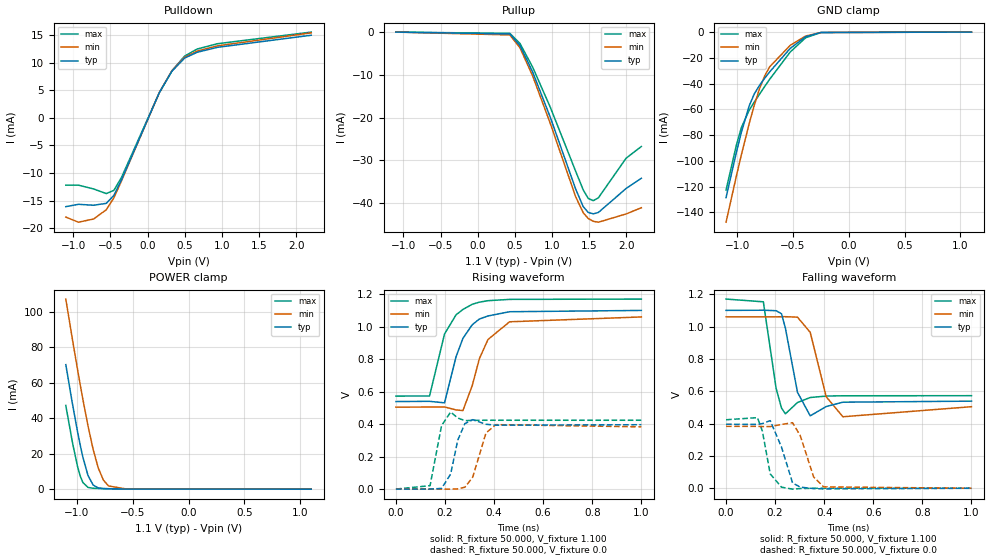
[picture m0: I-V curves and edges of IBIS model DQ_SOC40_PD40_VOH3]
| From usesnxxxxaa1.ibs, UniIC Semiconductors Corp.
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|   Model DQ_SOC40_PD40_VOH3
[Model] DQ_SOC40_PD40_VOH3
Model_type I/O
Polarity   Non-Inverting
Enable   Active-High
Vinl =  0.113V
Vinh =  0.253V
Vmeas =  0.183V
Rref =  50.000
Vref =  0.183V
C_comp   1.110pF   1.087pF   1.118pF
[Model Spec]
Vinh   0.253V   0.247V   0.265V
Vinl   0.113V   0.107V   0.125V
Vmeas   0.183V   NA   NA
Vref   0.183V   NA   NA
Rref   50.000   NA   NA
[Temperature Range]   25.000   0.125k   -40.000
[Voltage Range]   1.100V   1.060V   1.170V
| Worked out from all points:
|   slope of the pulldown table from 0 to 0.165 V, typ, clamps not added: 34.3 ohm
|   GND clamp passes 1 mA (typ) near -0.30 V on its own axis
|   POWER clamp passes 1 mA (typ) near -0.82 V on its own axis
|   rising waveform, R_fixture 50.000, V_fixture 1.100: 20-80 % time 76.9ps typ, 80.7ps min, 76.1ps max; typ from 0.539 V to 1.1 V
|   rising waveform, R_fixture 50.000, V_fixture 0.0: 20-80 % time 34.2ps typ, 42.2ps min, 26.6ps max; typ from 0 V to 0.396 V
|   falling waveform, R_fixture 50.000, V_fixture 1.100: 20-80 % time 39.5ps typ, 51.4ps min, 30.3ps max; typ from 1.1 V to 0.539 V
|   falling waveform, R_fixture 50.000, V_fixture 0.0: 20-80 % time 39.4ps typ, 48.3ps min, 31.2ps max; typ from 0.396 V to 0 V
[Pulldown]
|Voltage   I(typ)   I(min)   I(max)
-1.1V     -16.12mA   -18.01mA   -12.21mA
-930mV    -15.69mA   -18.94mA   -12.21mA
-726mV    -15.86mA   -18.36mA   -12.9mA
-556mV    -15.52mA   -16.68mA   -13.74mA
-454mV    -14.08mA   -14.53mA   -13.16mA
-352mV    -11.27mA   -11.46mA   -10.83mA
158mV     4.629mA    4.648mA    4.586mA
328mV     8.522mA    8.602mA    8.586mA
498mV     10.89mA    11.05mA    11.26mA
668mV     11.95mA    12.17mA    12.54mA
940mV     12.84mA    13.11mA    13.5mA
2.2V      15.04mA    15.47mA    15.61mA
[Pullup]
|Voltage   I(typ)   I(min)   I(max)
-1.1V     1nA        40.29nA    -1.059nA
432mV     -445.9uA   -664.3uA   -301.9uA
568mV     -3.14mA    -3.672mA   -2.666mA
738mV     -9.312mA   -10.23mA   -8.171mA
976mV     -19.93mA   -21.36mA   -17.58mA
1.316V    -36.64mA   -38.44mA   -32.48mA
1.418V    -40.78mA   -42.2mA    -36.86mA
1.486V    -42.14mA   -43.56mA   -38.87mA
1.554V    -42.47mA   -44.22mA   -39.39mA
1.622V    -42.15mA   -44.42mA   -38.73mA
1.996V    -36.53mA   -42.49mA   -29.45mA
2.2V      -34.15mA   -41.04mA   -26.73mA
[GND_clamp]
|Voltage   I(typ)   I(min)   I(max)
-1.1V     -128.5mA   -147.6mA   -122.6mA
-1.008V   -93.62mA   -112mA     -87.95mA
-962mV    -77.6mA    -95.05mA   -73.96mA
-893mV    -57.36mA   -71.21mA   -60.7mA
-847mV    -48.01mA   -56.81mA   -54.36mA
-801mV    -41.47mA   -44.23mA   -48.33mA
-755mV    -36.02mA   -34.19mA   -42.41mA
-709mV    -30.9mA    -26.94mA   -36.63mA
-525mV    -12.67mA   -10.3mA    -15.49mA
-387mV    -3.615mA   -3.065mA   -4.419mA
-249mV    -281uA     -330.6uA   -301.3uA
1.1V      0A         0A         0A
[POWER_clamp]
|Voltage   I(typ)   I(min)   I(max)
-1.1V     70.27mA    107.3mA    47.25mA
-1.039V   47.68mA    83.93mA    25.86mA
-993mV    31.88mA    66.94mA    12.35mA
-970mV    24.65mA    58.72mA    7.262mA
-947mV    18.06mA    50.74mA    3.761mA
-901mV    7.73mA     35.71mA    987.1uA
-855mV    2.348mA    22.46mA    514uA
-809mV    697.3uA    11.94mA    396.5uA
-763mV    321uA      5.097mA    322.7uA
-717mV    213.8uA    1.813mA    258.1uA
-556mV    65.24uA    79.15uA    81.64uA
1.1V      0A         0A         0A
[Ramp]
| variable   typ   min   max
dV/dt_r   0.238/34.205p   0.230/44.058p   0.254/26.879p
dV/dt_f   0.337/40.097p   0.333/51.984p   0.359/30.470p
R_load = 50.000
[Rising Waveform]
R_fixture= 50.000
V_fixture= 1.100
V_fixture_min= 1.060
V_fixture_max= 1.170
|time   V(typ)   V(min)   V(max)
0s        538.9mV    504.5mV    572.5mV
137ps     540.2mV    505.1mV    573.3mV
198ps     531mV      505.7mV    954.9mV
245ps     814.7mV    487.4mV    1.073V
273ps     928.1mV    483.5mV    1.106V
311ps     1.012V     637.3mV    1.138V
340ps     1.047V     802.9mV    1.151V
375ps     1.066V     920.7mV    1.16V
463ps     1.092V     1.03V      1.168V
1ns       1.1V       1.06V      1.17V
[Rising Waveform]
R_fixture= 50.000
V_fixture= 0.0
V_fixture_min= 0.0
V_fixture_max= 0.0
|time   V(typ)   V(min)   V(max)
0s        1.764uV    14.27uV    330.5nV
139ps     -39.12uV   2.016uV    20.91mV
186ps     4.2mV      18.06uV    391.2mV
223ps     92.51mV    -600.2uV   474.3mV
252ps     301.6mV    1.192mV    437.6mV
281ps     403.2mV    11.53mV    421.3mV
313ps     427.4mV    73.36mV    423.1mV
367ps     398.9mV    345.4mV    423.7mV
407ps     393.4mV    396.8mV    423.7mV
1ns       396.3mV    383.1mV    423.7mV
[Falling Waveform]
R_fixture= 50.000
V_fixture= 1.100
V_fixture_min= 1.060
V_fixture_max= 1.170
|time   V(typ)   V(min)   V(max)
0s        1.1V       1.06V      1.17V
152ps     1.101V     1.06V      1.153V
204ps     1.098V     1.06V      618.2mV
226ps     1.079V     1.061V     495.6mV
242ps     989.3mV    1.061V     460.5mV
291ps     593.7mV    1.058V     530.2mV
343ps     447.9mV    964.1mV    561.3mV
408ps     505.4mV    566.4mV    570.2mV
476ps     532.3mV    442.2mV    572mV
1ns       538.8mV    504.5mV    572.5mV
[Falling Waveform]
R_fixture= 50.000
V_fixture= 0.0
V_fixture_min= 0.0
V_fixture_max= 0.0
|time   V(typ)   V(min)   V(max)
0s        396.3mV    383.1mV    423.7mV
128ps     394.7mV    382.7mV    436.7mV
148ps     400.1mV    381.8mV    353.5mV
180ps     418.2mV    381.3mV    88.91mV
226ps     254.5mV    394.9mV    6.791mV
271ps     33.25mV    405.4mV    -5.525mV
302ps     7.059mV    326.9mV    -1.691mV
357ps     -2.039mV   69.62mV    -140.1uV
398ps     -3.841mV   8.587mV    -19.95uV
1ns       1.873uV    15.43uV    -4.527uV
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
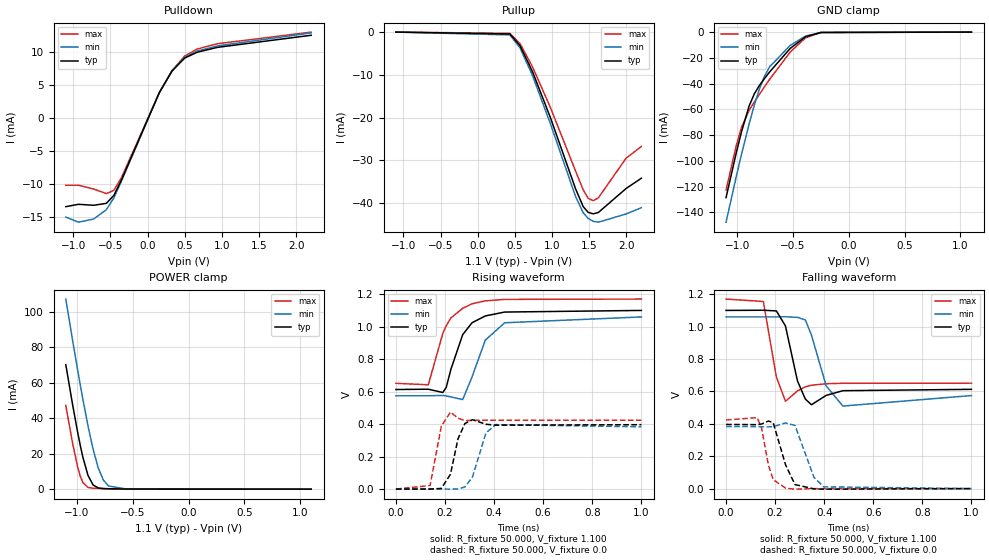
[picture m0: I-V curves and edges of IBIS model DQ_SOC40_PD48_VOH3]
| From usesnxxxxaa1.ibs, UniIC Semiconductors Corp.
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|   Model DQ_SOC40_PD48_VOH3
[Model] DQ_SOC40_PD48_VOH3
Model_type I/O
Polarity   Non-Inverting
Enable   Active-High
Vinl =  0.113V
Vinh =  0.253V
Vmeas =  0.183V
Rref =  50.000
Vref =  0.183V
C_comp   1.110pF   1.087pF   1.118pF
[Model Spec]
Vinh   0.253V   0.247V   0.265V
Vinl   0.113V   0.107V   0.125V
Vmeas   0.183V   NA   NA
Vref   0.183V   NA   NA
Rref   50.000   NA   NA
[Temperature Range]   25.000   0.125k   -40.000
[Voltage Range]   1.100V   1.060V   1.170V
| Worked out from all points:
|   slope of the pulldown table from 0 to 0.165 V, typ, clamps not added: 41.1 ohm
|   GND clamp passes 1 mA (typ) near -0.30 V on its own axis
|   POWER clamp passes 1 mA (typ) near -0.82 V on its own axis
|   rising waveform, R_fixture 50.000, V_fixture 1.100: 20-80 % time 76.2ps typ, 79.4ps min, 75.9ps max; typ from 0.613 V to 1.1 V
|   rising waveform, R_fixture 50.000, V_fixture 0.0: 20-80 % time 34.3ps typ, 43ps min, 26.7ps max; typ from 0 V to 0.396 V
|   falling waveform, R_fixture 50.000, V_fixture 1.100: 20-80 % time 40.3ps typ, 52.9ps min, 30.8ps max; typ from 1.1 V to 0.613 V
|   falling waveform, R_fixture 50.000, V_fixture 0.0: 20-80 % time 41.5ps typ, 49.8ps min, 33.7ps max; typ from 0.396 V to 0 V
[Pulldown]
|Voltage   I(typ)   I(min)   I(max)
-1.1V     -13.43mA   -15.01mA   -10.18mA
-930mV    -13.07mA   -15.78mA   -10.18mA
-726mV    -13.22mA   -15.3mA    -10.75mA
-556mV    -12.93mA   -13.9mA    -11.45mA
-454mV    -11.73mA   -12.11mA   -10.97mA
-352mV    -9.395mA   -9.553mA   -9.028mA
158mV     3.857mA    3.874mA    3.821mA
328mV     7.102mA    7.168mA    7.155mA
498mV     9.071mA    9.207mA    9.38mA
668mV     9.963mA    10.14mA    10.45mA
940mV     10.7mA     10.92mA    11.25mA
2.2V      12.53mA    12.89mA    13.01mA
[Pullup]
|Voltage   I(typ)   I(min)   I(max)
-1.1V     1nA        40.29nA    -1.059nA
432mV     -445.9uA   -664.3uA   -301.9uA
568mV     -3.14mA    -3.672mA   -2.666mA
738mV     -9.312mA   -10.23mA   -8.171mA
976mV     -19.93mA   -21.36mA   -17.58mA
1.316V    -36.64mA   -38.44mA   -32.48mA
1.418V    -40.78mA   -42.2mA    -36.86mA
1.486V    -42.14mA   -43.56mA   -38.87mA
1.554V    -42.47mA   -44.22mA   -39.39mA
1.622V    -42.15mA   -44.42mA   -38.73mA
1.996V    -36.53mA   -42.49mA   -29.45mA
2.2V      -34.15mA   -41.04mA   -26.73mA
[GND_clamp]
|Voltage   I(typ)   I(min)   I(max)
-1.1V     -128.5mA   -147.6mA   -122.6mA
-1.008V   -93.62mA   -112mA     -87.95mA
-962mV    -77.6mA    -95.05mA   -73.96mA
-893mV    -57.36mA   -71.21mA   -60.7mA
-847mV    -48.01mA   -56.81mA   -54.36mA
-801mV    -41.47mA   -44.23mA   -48.33mA
-755mV    -36.02mA   -34.19mA   -42.41mA
-709mV    -30.9mA    -26.94mA   -36.63mA
-525mV    -12.67mA   -10.3mA    -15.49mA
-387mV    -3.615mA   -3.065mA   -4.419mA
-249mV    -281uA     -330.6uA   -301.3uA
1.1V      0A         0A         0A
[POWER_clamp]
|Voltage   I(typ)   I(min)   I(max)
-1.1V     70.27mA    107.3mA    47.25mA
-1.039V   47.68mA    83.93mA    25.86mA
-993mV    31.88mA    66.94mA    12.35mA
-970mV    24.65mA    58.72mA    7.262mA
-947mV    18.06mA    50.74mA    3.761mA
-901mV    7.73mA     35.71mA    987.1uA
-855mV    2.348mA    22.46mA    514uA
-809mV    697.3uA    11.94mA    396.5uA
-763mV    321uA      5.097mA    322.7uA
-717mV    213.8uA    1.813mA    258.1uA
-556mV    65.24uA    79.15uA    81.64uA
1.1V      0A         0A         0A
[Ramp]
| variable   typ   min   max
dV/dt_r   0.238/34.731p   0.230/44.705p   0.254/27.114p
dV/dt_f   0.292/40.843p   0.291/53.764p   0.311/30.978p
R_load = 50.000
[Rising Waveform]
R_fixture= 50.000
V_fixture= 1.100
V_fixture_min= 1.060
V_fixture_max= 1.170
|time   V(typ)   V(min)   V(max)
0s        613mV      574.4mV    651mV
132ps     614.8mV    574.8mV    642.1mV
191ps     594.6mV    576.2mV    958.6mV
205ps     626.4mV    574mV      1.006V
224ps     737.4mV    567.2mV    1.054V
272ps     950.6mV    551mV      1.113V
310ps     1.024V     689.5mV    1.141V
364ps     1.066V     916.8mV    1.159V
443ps     1.09V      1.024V     1.168V
1ns       1.1V       1.06V      1.17V
[Rising Waveform]
R_fixture= 50.000
V_fixture= 0.0
V_fixture_min= 0.0
V_fixture_max= 0.0
|time   V(typ)   V(min)   V(max)
0s        1.965uV    15.9uV     367.9nV
139ps     -74.6uV    22.91uV    21.61mV
185ps     3.776mV    40.2uV     386.4mV
222ps     90.46mV    -769.1uV   473.9mV
253ps     309.5mV    1.09mV     436.6mV
281ps     403.5mV    12.65mV    421.3mV
312ps     427mV      74.25mV    423.1mV
367ps     398.8mV    346.4mV    423.7mV
407ps     393.4mV    396.8mV    423.7mV
1ns       396.3mV    383.1mV    423.7mV
[Falling Waveform]
R_fixture= 50.000
V_fixture= 1.100
V_fixture_min= 1.060
V_fixture_max= 1.170
|time   V(typ)   V(min)   V(max)
0s        1.1V       1.06V      1.17V
152ps     1.101V     1.06V      1.155V
205ps     1.097V     1.06V      688.9mV
242ps     1.004V     1.061V     539.3mV
291ps     664.7mV    1.057V     603.3mV
323ps     553.1mV    1.041V     628.1mV
348ps     517.7mV    947.7mV    637.9mV
408ps     575.5mV    633.9mV    647.5mV
476ps     604.4mV    509.6mV    650.2mV
1ns       612.9mV    574.4mV    651mV
[Falling Waveform]
R_fixture= 50.000
V_fixture= 0.0
V_fixture_min= 0.0
V_fixture_max= 0.0
|time   V(typ)   V(min)   V(max)
0s        396.3mV    383.1mV    423.7mV
127ps     394.7mV    382.7mV    438.3mV
145ps     398.8mV    381.9mV    371.6mV
173ps     417.2mV    381.1mV    142.1mV
192ps     406.9mV    382.4mV    55.76mV
243ps     144.6mV    405.5mV    2.177mV
281ps     24.82mV    389.6mV    -3.372mV
358ps     -1.482mV   70.24mV    -149.3uV
398ps     -3.36mV    10.99mV    -26.6uV
1ns       3.815uV    17.59uV    -4.001uV
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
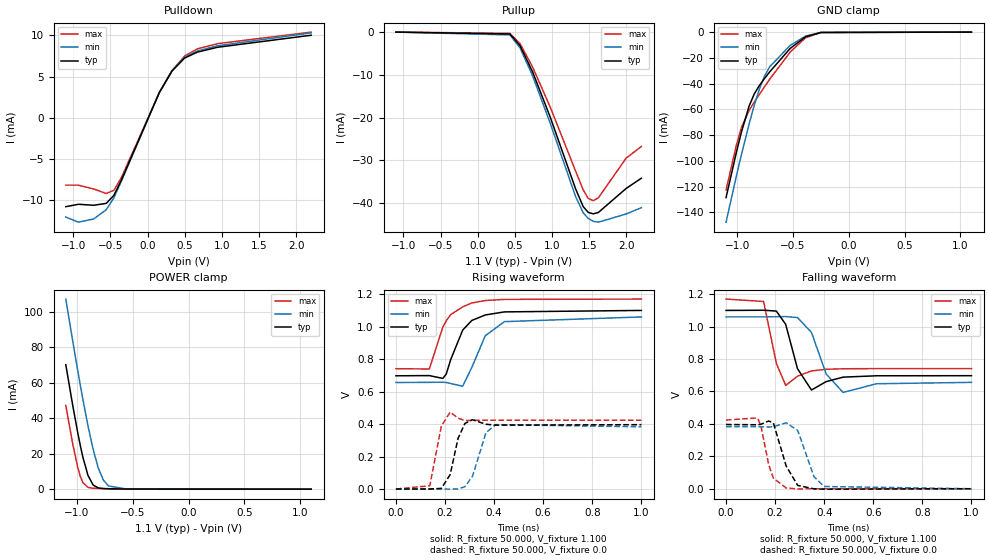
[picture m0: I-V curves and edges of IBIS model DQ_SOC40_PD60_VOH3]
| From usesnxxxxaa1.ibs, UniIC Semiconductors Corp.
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|   Model DQ_SOC40_PD60_VOH3
[Model] DQ_SOC40_PD60_VOH3
Model_type I/O
Polarity   Non-Inverting
Enable   Active-High
Vinl =  0.113V
Vinh =  0.253V
Vmeas =  0.183V
Rref =  50.000
Vref =  0.183V
C_comp   1.110pF   1.087pF   1.118pF
[Model Spec]
Vinh   0.253V   0.247V   0.265V
Vinl   0.113V   0.107V   0.125V
Vmeas   0.183V   NA   NA
Vref   0.183V   NA   NA
Rref   50.000   NA   NA
[Temperature Range]   25.000   0.125k   -40.000
[Voltage Range]   1.100V   1.060V   1.170V
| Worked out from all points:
|   slope of the pulldown table from 0 to 0.165 V, typ, clamps not added: 51.4 ohm
|   GND clamp passes 1 mA (typ) near -0.30 V on its own axis
|   POWER clamp passes 1 mA (typ) near -0.82 V on its own axis
|   rising waveform, R_fixture 50.000, V_fixture 1.100: 20-80 % time 75.4ps typ, 77.9ps min, 75.4ps max; typ from 0.697 V to 1.1 V
|   rising waveform, R_fixture 50.000, V_fixture 0.0: 20-80 % time 34.8ps typ, 43.7ps min, 26.8ps max; typ from 0 V to 0.396 V
|   falling waveform, R_fixture 50.000, V_fixture 1.100: 20-80 % time 40.8ps typ, 54.1ps min, 31.1ps max; typ from 1.1 V to 0.697 V
|   falling waveform, R_fixture 50.000, V_fixture 0.0: 20-80 % time 44ps typ, 51.6ps min, 36.8ps max; typ from 0.396 V to 0 V
[Pulldown]
|Voltage   I(typ)   I(min)   I(max)
-1.1V     -10.75mA   -12.01mA   -8.142mA
-930mV    -10.46mA   -12.63mA   -8.143mA
-726mV    -10.58mA   -12.24mA   -8.599mA
-556mV    -10.35mA   -11.12mA   -9.157mA
-454mV    -9.387mA   -9.688mA   -8.773mA
-352mV    -7.516mA   -7.642mA   -7.222mA
158mV     3.086mA    3.099mA    3.057mA
328mV     5.681mA    5.734mA    5.724mA
498mV     7.257mA    7.365mA    7.504mA
668mV     7.97mA     8.112mA    8.363mA
940mV     8.561mA    8.737mA    9mA
2.2V      10.02mA    10.31mA    10.4mA
[Pullup]
|Voltage   I(typ)   I(min)   I(max)
-1.1V     1nA        40.29nA    -1.059nA
432mV     -445.9uA   -664.3uA   -301.9uA
568mV     -3.14mA    -3.672mA   -2.666mA
738mV     -9.312mA   -10.23mA   -8.171mA
976mV     -19.93mA   -21.36mA   -17.58mA
1.316V    -36.64mA   -38.44mA   -32.48mA
1.418V    -40.78mA   -42.2mA    -36.86mA
1.486V    -42.14mA   -43.56mA   -38.87mA
1.554V    -42.47mA   -44.22mA   -39.39mA
1.622V    -42.15mA   -44.42mA   -38.73mA
1.996V    -36.53mA   -42.49mA   -29.45mA
2.2V      -34.15mA   -41.04mA   -26.73mA
[GND_clamp]
|Voltage   I(typ)   I(min)   I(max)
-1.1V     -128.5mA   -147.6mA   -122.6mA
-1.008V   -93.62mA   -112mA     -87.95mA
-962mV    -77.6mA    -95.05mA   -73.96mA
-893mV    -57.36mA   -71.21mA   -60.7mA
-847mV    -48.01mA   -56.81mA   -54.36mA
-801mV    -41.47mA   -44.23mA   -48.33mA
-755mV    -36.02mA   -34.19mA   -42.41mA
-709mV    -30.9mA    -26.94mA   -36.63mA
-525mV    -12.67mA   -10.3mA    -15.49mA
-387mV    -3.615mA   -3.065mA   -4.419mA
-249mV    -281uA     -330.6uA   -301.3uA
1.1V      0A         0A         0A
[POWER_clamp]
|Voltage   I(typ)   I(min)   I(max)
-1.1V     70.27mA    107.3mA    47.25mA
-1.039V   47.68mA    83.93mA    25.86mA
-993mV    31.88mA    66.94mA    12.35mA
-970mV    24.65mA    58.72mA    7.262mA
-947mV    18.06mA    50.74mA    3.761mA
-901mV    7.73mA     35.71mA    987.1uA
-855mV    2.348mA    22.46mA    514uA
-809mV    697.3uA    11.94mA    396.5uA
-763mV    321uA      5.097mA    322.7uA
-717mV    213.8uA    1.813mA    258.1uA
-556mV    65.24uA    79.15uA    81.64uA
1.1V      0A         0A         0A
[Ramp]
| variable   typ   min   max
dV/dt_r   0.238/35.057p   0.230/45.290p   0.254/27.177p
dV/dt_f   0.242/41.314p   0.242/55.001p   0.257/31.296p
R_load = 50.000
[Rising Waveform]
R_fixture= 50.000
V_fixture= 1.100
V_fixture_min= 1.060
V_fixture_max= 1.170
|time   V(typ)   V(min)   V(max)
0s        697.4mV    656.2mV    741mV
136ps     698.6mV    656.9mV    739.3mV
191ps     681.3mV    657.9mV    996.8mV
205ps     708mV      655.9mV    1.036V
223ps     796.6mV    650mV      1.074V
272ps     978.6mV    633.2mV    1.122V
309ps     1.038V     748.6mV    1.146V
364ps     1.072V     943.9mV    1.161V
442ps     1.091V     1.031V     1.168V
1ns       1.1V       1.06V      1.17V
[Rising Waveform]
R_fixture= 50.000
V_fixture= 0.0
V_fixture_min= 0.0
V_fixture_max= 0.0
|time   V(typ)   V(min)   V(max)
0s        2.218uV    17.94uV    414.7nV
138ps     -92.5uV    41.88uV    20.05mV
185ps     3.849mV    32.41uV    387.4mV
221ps     88.62mV    -949.7uV   473.5mV
253ps     311mV      857.9uV    436.7mV
281ps     403.7mV    14mV       421.3mV
312ps     426.9mV    78.79mV    423.1mV
367ps     398.7mV    347.3mV    423.7mV
407ps     393.4mV    396.7mV    423.7mV
1ns       396.3mV    383.1mV    423.7mV
[Falling Waveform]
R_fixture= 50.000
V_fixture= 1.100
V_fixture_min= 1.060
V_fixture_max= 1.170
|time   V(typ)   V(min)   V(max)
0s        1.1V       1.06V      1.17V
153ps     1.101V     1.06V      1.155V
205ps     1.096V     1.061V     773.3mV
243ps     1.014V     1.062V     637.3mV
291ps     741.1mV    1.056V     693.9mV
348ps     608.9mV    964.3mV    726.8mV
408ps     660.8mV    707.7mV    736.9mV
477ps     688.4mV    594mV      740mV
613ps     696.8mV    647.6mV    741mV
1ns       697.4mV    656.2mV    741mV
[Falling Waveform]
R_fixture= 50.000
V_fixture= 0.0
V_fixture_min= 0.0
V_fixture_max= 0.0
|time   V(typ)   V(min)   V(max)
0s        396.3mV    383.1mV    423.7mV
128ps     394.7mV    382.7mV    436.8mV
142ps     397.5mV    382mV      388.8mV
174ps     418mV      381.1mV    146.9mV
193ps     404.9mV    382.6mV    64.65mV
245ps     140.1mV    406.6mV    4.713mV
292ps     20.39mV    359.8mV    -1.251mV
358ps     -395uV     75.54mV    -107.1uV
399ps     -2.61mV    13.92mV    -21.3uV
1ns       4.28uV     19.82uV    -4.941uV
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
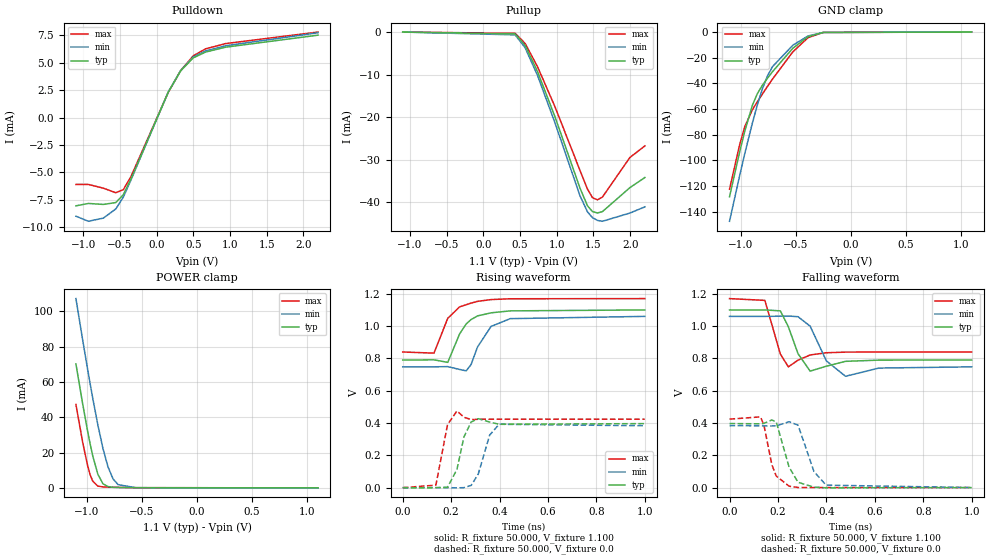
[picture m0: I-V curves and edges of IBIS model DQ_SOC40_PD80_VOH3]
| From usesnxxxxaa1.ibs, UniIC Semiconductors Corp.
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|   Model DQ_SOC40_PD80_VOH3
[Model] DQ_SOC40_PD80_VOH3
Model_type I/O
Polarity   Non-Inverting
Enable   Active-High
Vinl =  0.113V
Vinh =  0.253V
Vmeas =  0.183V
Rref =  50.000
Vref =  0.183V
C_comp   1.110pF   1.087pF   1.118pF
[Model Spec]
Vinh   0.253V   0.247V   0.265V
Vinl   0.113V   0.107V   0.125V
Vmeas   0.183V   NA   NA
Vref   0.183V   NA   NA
Rref   50.000   NA   NA
[Temperature Range]   25.000   0.125k   -40.000
[Voltage Range]   1.100V   1.060V   1.170V
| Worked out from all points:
|   slope of the pulldown table from 0 to 0.165 V, typ, clamps not added: 68.6 ohm
|   GND clamp passes 1 mA (typ) near -0.30 V on its own axis
|   POWER clamp passes 1 mA (typ) near -0.82 V on its own axis
|   rising waveform, R_fixture 50.000, V_fixture 1.100: 20-80 % time 70.4ps typ, 70.3ps min, 71.4ps max; typ from 0.79 V to 1.1 V
|   rising waveform, R_fixture 50.000, V_fixture 0.0: 20-80 % time 34.7ps typ, 44.4ps min, 26.7ps max; typ from 0 V to 0.396 V
|   falling waveform, R_fixture 50.000, V_fixture 1.100: 20-80 % time 43ps typ, 55.7ps min, 32.9ps max; typ from 1.1 V to 0.79 V
|   falling waveform, R_fixture 50.000, V_fixture 0.0: 20-80 % time 44.3ps typ, 50.6ps min, 39.7ps max; typ from 0.396 V to 0 V
[Pulldown]
|Voltage   I(typ)   I(min)   I(max)
-1.1V     -8.06mA    -9.005mA   -6.106mA
-930mV    -7.843mA   -9.47mA    -6.107mA
-726mV    -7.932mA   -9.181mA   -6.449mA
-556mV    -7.761mA   -8.341mA   -6.868mA
-454mV    -7.04mA    -7.266mA   -6.58mA
-352mV    -5.637mA   -5.732mA   -5.417mA
158mV     2.314mA    2.324mA    2.293mA
328mV     4.261mA    4.301mA    4.293mA
498mV     5.443mA    5.524mA    5.628mA
668mV     5.978mA    6.084mA    6.272mA
940mV     6.421mA    6.553mA    6.75mA
2.2V      7.518mA    7.735mA    7.803mA
[Pullup]
|Voltage   I(typ)   I(min)   I(max)
-1.1V     1nA        40.29nA    -1.059nA
432mV     -445.9uA   -664.3uA   -301.9uA
568mV     -3.14mA    -3.672mA   -2.666mA
738mV     -9.312mA   -10.23mA   -8.171mA
976mV     -19.93mA   -21.36mA   -17.58mA
1.316V    -36.64mA   -38.44mA   -32.48mA
1.418V    -40.78mA   -42.2mA    -36.86mA
1.486V    -42.14mA   -43.56mA   -38.87mA
1.554V    -42.47mA   -44.22mA   -39.39mA
1.622V    -42.15mA   -44.42mA   -38.73mA
1.996V    -36.53mA   -42.49mA   -29.45mA
2.2V      -34.15mA   -41.04mA   -26.73mA
[GND_clamp]
|Voltage   I(typ)   I(min)   I(max)
-1.1V     -128.5mA   -147.6mA   -122.6mA
-1.008V   -93.62mA   -112mA     -87.95mA
-962mV    -77.6mA    -95.05mA   -73.96mA
-893mV    -57.36mA   -71.21mA   -60.7mA
-847mV    -48.01mA   -56.81mA   -54.36mA
-801mV    -41.47mA   -44.23mA   -48.33mA
-755mV    -36.02mA   -34.19mA   -42.41mA
-709mV    -30.9mA    -26.94mA   -36.63mA
-525mV    -12.67mA   -10.3mA    -15.49mA
-387mV    -3.615mA   -3.065mA   -4.419mA
-249mV    -281uA     -330.6uA   -301.3uA
1.1V      0A         0A         0A
[POWER_clamp]
|Voltage   I(typ)   I(min)   I(max)
-1.1V     70.27mA    107.3mA    47.25mA
-1.039V   47.68mA    83.93mA    25.86mA
-993mV    31.88mA    66.94mA    12.35mA
-970mV    24.65mA    58.72mA    7.262mA
-947mV    18.06mA    50.74mA    3.761mA
-901mV    7.73mA     35.71mA    987.1uA
-855mV    2.348mA    22.46mA    514uA
-809mV    697.3uA    11.94mA    396.5uA
-763mV    321uA      5.097mA    322.7uA
-717mV    213.8uA    1.813mA    258.1uA
-556mV    65.24uA    79.15uA    81.64uA
1.1V      0A         0A         0A
[Ramp]
| variable   typ   min   max
dV/dt_r   0.238/35.308p   0.230/45.309p   0.254/27.184p
dV/dt_f   0.186/43.222p   0.187/56.773p   0.198/32.941p
R_load = 50.000
[Rising Waveform]
R_fixture= 50.000
V_fixture= 1.100
V_fixture_min= 1.060
V_fixture_max= 1.170
|time   V(typ)   V(min)   V(max)
0s        789.7mV    747.6mV    839.6mV
129ps     791.1mV    747.9mV    832.6mV
186ps     775.4mV    749.1mV    1.048V
235ps     951.6mV    731.5mV    1.119V
262ps     1.013V     723mV      1.132V
282ps     1.04V      761mV      1.142V
309ps     1.063V     870.9mV    1.153V
365ps     1.082V     997.9mV    1.164V
444ps     1.094V     1.046V     1.169V
1ns       1.1V       1.06V      1.17V
[Rising Waveform]
R_fixture= 50.000
V_fixture= 0.0
V_fixture_min= 0.0
V_fixture_max= 0.0
|time   V(typ)   V(min)   V(max)
0s        2.545uV    20.59uV    475.2nV
137ps     21.39uV    51.46uV    15.68mV
185ps     2.658mV    111.2uV    389.7mV
224ps     113.1mV    -1.052mV   474.7mV
253ps     315mV      144.2uV    435.7mV
283ps     406.9mV    14.18mV    421.3mV
312ps     426.9mV    84.52mV    423.1mV
359ps     406.1mV    325.4mV    423.7mV
398ps     392.5mV    392.3mV    423.7mV
1ns       396.3mV    383.1mV    423.7mV
[Falling Waveform]
R_fixture= 50.000
V_fixture= 1.100
V_fixture_min= 1.060
V_fixture_max= 1.170
|time   V(typ)   V(min)   V(max)
0s        1.1V       1.06V      1.17V
146ps     1.1V       1.06V      1.159V
210ps     1.094V     1.061V     826.6mV
243ps     995.8mV    1.062V     747.4mV
283ps     828.9mV    1.058V     789mV
333ps     721mV      999.4mV    821.1mV
400ps     751.5mV    784.5mV    834.7mV
479ps     781.5mV    689.1mV    838.6mV
617ps     789.2mV    739.9mV    839.6mV
1ns       789.7mV    747.5mV    839.6mV
[Falling Waveform]
R_fixture= 50.000
V_fixture= 0.0
V_fixture_min= 0.0
V_fixture_max= 0.0
|time   V(typ)   V(min)   V(max)
0s        396.3mV    383.1mV    423.7mV
128ps     394.7mV    382.7mV    437.7mV
142ps     397.4mV    382mV      387.9mV
175ps     418.7mV    381.1mV    140.6mV
193ps     406.2mV    382.5mV    71.6mV
246ps     126.9mV    407.3mV    8.571mV
283ps     32.66mV    386.9mV    459.6uV
349ps     2.59mV     98.23mV    92.22uV
399ps     -1.679mV   14.9mV     27.07uV
1ns       5.025uV    22.73uV    -5.313uV
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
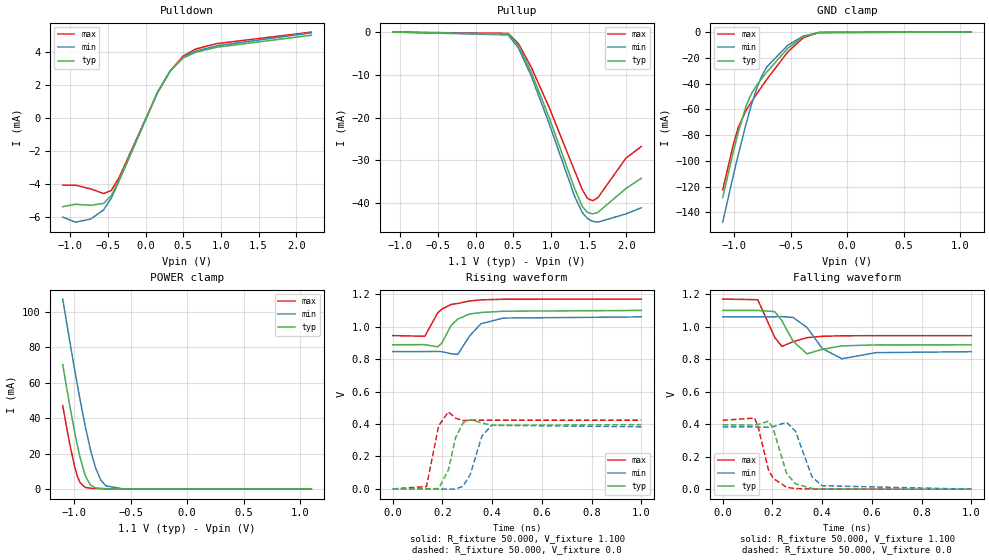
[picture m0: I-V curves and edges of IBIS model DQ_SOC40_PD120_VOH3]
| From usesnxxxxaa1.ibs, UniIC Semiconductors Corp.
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|   Model DQ_SOC40_PD120_VOH3
[Model] DQ_SOC40_PD120_VOH3
Model_type I/O
Polarity   Non-Inverting
Enable   Active-High
Vinl =  0.113V
Vinh =  0.253V
Vmeas =  0.183V
Rref =  50.000
Vref =  0.183V
C_comp   1.110pF   1.087pF   1.118pF
[Model Spec]
Vinh   0.253V   0.247V   0.265V
Vinl   0.113V   0.107V   0.125V
Vmeas   0.183V   NA   NA
Vref   0.183V   NA   NA
Rref   50.000   NA   NA
[Temperature Range]   25.000   0.125k   -40.000
[Voltage Range]   1.100V   1.060V   1.170V
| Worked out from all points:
|   slope of the pulldown table from 0 to 0.165 V, typ, clamps not added: 103 ohm
|   GND clamp passes 1 mA (typ) near -0.30 V on its own axis
|   POWER clamp passes 1 mA (typ) near -0.82 V on its own axis
|   rising waveform, R_fixture 50.000, V_fixture 1.100: 20-80 % time 65.9ps typ, 63.5ps min, 68.5ps max; typ from 0.888 V to 1.1 V
|   rising waveform, R_fixture 50.000, V_fixture 0.0: 20-80 % time 35.2ps typ, 45.4ps min, 26.9ps max; typ from 0 V to 0.396 V
|   falling waveform, R_fixture 50.000, V_fixture 1.100: 20-80 % time 43.5ps typ, 56.9ps min, 33.2ps max; typ from 1.1 V to 0.888 V
|   falling waveform, R_fixture 50.000, V_fixture 0.0: 20-80 % time 49ps typ, 53.8ps min, 46ps max; typ from 0.396 V to 0 V
[Pulldown]
|Voltage   I(typ)   I(min)   I(max)
-1.1V     -5.373mA   -6.003mA   -4.071mA
-930mV    -5.229mA   -6.314mA   -4.072mA
-726mV    -5.288mA   -6.12mA    -4.3mA
-556mV    -5.174mA   -5.561mA   -4.579mA
-454mV    -4.694mA   -4.844mA   -4.386mA
-352mV    -3.758mA   -3.821mA   -3.611mA
158mV     1.543mA    1.549mA    1.529mA
328mV     2.841mA    2.867mA    2.862mA
498mV     3.628mA    3.683mA    3.752mA
668mV     3.985mA    4.056mA    4.181mA
940mV     4.28mA     4.369mA    4.5mA
2.2V      5.012mA    5.157mA    5.202mA
[Pullup]
|Voltage   I(typ)   I(min)   I(max)
-1.1V     1nA        40.29nA    -1.059nA
432mV     -445.9uA   -664.3uA   -301.9uA
568mV     -3.14mA    -3.672mA   -2.666mA
738mV     -9.312mA   -10.23mA   -8.171mA
976mV     -19.93mA   -21.36mA   -17.58mA
1.316V    -36.64mA   -38.44mA   -32.48mA
1.418V    -40.78mA   -42.2mA    -36.86mA
1.486V    -42.14mA   -43.56mA   -38.87mA
1.554V    -42.47mA   -44.22mA   -39.39mA
1.622V    -42.15mA   -44.42mA   -38.73mA
1.996V    -36.53mA   -42.49mA   -29.45mA
2.2V      -34.15mA   -41.04mA   -26.73mA
[GND_clamp]
|Voltage   I(typ)   I(min)   I(max)
-1.1V     -128.5mA   -147.6mA   -122.6mA
-1.008V   -93.62mA   -112mA     -87.95mA
-962mV    -77.6mA    -95.05mA   -73.96mA
-893mV    -57.36mA   -71.21mA   -60.7mA
-847mV    -48.01mA   -56.81mA   -54.36mA
-801mV    -41.47mA   -44.23mA   -48.33mA
-755mV    -36.02mA   -34.19mA   -42.41mA
-709mV    -30.9mA    -26.94mA   -36.63mA
-525mV    -12.67mA   -10.3mA    -15.49mA
-387mV    -3.615mA   -3.065mA   -4.419mA
-249mV    -281uA     -330.6uA   -301.3uA
1.1V      0A         0A         0A
[POWER_clamp]
|Voltage   I(typ)   I(min)   I(max)
-1.1V     70.27mA    107.3mA    47.25mA
-1.039V   47.68mA    83.93mA    25.86mA
-993mV    31.88mA    66.94mA    12.35mA
-970mV    24.65mA    58.72mA    7.262mA
-947mV    18.06mA    50.74mA    3.761mA
-901mV    7.73mA     35.71mA    987.1uA
-855mV    2.348mA    22.46mA    514uA
-809mV    697.3uA    11.94mA    396.5uA
-763mV    321uA      5.097mA    322.7uA
-717mV    213.8uA    1.813mA    258.1uA
-556mV    65.24uA    79.15uA    81.64uA
1.1V      0A         0A         0A
[Ramp]
| variable   typ   min   max
dV/dt_r   0.238/36.048p   0.230/46.073p   0.254/27.536p
dV/dt_f   0.127/43.850p   0.128/57.564p   0.135/33.292p
R_load = 50.000
[Rising Waveform]
R_fixture= 50.000
V_fixture= 1.100
V_fixture_min= 1.060
V_fixture_max= 1.170
|time   V(typ)   V(min)   V(max)
0s        888.3mV    846.1mV    944.8mV
129ps     889.2mV    846.4mV    940.9mV
181ps     875.6mV    847.3mV    1.085V
198ps     899.6mV    845.6mV    1.108V
235ps     1.008V     833.3mV    1.137V
262ps     1.047V     829.3mV    1.143V
309ps     1.078V     942.5mV    1.158V
355ps     1.087V     1.018V     1.165V
445ps     1.095V     1.053V     1.169V
1ns       1.1V       1.06V      1.17V
[Rising Waveform]
R_fixture= 50.000
V_fixture= 0.0
V_fixture_min= 0.0
V_fixture_max= 0.0
|time   V(typ)   V(min)   V(max)
0s        2.986uV    24.15uV    556.4nV
136ps     4.467uV    74.9uV     14.95mV
185ps     2.796mV    109.4uV    390.1mV
224ps     117.6mV    -1.347mV   474.7mV
253ps     316.2mV    -263.4uV   435.8mV
283ps     406.9mV    16.24mV    421.3mV
312ps     426.9mV    89.99mV    423.1mV
359ps     406mV      326.3mV    423.7mV
398ps     392.5mV    392.2mV    423.7mV
1ns       396.3mV    383.1mV    423.7mV
[Falling Waveform]
R_fixture= 50.000
V_fixture= 1.100
V_fixture_min= 1.060
V_fixture_max= 1.170
|time   V(typ)   V(min)   V(max)
0s        1.1V       1.06V      1.17V
141ps     1.1V       1.06V      1.166V
209ps     1.093V     1.061V     935mV
238ps     1.037V     1.062V     878.4mV
283ps     910.7mV    1.057V     907.6mV
339ps     833mV      995.2mV    932.3mV
400ps     860.3mV    866.6mV    940.9mV
479ps     882mV      802.6mV    944mV
617ps     887.8mV    840.3mV    944.7mV
1ns       888.3mV    846.1mV    944.8mV
[Falling Waveform]
R_fixture= 50.000
V_fixture= 0.0
V_fixture_min= 0.0
V_fixture_max= 0.0
|time   V(typ)   V(min)   V(max)
0s        396.3mV    383.1mV    423.7mV
128ps     394.7mV    382.7mV    437.6mV
142ps     397.5mV    382mV      386.8mV
184ps     418.3mV    381.4mV    119.4mV
203ps     373.4mV    384.9mV    66.53mV
257ps     96.94mV    411.4mV    11.35mV
293ps     32.82mV    355.9mV    3.762mV
359ps     4.085mV    76.31mV    736.7uV
399ps     96.03uV    21.21mV    271.4uV
1ns       62.55nV    26.72uV    -6.107uV
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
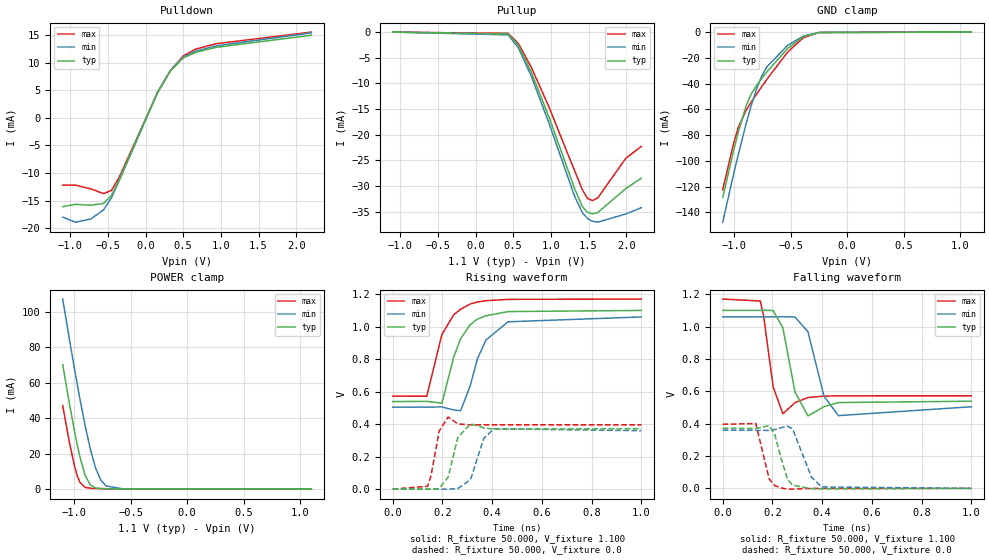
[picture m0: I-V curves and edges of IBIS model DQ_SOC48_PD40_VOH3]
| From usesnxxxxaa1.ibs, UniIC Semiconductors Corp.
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|   Model DQ_SOC48_PD40_VOH3
[Model] DQ_SOC48_PD40_VOH3
Model_type I/O
Polarity   Non-Inverting
Enable   Active-High
Vinl =  0.113V
Vinh =  0.253V
Vmeas =  0.183V
Rref =  50.000
Vref =  0.183V
C_comp   1.110pF   1.087pF   1.118pF
[Model Spec]
Vinh   0.253V   0.247V   0.265V
Vinl   0.113V   0.107V   0.125V
Vmeas   0.183V   NA   NA
Vref   0.183V   NA   NA
Rref   50.000   NA   NA
[Temperature Range]   25.000   0.125k   -40.000
[Voltage Range]   1.100V   1.060V   1.170V
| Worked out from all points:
|   slope of the pulldown table from 0 to 0.165 V, typ, clamps not added: 34.3 ohm
|   GND clamp passes 1 mA (typ) near -0.30 V on its own axis
|   POWER clamp passes 1 mA (typ) near -0.82 V on its own axis
|   rising waveform, R_fixture 50.000, V_fixture 1.100: 20-80 % time 77ps typ, 81.1ps min, 76.1ps max; typ from 0.539 V to 1.1 V
|   rising waveform, R_fixture 50.000, V_fixture 0.0: 20-80 % time 34.7ps typ, 43.2ps min, 27ps max; typ from 0 V to 0.372 V
|   falling waveform, R_fixture 50.000, V_fixture 1.100: 20-80 % time 39.3ps typ, 51ps min, 30.3ps max; typ from 1.1 V to 0.539 V
|   falling waveform, R_fixture 50.000, V_fixture 0.0: 20-80 % time 38.9ps typ, 47.7ps min, 30.9ps max; typ from 0.372 V to 0 V
[Pulldown]
|Voltage   I(typ)   I(min)   I(max)
-1.1V     -16.12mA   -18.01mA   -12.21mA
-930mV    -15.69mA   -18.94mA   -12.21mA
-726mV    -15.86mA   -18.36mA   -12.9mA
-556mV    -15.52mA   -16.68mA   -13.74mA
-454mV    -14.08mA   -14.53mA   -13.16mA
-352mV    -11.27mA   -11.46mA   -10.83mA
158mV     4.629mA    4.648mA    4.586mA
328mV     8.522mA    8.602mA    8.586mA
498mV     10.89mA    11.05mA    11.26mA
668mV     11.95mA    12.17mA    12.54mA
940mV     12.84mA    13.11mA    13.5mA
2.2V      15.04mA    15.47mA    15.61mA
[Pullup]
|Voltage   I(typ)   I(min)   I(max)
-1.1V     1nA        30.06nA    -1.059nA
432mV     -371.6uA   -553.6uA   -251.6uA
568mV     -2.617mA   -3.06mA    -2.222mA
738mV     -7.76mA    -8.529mA   -6.809mA
976mV     -16.61mA   -17.8mA    -14.65mA
1.316V    -30.54mA   -32.03mA   -27.06mA
1.418V    -33.98mA   -35.17mA   -30.72mA
1.486V    -35.12mA   -36.3mA    -32.39mA
1.554V    -35.39mA   -36.85mA   -32.82mA
1.622V    -35.13mA   -37.02mA   -32.28mA
1.996V    -30.44mA   -35.41mA   -24.54mA
2.2V      -28.46mA   -34.2mA    -22.27mA
[GND_clamp]
|Voltage   I(typ)   I(min)   I(max)
-1.1V     -128.5mA   -147.6mA   -122.6mA
-1.008V   -93.62mA   -112mA     -87.95mA
-962mV    -77.6mA    -95.05mA   -73.96mA
-893mV    -57.36mA   -71.21mA   -60.7mA
-847mV    -48.01mA   -56.81mA   -54.36mA
-801mV    -41.47mA   -44.23mA   -48.33mA
-755mV    -36.02mA   -34.19mA   -42.41mA
-709mV    -30.9mA    -26.94mA   -36.63mA
-525mV    -12.67mA   -10.3mA    -15.49mA
-387mV    -3.615mA   -3.065mA   -4.419mA
-249mV    -281uA     -330.6uA   -301.3uA
1.1V      0A         0A         0A
[POWER_clamp]
|Voltage   I(typ)   I(min)   I(max)
-1.1V     70.27mA    107.3mA    47.25mA
-1.039V   47.68mA    83.93mA    25.86mA
-993mV    31.88mA    66.94mA    12.35mA
-970mV    24.65mA    58.72mA    7.262mA
-947mV    18.06mA    50.74mA    3.761mA
-901mV    7.73mA     35.71mA    987.1uA
-855mV    2.348mA    22.46mA    514uA
-809mV    697.3uA    11.94mA    396.5uA
-763mV    321uA      5.097mA    322.7uA
-717mV    213.8uA    1.813mA    258.1uA
-556mV    65.24uA    79.15uA    81.64uA
1.1V      0A         0A         0A
[Ramp]
| variable   typ   min   max
dV/dt_r   0.223/34.718p   0.216/44.081p   0.238/27.242p
dV/dt_f   0.337/39.960p   0.333/51.746p   0.359/30.253p
R_load = 50.000
[Rising Waveform]
R_fixture= 50.000
V_fixture= 1.100
V_fixture_min= 1.060
V_fixture_max= 1.170
|time   V(typ)   V(min)   V(max)
0s        538.9mV    504.5mV    572.5mV
137ps     540.2mV    505.1mV    571.6mV
198ps     529.1mV    505.7mV    952.3mV
245ps     810.4mV    487.6mV    1.073V
273ps     925.5mV    482.4mV    1.107V
311ps     1.011V     632.5mV    1.139V
341ps     1.047V     802.7mV    1.152V
375ps     1.067V     917.9mV    1.16V
464ps     1.093V     1.03V      1.168V
1ns       1.1V       1.06V      1.17V
[Rising Waveform]
R_fixture= 50.000
V_fixture= 0.0
V_fixture_min= 0.0
V_fixture_max= 0.0
|time   V(typ)   V(min)   V(max)
0s        1.764uV    14.27uV    330.5nV
140ps     2.535uV    -6.891uV   17.52mV
154ps     -246.8uV   32.03uV    81.06mV
187ps     3.627mV    6.249uV    357.3mV
223ps     73.95mV    -340.5uV   443.9mV
262ps     318.5mV    3.075mV    401.2mV
313ps     401.6mV    58.72mV    395.6mV
366ps     376.9mV    311.1mV    396mV
407ps     369.2mV    371.5mV    396mV
1ns       371.6mV    359.6mV    396mV
[Falling Waveform]
R_fixture= 50.000
V_fixture= 1.100
V_fixture_min= 1.060
V_fixture_max= 1.170
|time   V(typ)   V(min)   V(max)
0s        1.1V       1.06V      1.17V
151ps     1.1V       1.06V      1.158V
164ps     1.101V     1.06V      1.071V
203ps     1.099V     1.06V      627.2mV
242ps     992.1mV    1.061V     461.2mV
291ps     594.8mV    1.059V     530.2mV
343ps     448.1mV    967.5mV    561.3mV
407ps     504.7mV    571.5mV    570.1mV
465ps     530.4mV    449.7mV    571.9mV
1ns       538.8mV    504.5mV    572.5mV
[Falling Waveform]
R_fixture= 50.000
V_fixture= 0.0
V_fixture_min= 0.0
V_fixture_max= 0.0
|time   V(typ)   V(min)   V(max)
0s        371.6mV    359.6mV    396mV
133ps     370.7mV    359mV      400.9mV
187ps     387.8mV    358.4mV    57.34mV
210ps     330mV      363.2mV    16.39mV
236ps     179.8mV    375.2mV    2.494mV
261ps     55.66mV    384.7mV    -4.804mV
281ps     19.55mV    367.9mV    -4.332mV
357ps     -2.041mV   69.11mV    -138.1uV
398ps     -3.843mV   8.999mV    -16.5uV
1ns       2.392uV    16.45uV    -1.611uV
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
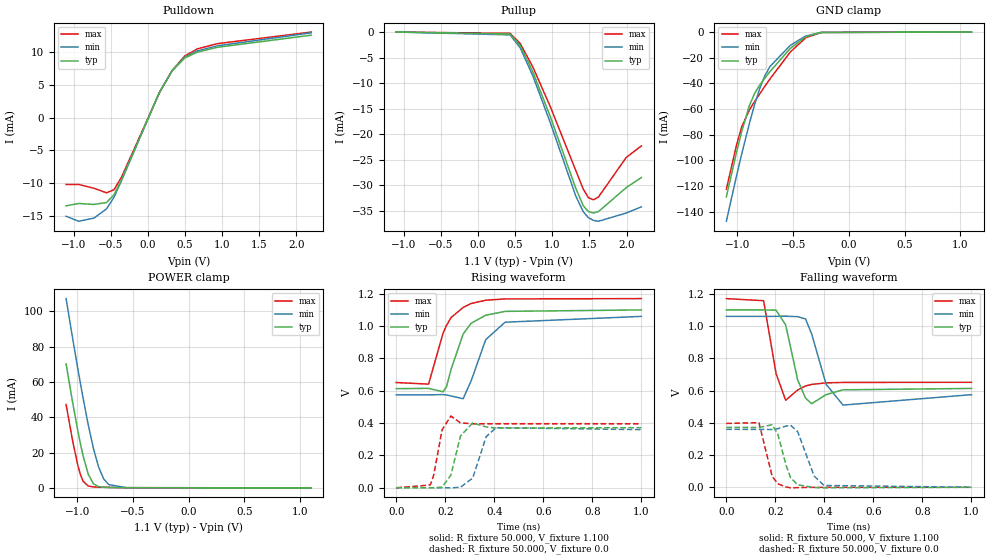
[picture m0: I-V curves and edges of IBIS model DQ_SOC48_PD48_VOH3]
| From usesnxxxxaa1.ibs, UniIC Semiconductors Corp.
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|   Model DQ_SOC48_PD48_VOH3
[Model] DQ_SOC48_PD48_VOH3
Model_type I/O
Polarity   Non-Inverting
Enable   Active-High
Vinl =  0.113V
Vinh =  0.253V
Vmeas =  0.183V
Rref =  50.000
Vref =  0.183V
C_comp   1.110pF   1.087pF   1.118pF
[Model Spec]
Vinh   0.253V   0.247V   0.265V
Vinl   0.113V   0.107V   0.125V
Vmeas   0.183V   NA   NA
Vref   0.183V   NA   NA
Rref   50.000   NA   NA
[Temperature Range]   25.000   0.125k   -40.000
[Voltage Range]   1.100V   1.060V   1.170V
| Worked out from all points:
|   slope of the pulldown table from 0 to 0.165 V, typ, clamps not added: 41.1 ohm
|   GND clamp passes 1 mA (typ) near -0.30 V on its own axis
|   POWER clamp passes 1 mA (typ) near -0.82 V on its own axis
|   rising waveform, R_fixture 50.000, V_fixture 1.100: 20-80 % time 76.5ps typ, 80ps min, 75.9ps max; typ from 0.613 V to 1.1 V
|   rising waveform, R_fixture 50.000, V_fixture 0.0: 20-80 % time 35.2ps typ, 43.9ps min, 26.9ps max; typ from 0 V to 0.372 V
|   falling waveform, R_fixture 50.000, V_fixture 1.100: 20-80 % time 40.1ps typ, 52.8ps min, 30.8ps max; typ from 1.1 V to 0.613 V
|   falling waveform, R_fixture 50.000, V_fixture 0.0: 20-80 % time 41.1ps typ, 49.3ps min, 33.4ps max; typ from 0.372 V to 0 V
[Pulldown]
|Voltage   I(typ)   I(min)   I(max)
-1.1V     -13.43mA   -15.01mA   -10.18mA
-930mV    -13.07mA   -15.78mA   -10.18mA
-726mV    -13.22mA   -15.3mA    -10.75mA
-556mV    -12.93mA   -13.9mA    -11.45mA
-454mV    -11.73mA   -12.11mA   -10.97mA
-352mV    -9.395mA   -9.553mA   -9.028mA
158mV     3.857mA    3.874mA    3.821mA
328mV     7.102mA    7.168mA    7.155mA
498mV     9.071mA    9.207mA    9.38mA
668mV     9.963mA    10.14mA    10.45mA
940mV     10.7mA     10.92mA    11.25mA
2.2V      12.53mA    12.89mA    13.01mA
[Pullup]
|Voltage   I(typ)   I(min)   I(max)
-1.1V     1nA        30.06nA    -1.059nA
432mV     -371.6uA   -553.6uA   -251.6uA
568mV     -2.617mA   -3.06mA    -2.222mA
738mV     -7.76mA    -8.529mA   -6.809mA
976mV     -16.61mA   -17.8mA    -14.65mA
1.316V    -30.54mA   -32.03mA   -27.06mA
1.418V    -33.98mA   -35.17mA   -30.72mA
1.486V    -35.12mA   -36.3mA    -32.39mA
1.554V    -35.39mA   -36.85mA   -32.82mA
1.622V    -35.13mA   -37.02mA   -32.28mA
1.996V    -30.44mA   -35.41mA   -24.54mA
2.2V      -28.46mA   -34.2mA    -22.27mA
[GND_clamp]
|Voltage   I(typ)   I(min)   I(max)
-1.1V     -128.5mA   -147.6mA   -122.6mA
-1.008V   -93.62mA   -112mA     -87.95mA
-962mV    -77.6mA    -95.05mA   -73.96mA
-893mV    -57.36mA   -71.21mA   -60.7mA
-847mV    -48.01mA   -56.81mA   -54.36mA
-801mV    -41.47mA   -44.23mA   -48.33mA
-755mV    -36.02mA   -34.19mA   -42.41mA
-709mV    -30.9mA    -26.94mA   -36.63mA
-525mV    -12.67mA   -10.3mA    -15.49mA
-387mV    -3.615mA   -3.065mA   -4.419mA
-249mV    -281uA     -330.6uA   -301.3uA
1.1V      0A         0A         0A
[POWER_clamp]
|Voltage   I(typ)   I(min)   I(max)
-1.1V     70.27mA    107.3mA    47.25mA
-1.039V   47.68mA    83.93mA    25.86mA
-993mV    31.88mA    66.94mA    12.35mA
-970mV    24.65mA    58.72mA    7.262mA
-947mV    18.06mA    50.74mA    3.761mA
-901mV    7.73mA     35.71mA    987.1uA
-855mV    2.348mA    22.46mA    514uA
-809mV    697.3uA    11.94mA    396.5uA
-763mV    321uA      5.097mA    322.7uA
-717mV    213.8uA    1.813mA    258.1uA
-556mV    65.24uA    79.15uA    81.64uA
1.1V      0A         0A         0A
[Ramp]
| variable   typ   min   max
dV/dt_r   0.223/35.405p   0.216/44.709p   0.238/27.565p
dV/dt_f   0.292/40.658p   0.291/53.435p   0.311/30.807p
R_load = 50.000
[Rising Waveform]
R_fixture= 50.000
V_fixture= 1.100
V_fixture_min= 1.060
V_fixture_max= 1.170
|time   V(typ)   V(min)   V(max)
0s        613mV      574.4mV    651mV
132ps     614.8mV    574.8mV    641mV
191ps     593.6mV    576.2mV    955.8mV
205ps     623.8mV    574.1mV    1.004V
224ps     733.3mV    567.5mV    1.053V
273ps     950.5mV    550.6mV    1.115V
306ps     1.018V     662.6mV    1.14V
365ps     1.067V     915.9mV    1.16V
444ps     1.091V     1.024V     1.168V
1ns       1.1V       1.06V      1.17V
[Rising Waveform]
R_fixture= 50.000
V_fixture= 0.0
V_fixture_min= 0.0
V_fixture_max= 0.0
|time   V(typ)   V(min)   V(max)
0s        1.965uV    15.9uV     367.9nV
139ps     -25.47uV   11.23uV    16.81mV
153ps     -356uV     50.82uV    77.23mV
187ps     3.739mV    7.855uV    358mV
223ps     77.94mV    -516.4uV   443.9mV
262ps     319.6mV    2.977mV    401.2mV
312ps     401.1mV    59.98mV    395.6mV
367ps     376.1mV    315.6mV    396mV
407ps     369.2mV    371.5mV    396mV
1ns       371.6mV    359.6mV    396mV
[Falling Waveform]
R_fixture= 50.000
V_fixture= 1.100
V_fixture_min= 1.060
V_fixture_max= 1.170
|time   V(typ)   V(min)   V(max)
0s        1.1V       1.06V      1.17V
152ps     1.1V       1.06V      1.157V
203ps     1.098V     1.06V      704.3mV
242ps     1.007V     1.061V     539.5mV
291ps     665.9mV    1.058V     603.4mV
323ps     553.5mV    1.044V     628.2mV
348ps     518mV      951.2mV    637.9mV
407ps     574.7mV    638.7mV    647.5mV
476ps     604.4mV    509.8mV    650.2mV
1ns       612.9mV    574.4mV    651mV
[Falling Waveform]
R_fixture= 50.000
V_fixture= 0.0
V_fixture_min= 0.0
V_fixture_max= 0.0
|time   V(typ)   V(min)   V(max)
0s        371.6mV    359.6mV    396mV
133ps     370.7mV    359mV      400.5mV
187ps     387.7mV    358.4mV    67.55mV
210ps     328.8mV    363.3mV    22.16mV
244ps     135.3mV    379.7mV    1.605mV
262ps     59.77mV    384.9mV    -3.396mV
291ps     15.61mV    345.2mV    -2.323mV
358ps     -1.5mV     69.85mV    -148.7uV
398ps     -3.368mV   11.42mV    -23.61uV
1ns       4.349uV    18.74uV    -1.582uV
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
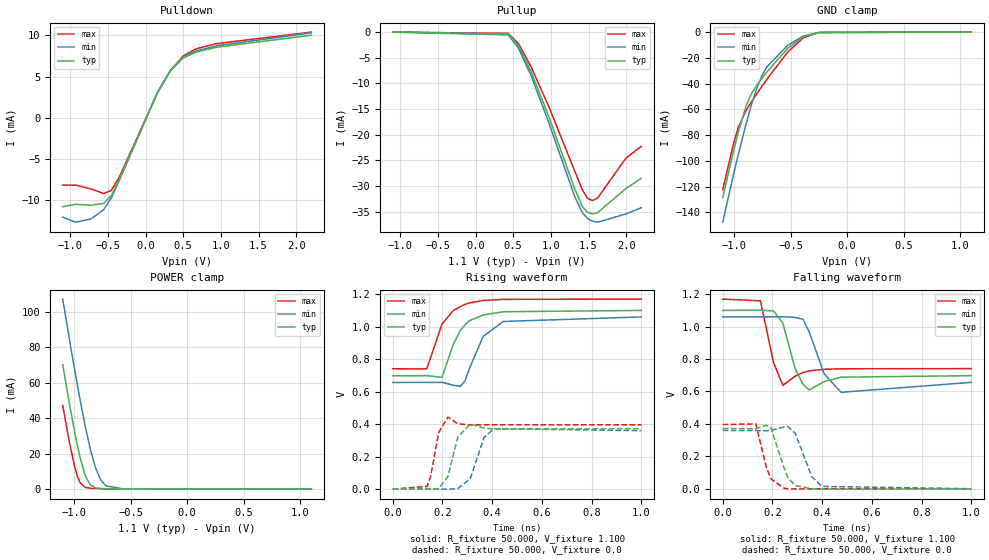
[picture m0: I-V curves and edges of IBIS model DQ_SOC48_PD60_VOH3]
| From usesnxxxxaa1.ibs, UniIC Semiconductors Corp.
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|   Model DQ_SOC48_PD60_VOH3
[Model] DQ_SOC48_PD60_VOH3
Model_type I/O
Polarity   Non-Inverting
Enable   Active-High
Vinl =  0.113V
Vinh =  0.253V
Vmeas =  0.183V
Rref =  50.000
Vref =  0.183V
C_comp   1.110pF   1.087pF   1.118pF
[Model Spec]
Vinh   0.253V   0.247V   0.265V
Vinl   0.113V   0.107V   0.125V
Vmeas   0.183V   NA   NA
Vref   0.183V   NA   NA
Rref   50.000   NA   NA
[Temperature Range]   25.000   0.125k   -40.000
[Voltage Range]   1.100V   1.060V   1.170V
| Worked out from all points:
|   slope of the pulldown table from 0 to 0.165 V, typ, clamps not added: 51.4 ohm
|   GND clamp passes 1 mA (typ) near -0.30 V on its own axis
|   POWER clamp passes 1 mA (typ) near -0.82 V on its own axis
|   rising waveform, R_fixture 50.000, V_fixture 1.100: 20-80 % time 75.6ps typ, 78.6ps min, 75.5ps max; typ from 0.697 V to 1.1 V
|   rising waveform, R_fixture 50.000, V_fixture 0.0: 20-80 % time 35.7ps typ, 44.5ps min, 27.3ps max; typ from 0 V to 0.372 V
|   falling waveform, R_fixture 50.000, V_fixture 1.100: 20-80 % time 40.6ps typ, 53.9ps min, 31.1ps max; typ from 1.1 V to 0.697 V
|   falling waveform, R_fixture 50.000, V_fixture 0.0: 20-80 % time 43.7ps typ, 51.6ps min, 36.4ps max; typ from 0.372 V to 0 V
[Pulldown]
|Voltage   I(typ)   I(min)   I(max)
-1.1V     -10.75mA   -12.01mA   -8.142mA
-930mV    -10.46mA   -12.63mA   -8.143mA
-726mV    -10.58mA   -12.24mA   -8.599mA
-556mV    -10.35mA   -11.12mA   -9.157mA
-454mV    -9.387mA   -9.688mA   -8.773mA
-352mV    -7.516mA   -7.642mA   -7.222mA
158mV     3.086mA    3.099mA    3.057mA
328mV     5.681mA    5.734mA    5.724mA
498mV     7.257mA    7.365mA    7.504mA
668mV     7.97mA     8.112mA    8.363mA
940mV     8.561mA    8.737mA    9mA
2.2V      10.02mA    10.31mA    10.4mA
[Pullup]
|Voltage   I(typ)   I(min)   I(max)
-1.1V     1nA        30.06nA    -1.059nA
432mV     -371.6uA   -553.6uA   -251.6uA
568mV     -2.617mA   -3.06mA    -2.222mA
738mV     -7.76mA    -8.529mA   -6.809mA
976mV     -16.61mA   -17.8mA    -14.65mA
1.316V    -30.54mA   -32.03mA   -27.06mA
1.418V    -33.98mA   -35.17mA   -30.72mA
1.486V    -35.12mA   -36.3mA    -32.39mA
1.554V    -35.39mA   -36.85mA   -32.82mA
1.622V    -35.13mA   -37.02mA   -32.28mA
1.996V    -30.44mA   -35.41mA   -24.54mA
2.2V      -28.46mA   -34.2mA    -22.27mA
[GND_clamp]
|Voltage   I(typ)   I(min)   I(max)
-1.1V     -128.5mA   -147.6mA   -122.6mA
-1.008V   -93.62mA   -112mA     -87.95mA
-962mV    -77.6mA    -95.05mA   -73.96mA
-893mV    -57.36mA   -71.21mA   -60.7mA
-847mV    -48.01mA   -56.81mA   -54.36mA
-801mV    -41.47mA   -44.23mA   -48.33mA
-755mV    -36.02mA   -34.19mA   -42.41mA
-709mV    -30.9mA    -26.94mA   -36.63mA
-525mV    -12.67mA   -10.3mA    -15.49mA
-387mV    -3.615mA   -3.065mA   -4.419mA
-249mV    -281uA     -330.6uA   -301.3uA
1.1V      0A         0A         0A
[POWER_clamp]
|Voltage   I(typ)   I(min)   I(max)
-1.1V     70.27mA    107.3mA    47.25mA
-1.039V   47.68mA    83.93mA    25.86mA
-993mV    31.88mA    66.94mA    12.35mA
-970mV    24.65mA    58.72mA    7.262mA
-947mV    18.06mA    50.74mA    3.761mA
-901mV    7.73mA     35.71mA    987.1uA
-855mV    2.348mA    22.46mA    514uA
-809mV    697.3uA    11.94mA    396.5uA
-763mV    321uA      5.097mA    322.7uA
-717mV    213.8uA    1.813mA    258.1uA
-556mV    65.24uA    79.15uA    81.64uA
1.1V      0A         0A         0A
[Ramp]
| variable   typ   min   max
dV/dt_r   0.223/35.869p   0.216/45.259p   0.238/27.612p
dV/dt_f   0.242/41.080p   0.242/54.520p   0.257/31.198p
R_load = 50.000
[Rising Waveform]
R_fixture= 50.000
V_fixture= 1.100
V_fixture_min= 1.060
V_fixture_max= 1.170
|time   V(typ)   V(min)   V(max)
0s        697.4mV    656.2mV    741mV
137ps     698.5mV    656.9mV    739.5mV
198ps     687.9mV    657.2mV    1.015V
244ps     892.2mV    639.3mV    1.1V
272ps     976mV      632.2mV    1.123V
291ps     1.012V     666.8mV    1.137V
309ps     1.037V     744.3mV    1.146V
364ps     1.072V     940.6mV    1.161V
445ps     1.092V     1.032V     1.168V
1ns       1.1V       1.06V      1.17V
[Rising Waveform]
R_fixture= 50.000
V_fixture= 0.0
V_fixture_min= 0.0
V_fixture_max= 0.0
|time   V(typ)   V(min)   V(max)
0s        2.218uV    17.94uV    414.7nV
138ps     -53.57uV   30.54uV    15.83mV
152ps     -464.7uV   69.02uV    73.91mV
185ps     3.048mV    19.91uV    348.5mV
222ps     76.81mV    -701.6uV   443.2mV
262ps     320.6mV    2.968mV    401.4mV
312ps     401.1mV    64.3mV     395.6mV
367ps     376.1mV    316.7mV    396mV
407ps     369.2mV    371.5mV    396mV
1ns       371.6mV    359.6mV    396mV
[Falling Waveform]
R_fixture= 50.000
V_fixture= 1.100
V_fixture_min= 1.060
V_fixture_max= 1.170
|time   V(typ)   V(min)   V(max)
0s        1.1V       1.06V      1.17V
152ps     1.101V     1.06V      1.159V
204ps     1.097V     1.06V      780.3mV
242ps     1.022V     1.061V     637.8mV
291ps     742.3mV    1.057V     694.1mV
323ps     643.6mV    1.045V     717.3mV
348ps     609.3mV    967.8mV    726.8mV
408ps     660.9mV    709.2mV    736.9mV
476ps     688.3mV    594.8mV    740mV
1ns       697.4mV    656.2mV    741mV
[Falling Waveform]
R_fixture= 50.000
V_fixture= 0.0
V_fixture_min= 0.0
V_fixture_max= 0.0
|time   V(typ)   V(min)   V(max)
0s        371.6mV    359.6mV    396mV
133ps     370.7mV    359mV      400mV
175ps     390.9mV    357.8mV    135.9mV
193ps     380.9mV    359.1mV    62.15mV
244ps     140.9mV    379.8mV    4.873mV
262ps     67.77mV    385mV      -921.1uV
292ps     19.99mV    341.8mV    -1.303mV
358ps     -430.8uV   74.92mV    -109.7uV
399ps     -2.623mV   14.36mV    -18.87uV
1ns       4.993uV    21.11uV    -2.174uV
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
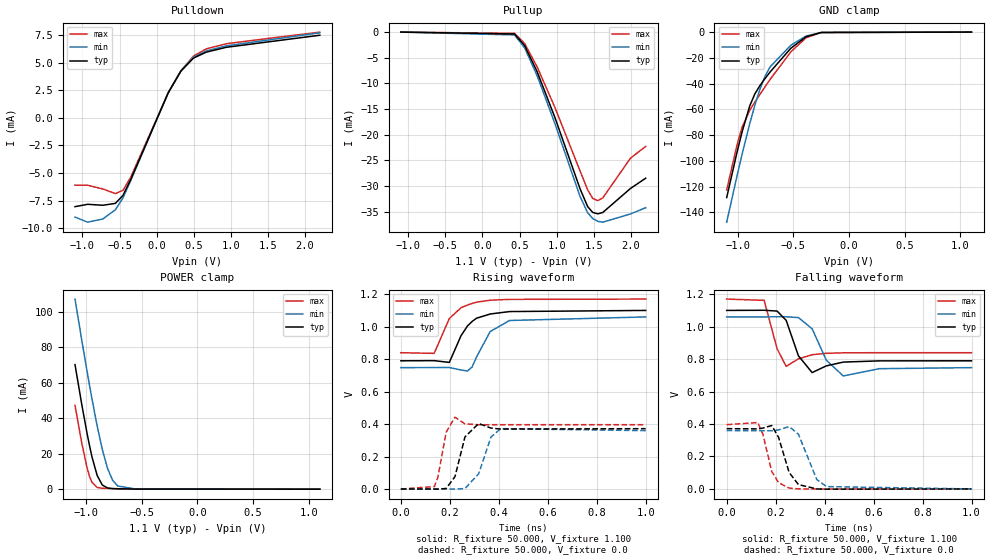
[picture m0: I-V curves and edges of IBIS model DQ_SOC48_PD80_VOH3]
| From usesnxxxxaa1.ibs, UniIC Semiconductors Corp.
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|   Model DQ_SOC48_PD80_VOH3
[Model] DQ_SOC48_PD80_VOH3
Model_type I/O
Polarity   Non-Inverting
Enable   Active-High
Vinl =  0.113V
Vinh =  0.253V
Vmeas =  0.183V
Rref =  50.000
Vref =  0.183V
C_comp   1.110pF   1.087pF   1.118pF
[Model Spec]
Vinh   0.253V   0.247V   0.265V
Vinl   0.113V   0.107V   0.125V
Vmeas   0.183V   NA   NA
Vref   0.183V   NA   NA
Rref   50.000   NA   NA
[Temperature Range]   25.000   0.125k   -40.000
[Voltage Range]   1.100V   1.060V   1.170V
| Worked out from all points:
|   slope of the pulldown table from 0 to 0.165 V, typ, clamps not added: 68.6 ohm
|   GND clamp passes 1 mA (typ) near -0.30 V on its own axis
|   POWER clamp passes 1 mA (typ) near -0.82 V on its own axis
|   rising waveform, R_fixture 50.000, V_fixture 1.100: 20-80 % time 74.6ps typ, 77.1ps min, 75.1ps max; typ from 0.79 V to 1.1 V
|   rising waveform, R_fixture 50.000, V_fixture 0.0: 20-80 % time 36.3ps typ, 45.2ps min, 27.8ps max; typ from 0 V to 0.372 V
|   falling waveform, R_fixture 50.000, V_fixture 1.100: 20-80 % time 40.6ps typ, 54.4ps min, 31.1ps max; typ from 1.1 V to 0.79 V
|   falling waveform, R_fixture 50.000, V_fixture 0.0: 20-80 % time 47.6ps typ, 55ps min, 41.2ps max; typ from 0.372 V to 0 V
[Pulldown]
|Voltage   I(typ)   I(min)   I(max)
-1.1V     -8.06mA    -9.005mA   -6.106mA
-930mV    -7.843mA   -9.47mA    -6.107mA
-726mV    -7.932mA   -9.181mA   -6.449mA
-556mV    -7.761mA   -8.341mA   -6.868mA
-454mV    -7.04mA    -7.266mA   -6.58mA
-352mV    -5.637mA   -5.732mA   -5.417mA
158mV     2.314mA    2.324mA    2.293mA
328mV     4.261mA    4.301mA    4.293mA
498mV     5.443mA    5.524mA    5.628mA
668mV     5.978mA    6.084mA    6.272mA
940mV     6.421mA    6.553mA    6.75mA
2.2V      7.518mA    7.735mA    7.803mA
[Pullup]
|Voltage   I(typ)   I(min)   I(max)
-1.1V     1nA        30.06nA    -1.059nA
432mV     -371.6uA   -553.6uA   -251.6uA
568mV     -2.617mA   -3.06mA    -2.222mA
738mV     -7.76mA    -8.529mA   -6.809mA
976mV     -16.61mA   -17.8mA    -14.65mA
1.316V    -30.54mA   -32.03mA   -27.06mA
1.418V    -33.98mA   -35.17mA   -30.72mA
1.486V    -35.12mA   -36.3mA    -32.39mA
1.554V    -35.39mA   -36.85mA   -32.82mA
1.622V    -35.13mA   -37.02mA   -32.28mA
1.996V    -30.44mA   -35.41mA   -24.54mA
2.2V      -28.46mA   -34.2mA    -22.27mA
[GND_clamp]
|Voltage   I(typ)   I(min)   I(max)
-1.1V     -128.5mA   -147.6mA   -122.6mA
-1.008V   -93.62mA   -112mA     -87.95mA
-962mV    -77.6mA    -95.05mA   -73.96mA
-893mV    -57.36mA   -71.21mA   -60.7mA
-847mV    -48.01mA   -56.81mA   -54.36mA
-801mV    -41.47mA   -44.23mA   -48.33mA
-755mV    -36.02mA   -34.19mA   -42.41mA
-709mV    -30.9mA    -26.94mA   -36.63mA
-525mV    -12.67mA   -10.3mA    -15.49mA
-387mV    -3.615mA   -3.065mA   -4.419mA
-249mV    -281uA     -330.6uA   -301.3uA
1.1V      0A         0A         0A
[POWER_clamp]
|Voltage   I(typ)   I(min)   I(max)
-1.1V     70.27mA    107.3mA    47.25mA
-1.039V   47.68mA    83.93mA    25.86mA
-993mV    31.88mA    66.94mA    12.35mA
-970mV    24.65mA    58.72mA    7.262mA
-947mV    18.06mA    50.74mA    3.761mA
-901mV    7.73mA     35.71mA    987.1uA
-855mV    2.348mA    22.46mA    514uA
-809mV    697.3uA    11.94mA    396.5uA
-763mV    321uA      5.097mA    322.7uA
-717mV    213.8uA    1.813mA    258.1uA
-556mV    65.24uA    79.15uA    81.64uA
1.1V      0A         0A         0A
[Ramp]
| variable   typ   min   max
dV/dt_r   0.223/36.354p   0.216/46.217p   0.238/28.090p
dV/dt_f   0.186/41.024p   0.187/55.162p   0.198/31.224p
R_load = 50.000
[Rising Waveform]
R_fixture= 50.000
V_fixture= 1.100
V_fixture_min= 1.060
V_fixture_max= 1.170
|time   V(typ)   V(min)   V(max)
0s        789.7mV    747.6mV    839.6mV
136ps     790.7mV    748.1mV    835.4mV
198ps     779.8mV    748.3mV    1.05V
246ps     944.9mV    733.2mV    1.117V
272ps     1.004V     726.6mV    1.133V
291ps     1.032V     751.5mV    1.143V
309ps     1.052V     813.1mV    1.151V
365ps     1.078V     970.1mV    1.163V
444ps     1.093V     1.038V     1.168V
1ns       1.1V       1.06V      1.17V
[Rising Waveform]
R_fixture= 50.000
V_fixture= 0.0
V_fixture_min= 0.0
V_fixture_max= 0.0
|time   V(typ)   V(min)   V(max)
0s        2.545uV    20.59uV    475.2nV
137ps     -81.03uV   52.03uV    15.2mV
151ps     -589.2uV   92.18uV    70.8mV
185ps     3.278mV    11.56uV    349.3mV
221ps     75.98mV    -913.9uV   442.6mV
262ps     321.4mV    3.082mV    401.4mV
318ps     403.7mV    94.17mV    395.7mV
368ps     375.4mV    320mV      396mV
408ps     369.3mV    371.9mV    396mV
1ns       371.6mV    359.6mV    396mV
[Falling Waveform]
R_fixture= 50.000
V_fixture= 1.100
V_fixture_min= 1.060
V_fixture_max= 1.170
|time   V(typ)   V(min)   V(max)
0s        1.1V       1.06V      1.17V
153ps     1.101V     1.06V      1.162V
206ps     1.096V     1.061V     863.4mV
243ps     1.039V     1.061V     755.4mV
293ps     820.3mV    1.056V     801.6mV
349ps     717mV      986.9mV    827.2mV
407ps     758.4mV    793.2mV    835.7mV
476ps     781.6mV    696.3mV    838.7mV
623ps     789.2mV    741mV      839.6mV
1ns       789.7mV    747.5mV    839.6mV
[Falling Waveform]
R_fixture= 50.000
V_fixture= 0.0
V_fixture_min= 0.0
V_fixture_max= 0.0
|time   V(typ)   V(min)   V(max)
0s        371.6mV    359.6mV    396mV
127ps     370.1mV    359.2mV    409.2mV
148ps     374.9mV    358.4mV    336.9mV
184ps     390.8mV    358.2mV    107.7mV
212ps     317.6mV    364mV      38.53mV
255ps     101.9mV    384.2mV    5.391mV
293ps     26.92mV    337.5mV    527.6uV
368ps     94.09uV    57.83mV    81.73uV
408ps     -1.313mV   14.42mV    31.9uV
1ns       5.66uV     24.23uV    -2.177uV
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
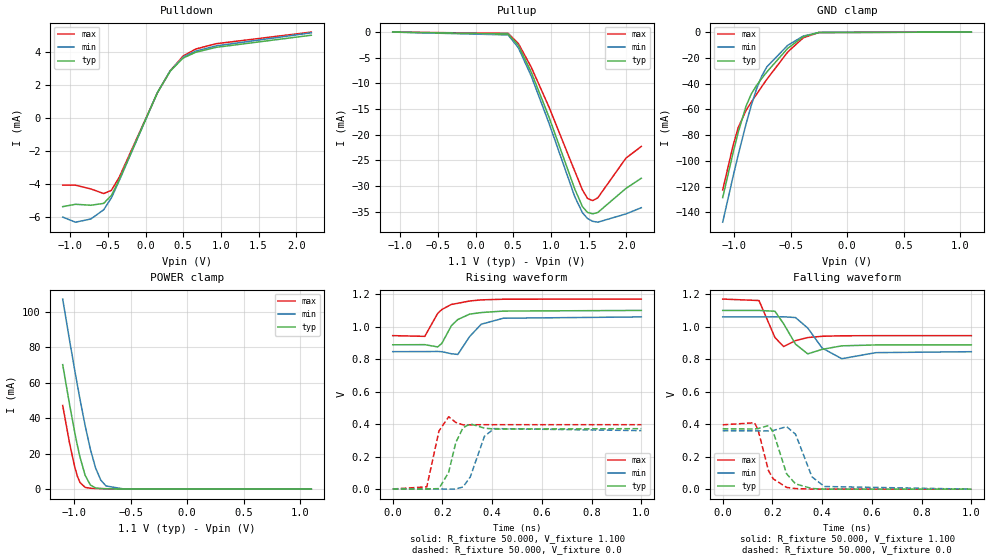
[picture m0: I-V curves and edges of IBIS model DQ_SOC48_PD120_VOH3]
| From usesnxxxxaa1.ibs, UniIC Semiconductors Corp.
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|   Model DQ_SOC48_PD120_VOH3
[Model] DQ_SOC48_PD120_VOH3
Model_type I/O
Polarity   Non-Inverting
Enable   Active-High
Vinl =  0.113V
Vinh =  0.253V
Vmeas =  0.183V
Rref =  50.000
Vref =  0.183V
C_comp   1.110pF   1.087pF   1.118pF
[Model Spec]
Vinh   0.253V   0.247V   0.265V
Vinl   0.113V   0.107V   0.125V
Vmeas   0.183V   NA   NA
Vref   0.183V   NA   NA
Rref   50.000   NA   NA
[Temperature Range]   25.000   0.125k   -40.000
[Voltage Range]   1.100V   1.060V   1.170V
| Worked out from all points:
|   slope of the pulldown table from 0 to 0.165 V, typ, clamps not added: 103 ohm
|   GND clamp passes 1 mA (typ) near -0.30 V on its own axis
|   POWER clamp passes 1 mA (typ) near -0.82 V on its own axis
|   rising waveform, R_fixture 50.000, V_fixture 1.100: 20-80 % time 68.3ps typ, 67ps min, 69.8ps max; typ from 0.888 V to 1.1 V
|   rising waveform, R_fixture 50.000, V_fixture 0.0: 20-80 % time 36.3ps typ, 45.5ps min, 27.7ps max; typ from 0 V to 0.372 V
|   falling waveform, R_fixture 50.000, V_fixture 1.100: 20-80 % time 43.2ps typ, 56.4ps min, 33ps max; typ from 1.1 V to 0.888 V
|   falling waveform, R_fixture 50.000, V_fixture 0.0: 20-80 % time 49.2ps typ, 54.5ps min, 46.1ps max; typ from 0.372 V to 0 V
[Pulldown]
|Voltage   I(typ)   I(min)   I(max)
-1.1V     -5.373mA   -6.003mA   -4.071mA
-930mV    -5.229mA   -6.314mA   -4.072mA
-726mV    -5.288mA   -6.12mA    -4.3mA
-556mV    -5.174mA   -5.561mA   -4.579mA
-454mV    -4.694mA   -4.844mA   -4.386mA
-352mV    -3.758mA   -3.821mA   -3.611mA
158mV     1.543mA    1.549mA    1.529mA
328mV     2.841mA    2.867mA    2.862mA
498mV     3.628mA    3.683mA    3.752mA
668mV     3.985mA    4.056mA    4.181mA
940mV     4.28mA     4.369mA    4.5mA
2.2V      5.012mA    5.157mA    5.202mA
[Pullup]
|Voltage   I(typ)   I(min)   I(max)
-1.1V     1nA        30.06nA    -1.059nA
432mV     -371.6uA   -553.6uA   -251.6uA
568mV     -2.617mA   -3.06mA    -2.222mA
738mV     -7.76mA    -8.529mA   -6.809mA
976mV     -16.61mA   -17.8mA    -14.65mA
1.316V    -30.54mA   -32.03mA   -27.06mA
1.418V    -33.98mA   -35.17mA   -30.72mA
1.486V    -35.12mA   -36.3mA    -32.39mA
1.554V    -35.39mA   -36.85mA   -32.82mA
1.622V    -35.13mA   -37.02mA   -32.28mA
1.996V    -30.44mA   -35.41mA   -24.54mA
2.2V      -28.46mA   -34.2mA    -22.27mA
[GND_clamp]
|Voltage   I(typ)   I(min)   I(max)
-1.1V     -128.5mA   -147.6mA   -122.6mA
-1.008V   -93.62mA   -112mA     -87.95mA
-962mV    -77.6mA    -95.05mA   -73.96mA
-893mV    -57.36mA   -71.21mA   -60.7mA
-847mV    -48.01mA   -56.81mA   -54.36mA
-801mV    -41.47mA   -44.23mA   -48.33mA
-755mV    -36.02mA   -34.19mA   -42.41mA
-709mV    -30.9mA    -26.94mA   -36.63mA
-525mV    -12.67mA   -10.3mA    -15.49mA
-387mV    -3.615mA   -3.065mA   -4.419mA
-249mV    -281uA     -330.6uA   -301.3uA
1.1V      0A         0A         0A
[POWER_clamp]
|Voltage   I(typ)   I(min)   I(max)
-1.1V     70.27mA    107.3mA    47.25mA
-1.039V   47.68mA    83.93mA    25.86mA
-993mV    31.88mA    66.94mA    12.35mA
-970mV    24.65mA    58.72mA    7.262mA
-947mV    18.06mA    50.74mA    3.761mA
-901mV    7.73mA     35.71mA    987.1uA
-855mV    2.348mA    22.46mA    514uA
-809mV    697.3uA    11.94mA    396.5uA
-763mV    321uA      5.097mA    322.7uA
-717mV    213.8uA    1.813mA    258.1uA
-556mV    65.24uA    79.15uA    81.64uA
1.1V      0A         0A         0A
[Ramp]
| variable   typ   min   max
dV/dt_r   0.223/36.494p   0.216/46.462p   0.238/28.256p
dV/dt_f   0.127/43.476p   0.128/57.142p   0.135/33.011p
R_load = 50.000
[Rising Waveform]
R_fixture= 50.000
V_fixture= 1.100
V_fixture_min= 1.060
V_fixture_max= 1.170
|time   V(typ)   V(min)   V(max)
0s        888.3mV    846.1mV    944.8mV
129ps     889.1mV    846.4mV    940.3mV
181ps     875.3mV    847.3mV    1.082V
198ps     898mV      845.6mV    1.106V
236ps     1.006V     833.2mV    1.137V
262ps     1.044V     828.9mV    1.144V
309ps     1.077V     938.3mV    1.158V
356ps     1.087V     1.015V     1.165V
445ps     1.096V     1.052V     1.169V
1ns       1.1V       1.06V      1.17V
[Rising Waveform]
R_fixture= 50.000
V_fixture= 0.0
V_fixture_min= 0.0
V_fixture_max= 0.0
|time   V(typ)   V(min)   V(max)
0s        2.986uV    24.15uV    556.4nV
137ps     243.8nV    68.11uV    13.18mV
186ps     2.366mV    74.18uV    356.9mV
225ps     102.5mV    -1.051mV   445mV
254ps     287.4mV    -30.05uV   409.7mV
283ps     377.4mV    12.83mV    395.2mV
312ps     401.2mV    74.4mV     395.6mV
369ps     374.9mV    324.8mV    396mV
408ps     369.3mV    371.9mV    396mV
1ns       371.6mV    359.6mV    396mV
[Falling Waveform]
R_fixture= 50.000
V_fixture= 1.100
V_fixture_min= 1.060
V_fixture_max= 1.170
|time   V(typ)   V(min)   V(max)
0s        1.1V       1.06V      1.17V
146ps     1.1V       1.06V      1.161V
210ps     1.095V     1.061V     933.6mV
245ps     1.018V     1.061V     877.7mV
293ps     892.4mV    1.056V     914.3mV
342ps     832.6mV    991.7mV    933.1mV
400ps     860.5mV    868.4mV    940.9mV
479ps     882.1mV    803mV      944mV
616ps     887.8mV    840.2mV    944.7mV
1ns       888.3mV    846.1mV    944.8mV
[Falling Waveform]
R_fixture= 50.000
V_fixture= 0.0
V_fixture_min= 0.0
V_fixture_max= 0.0
|time   V(typ)   V(min)   V(max)
0s        371.6mV    359.6mV    396mV
128ps     370.2mV    359.2mV    408.7mV
142ps     372.6mV    358.6mV    366.4mV
184ps     391.5mV    358.1mV    114.6mV
203ps     354.3mV    361.1mV    63.84mV
257ps     94.45mV    384.9mV    10.79mV
293ps     32.29mV    338.1mV    3.544mV
359ps     3.999mV    75.8mV     697.6uV
409ps     -29.98uV   16.34mV    204.2uV
1ns       1.679uV    28.44uV    -2.337uV
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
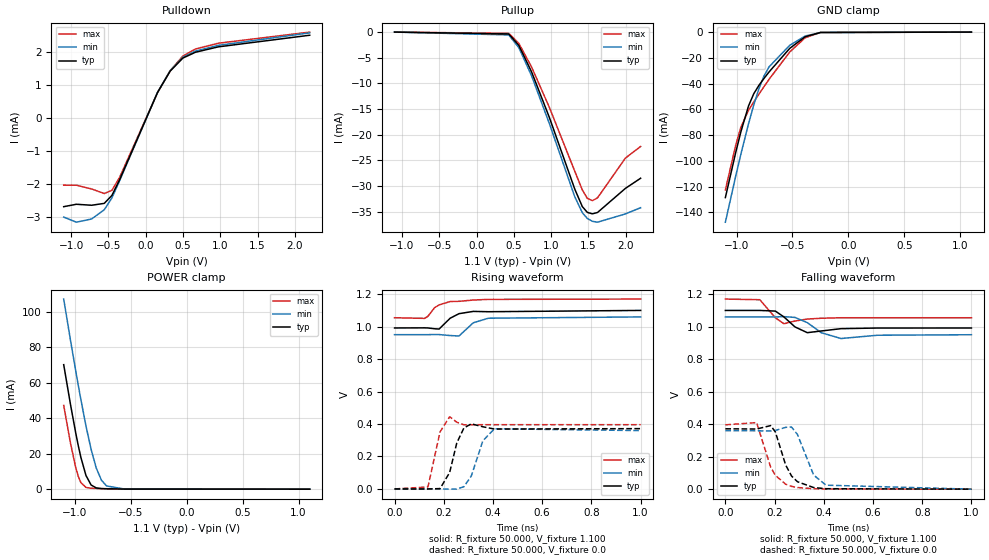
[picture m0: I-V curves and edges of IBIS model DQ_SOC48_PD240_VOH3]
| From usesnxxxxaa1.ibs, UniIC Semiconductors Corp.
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|   Model DQ_SOC48_PD240_VOH3
[Model] DQ_SOC48_PD240_VOH3
Model_type I/O
Polarity   Non-Inverting
Enable   Active-High
Vinl =  0.113V
Vinh =  0.253V
Vmeas =  0.183V
Rref =  50.000
Vref =  0.183V
C_comp   1.110pF   1.087pF   1.118pF
[Model Spec]
Vinh   0.253V   0.247V   0.265V
Vinl   0.113V   0.107V   0.125V
Vmeas   0.183V   NA   NA
Vref   0.183V   NA   NA
Rref   50.000   NA   NA
[Temperature Range]   25.000   0.125k   -40.000
[Voltage Range]   1.100V   1.060V   1.170V
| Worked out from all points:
|   slope of the pulldown table from 0 to 0.165 V, typ, clamps not added: 206 ohm
|   GND clamp passes 1 mA (typ) near -0.30 V on its own axis
|   POWER clamp passes 1 mA (typ) near -0.82 V on its own axis
|   rising waveform, R_fixture 50.000, V_fixture 1.100: 20-80 % time 54.9ps typ, 50.3ps min, 62.1ps max; typ from 0.992 V to 1.1 V
|   rising waveform, R_fixture 50.000, V_fixture 0.0: 20-80 % time 36.9ps typ, 47.1ps min, 28.3ps max; typ from 0 V to 0.372 V
|   falling waveform, R_fixture 50.000, V_fixture 1.100: 20-80 % time 44.3ps typ, 57.5ps min, 33.8ps max; typ from 1.1 V to 0.992 V
|   falling waveform, R_fixture 50.000, V_fixture 0.0: 20-80 % time 57.2ps typ, 60.1ps min, 56ps max; typ from 0.372 V to 0 V
[Pulldown]
|Voltage   I(typ)   I(min)   I(max)
-1.1V     -2.687mA   -3.002mA   -2.035mA
-930mV    -2.614mA   -3.157mA   -2.036mA
-726mV    -2.644mA   -3.06mA    -2.15mA
-556mV    -2.587mA   -2.78mA    -2.289mA
-454mV    -2.347mA   -2.422mA   -2.193mA
-352mV    -1.879mA   -1.911mA   -1.806mA
158mV     771.5uA    774.7uA    764.3uA
328mV     1.42mA     1.434mA    1.431mA
498mV     1.814mA    1.841mA    1.876mA
668mV     1.992mA    2.028mA    2.091mA
974mV     2.154mA    2.199mA    2.264mA
2.2V      2.506mA    2.578mA    2.601mA
[Pullup]
|Voltage   I(typ)   I(min)   I(max)
-1.1V     1nA        30.06nA    -1.059nA
432mV     -371.6uA   -553.6uA   -251.6uA
568mV     -2.617mA   -3.06mA    -2.222mA
738mV     -7.76mA    -8.529mA   -6.809mA
976mV     -16.61mA   -17.8mA    -14.65mA
1.316V    -30.54mA   -32.03mA   -27.06mA
1.418V    -33.98mA   -35.17mA   -30.72mA
1.486V    -35.12mA   -36.3mA    -32.39mA
1.554V    -35.39mA   -36.85mA   -32.82mA
1.622V    -35.13mA   -37.02mA   -32.28mA
1.996V    -30.44mA   -35.41mA   -24.54mA
2.2V      -28.46mA   -34.2mA    -22.27mA
[GND_clamp]
|Voltage   I(typ)   I(min)   I(max)
-1.1V     -128.5mA   -147.6mA   -122.6mA
-1.008V   -93.62mA   -112mA     -87.95mA
-962mV    -77.6mA    -95.05mA   -73.96mA
-893mV    -57.36mA   -71.21mA   -60.7mA
-847mV    -48.01mA   -56.81mA   -54.36mA
-801mV    -41.47mA   -44.23mA   -48.33mA
-755mV    -36.02mA   -34.19mA   -42.41mA
-709mV    -30.9mA    -26.94mA   -36.63mA
-525mV    -12.67mA   -10.3mA    -15.49mA
-387mV    -3.615mA   -3.065mA   -4.419mA
-249mV    -281uA     -330.6uA   -301.3uA
1.1V      0A         0A         0A
[POWER_clamp]
|Voltage   I(typ)   I(min)   I(max)
-1.1V     70.27mA    107.3mA    47.25mA
-1.039V   47.68mA    83.93mA    25.86mA
-993mV    31.88mA    66.94mA    12.35mA
-970mV    24.65mA    58.72mA    7.262mA
-947mV    18.06mA    50.74mA    3.761mA
-901mV    7.73mA     35.71mA    987.1uA
-855mV    2.348mA    22.46mA    514uA
-809mV    697.3uA    11.94mA    396.5uA
-763mV    321uA      5.097mA    322.7uA
-717mV    213.8uA    1.813mA    258.1uA
-556mV    65.24uA    79.15uA    81.64uA
1.1V      0A         0A         0A
[Ramp]
| variable   typ   min   max
dV/dt_r   0.223/37.359p   0.216/47.161p   0.238/28.337p
dV/dt_f   64.848m/44.297p   65.673m/58.011p   68.888m/33.844p
R_load = 50.000
[Rising Waveform]
R_fixture= 50.000
V_fixture= 1.100
V_fixture_min= 1.060
V_fixture_max= 1.170
|time   V(typ)   V(min)   V(max)
0s        991.9mV    950.6mV    1.055V
122ps     992.6mV    950.6mV    1.051V
135ps     992mV      950.8mV    1.063V
163ps     986.9mV    951.3mV    1.117V
181ps     985.3mV    951.2mV    1.134V
226ps     1.052V     945.2mV    1.155V
262ps     1.08V      942.5mV    1.156V
320ps     1.094V     1.024V     1.164V
381ps     1.092V     1.052V     1.168V
1ns       1.1V       1.06V      1.17V
[Rising Waveform]
R_fixture= 50.000
V_fixture= 0.0
V_fixture_min= 0.0
V_fixture_max= 0.0
|time   V(typ)   V(min)   V(max)
0s        3.61uV     29.2uV     671nV
136ps     -38.66uV   95.79uV    12.43mV
185ps     2.18mV     64.65uV    352.3mV
224ps     101.5mV    -1.344mV   444.7mV
253ps     283.7mV    -561.8uV   411.2mV
282ps     376mV      13.96mV    395.3mV
312ps     401.1mV    80.14mV    395.6mV
359ps     383.1mV    296.9mV    396mV
406ps     369.1mV    370.8mV    396mV
1ns       371.6mV    359.6mV    396mV
[Falling Waveform]
R_fixture= 50.000
V_fixture= 1.100
V_fixture_min= 1.060
V_fixture_max= 1.170
|time   V(typ)   V(min)   V(max)
0s        1.1V       1.06V      1.17V
140ps     1.1V       1.06V      1.166V
203ps     1.096V     1.06V      1.055V
238ps     1.06V      1.062V     1.018V
283ps     998.4mV    1.057V     1.035V
333ps     963.1mV    1.025V     1.047V
390ps     973.7mV    962.6mV    1.052V
470ps     987.8mV    927.2mV    1.055V
618ps     991.7mV    947.4mV    1.055V
1ns       991.9mV    950.5mV    1.055V
[Falling Waveform]
R_fixture= 50.000
V_fixture= 0.0
V_fixture_min= 0.0
V_fixture_max= 0.0
|time   V(typ)   V(min)   V(max)
0s        371.6mV    359.6mV    396mV
127ps     370.1mV    359.2mV    409.7mV
184ps     391.3mV    358.2mV    135.5mV
203ps     352.8mV    361.2mV    85.13mV
245ps     148.7mV    380.7mV    30.54mV
269ps     80.61mV    381.9mV    17.05mV
293ps     45.77mV    336.1mV    10.18mV
359ps     9.829mV    86.28mV    2.587mV
409ps     2.805mV    24.52mV    912.2uV
1ns       8.359uV    34.47uV    -2.76uV
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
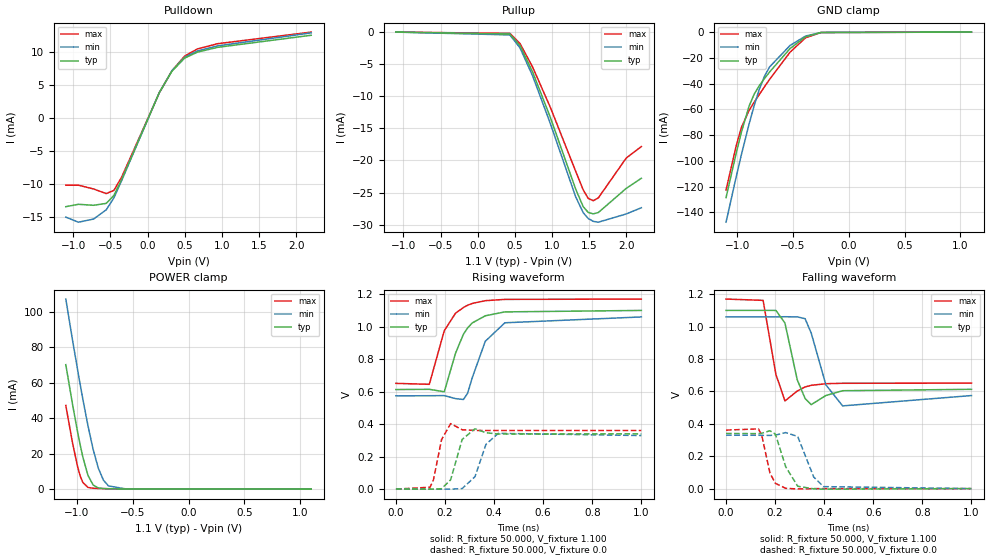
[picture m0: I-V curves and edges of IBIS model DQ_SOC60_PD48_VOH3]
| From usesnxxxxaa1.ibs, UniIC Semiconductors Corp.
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|   Model DQ_SOC60_PD48_VOH3
[Model] DQ_SOC60_PD48_VOH3
Model_type I/O
Polarity   Non-Inverting
Enable   Active-High
Vinl =  0.113V
Vinh =  0.253V
Vmeas =  0.183V
Rref =  50.000
Vref =  0.183V
C_comp   1.110pF   1.087pF   1.118pF
[Model Spec]
Vinh   0.253V   0.247V   0.265V
Vinl   0.113V   0.107V   0.125V
Vmeas   0.183V   NA   NA
Vref   0.183V   NA   NA
Rref   50.000   NA   NA
[Temperature Range]   25.000   0.125k   -40.000
[Voltage Range]   1.100V   1.060V   1.170V
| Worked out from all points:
|   slope of the pulldown table from 0 to 0.165 V, typ, clamps not added: 41.1 ohm
|   GND clamp passes 1 mA (typ) near -0.30 V on its own axis
|   POWER clamp passes 1 mA (typ) near -0.82 V on its own axis
|   rising waveform, R_fixture 50.000, V_fixture 1.100: 20-80 % time 76.7ps typ, 80.3ps min, 75.7ps max; typ from 0.613 V to 1.1 V
|   rising waveform, R_fixture 50.000, V_fixture 0.0: 20-80 % time 35.4ps typ, 44.5ps min, 28.1ps max; typ from 0 V to 0.34 V
|   falling waveform, R_fixture 50.000, V_fixture 1.100: 20-80 % time 40ps typ, 52.5ps min, 30.8ps max; typ from 1.1 V to 0.613 V
|   falling waveform, R_fixture 50.000, V_fixture 0.0: 20-80 % time 40.1ps typ, 48.3ps min, 32.8ps max; typ from 0.34 V to 0 V
[Pulldown]
|Voltage   I(typ)   I(min)   I(max)
-1.1V     -13.43mA   -15.01mA   -10.18mA
-930mV    -13.07mA   -15.78mA   -10.18mA
-726mV    -13.22mA   -15.3mA    -10.75mA
-556mV    -12.93mA   -13.9mA    -11.45mA
-454mV    -11.73mA   -12.11mA   -10.97mA
-352mV    -9.395mA   -9.553mA   -9.028mA
158mV     3.857mA    3.874mA    3.821mA
328mV     7.102mA    7.168mA    7.155mA
498mV     9.071mA    9.207mA    9.38mA
668mV     9.963mA    10.14mA    10.45mA
940mV     10.7mA     10.92mA    11.25mA
2.2V      12.53mA    12.89mA    13.01mA
[Pullup]
|Voltage   I(typ)   I(min)   I(max)
-1.1V     1nA        30.41nA    -1.059nA
432mV     -297.3uA   -442.9uA   -201.3uA
568mV     -2.094mA   -2.448mA   -1.778mA
738mV     -6.208mA   -6.823mA   -5.447mA
976mV     -13.28mA   -14.24mA   -11.72mA
1.316V    -24.43mA   -25.63mA   -21.65mA
1.418V    -27.19mA   -28.13mA   -24.57mA
1.486V    -28.09mA   -29.04mA   -25.91mA
1.554V    -28.31mA   -29.48mA   -26.26mA
1.622V    -28.1mA    -29.61mA   -25.82mA
1.996V    -24.35mA   -28.33mA   -19.63mA
2.2V      -22.77mA   -27.36mA   -17.82mA
[GND_clamp]
|Voltage   I(typ)   I(min)   I(max)
-1.1V     -128.5mA   -147.6mA   -122.6mA
-1.008V   -93.62mA   -112mA     -87.95mA
-962mV    -77.6mA    -95.05mA   -73.96mA
-893mV    -57.36mA   -71.21mA   -60.7mA
-847mV    -48.01mA   -56.81mA   -54.36mA
-801mV    -41.47mA   -44.23mA   -48.33mA
-755mV    -36.02mA   -34.19mA   -42.41mA
-709mV    -30.9mA    -26.94mA   -36.63mA
-525mV    -12.67mA   -10.3mA    -15.49mA
-387mV    -3.615mA   -3.065mA   -4.419mA
-249mV    -281uA     -330.6uA   -301.3uA
1.1V      0A         0A         0A
[POWER_clamp]
|Voltage   I(typ)   I(min)   I(max)
-1.1V     70.27mA    107.3mA    47.25mA
-1.039V   47.68mA    83.93mA    25.86mA
-993mV    31.88mA    66.94mA    12.35mA
-970mV    24.65mA    58.72mA    7.262mA
-947mV    18.06mA    50.74mA    3.761mA
-901mV    7.73mA     35.71mA    987.1uA
-855mV    2.348mA    22.46mA    514uA
-809mV    697.3uA    11.94mA    396.5uA
-763mV    321uA      5.097mA    322.7uA
-717mV    213.8uA    1.813mA    258.1uA
-556mV    65.24uA    79.15uA    81.64uA
1.1V      0A         0A         0A
[Ramp]
| variable   typ   min   max
dV/dt_r   0.204/35.865p   0.198/44.990p   0.217/28.178p
dV/dt_f   0.292/40.381p   0.291/53.457p   0.311/30.798p
R_load = 50.000
[Rising Waveform]
R_fixture= 50.000
V_fixture= 1.100
V_fixture_min= 1.060
V_fixture_max= 1.170
|time   V(typ)   V(min)   V(max)
0s        613mV      574.4mV    651mV
136ps     614.4mV    575mV      645.2mV
197ps     599.1mV    575.7mV    975.6mV
243ps     837.2mV    557.3mV    1.083V
275ps     953.2mV    551.7mV    1.118V
292ps     992.2mV    590mV      1.132V
311ps     1.023V     685.7mV    1.143V
364ps     1.067V     910mV      1.16V
444ps     1.091V     1.024V     1.168V
1ns       1.1V       1.06V      1.17V
[Rising Waveform]
R_fixture= 50.000
V_fixture= 0.0
V_fixture_min= 0.0
V_fixture_max= 0.0
|time   V(typ)   V(min)   V(max)
0s        1.965uV    15.9uV     367.9nV
139ps     42.42uV    -3.809uV   11.73mV
153ps     -152uV     30.7uV     57.46mV
186ps     2.407mV    41.27uV    305.1mV
223ps     57.78mV    -239.4uV   403.5mV
270ps     306.2mV    3.781mV    365.4mV
322ps     371.5mV    76.11mV    361.1mV
367ps     347.2mV    276.1mV    361.1mV
417ps     339.1mV    343.4mV    361.1mV
1ns       340.3mV    329.8mV    361.1mV
[Falling Waveform]
R_fixture= 50.000
V_fixture= 1.100
V_fixture_min= 1.060
V_fixture_max= 1.170
|time   V(typ)   V(min)   V(max)
0s        1.1V       1.06V      1.17V
151ps     1.1V       1.06V      1.162V
203ps     1.1V       1.06V      705.9mV
240ps     1.022V     1.061V     541.1mV
290ps     672mV      1.06V      602.2mV
322ps     556.5mV    1.049V     627.6mV
347ps     518.3mV    960mV      637.6mV
407ps     574.8mV    640mV      647.5mV
475ps     604.3mV    510.6mV    650.2mV
1ns       612.9mV    574.4mV    651mV
[Falling Waveform]
R_fixture= 50.000
V_fixture= 0.0
V_fixture_min= 0.0
V_fixture_max= 0.0
|time   V(typ)   V(min)   V(max)
0s        340.3mV    329.8mV    361.1mV
132ps     339.3mV    329.3mV    368.8mV
146ps     342mV      328.9mV    325.6mV
179ps     357.1mV    328.4mV    95.54mV
201ps     336.6mV    330.3mV    32.57mV
243ps     135.1mV    345.9mV    1.772mV
292ps     14.57mV    322mV      -2.273mV
357ps     -1.398mV   72.02mV    -156.2uV
397ps     -3.436mV   12.23mV    -23.48uV
1ns       4.607uV    19.53uV    575.3nV
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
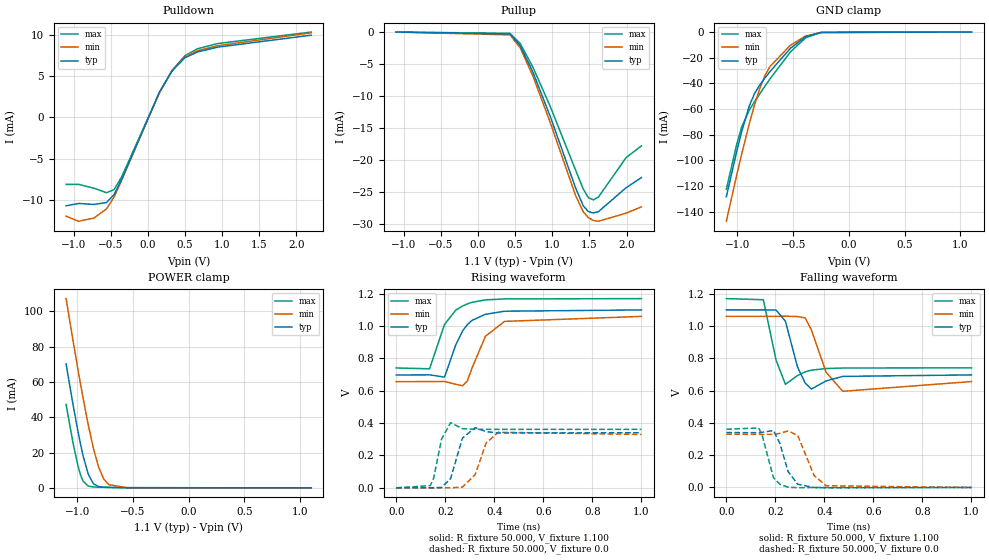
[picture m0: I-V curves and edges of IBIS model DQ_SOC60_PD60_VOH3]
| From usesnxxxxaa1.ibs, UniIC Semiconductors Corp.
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|   Model DQ_SOC60_PD60_VOH3
[Model] DQ_SOC60_PD60_VOH3
Model_type I/O
Polarity   Non-Inverting
Enable   Active-High
Vinl =  0.113V
Vinh =  0.253V
Vmeas =  0.183V
Rref =  50.000
Vref =  0.183V
C_comp   1.110pF   1.087pF   1.118pF
[Model Spec]
Vinh   0.253V   0.247V   0.265V
Vinl   0.113V   0.107V   0.125V
Vmeas   0.183V   NA   NA
Vref   0.183V   NA   NA
Rref   50.000   NA   NA
[Temperature Range]   25.000   0.125k   -40.000
[Voltage Range]   1.100V   1.060V   1.170V
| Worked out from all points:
|   slope of the pulldown table from 0 to 0.165 V, typ, clamps not added: 51.4 ohm
|   GND clamp passes 1 mA (typ) near -0.30 V on its own axis
|   POWER clamp passes 1 mA (typ) near -0.82 V on its own axis
|   rising waveform, R_fixture 50.000, V_fixture 1.100: 20-80 % time 76ps typ, 79.3ps min, 75.4ps max; typ from 0.697 V to 1.1 V
|   rising waveform, R_fixture 50.000, V_fixture 0.0: 20-80 % time 36.1ps typ, 45.4ps min, 28.4ps max; typ from 0 V to 0.34 V
|   falling waveform, R_fixture 50.000, V_fixture 1.100: 20-80 % time 40.4ps typ, 53.6ps min, 31.1ps max; typ from 1.1 V to 0.697 V
|   falling waveform, R_fixture 50.000, V_fixture 0.0: 20-80 % time 42.6ps typ, 50.8ps min, 35.9ps max; typ from 0.34 V to 0 V
[Pulldown]
|Voltage   I(typ)   I(min)   I(max)
-1.1V     -10.75mA   -12.01mA   -8.142mA
-930mV    -10.46mA   -12.63mA   -8.143mA
-726mV    -10.58mA   -12.24mA   -8.599mA
-556mV    -10.35mA   -11.12mA   -9.157mA
-454mV    -9.387mA   -9.688mA   -8.773mA
-352mV    -7.516mA   -7.642mA   -7.222mA
158mV     3.086mA    3.099mA    3.057mA
328mV     5.681mA    5.734mA    5.724mA
498mV     7.257mA    7.365mA    7.504mA
668mV     7.97mA     8.112mA    8.363mA
940mV     8.561mA    8.737mA    9mA
2.2V      10.02mA    10.31mA    10.4mA
[Pullup]
|Voltage   I(typ)   I(min)   I(max)
-1.1V     1nA        30.41nA    -1.059nA
432mV     -297.3uA   -442.9uA   -201.3uA
568mV     -2.094mA   -2.448mA   -1.778mA
738mV     -6.208mA   -6.823mA   -5.447mA
976mV     -13.28mA   -14.24mA   -11.72mA
1.316V    -24.43mA   -25.63mA   -21.65mA
1.418V    -27.19mA   -28.13mA   -24.57mA
1.486V    -28.09mA   -29.04mA   -25.91mA
1.554V    -28.31mA   -29.48mA   -26.26mA
1.622V    -28.1mA    -29.61mA   -25.82mA
1.996V    -24.35mA   -28.33mA   -19.63mA
2.2V      -22.77mA   -27.36mA   -17.82mA
[GND_clamp]
|Voltage   I(typ)   I(min)   I(max)
-1.1V     -128.5mA   -147.6mA   -122.6mA
-1.008V   -93.62mA   -112mA     -87.95mA
-962mV    -77.6mA    -95.05mA   -73.96mA
-893mV    -57.36mA   -71.21mA   -60.7mA
-847mV    -48.01mA   -56.81mA   -54.36mA
-801mV    -41.47mA   -44.23mA   -48.33mA
-755mV    -36.02mA   -34.19mA   -42.41mA
-709mV    -30.9mA    -26.94mA   -36.63mA
-525mV    -12.67mA   -10.3mA    -15.49mA
-387mV    -3.615mA   -3.065mA   -4.419mA
-249mV    -281uA     -330.6uA   -301.3uA
1.1V      0A         0A         0A
[POWER_clamp]
|Voltage   I(typ)   I(min)   I(max)
-1.1V     70.27mA    107.3mA    47.25mA
-1.039V   47.68mA    83.93mA    25.86mA
-993mV    31.88mA    66.94mA    12.35mA
-970mV    24.65mA    58.72mA    7.262mA
-947mV    18.06mA    50.74mA    3.761mA
-901mV    7.73mA     35.71mA    987.1uA
-855mV    2.348mA    22.46mA    514uA
-809mV    697.3uA    11.94mA    396.5uA
-763mV    321uA      5.097mA    322.7uA
-717mV    213.8uA    1.813mA    258.1uA
-556mV    65.24uA    79.15uA    81.64uA
1.1V      0A         0A         0A
[Ramp]
| variable   typ   min   max
dV/dt_r   0.204/36.487p   0.198/45.986p   0.217/28.326p
dV/dt_f   0.242/40.804p   0.242/54.455p   0.257/31.161p
R_load = 50.000
[Rising Waveform]
R_fixture= 50.000
V_fixture= 1.100
V_fixture_min= 1.060
V_fixture_max= 1.170
|time   V(typ)   V(min)   V(max)
0s        697.4mV    656.2mV    741mV
136ps     698.6mV    656.8mV    735.9mV
197ps     684.5mV    657.4mV    1.01V
243ps     884.2mV    640.1mV    1.099V
271ps     971mV      630.8mV    1.124V
290ps     1.009V     660.5mV    1.137V
309ps     1.035V     739.7mV    1.147V
364ps     1.073V     937.2mV    1.162V
442ps     1.092V     1.029V     1.168V
1ns       1.1V       1.06V      1.17V
[Rising Waveform]
R_fixture= 50.000
V_fixture= 0.0
V_fixture_min= 0.0
V_fixture_max= 0.0
|time   V(typ)   V(min)   V(max)
0s        2.218uV    17.94uV    414.7nV
139ps     -5.703uV   18.06uV    13.12mV
152ps     -263.9uV   48uV       55.35mV
185ps     2.206mV    34.71uV    301mV
222ps     57.54mV    -417uV     402.7mV
270ps     307.1mV    4.198mV    365.5mV
322ps     371.5mV    80.78mV    361.1mV
367ps     347.2mV    277.5mV    361.1mV
417ps     339.1mV    343.4mV    361.1mV
1ns       340.3mV    329.8mV    361.1mV
[Falling Waveform]
R_fixture= 50.000
V_fixture= 1.100
V_fixture_min= 1.060
V_fixture_max= 1.170
|time   V(typ)   V(min)   V(max)
0s        1.1V       1.06V      1.17V
151ps     1.1V       1.06V      1.163V
203ps     1.099V     1.06V      787.9mV
241ps     1.03V      1.061V     638.9mV
290ps     747.7mV    1.059V     693.2mV
322ps     646.4mV    1.05V      716.8mV
347ps     609.9mV    975.7mV    726.6mV
407ps     660.2mV    713.5mV    736.9mV
475ps     688.1mV    595.8mV    740mV
1ns       697.4mV    656.2mV    741mV
[Falling Waveform]
R_fixture= 50.000
V_fixture= 0.0
V_fixture_min= 0.0
V_fixture_max= 0.0
|time   V(typ)   V(min)   V(max)
0s        340.3mV    329.8mV    361.1mV
132ps     339.3mV    329.3mV    368.5mV
146ps     342mV      328.9mV    324.3mV
192ps     352.6mV    329.1mV    61.41mV
218ps     274.7mV    335mV      20.15mV
252ps     98.87mV    350.1mV    1.571mV
291ps     20.14mV    322.9mV    -1.424mV
358ps     -469.6uV   74.22mV    -116.3uV
407ps     -2.168mV   10.78mV    -11.41uV
1ns       5.13uV     22.01uV    735.3nV
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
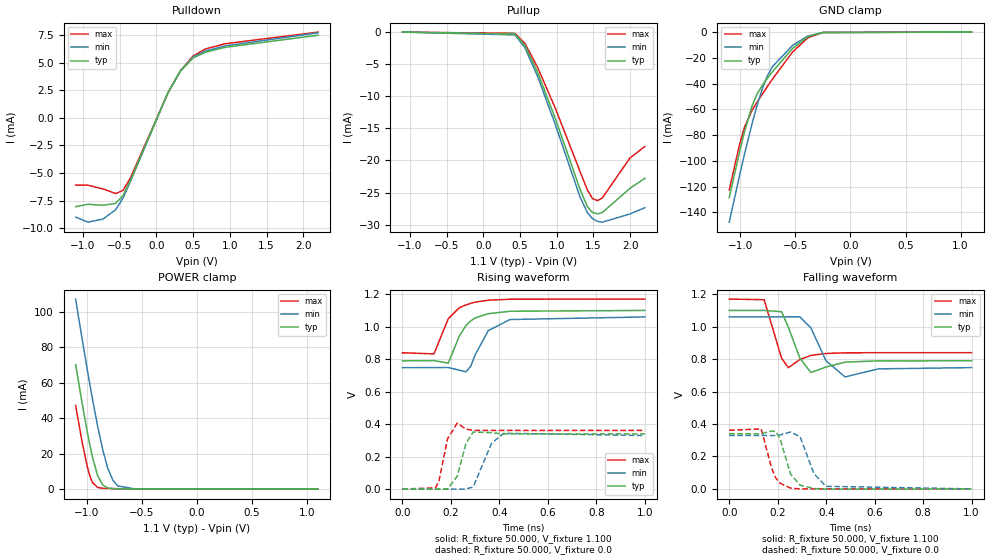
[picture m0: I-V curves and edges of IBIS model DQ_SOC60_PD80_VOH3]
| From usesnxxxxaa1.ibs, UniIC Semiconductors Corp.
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|   Model DQ_SOC60_PD80_VOH3
[Model] DQ_SOC60_PD80_VOH3
Model_type I/O
Polarity   Non-Inverting
Enable   Active-High
Vinl =  0.113V
Vinh =  0.253V
Vmeas =  0.183V
Rref =  50.000
Vref =  0.183V
C_comp   1.110pF   1.087pF   1.118pF
[Model Spec]
Vinh   0.253V   0.247V   0.265V
Vinl   0.113V   0.107V   0.125V
Vmeas   0.183V   NA   NA
Vref   0.183V   NA   NA
Rref   50.000   NA   NA
[Temperature Range]   25.000   0.125k   -40.000
[Voltage Range]   1.100V   1.060V   1.170V
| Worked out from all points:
|   slope of the pulldown table from 0 to 0.165 V, typ, clamps not added: 68.6 ohm
|   GND clamp passes 1 mA (typ) near -0.30 V on its own axis
|   POWER clamp passes 1 mA (typ) near -0.82 V on its own axis
|   rising waveform, R_fixture 50.000, V_fixture 1.100: 20-80 % time 72.8ps typ, 74.3ps min, 72.8ps max; typ from 0.79 V to 1.1 V
|   rising waveform, R_fixture 50.000, V_fixture 0.0: 20-80 % time 36.5ps typ, 45.5ps min, 28.4ps max; typ from 0 V to 0.34 V
|   falling waveform, R_fixture 50.000, V_fixture 1.100: 20-80 % time 42.5ps typ, 55.3ps min, 32.7ps max; typ from 1.1 V to 0.79 V
|   falling waveform, R_fixture 50.000, V_fixture 0.0: 20-80 % time 43.9ps typ, 50ps min, 39.5ps max; typ from 0.34 V to 0 V
[Pulldown]
|Voltage   I(typ)   I(min)   I(max)
-1.1V     -8.06mA    -9.005mA   -6.106mA
-930mV    -7.843mA   -9.47mA    -6.107mA
-726mV    -7.932mA   -9.181mA   -6.449mA
-556mV    -7.761mA   -8.341mA   -6.868mA
-454mV    -7.04mA    -7.266mA   -6.58mA
-352mV    -5.637mA   -5.732mA   -5.417mA
158mV     2.314mA    2.324mA    2.293mA
328mV     4.261mA    4.301mA    4.293mA
498mV     5.443mA    5.524mA    5.628mA
668mV     5.978mA    6.084mA    6.272mA
940mV     6.421mA    6.553mA    6.75mA
2.2V      7.518mA    7.735mA    7.803mA
[Pullup]
|Voltage   I(typ)   I(min)   I(max)
-1.1V     1nA        30.41nA    -1.059nA
432mV     -297.3uA   -442.9uA   -201.3uA
568mV     -2.094mA   -2.448mA   -1.778mA
738mV     -6.208mA   -6.823mA   -5.447mA
976mV     -13.28mA   -14.24mA   -11.72mA
1.316V    -24.43mA   -25.63mA   -21.65mA
1.418V    -27.19mA   -28.13mA   -24.57mA
1.486V    -28.09mA   -29.04mA   -25.91mA
1.554V    -28.31mA   -29.48mA   -26.26mA
1.622V    -28.1mA    -29.61mA   -25.82mA
1.996V    -24.35mA   -28.33mA   -19.63mA
2.2V      -22.77mA   -27.36mA   -17.82mA
[GND_clamp]
|Voltage   I(typ)   I(min)   I(max)
-1.1V     -128.5mA   -147.6mA   -122.6mA
-1.008V   -93.62mA   -112mA     -87.95mA
-962mV    -77.6mA    -95.05mA   -73.96mA
-893mV    -57.36mA   -71.21mA   -60.7mA
-847mV    -48.01mA   -56.81mA   -54.36mA
-801mV    -41.47mA   -44.23mA   -48.33mA
-755mV    -36.02mA   -34.19mA   -42.41mA
-709mV    -30.9mA    -26.94mA   -36.63mA
-525mV    -12.67mA   -10.3mA    -15.49mA
-387mV    -3.615mA   -3.065mA   -4.419mA
-249mV    -281uA     -330.6uA   -301.3uA
1.1V      0A         0A         0A
[POWER_clamp]
|Voltage   I(typ)   I(min)   I(max)
-1.1V     70.27mA    107.3mA    47.25mA
-1.039V   47.68mA    83.93mA    25.86mA
-993mV    31.88mA    66.94mA    12.35mA
-970mV    24.65mA    58.72mA    7.262mA
-947mV    18.06mA    50.74mA    3.761mA
-901mV    7.73mA     35.71mA    987.1uA
-855mV    2.348mA    22.46mA    514uA
-809mV    697.3uA    11.94mA    396.5uA
-763mV    321uA      5.097mA    322.7uA
-717mV    213.8uA    1.813mA    258.1uA
-556mV    65.24uA    79.15uA    81.64uA
1.1V      0A         0A         0A
[Ramp]
| variable   typ   min   max
dV/dt_r   0.204/36.620p   0.198/45.723p   0.217/28.504p
dV/dt_f   0.186/42.751p   0.187/55.978p   0.198/32.699p
R_load = 50.000
[Rising Waveform]
R_fixture= 50.000
V_fixture= 1.100
V_fixture_min= 1.060
V_fixture_max= 1.170
|time   V(typ)   V(min)   V(max)
0s        789.7mV    747.6mV    839.6mV
130ps     791mV      747.9mV    832.3mV
189ps     775.6mV    748.8mV    1.049V
235ps     943.5mV    732mV      1.117V
262ps     1.007V     722.1mV    1.134V
282ps     1.036V     757mV      1.144V
300ps     1.054V     826.6mV    1.151V
354ps     1.08V      975.8mV    1.163V
444ps     1.095V     1.044V     1.169V
1ns       1.1V       1.06V      1.17V
[Rising Waveform]
R_fixture= 50.000
V_fixture= 0.0
V_fixture_min= 0.0
V_fixture_max= 0.0
|time   V(typ)   V(min)   V(max)
0s        2.545uV    20.59uV    475.2nV
137ps     95.77uV    25.53uV    8.072mV
151ps     -199.8uV   59.65uV    51.9mV
186ps     1.16mV     102.8uV    309.3mV
226ps     78.79mV    -454.6uV   405.8mV
262ps     280.8mV    745.3uV    369.5mV
292ps     351.2mV    13.39mV    361.6mV
367ps     347.4mV    280.6mV    361.1mV
418ps     339.1mV    343.8mV    361.1mV
1ns       340.3mV    329.8mV    361.1mV
[Falling Waveform]
R_fixture= 50.000
V_fixture= 1.100
V_fixture_min= 1.060
V_fixture_max= 1.170
|time   V(typ)   V(min)   V(max)
0s        1.1V       1.06V      1.17V
144ps     1.1V       1.06V      1.166V
216ps     1.092V     1.06V      805.4mV
244ps     996.4mV    1.061V     747.3mV
291ps     807.3mV    1.061V     796.8mV
337ps     717mV      992.8mV    822.7mV
399ps     751.1mV    790.1mV    834.7mV
478ps     781.4mV    690.1mV    838.6mV
615ps     789.1mV    739.7mV    839.6mV
1ns       789.7mV    747.5mV    839.6mV
[Falling Waveform]
R_fixture= 50.000
V_fixture= 0.0
V_fixture_min= 0.0
V_fixture_max= 0.0
|time   V(typ)   V(min)   V(max)
0s        340.3mV    329.8mV    361.1mV
132ps     339.2mV    329.3mV    369.7mV
175ps     356.4mV    328.3mV    127.1mV
192ps     353.8mV    329.1mV    66.93mV
210ps     307.5mV    332.5mV    34.57mV
253ps     91.28mV    350.6mV    4.95mV
292ps     22.85mV    322.1mV    114.5uV
349ps     2.413mV    94.91mV    50.38uV
399ps     -1.727mV   15.73mV    21.28uV
1ns       6.029uV    25.23uV    -1.459uV
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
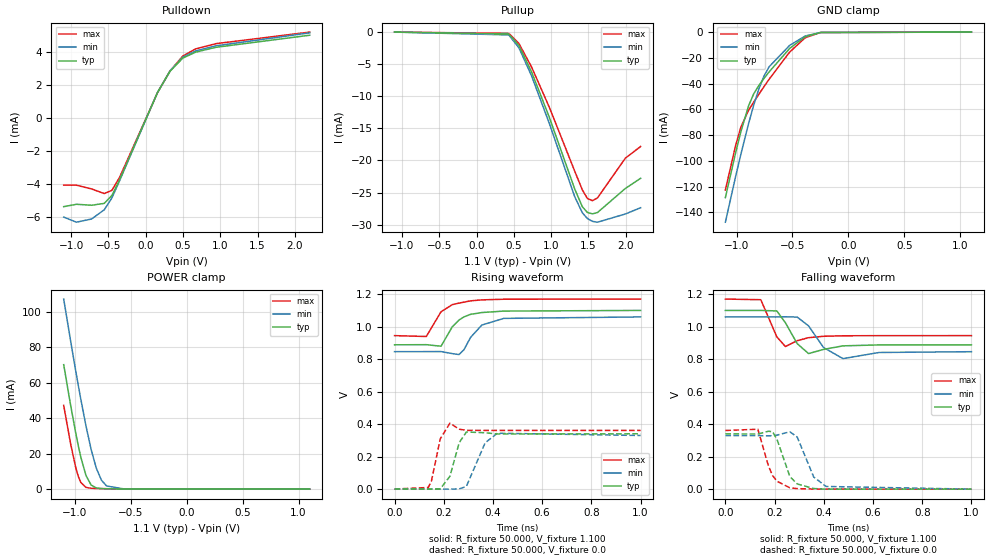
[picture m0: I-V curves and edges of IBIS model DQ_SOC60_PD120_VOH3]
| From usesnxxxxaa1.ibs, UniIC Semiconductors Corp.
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|   Model DQ_SOC60_PD120_VOH3
[Model] DQ_SOC60_PD120_VOH3
Model_type I/O
Polarity   Non-Inverting
Enable   Active-High
Vinl =  0.113V
Vinh =  0.253V
Vmeas =  0.183V
Rref =  50.000
Vref =  0.183V
C_comp   1.110pF   1.087pF   1.118pF
[Model Spec]
Vinh   0.253V   0.247V   0.265V
Vinl   0.113V   0.107V   0.125V
Vmeas   0.183V   NA   NA
Vref   0.183V   NA   NA
Rref   50.000   NA   NA
[Temperature Range]   25.000   0.125k   -40.000
[Voltage Range]   1.100V   1.060V   1.170V
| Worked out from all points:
|   slope of the pulldown table from 0 to 0.165 V, typ, clamps not added: 103 ohm
|   GND clamp passes 1 mA (typ) near -0.30 V on its own axis
|   POWER clamp passes 1 mA (typ) near -0.82 V on its own axis
|   rising waveform, R_fixture 50.000, V_fixture 1.100: 20-80 % time 70.2ps typ, 70.1ps min, 71ps max; typ from 0.888 V to 1.1 V
|   rising waveform, R_fixture 50.000, V_fixture 0.0: 20-80 % time 37.3ps typ, 46.5ps min, 28.7ps max; typ from 0 V to 0.34 V
|   falling waveform, R_fixture 50.000, V_fixture 1.100: 20-80 % time 43ps typ, 55.7ps min, 32.9ps max; typ from 1.1 V to 0.888 V
|   falling waveform, R_fixture 50.000, V_fixture 0.0: 20-80 % time 49.5ps typ, 54.5ps min, 46.1ps max; typ from 0.34 V to 0 V
[Pulldown]
|Voltage   I(typ)   I(min)   I(max)
-1.1V     -5.373mA   -6.003mA   -4.071mA
-930mV    -5.229mA   -6.314mA   -4.072mA
-726mV    -5.288mA   -6.12mA    -4.3mA
-556mV    -5.174mA   -5.561mA   -4.579mA
-454mV    -4.694mA   -4.844mA   -4.386mA
-352mV    -3.758mA   -3.821mA   -3.611mA
158mV     1.543mA    1.549mA    1.529mA
328mV     2.841mA    2.867mA    2.862mA
498mV     3.628mA    3.683mA    3.752mA
668mV     3.985mA    4.056mA    4.181mA
940mV     4.28mA     4.369mA    4.5mA
2.2V      5.012mA    5.157mA    5.202mA
[Pullup]
|Voltage   I(typ)   I(min)   I(max)
-1.1V     1nA        30.41nA    -1.059nA
432mV     -297.3uA   -442.9uA   -201.3uA
568mV     -2.094mA   -2.448mA   -1.778mA
738mV     -6.208mA   -6.823mA   -5.447mA
976mV     -13.28mA   -14.24mA   -11.72mA
1.316V    -24.43mA   -25.63mA   -21.65mA
1.418V    -27.19mA   -28.13mA   -24.57mA
1.486V    -28.09mA   -29.04mA   -25.91mA
1.554V    -28.31mA   -29.48mA   -26.26mA
1.622V    -28.1mA    -29.61mA   -25.82mA
1.996V    -24.35mA   -28.33mA   -19.63mA
2.2V      -22.77mA   -27.36mA   -17.82mA
[GND_clamp]
|Voltage   I(typ)   I(min)   I(max)
-1.1V     -128.5mA   -147.6mA   -122.6mA
-1.008V   -93.62mA   -112mA     -87.95mA
-962mV    -77.6mA    -95.05mA   -73.96mA
-893mV    -57.36mA   -71.21mA   -60.7mA
-847mV    -48.01mA   -56.81mA   -54.36mA
-801mV    -41.47mA   -44.23mA   -48.33mA
-755mV    -36.02mA   -34.19mA   -42.41mA
-709mV    -30.9mA    -26.94mA   -36.63mA
-525mV    -12.67mA   -10.3mA    -15.49mA
-387mV    -3.615mA   -3.065mA   -4.419mA
-249mV    -281uA     -330.6uA   -301.3uA
1.1V      0A         0A         0A
[POWER_clamp]
|Voltage   I(typ)   I(min)   I(max)
-1.1V     70.27mA    107.3mA    47.25mA
-1.039V   47.68mA    83.93mA    25.86mA
-993mV    31.88mA    66.94mA    12.35mA
-970mV    24.65mA    58.72mA    7.262mA
-947mV    18.06mA    50.74mA    3.761mA
-901mV    7.73mA     35.71mA    987.1uA
-855mV    2.348mA    22.46mA    514uA
-809mV    697.3uA    11.94mA    396.5uA
-763mV    321uA      5.097mA    322.7uA
-717mV    213.8uA    1.813mA    258.1uA
-556mV    65.24uA    79.15uA    81.64uA
1.1V      0A         0A         0A
[Ramp]
| variable   typ   min   max
dV/dt_r   0.204/37.225p   0.198/47.308p   0.217/29.060p
dV/dt_f   0.127/43.073p   0.128/56.723p   0.135/32.870p
R_load = 50.000
[Rising Waveform]
R_fixture= 50.000
V_fixture= 1.100
V_fixture_min= 1.060
V_fixture_max= 1.170
|time   V(typ)   V(min)   V(max)
0s        888.3mV    846.1mV    944.8mV
129ps     889.1mV    846.4mV    939.5mV
189ps     879.7mV    846.8mV    1.092V
235ps     1V         833.9mV    1.136V
262ps     1.041V     828.4mV    1.145V
282ps     1.06V      857.8mV    1.151V
309ps     1.076V     934.1mV    1.159V
355ps     1.087V     1.01V      1.165V
444ps     1.096V     1.051V     1.169V
1ns       1.1V       1.06V      1.17V
[Rising Waveform]
R_fixture= 50.000
V_fixture= 0.0
V_fixture_min= 0.0
V_fixture_max= 0.0
|time   V(typ)   V(min)   V(max)
0s        2.986uV    24.15uV    556.4nV
137ps     44.64uV    52.89uV    9.622mV
150ps     -326.1uV   84.95uV    50.07mV
186ps     1.371mV    91.1uV     309.7mV
225ps     78.64mV    -709.1uV   405.5mV
263ps     286.3mV    996.1uV    368.5mV
292ps     351.3mV    16.35mV    361.6mV
368ps     346.7mV    284.5mV    361.1mV
418ps     339.1mV    343.8mV    361.1mV
1ns       340.3mV    329.8mV    361.1mV
[Falling Waveform]
R_fixture= 50.000
V_fixture= 1.100
V_fixture_min= 1.060
V_fixture_max= 1.170
|time   V(typ)   V(min)   V(max)
0s        1.1V       1.06V      1.17V
144ps     1.1V       1.06V      1.166V
209ps     1.097V     1.06V      937.5mV
244ps     1.024V     1.061V     877.9mV
292ps     895.5mV    1.059V     914mV
338ps     834.5mV    1.005V     932.2mV
399ps     860.1mV    871.6mV    940.9mV
478ps     882mV      803.5mV    944mV
625ps     887.9mV    841.1mV    944.7mV
1ns       888.3mV    846.1mV    944.8mV
[Falling Waveform]
R_fixture= 50.000
V_fixture= 0.0
V_fixture_min= 0.0
V_fixture_max= 0.0
|time   V(typ)   V(min)   V(max)
0s        340.3mV    329.8mV    361.1mV
132ps     339.2mV    329.3mV    368.8mV
175ps     356.5mV    328.3mV    142.8mV
192ps     353.3mV    329.1mV    83.48mV
210ps     305.6mV    332.6mV    48.38mV
262ps     77.8mV     353.2mV    8.426mV
292ps     32.12mV    320.4mV    3.33mV
359ps     3.804mV    74.83mV    642.9uV
409ps     -80.15uV   16.59mV    190.9uV
1ns       1.045uV    29.62uV    1.033uV
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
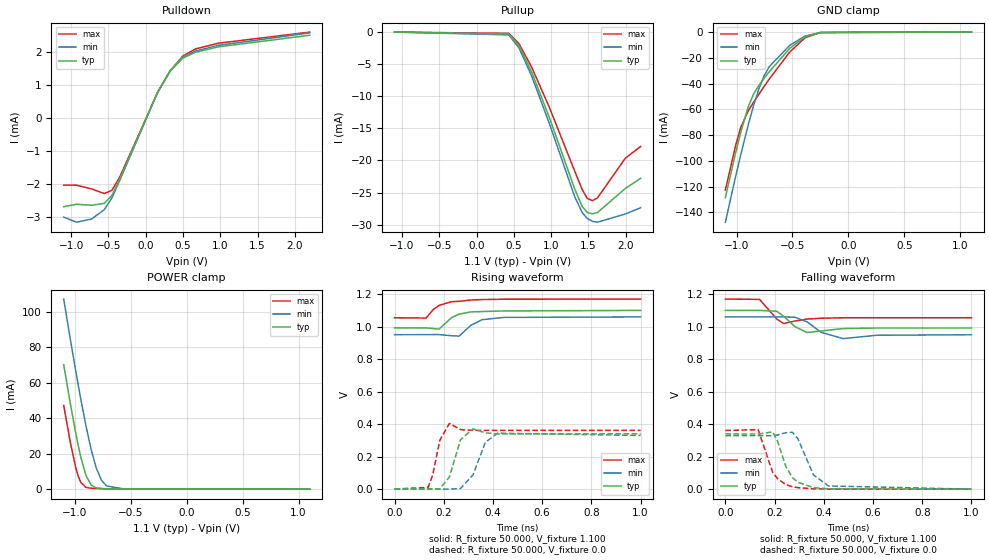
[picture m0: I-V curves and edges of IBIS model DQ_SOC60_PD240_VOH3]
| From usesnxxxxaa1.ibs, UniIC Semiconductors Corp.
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|   Model DQ_SOC60_PD240_VOH3
[Model] DQ_SOC60_PD240_VOH3
Model_type I/O
Polarity   Non-Inverting
Enable   Active-High
Vinl =  0.113V
Vinh =  0.253V
Vmeas =  0.183V
Rref =  50.000
Vref =  0.183V
C_comp   1.110pF   1.087pF   1.118pF
[Model Spec]
Vinh   0.253V   0.247V   0.265V
Vinl   0.113V   0.107V   0.125V
Vmeas   0.183V   NA   NA
Vref   0.183V   NA   NA
Rref   50.000   NA   NA
[Temperature Range]   25.000   0.125k   -40.000
[Voltage Range]   1.100V   1.060V   1.170V
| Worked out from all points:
|   slope of the pulldown table from 0 to 0.165 V, typ, clamps not added: 206 ohm
|   GND clamp passes 1 mA (typ) near -0.30 V on its own axis
|   POWER clamp passes 1 mA (typ) near -0.82 V on its own axis
|   rising waveform, R_fixture 50.000, V_fixture 1.100: 20-80 % time 60.5ps typ, 56.2ps min, 65.3ps max; typ from 0.992 V to 1.1 V
|   rising waveform, R_fixture 50.000, V_fixture 0.0: 20-80 % time 37.9ps typ, 47.6ps min, 29.1ps max; typ from 0 V to 0.34 V
|   falling waveform, R_fixture 50.000, V_fixture 1.100: 20-80 % time 43.6ps typ, 56.7ps min, 33.4ps max; typ from 1.1 V to 0.992 V
|   falling waveform, R_fixture 50.000, V_fixture 0.0: 20-80 % time 57.5ps typ, 60.3ps min, 56.2ps max; typ from 0.34 V to 0 V
[Pulldown]
|Voltage   I(typ)   I(min)   I(max)
-1.1V     -2.687mA   -3.002mA   -2.035mA
-930mV    -2.614mA   -3.157mA   -2.036mA
-726mV    -2.644mA   -3.06mA    -2.15mA
-556mV    -2.587mA   -2.78mA    -2.289mA
-454mV    -2.347mA   -2.422mA   -2.193mA
-352mV    -1.879mA   -1.911mA   -1.806mA
158mV     771.5uA    774.7uA    764.3uA
328mV     1.42mA     1.434mA    1.431mA
498mV     1.814mA    1.841mA    1.876mA
668mV     1.992mA    2.028mA    2.091mA
974mV     2.154mA    2.199mA    2.264mA
2.2V      2.506mA    2.578mA    2.601mA
[Pullup]
|Voltage   I(typ)   I(min)   I(max)
-1.1V     1nA        30.41nA    -1.059nA
432mV     -297.3uA   -442.9uA   -201.3uA
568mV     -2.094mA   -2.448mA   -1.778mA
738mV     -6.208mA   -6.823mA   -5.447mA
976mV     -13.28mA   -14.24mA   -11.72mA
1.316V    -24.43mA   -25.63mA   -21.65mA
1.418V    -27.19mA   -28.13mA   -24.57mA
1.486V    -28.09mA   -29.04mA   -25.91mA
1.554V    -28.31mA   -29.48mA   -26.26mA
1.622V    -28.1mA    -29.61mA   -25.82mA
1.996V    -24.35mA   -28.33mA   -19.63mA
2.2V      -22.77mA   -27.36mA   -17.82mA
[GND_clamp]
|Voltage   I(typ)   I(min)   I(max)
-1.1V     -128.5mA   -147.6mA   -122.6mA
-1.008V   -93.62mA   -112mA     -87.95mA
-962mV    -77.6mA    -95.05mA   -73.96mA
-893mV    -57.36mA   -71.21mA   -60.7mA
-847mV    -48.01mA   -56.81mA   -54.36mA
-801mV    -41.47mA   -44.23mA   -48.33mA
-755mV    -36.02mA   -34.19mA   -42.41mA
-709mV    -30.9mA    -26.94mA   -36.63mA
-525mV    -12.67mA   -10.3mA    -15.49mA
-387mV    -3.615mA   -3.065mA   -4.419mA
-249mV    -281uA     -330.6uA   -301.3uA
1.1V      0A         0A         0A
[POWER_clamp]
|Voltage   I(typ)   I(min)   I(max)
-1.1V     70.27mA    107.3mA    47.25mA
-1.039V   47.68mA    83.93mA    25.86mA
-993mV    31.88mA    66.94mA    12.35mA
-970mV    24.65mA    58.72mA    7.262mA
-947mV    18.06mA    50.74mA    3.761mA
-901mV    7.73mA     35.71mA    987.1uA
-855mV    2.348mA    22.46mA    514uA
-809mV    697.3uA    11.94mA    396.5uA
-763mV    321uA      5.097mA    322.7uA
-717mV    213.8uA    1.813mA    258.1uA
-556mV    65.24uA    79.15uA    81.64uA
1.1V      0A         0A         0A
[Ramp]
| variable   typ   min   max
dV/dt_r   0.204/38.016p   0.198/48.780p   0.217/29.398p
dV/dt_f   64.848m/44.030p   65.673m/57.481p   68.888m/33.584p
R_load = 50.000
[Rising Waveform]
R_fixture= 50.000
V_fixture= 1.100
V_fixture_min= 1.060
V_fixture_max= 1.170
|time   V(typ)   V(min)   V(max)
0s        991.9mV    950.6mV    1.055V
128ps     992.4mV    950.7mV    1.053V
158ps     988.3mV    951.2mV    1.106V
181ps     985mV      951.2mV    1.131V
232ps     1.056V     944mV      1.154V
262ps     1.077V     941.9mV    1.156V
310ps     1.091V     1.008V     1.164V
356ps     1.093V     1.043V     1.167V
445ps     1.097V     1.057V     1.169V
1ns       1.1V       1.06V      1.17V
[Rising Waveform]
R_fixture= 50.000
V_fixture= 0.0
V_fixture_min= 0.0
V_fixture_max= 0.0
|time   V(typ)   V(min)   V(max)
0s        3.61uV     29.2uV     671nV
136ps     -4.338uV   80.83uV    9.469mV
155ps     -709.8uV   121.7uV    84.21mV
184ps     986.8uV    78.25uV    300.7mV
223ps     74.46mV    -961.2uV   404.1mV
268ps     302.9mV    2.942mV    366mV
319ps     370.7mV    87.36mV    361.1mV
369ps     345.8mV    287.6mV    361.1mV
419ps     339.2mV    344.1mV    361.1mV
1ns       340.3mV    329.8mV    361.1mV
[Falling Waveform]
R_fixture= 50.000
V_fixture= 1.100
V_fixture_min= 1.060
V_fixture_max= 1.170
|time   V(typ)   V(min)   V(max)
0s        1.1V       1.06V      1.17V
139ps     1.1V       1.06V      1.168V
209ps     1.095V     1.06V      1.047V
237ps     1.064V     1.061V     1.019V
283ps     999.9mV    1.058V     1.035V
332ps     964.1mV    1.03V      1.047V
389ps     973.6mV    965.5mV    1.052V
478ps     988.4mV    926.6mV    1.055V
616ps     991.7mV    947.3mV    1.055V
1ns       991.9mV    950.5mV    1.055V
[Falling Waveform]
R_fixture= 50.000
V_fixture= 0.0
V_fixture_min= 0.0
V_fixture_max= 0.0
|time   V(typ)   V(min)   V(max)
0s        340.3mV    329.8mV    361.1mV
133ps     339.4mV    329.3mV    366.4mV
192ps     352.5mV    329.1mV    104.5mV
212ps     295.3mV    333.2mV    64.59mV
246ps     138.4mV    347.8mV    28.1mV
272ps     72.35mV    350.5mV    14.96mV
295ps     42mV       309.3mV    9.158mV
358ps     9.717mV    87.52mV    2.481mV
419ps     2.17mV     19.79mV    700.2uV
1ns       8.799uV    35.86uV    1.336uV
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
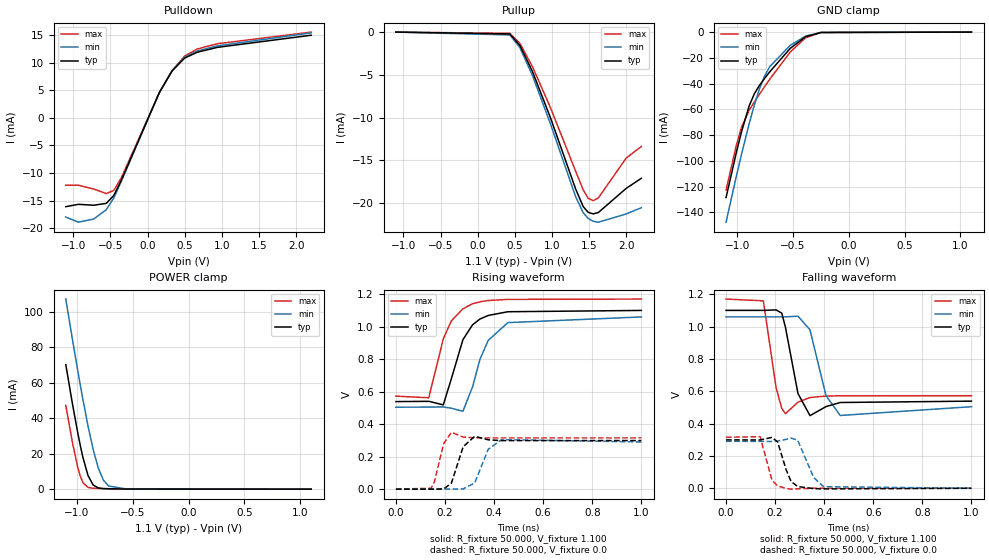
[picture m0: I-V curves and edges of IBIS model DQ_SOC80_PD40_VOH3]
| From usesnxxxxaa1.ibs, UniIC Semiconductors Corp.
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|   Model DQ_SOC80_PD40_VOH3
[Model] DQ_SOC80_PD40_VOH3
Model_type I/O
Polarity   Non-Inverting
Enable   Active-High
Vinl =  0.113V
Vinh =  0.253V
Vmeas =  0.183V
Rref =  50.000
Vref =  0.183V
C_comp   1.110pF   1.087pF   1.118pF
[Model Spec]
Vinh   0.253V   0.247V   0.265V
Vinl   0.113V   0.107V   0.125V
Vmeas   0.183V   NA   NA
Vref   0.183V   NA   NA
Rref   50.000   NA   NA
[Temperature Range]   25.000   0.125k   -40.000
[Voltage Range]   1.100V   1.060V   1.170V
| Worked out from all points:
|   slope of the pulldown table from 0 to 0.165 V, typ, clamps not added: 34.3 ohm
|   GND clamp passes 1 mA (typ) near -0.30 V on its own axis
|   POWER clamp passes 1 mA (typ) near -0.82 V on its own axis
|   rising waveform, R_fixture 50.000, V_fixture 1.100: 20-80 % time 76.9ps typ, 81.2ps min, 75.6ps max; typ from 0.539 V to 1.1 V
|   rising waveform, R_fixture 50.000, V_fixture 0.0: 20-80 % time 35.7ps typ, 44.3ps min, 28.7ps max; typ from 0 V to 0.299 V
|   falling waveform, R_fixture 50.000, V_fixture 1.100: 20-80 % time 39.2ps typ, 50.8ps min, 30.2ps max; typ from 1.1 V to 0.539 V
|   falling waveform, R_fixture 50.000, V_fixture 0.0: 20-80 % time 36.6ps typ, 44.3ps min, 29.4ps max; typ from 0.299 V to 0 V
[Pulldown]
|Voltage   I(typ)   I(min)   I(max)
-1.1V     -16.12mA   -18.01mA   -12.21mA
-930mV    -15.69mA   -18.94mA   -12.21mA
-726mV    -15.86mA   -18.36mA   -12.9mA
-556mV    -15.52mA   -16.68mA   -13.74mA
-454mV    -14.08mA   -14.53mA   -13.16mA
-352mV    -11.27mA   -11.46mA   -10.83mA
158mV     4.629mA    4.648mA    4.586mA
328mV     8.522mA    8.602mA    8.586mA
498mV     10.89mA    11.05mA    11.26mA
668mV     11.95mA    12.17mA    12.54mA
940mV     12.84mA    13.11mA    13.5mA
2.2V      15.04mA    15.47mA    15.61mA
[Pullup]
|Voltage   I(typ)   I(min)   I(max)
-1.1V     1nA        20.18nA    0A
432mV     -223uA     -332.2uA   -150.9uA
568mV     -1.57mA    -1.836mA   -1.333mA
738mV     -4.656mA   -5.117mA   -4.085mA
976mV     -9.963mA   -10.68mA   -8.789mA
1.316V    -18.32mA   -19.22mA   -16.24mA
1.418V    -20.39mA   -21.1mA    -18.43mA
1.486V    -21.07mA   -21.78mA   -19.43mA
1.554V    -21.24mA   -22.11mA   -19.69mA
1.622V    -21.08mA   -22.21mA   -19.37mA
1.996V    -18.26mA   -21.25mA   -14.72mA
2.2V      -17.08mA   -20.52mA   -13.36mA
[GND_clamp]
|Voltage   I(typ)   I(min)   I(max)
-1.1V     -128.5mA   -147.6mA   -122.6mA
-1.008V   -93.62mA   -112mA     -87.95mA
-962mV    -77.6mA    -95.05mA   -73.96mA
-893mV    -57.36mA   -71.21mA   -60.7mA
-847mV    -48.01mA   -56.81mA   -54.36mA
-801mV    -41.47mA   -44.23mA   -48.33mA
-755mV    -36.02mA   -34.19mA   -42.41mA
-709mV    -30.9mA    -26.94mA   -36.63mA
-525mV    -12.67mA   -10.3mA    -15.49mA
-387mV    -3.615mA   -3.065mA   -4.419mA
-249mV    -281uA     -330.6uA   -301.3uA
1.1V      0A         0A         0A
[POWER_clamp]
|Voltage   I(typ)   I(min)   I(max)
-1.1V     70.27mA    107.3mA    47.25mA
-1.039V   47.68mA    83.93mA    25.86mA
-993mV    31.88mA    66.94mA    12.35mA
-970mV    24.65mA    58.72mA    7.262mA
-947mV    18.06mA    50.74mA    3.761mA
-901mV    7.73mA     35.71mA    987.1uA
-855mV    2.348mA    22.46mA    514uA
-809mV    697.3uA    11.94mA    396.5uA
-763mV    321uA      5.097mA    322.7uA
-717mV    213.8uA    1.813mA    258.1uA
-556mV    65.24uA    79.15uA    81.64uA
1.1V      0A         0A         0A
[Ramp]
| variable   typ   min   max
dV/dt_r   0.179/35.881p   0.174/44.542p   0.189/28.904p
dV/dt_f   0.337/39.562p   0.333/51.326p   0.359/30.225p
R_load = 50.000
[Rising Waveform]
R_fixture= 50.000
V_fixture= 1.100
V_fixture_min= 1.060
V_fixture_max= 1.170
|time   V(typ)   V(min)   V(max)
0s        538.9mV    504.5mV    572.5mV
134ps     540.6mV    504.9mV    562.5mV
193ps     518.8mV    506.4mV    925.7mV
226ps     680.2mV    497.8mV    1.036V
273ps     920.2mV    479.4mV    1.11V
312ps     1.011V     628.6mV    1.141V
342ps     1.047V     797.6mV    1.153V
376ps     1.069V     915.5mV    1.161V
456ps     1.092V     1.025V     1.168V
1ns       1.1V       1.06V      1.17V
[Rising Waveform]
R_fixture= 50.000
V_fixture= 0.0
V_fixture_min= 0.0
V_fixture_max= 0.0
|time   V(typ)   V(min)   V(max)
0s        1.764uV    14.27uV    330.5nV
143ps     200.5uV    -33.5uV    5.78mV
156ps     199.8uV    -4.366uV   41.69mV
195ps     1.388mV    115uV      281.2mV
226ps     37.06mV    228.2uV    350.2mV
274ps     261mV      1.524mV    320.4mV
321ps     325.4mV    37.81mV    316mV
376ps     303.8mV    245.1mV    315.5mV
431ps     298.8mV    305mV      315.5mV
1ns       299.2mV    290.5mV    315.5mV
[Falling Waveform]
R_fixture= 50.000
V_fixture= 1.100
V_fixture_min= 1.060
V_fixture_max= 1.170
|time   V(typ)   V(min)   V(max)
0s        1.1V       1.06V      1.17V
152ps     1.1V       1.06V      1.159V
204ps     1.103V     1.06V      621.6mV
227ps     1.083V     1.06V      493.9mV
242ps     996mV      1.06V      461.2mV
293ps     586.1mV    1.064V     532.5mV
342ps     449.1mV    980.1mV    561.1mV
407ps     504.8mV    573.9mV    570.2mV
465ps     530.4mV    450.1mV    571.9mV
1ns       538.8mV    504.5mV    572.5mV
[Falling Waveform]
R_fixture= 50.000
V_fixture= 0.0
V_fixture_min= 0.0
V_fixture_max= 0.0
|time   V(typ)   V(min)   V(max)
0s        299.2mV    290.5mV    315.5mV
139ps     298.7mV    289.9mV    318.9mV
187ps     314.7mV    289.4mV    50.48mV
210ps     286.8mV    291.8mV    14.5mV
245ps     113.8mV    302.7mV    -1.054mV
265ps     41.9mV     310.5mV    -5.517mV
292ps     10.8mV     296.6mV    -2.759mV
357ps     -2.053mV   66.77mV    -141uV
397ps     -3.938mV   9.846mV    -16.21uV
1ns       3.88uV     17.66uV    1.711uV
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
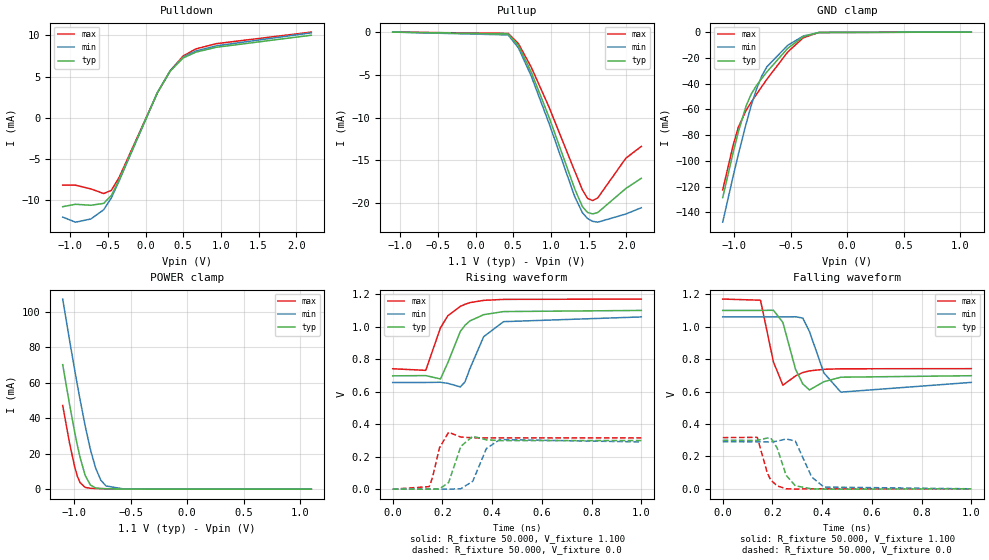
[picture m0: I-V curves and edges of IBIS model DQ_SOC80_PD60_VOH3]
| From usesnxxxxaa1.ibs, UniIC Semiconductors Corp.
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|   Model DQ_SOC80_PD60_VOH3
[Model] DQ_SOC80_PD60_VOH3
Model_type I/O
Polarity   Non-Inverting
Enable   Active-High
Vinl =  0.113V
Vinh =  0.253V
Vmeas =  0.183V
Rref =  50.000
Vref =  0.183V
C_comp   1.110pF   1.087pF   1.118pF
[Model Spec]
Vinh   0.253V   0.247V   0.265V
Vinl   0.113V   0.107V   0.125V
Vmeas   0.183V   NA   NA
Vref   0.183V   NA   NA
Rref   50.000   NA   NA
[Temperature Range]   25.000   0.125k   -40.000
[Voltage Range]   1.100V   1.060V   1.170V
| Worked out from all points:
|   slope of the pulldown table from 0 to 0.165 V, typ, clamps not added: 51.4 ohm
|   GND clamp passes 1 mA (typ) near -0.30 V on its own axis
|   POWER clamp passes 1 mA (typ) near -0.82 V on its own axis
|   rising waveform, R_fixture 50.000, V_fixture 1.100: 20-80 % time 76ps typ, 79.6ps min, 75.2ps max; typ from 0.697 V to 1.1 V
|   rising waveform, R_fixture 50.000, V_fixture 0.0: 20-80 % time 36.6ps typ, 45.5ps min, 29.1ps max; typ from 0 V to 0.299 V
|   falling waveform, R_fixture 50.000, V_fixture 1.100: 20-80 % time 40.3ps typ, 53.4ps min, 31ps max; typ from 1.1 V to 0.697 V
|   falling waveform, R_fixture 50.000, V_fixture 0.0: 20-80 % time 41.5ps typ, 48.9ps min, 35.1ps max; typ from 0.299 V to 0 V
[Pulldown]
|Voltage   I(typ)   I(min)   I(max)
-1.1V     -10.75mA   -12.01mA   -8.142mA
-930mV    -10.46mA   -12.63mA   -8.143mA
-726mV    -10.58mA   -12.24mA   -8.599mA
-556mV    -10.35mA   -11.12mA   -9.157mA
-454mV    -9.387mA   -9.688mA   -8.773mA
-352mV    -7.516mA   -7.642mA   -7.222mA
158mV     3.086mA    3.099mA    3.057mA
328mV     5.681mA    5.734mA    5.724mA
498mV     7.257mA    7.365mA    7.504mA
668mV     7.97mA     8.112mA    8.363mA
940mV     8.561mA    8.737mA    9mA
2.2V      10.02mA    10.31mA    10.4mA
[Pullup]
|Voltage   I(typ)   I(min)   I(max)
-1.1V     1nA        20.18nA    0A
432mV     -223uA     -332.2uA   -150.9uA
568mV     -1.57mA    -1.836mA   -1.333mA
738mV     -4.656mA   -5.117mA   -4.085mA
976mV     -9.963mA   -10.68mA   -8.789mA
1.316V    -18.32mA   -19.22mA   -16.24mA
1.418V    -20.39mA   -21.1mA    -18.43mA
1.486V    -21.07mA   -21.78mA   -19.43mA
1.554V    -21.24mA   -22.11mA   -19.69mA
1.622V    -21.08mA   -22.21mA   -19.37mA
1.996V    -18.26mA   -21.25mA   -14.72mA
2.2V      -17.08mA   -20.52mA   -13.36mA
[GND_clamp]
|Voltage   I(typ)   I(min)   I(max)
-1.1V     -128.5mA   -147.6mA   -122.6mA
-1.008V   -93.62mA   -112mA     -87.95mA
-962mV    -77.6mA    -95.05mA   -73.96mA
-893mV    -57.36mA   -71.21mA   -60.7mA
-847mV    -48.01mA   -56.81mA   -54.36mA
-801mV    -41.47mA   -44.23mA   -48.33mA
-755mV    -36.02mA   -34.19mA   -42.41mA
-709mV    -30.9mA    -26.94mA   -36.63mA
-525mV    -12.67mA   -10.3mA    -15.49mA
-387mV    -3.615mA   -3.065mA   -4.419mA
-249mV    -281uA     -330.6uA   -301.3uA
1.1V      0A         0A         0A
[POWER_clamp]
|Voltage   I(typ)   I(min)   I(max)
-1.1V     70.27mA    107.3mA    47.25mA
-1.039V   47.68mA    83.93mA    25.86mA
-993mV    31.88mA    66.94mA    12.35mA
-970mV    24.65mA    58.72mA    7.262mA
-947mV    18.06mA    50.74mA    3.761mA
-901mV    7.73mA     35.71mA    987.1uA
-855mV    2.348mA    22.46mA    514uA
-809mV    697.3uA    11.94mA    396.5uA
-763mV    321uA      5.097mA    322.7uA
-717mV    213.8uA    1.813mA    258.1uA
-556mV    65.24uA    79.15uA    81.64uA
1.1V      0A         0A         0A
[Ramp]
| variable   typ   min   max
dV/dt_r   0.179/36.904p   0.174/46.516p   0.189/29.583p
dV/dt_f   0.242/40.692p   0.242/54.110p   0.257/31.171p
R_load = 50.000
[Rising Waveform]
R_fixture= 50.000
V_fixture= 1.100
V_fixture_min= 1.060
V_fixture_max= 1.170
|time   V(typ)   V(min)   V(max)
0s        697.4mV    656.2mV    741mV
133ps     698.9mV    656.7mV    731.2mV
192ps     678.3mV    657.9mV    992.6mV
222ps     779.2mV    651.2mV    1.068V
272ps     970.8mV    629.3mV    1.125V
291ps     1.009V     660.6mV    1.138V
310ps     1.035V     739.8mV    1.148V
366ps     1.074V     938.6mV    1.162V
446ps     1.093V     1.031V     1.168V
1ns       1.1V       1.06V      1.17V
[Rising Waveform]
R_fixture= 50.000
V_fixture= 0.0
V_fixture_min= 0.0
V_fixture_max= 0.0
|time   V(typ)   V(min)   V(max)
0s        2.218uV    17.94uV    414.7nV
147ps     35.54uV    16.27uV    15.49mV
160ps     -118.8uV   35.32uV    71.34mV
188ps     1.23mV     56.87uV    254.3mV
225ps     41.09mV    -106.5uV   350mV
274ps     263.1mV    2.517mV    320.6mV
322ps     325.8mV    48.72mV    316mV
377ps     303.4mV    250.2mV    315.5mV
431ps     298.8mV    305.1mV    315.5mV
1ns       299.2mV    290.5mV    315.5mV
[Falling Waveform]
R_fixture= 50.000
V_fixture= 1.100
V_fixture_min= 1.060
V_fixture_max= 1.170
|time   V(typ)   V(min)   V(max)
0s        1.1V       1.06V      1.17V
152ps     1.1V       1.06V      1.163V
204ps     1.101V     1.06V      782.6mV
242ps     1.026V     1.06V      638.6mV
293ps     736.6mV    1.061V     696.3mV
322ps     646.9mV    1.053V     716.8mV
349ps     609.5mV    969.5mV    727.2mV
407ps     660.4mV    714.8mV    736.9mV
475ps     688.2mV    596.1mV    740mV
1ns       697.4mV    656.2mV    741mV
[Falling Waveform]
R_fixture= 50.000
V_fixture= 0.0
V_fixture_min= 0.0
V_fixture_max= 0.0
|time   V(typ)   V(min)   V(max)
0s        299.2mV    290.5mV    315.5mV
139ps     298.7mV    289.9mV    317.5mV
179ps     312.9mV    289.3mV    99.41mV
193ps     313.5mV    289.7mV    54.56mV
219ps     252.4mV    293.9mV    17.96mV
255ps     83.43mV    307.3mV    282.8uV
292ps     18.88mV    294.5mV    -1.478mV
358ps     -512.5uV   72.77mV    -128.5uV
407ps     -2.187mV   10.84mV    -13.51uV
1ns       5.013uV    22.11uV    2.288uV
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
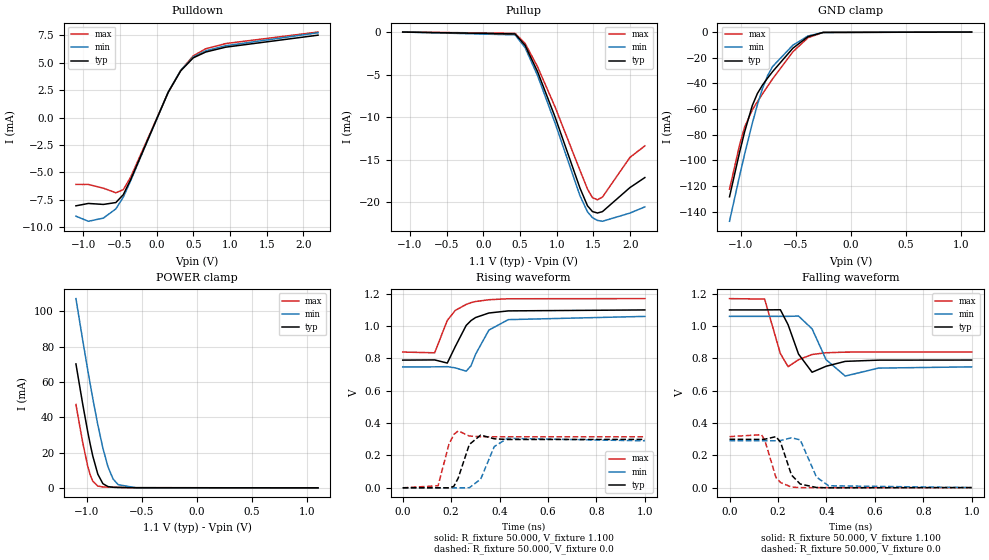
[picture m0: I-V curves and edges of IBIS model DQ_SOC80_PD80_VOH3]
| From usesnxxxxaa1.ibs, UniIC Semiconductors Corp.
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|   Model DQ_SOC80_PD80_VOH3
[Model] DQ_SOC80_PD80_VOH3
Model_type I/O
Polarity   Non-Inverting
Enable   Active-High
Vinl =  0.113V
Vinh =  0.253V
Vmeas =  0.183V
Rref =  50.000
Vref =  0.183V
C_comp   1.110pF   1.087pF   1.118pF
[Model Spec]
Vinh   0.253V   0.247V   0.265V
Vinl   0.113V   0.107V   0.125V
Vmeas   0.183V   NA   NA
Vref   0.183V   NA   NA
Rref   50.000   NA   NA
[Temperature Range]   25.000   0.125k   -40.000
[Voltage Range]   1.100V   1.060V   1.170V
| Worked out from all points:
|   slope of the pulldown table from 0 to 0.165 V, typ, clamps not added: 68.6 ohm
|   GND clamp passes 1 mA (typ) near -0.30 V on its own axis
|   POWER clamp passes 1 mA (typ) near -0.82 V on its own axis
|   rising waveform, R_fixture 50.000, V_fixture 1.100: 20-80 % time 73.7ps typ, 75.7ps min, 73.2ps max; typ from 0.79 V to 1.1 V
|   rising waveform, R_fixture 50.000, V_fixture 0.0: 20-80 % time 36.9ps typ, 45.3ps min, 29.4ps max; typ from 0 V to 0.299 V
|   falling waveform, R_fixture 50.000, V_fixture 1.100: 20-80 % time 42.4ps typ, 55.1ps min, 32.6ps max; typ from 1.1 V to 0.79 V
|   falling waveform, R_fixture 50.000, V_fixture 0.0: 20-80 % time 43.1ps typ, 49ps min, 38.8ps max; typ from 0.299 V to 0 V
[Pulldown]
|Voltage   I(typ)   I(min)   I(max)
-1.1V     -8.06mA    -9.005mA   -6.106mA
-930mV    -7.843mA   -9.47mA    -6.107mA
-726mV    -7.932mA   -9.181mA   -6.449mA
-556mV    -7.761mA   -8.341mA   -6.868mA
-454mV    -7.04mA    -7.266mA   -6.58mA
-352mV    -5.637mA   -5.732mA   -5.417mA
158mV     2.314mA    2.324mA    2.293mA
328mV     4.261mA    4.301mA    4.293mA
498mV     5.443mA    5.524mA    5.628mA
668mV     5.978mA    6.084mA    6.272mA
940mV     6.421mA    6.553mA    6.75mA
2.2V      7.518mA    7.735mA    7.803mA
[Pullup]
|Voltage   I(typ)   I(min)   I(max)
-1.1V     1nA        20.18nA    0A
432mV     -223uA     -332.2uA   -150.9uA
568mV     -1.57mA    -1.836mA   -1.333mA
738mV     -4.656mA   -5.117mA   -4.085mA
976mV     -9.963mA   -10.68mA   -8.789mA
1.316V    -18.32mA   -19.22mA   -16.24mA
1.418V    -20.39mA   -21.1mA    -18.43mA
1.486V    -21.07mA   -21.78mA   -19.43mA
1.554V    -21.24mA   -22.11mA   -19.69mA
1.622V    -21.08mA   -22.21mA   -19.37mA
1.996V    -18.26mA   -21.25mA   -14.72mA
2.2V      -17.08mA   -20.52mA   -13.36mA
[GND_clamp]
|Voltage   I(typ)   I(min)   I(max)
-1.1V     -128.5mA   -147.6mA   -122.6mA
-1.008V   -93.62mA   -112mA     -87.95mA
-962mV    -77.6mA    -95.05mA   -73.96mA
-893mV    -57.36mA   -71.21mA   -60.7mA
-847mV    -48.01mA   -56.81mA   -54.36mA
-801mV    -41.47mA   -44.23mA   -48.33mA
-755mV    -36.02mA   -34.19mA   -42.41mA
-709mV    -30.9mA    -26.94mA   -36.63mA
-525mV    -12.67mA   -10.3mA    -15.49mA
-387mV    -3.615mA   -3.065mA   -4.419mA
-249mV    -281uA     -330.6uA   -301.3uA
1.1V      0A         0A         0A
[POWER_clamp]
|Voltage   I(typ)   I(min)   I(max)
-1.1V     70.27mA    107.3mA    47.25mA
-1.039V   47.68mA    83.93mA    25.86mA
-993mV    31.88mA    66.94mA    12.35mA
-970mV    24.65mA    58.72mA    7.262mA
-947mV    18.06mA    50.74mA    3.761mA
-901mV    7.73mA     35.71mA    987.1uA
-855mV    2.348mA    22.46mA    514uA
-809mV    697.3uA    11.94mA    396.5uA
-763mV    321uA      5.097mA    322.7uA
-717mV    213.8uA    1.813mA    258.1uA
-556mV    65.24uA    79.15uA    81.64uA
1.1V      0A         0A         0A
[Ramp]
| variable   typ   min   max
dV/dt_r   0.179/37.528p   0.174/46.232p   0.189/29.610p
dV/dt_f   0.186/42.394p   0.187/55.808p   0.198/32.549p
R_load = 50.000
[Rising Waveform]
R_fixture= 50.000
V_fixture= 1.100
V_fixture_min= 1.060
V_fixture_max= 1.170
|time   V(typ)   V(min)   V(max)
0s        789.7mV    747.6mV    839.6mV
132ps     790.9mV    748mV      834.9mV
184ps     771.4mV    749.3mV    1.035V
217ps     873.2mV    741.7mV    1.097V
262ps     1.004V     721.2mV    1.134V
282ps     1.034V     754.3mV    1.145V
301ps     1.053V     826.5mV    1.152V
356ps     1.081V     975.4mV    1.163V
436ps     1.094V     1.04V      1.169V
1ns       1.1V       1.06V      1.17V
[Rising Waveform]
R_fixture= 50.000
V_fixture= 0.0
V_fixture_min= 0.0
V_fixture_max= 0.0
|time   V(typ)   V(min)   V(max)
0s        2.545uV    20.59uV    475.2nV
146ps     115uV      27.92uV    12.67mV
191ps     -181.4uV   136.4uV    270.1mV
211ps     8.904mV    30.67uV    329.7mV
229ps     59.53mV    -124.8uV   352.2mV
275ps     267.7mV    457.9uV    320.1mV
322ps     326.1mV    53.51mV    315.9mV
378ps     303mV      255mV      315.5mV
432ps     298.8mV    305.6mV    315.5mV
1ns       299.2mV    290.5mV    315.5mV
[Falling Waveform]
R_fixture= 50.000
V_fixture= 1.100
V_fixture_min= 1.060
V_fixture_max= 1.170
|time   V(typ)   V(min)   V(max)
0s        1.1V       1.06V      1.17V
145ps     1.1V       1.06V      1.167V
210ps     1.101V     1.06V      829.9mV
242ps     1.008V     1.06V      748.8mV
285ps     826.7mV    1.062V     791.7mV
341ps     714.2mV    982.9mV    824.1mV
399ps     751.3mV    791.7mV    834.7mV
478ps     781.5mV    690.5mV    838.6mV
615ps     789.1mV    739.8mV    839.6mV
1ns       789.7mV    747.5mV    839.6mV
[Falling Waveform]
R_fixture= 50.000
V_fixture= 0.0
V_fixture_min= 0.0
V_fixture_max= 0.0
|time   V(typ)   V(min)   V(max)
0s        299.2mV    290.5mV    315.5mV
132ps     298.1mV    290.1mV    327.5mV
146ps     299.7mV    289.7mV    292mV
192ps     315.5mV    289.6mV    62.06mV
211ps     280.2mV    292mV      31.09mV
256ps     77.81mV    308.1mV    3.337mV
292ps     22.11mV    295.7mV    -67.2uV
359ps     726.8uV    65.32mV    15.61uV
409ps     -1.431mV   11.35mV    10.52uV
1ns       5.753uV    25.33uV    -1.648uV
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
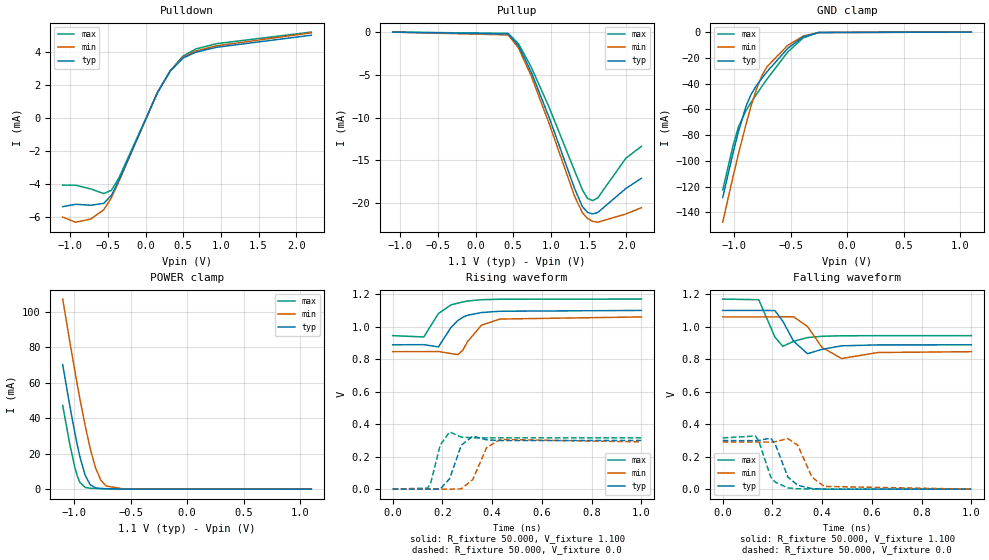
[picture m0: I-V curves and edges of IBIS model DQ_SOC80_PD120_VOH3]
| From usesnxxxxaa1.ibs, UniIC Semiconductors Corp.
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|   Model DQ_SOC80_PD120_VOH3
[Model] DQ_SOC80_PD120_VOH3
Model_type I/O
Polarity   Non-Inverting
Enable   Active-High
Vinl =  0.113V
Vinh =  0.253V
Vmeas =  0.183V
Rref =  50.000
Vref =  0.183V
C_comp   1.110pF   1.087pF   1.118pF
[Model Spec]
Vinh   0.253V   0.247V   0.265V
Vinl   0.113V   0.107V   0.125V
Vmeas   0.183V   NA   NA
Vref   0.183V   NA   NA
Rref   50.000   NA   NA
[Temperature Range]   25.000   0.125k   -40.000
[Voltage Range]   1.100V   1.060V   1.170V
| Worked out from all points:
|   slope of the pulldown table from 0 to 0.165 V, typ, clamps not added: 103 ohm
|   GND clamp passes 1 mA (typ) near -0.30 V on its own axis
|   POWER clamp passes 1 mA (typ) near -0.82 V on its own axis
|   rising waveform, R_fixture 50.000, V_fixture 1.100: 20-80 % time 71.7ps typ, 72.3ps min, 72.1ps max; typ from 0.888 V to 1.1 V
|   rising waveform, R_fixture 50.000, V_fixture 0.0: 20-80 % time 37.5ps typ, 46.2ps min, 29.7ps max; typ from 0 V to 0.299 V
|   falling waveform, R_fixture 50.000, V_fixture 1.100: 20-80 % time 42.7ps typ, 55.3ps min, 32.7ps max; typ from 1.1 V to 0.888 V
|   falling waveform, R_fixture 50.000, V_fixture 0.0: 20-80 % time 48.8ps typ, 53.5ps min, 45.9ps max; typ from 0.299 V to 0 V
[Pulldown]
|Voltage   I(typ)   I(min)   I(max)
-1.1V     -5.373mA   -6.003mA   -4.071mA
-930mV    -5.229mA   -6.314mA   -4.072mA
-726mV    -5.288mA   -6.12mA    -4.3mA
-556mV    -5.174mA   -5.561mA   -4.579mA
-454mV    -4.694mA   -4.844mA   -4.386mA
-352mV    -3.758mA   -3.821mA   -3.611mA
158mV     1.543mA    1.549mA    1.529mA
328mV     2.841mA    2.867mA    2.862mA
498mV     3.628mA    3.683mA    3.752mA
668mV     3.985mA    4.056mA    4.181mA
940mV     4.28mA     4.369mA    4.5mA
2.2V      5.012mA    5.157mA    5.202mA
[Pullup]
|Voltage   I(typ)   I(min)   I(max)
-1.1V     1nA        20.18nA    0A
432mV     -223uA     -332.2uA   -150.9uA
568mV     -1.57mA    -1.836mA   -1.333mA
738mV     -4.656mA   -5.117mA   -4.085mA
976mV     -9.963mA   -10.68mA   -8.789mA
1.316V    -18.32mA   -19.22mA   -16.24mA
1.418V    -20.39mA   -21.1mA    -18.43mA
1.486V    -21.07mA   -21.78mA   -19.43mA
1.554V    -21.24mA   -22.11mA   -19.69mA
1.622V    -21.08mA   -22.21mA   -19.37mA
1.996V    -18.26mA   -21.25mA   -14.72mA
2.2V      -17.08mA   -20.52mA   -13.36mA
[GND_clamp]
|Voltage   I(typ)   I(min)   I(max)
-1.1V     -128.5mA   -147.6mA   -122.6mA
-1.008V   -93.62mA   -112mA     -87.95mA
-962mV    -77.6mA    -95.05mA   -73.96mA
-893mV    -57.36mA   -71.21mA   -60.7mA
-847mV    -48.01mA   -56.81mA   -54.36mA
-801mV    -41.47mA   -44.23mA   -48.33mA
-755mV    -36.02mA   -34.19mA   -42.41mA
-709mV    -30.9mA    -26.94mA   -36.63mA
-525mV    -12.67mA   -10.3mA    -15.49mA
-387mV    -3.615mA   -3.065mA   -4.419mA
-249mV    -281uA     -330.6uA   -301.3uA
1.1V      0A         0A         0A
[POWER_clamp]
|Voltage   I(typ)   I(min)   I(max)
-1.1V     70.27mA    107.3mA    47.25mA
-1.039V   47.68mA    83.93mA    25.86mA
-993mV    31.88mA    66.94mA    12.35mA
-970mV    24.65mA    58.72mA    7.262mA
-947mV    18.06mA    50.74mA    3.761mA
-901mV    7.73mA     35.71mA    987.1uA
-855mV    2.348mA    22.46mA    514uA
-809mV    697.3uA    11.94mA    396.5uA
-763mV    321uA      5.097mA    322.7uA
-717mV    213.8uA    1.813mA    258.1uA
-556mV    65.24uA    79.15uA    81.64uA
1.1V      0A         0A         0A
[Ramp]
| variable   typ   min   max
dV/dt_r   0.179/38.124p   0.174/47.306p   0.189/29.915p
dV/dt_f   0.127/42.714p   0.128/56.263p   0.135/32.637p
R_load = 50.000
[Rising Waveform]
R_fixture= 50.000
V_fixture= 1.100
V_fixture_min= 1.060
V_fixture_max= 1.170
|time   V(typ)   V(min)   V(max)
0s        888.3mV    846.1mV    944.8mV
125ps     889.3mV    846.3mV    936.8mV
184ps     875.5mV    847.2mV    1.081V
234ps     994.4mV    834.7mV    1.134V
262ps     1.038V     827.5mV    1.145V
282ps     1.058V     855.2mV    1.152V
301ps     1.07V      908mV      1.158V
357ps     1.087V     1.009V     1.166V
431ps     1.095V     1.047V     1.169V
1ns       1.1V       1.06V      1.17V
[Rising Waveform]
R_fixture= 50.000
V_fixture= 0.0
V_fixture_min= 0.0
V_fixture_max= 0.0
|time   V(typ)   V(min)   V(max)
0s        2.986uV    24.15uV    556.4nV
140ps     91.91uV    43.24uV    5.876mV
153ps     -158.9uV   64.39uV    39.18mV
191ps     416.4uV    98.88uV    271.3mV
229ps     63.92mV    -394.2uV   352.2mV
276ps     270.8mV    1.662mV    320mV
322ps     326.1mV    58.85mV    315.9mV
378ps     303mV      255.9mV    315.5mV
432ps     298.8mV    305.6mV    315.5mV
1ns       299.2mV    290.5mV    315.5mV
[Falling Waveform]
R_fixture= 50.000
V_fixture= 1.100
V_fixture_min= 1.060
V_fixture_max= 1.170
|time   V(typ)   V(min)   V(max)
0s        1.1V       1.06V      1.17V
145ps     1.1V       1.06V      1.166V
210ps     1.099V     1.06V      935.8mV
242ps     1.033V     1.061V     879.2mV
285ps     910.8mV    1.061V     909.8mV
341ps     833.5mV    1.001V     933mV
399ps     860.3mV    873.2mV    940.9mV
478ps     882.1mV    803.9mV    944mV
624ps     887.9mV    841mV      944.7mV
1ns       888.3mV    846.1mV    944.8mV
[Falling Waveform]
R_fixture= 50.000
V_fixture= 0.0
V_fixture_min= 0.0
V_fixture_max= 0.0
|time   V(typ)   V(min)   V(max)
0s        299.2mV    290.5mV    315.5mV
132ps     298.1mV    290.1mV    327.1mV
146ps     299.8mV    289.7mV    291.3mV
193ps     314.3mV    289.7mV    75.16mV
211ps     278.6mV    292.1mV    43.5mV
262ps     74.68mV    310.9mV    7.632mV
302ps     23.25mV    270.3mV    2.297mV
359ps     3.611mV    73.35mV    571.3uV
409ps     -152uV     16.59mV    170.9uV
1ns       3.146uV    29.71uV    3.149uV
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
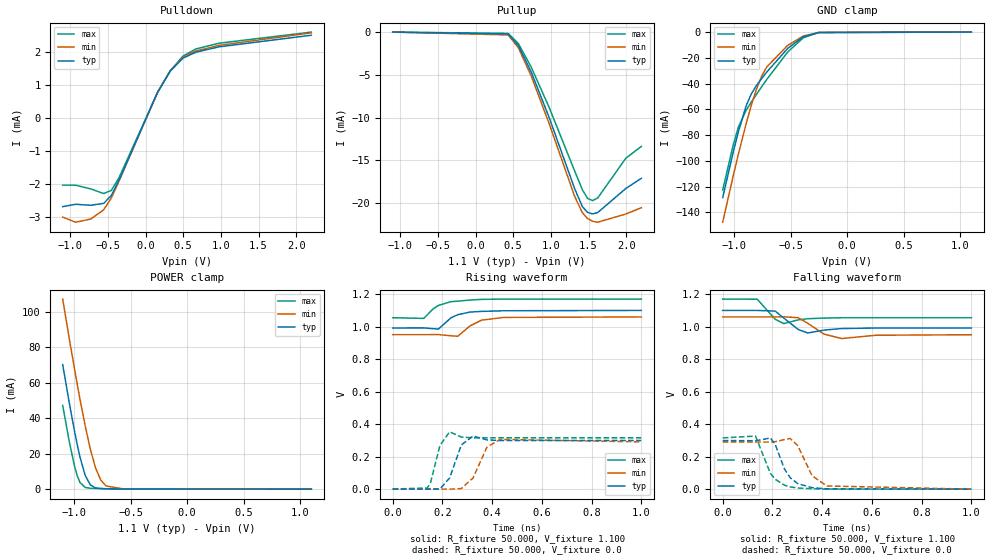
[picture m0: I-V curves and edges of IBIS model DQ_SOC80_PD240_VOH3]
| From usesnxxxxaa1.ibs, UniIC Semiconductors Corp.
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|   Model DQ_SOC80_PD240_VOH3
[Model] DQ_SOC80_PD240_VOH3
Model_type I/O
Polarity   Non-Inverting
Enable   Active-High
Vinl =  0.113V
Vinh =  0.253V
Vmeas =  0.183V
Rref =  50.000
Vref =  0.183V
C_comp   1.110pF   1.087pF   1.118pF
[Model Spec]
Vinh   0.253V   0.247V   0.265V
Vinl   0.113V   0.107V   0.125V
Vmeas   0.183V   NA   NA
Vref   0.183V   NA   NA
Rref   50.000   NA   NA
[Temperature Range]   25.000   0.125k   -40.000
[Voltage Range]   1.100V   1.060V   1.170V
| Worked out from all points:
|   slope of the pulldown table from 0 to 0.165 V, typ, clamps not added: 206 ohm
|   GND clamp passes 1 mA (typ) near -0.30 V on its own axis
|   POWER clamp passes 1 mA (typ) near -0.82 V on its own axis
|   rising waveform, R_fixture 50.000, V_fixture 1.100: 20-80 % time 64.7ps typ, 62.2ps min, 67.7ps max; typ from 0.992 V to 1.1 V
|   rising waveform, R_fixture 50.000, V_fixture 0.0: 20-80 % time 38.3ps typ, 47.9ps min, 30.1ps max; typ from 0 V to 0.299 V
|   falling waveform, R_fixture 50.000, V_fixture 1.100: 20-80 % time 43.2ps typ, 56ps min, 33.2ps max; typ from 1.1 V to 0.992 V
|   falling waveform, R_fixture 50.000, V_fixture 0.0: 20-80 % time 57.4ps typ, 60.3ps min, 56ps max; typ from 0.299 V to 0 V
[Pulldown]
|Voltage   I(typ)   I(min)   I(max)
-1.1V     -2.687mA   -3.002mA   -2.035mA
-930mV    -2.614mA   -3.157mA   -2.036mA
-726mV    -2.644mA   -3.06mA    -2.15mA
-556mV    -2.587mA   -2.78mA    -2.289mA
-454mV    -2.347mA   -2.422mA   -2.193mA
-352mV    -1.879mA   -1.911mA   -1.806mA
158mV     771.5uA    774.7uA    764.3uA
328mV     1.42mA     1.434mA    1.431mA
498mV     1.814mA    1.841mA    1.876mA
668mV     1.992mA    2.028mA    2.091mA
974mV     2.154mA    2.199mA    2.264mA
2.2V      2.506mA    2.578mA    2.601mA
[Pullup]
|Voltage   I(typ)   I(min)   I(max)
-1.1V     1nA        20.18nA    0A
432mV     -223uA     -332.2uA   -150.9uA
568mV     -1.57mA    -1.836mA   -1.333mA
738mV     -4.656mA   -5.117mA   -4.085mA
976mV     -9.963mA   -10.68mA   -8.789mA
1.316V    -18.32mA   -19.22mA   -16.24mA
1.418V    -20.39mA   -21.1mA    -18.43mA
1.486V    -21.07mA   -21.78mA   -19.43mA
1.554V    -21.24mA   -22.11mA   -19.69mA
1.622V    -21.08mA   -22.21mA   -19.37mA
1.996V    -18.26mA   -21.25mA   -14.72mA
2.2V      -17.08mA   -20.52mA   -13.36mA
[GND_clamp]
|Voltage   I(typ)   I(min)   I(max)
-1.1V     -128.5mA   -147.6mA   -122.6mA
-1.008V   -93.62mA   -112mA     -87.95mA
-962mV    -77.6mA    -95.05mA   -73.96mA
-893mV    -57.36mA   -71.21mA   -60.7mA
-847mV    -48.01mA   -56.81mA   -54.36mA
-801mV    -41.47mA   -44.23mA   -48.33mA
-755mV    -36.02mA   -34.19mA   -42.41mA
-709mV    -30.9mA    -26.94mA   -36.63mA
-525mV    -12.67mA   -10.3mA    -15.49mA
-387mV    -3.615mA   -3.065mA   -4.419mA
-249mV    -281uA     -330.6uA   -301.3uA
1.1V      0A         0A         0A
[POWER_clamp]
|Voltage   I(typ)   I(min)   I(max)
-1.1V     70.27mA    107.3mA    47.25mA
-1.039V   47.68mA    83.93mA    25.86mA
-993mV    31.88mA    66.94mA    12.35mA
-970mV    24.65mA    58.72mA    7.262mA
-947mV    18.06mA    50.74mA    3.761mA
-901mV    7.73mA     35.71mA    987.1uA
-855mV    2.348mA    22.46mA    514uA
-809mV    697.3uA    11.94mA    396.5uA
-763mV    321uA      5.097mA    322.7uA
-717mV    213.8uA    1.813mA    258.1uA
-556mV    65.24uA    79.15uA    81.64uA
1.1V      0A         0A         0A
[Ramp]
| variable   typ   min   max
dV/dt_r   0.179/38.893p   0.174/48.556p   0.189/30.250p
dV/dt_f   64.848m/43.349p   65.673m/56.412p   68.888m/33.271p
R_load = 50.000
[Rising Waveform]
R_fixture= 50.000
V_fixture= 1.100
V_fixture_min= 1.060
V_fixture_max= 1.170
|time   V(typ)   V(min)   V(max)
0s        991.9mV    950.6mV    1.055V
125ps     992.5mV    950.6mV    1.051V
162ps     987.6mV    951.2mV    1.109V
184ps     985.4mV    951.2mV    1.131V
234ps     1.054V     943.8mV    1.154V
262ps     1.074V     941mV      1.157V
311ps     1.09V      1.005V     1.164V
357ps     1.094V     1.04V      1.168V
447ps     1.098V     1.057V     1.17V
1ns       1.1V       1.06V      1.17V
[Rising Waveform]
R_fixture= 50.000
V_fixture= 0.0
V_fixture_min= 0.0
V_fixture_max= 0.0
|time   V(typ)   V(min)   V(max)
0s        3.61uV     29.2uV     671nV
139ps     20.99uV    70.95uV    6.475mV
152ps     -310.4uV   89.84uV    38.36mV
190ps     905.6uV    47.09uV    268.2mV
229ps     68.35mV    -709.9uV   352.7mV
276ps     271.6mV    3.007mV    320mV
323ps     326.6mV    68.05mV    315.9mV
379ps     302.6mV    258.4mV    315.5mV
432ps     298.8mV    305.6mV    315.5mV
1ns       299.2mV    290.5mV    315.5mV
[Falling Waveform]
R_fixture= 50.000
V_fixture= 1.100
V_fixture_min= 1.060
V_fixture_max= 1.170
|time   V(typ)   V(min)   V(max)
0s        1.1V       1.06V      1.17V
139ps     1.1V       1.06V      1.169V
211ps     1.096V     1.06V      1.046V
245ps     1.054V     1.061V     1.019V
304ps     982.3mV    1.055V     1.042V
342ps     961.4mV    1.021V     1.049V
407ps     978.8mV    954.6mV    1.053V
478ps     988.5mV    927mV      1.055V
616ps     991.7mV    947.3mV    1.055V
1ns       991.9mV    950.5mV    1.055V
[Falling Waveform]
R_fixture= 50.000
V_fixture= 0.0
V_fixture_min= 0.0
V_fixture_max= 0.0
|time   V(typ)   V(min)   V(max)
0s        299.2mV    290.5mV    315.5mV
132ps     298.1mV    290.1mV    326.8mV
192ps     314.8mV    289.7mV    96.63mV
211ps     276.7mV    292.2mV    61.14mV
248ps     124.9mV    304.8mV    24.82mV
272ps     68.96mV    312mV      13.77mV
302ps     34.34mV    267.9mV    7.261mV
359ps     9mV        83.23mV    2.237mV
419ps     2.03mV     19.66mV    644.9uV
1ns       8.294uV    35.91uV    3.885uV
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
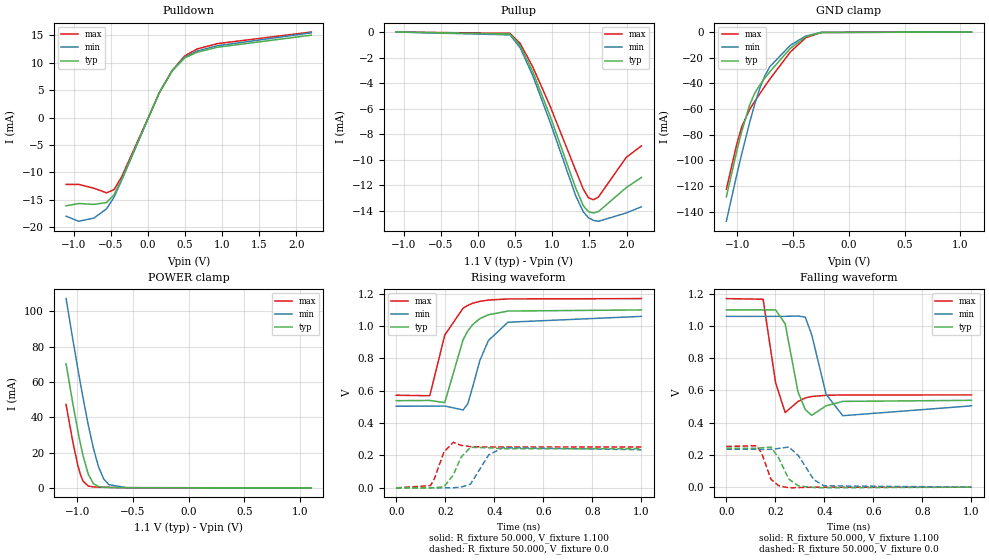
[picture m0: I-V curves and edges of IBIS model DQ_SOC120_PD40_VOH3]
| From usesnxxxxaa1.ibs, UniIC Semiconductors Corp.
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|   Model DQ_SOC120_PD40_VOH3
[Model] DQ_SOC120_PD40_VOH3
Model_type I/O
Polarity   Non-Inverting
Enable   Active-High
Vinl =  0.113V
Vinh =  0.253V
Vmeas =  0.183V
Rref =  50.000
Vref =  0.183V
C_comp   1.110pF   1.087pF   1.118pF
[Model Spec]
Vinh   0.253V   0.247V   0.265V
Vinl   0.113V   0.107V   0.125V
Vmeas   0.183V   NA   NA
Vref   0.183V   NA   NA
Rref   50.000   NA   NA
[Temperature Range]   25.000   0.125k   -40.000
[Voltage Range]   1.100V   1.060V   1.170V
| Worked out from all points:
|   slope of the pulldown table from 0 to 0.165 V, typ, clamps not added: 34.3 ohm
|   GND clamp passes 1 mA (typ) near -0.30 V on its own axis
|   POWER clamp passes 1 mA (typ) near -0.82 V on its own axis
|   rising waveform, R_fixture 50.000, V_fixture 1.100: 20-80 % time 77.6ps typ, 82.5ps min, 75.6ps max; typ from 0.539 V to 1.1 V
|   rising waveform, R_fixture 50.000, V_fixture 0.0: 20-80 % time 42.8ps typ, 52.8ps min, 34.4ps max; typ from 0 V to 0.242 V
|   falling waveform, R_fixture 50.000, V_fixture 1.100: 20-80 % time 39ps typ, 50.6ps min, 30.2ps max; typ from 1.1 V to 0.539 V
|   falling waveform, R_fixture 50.000, V_fixture 0.0: 20-80 % time 46.7ps typ, 59ps min, 34.7ps max; typ from 0.242 V to 0 V
[Pulldown]
|Voltage   I(typ)   I(min)   I(max)
-1.1V     -16.12mA   -18.01mA   -12.21mA
-930mV    -15.69mA   -18.94mA   -12.21mA
-726mV    -15.86mA   -18.36mA   -12.9mA
-556mV    -15.52mA   -16.68mA   -13.74mA
-454mV    -14.08mA   -14.53mA   -13.16mA
-352mV    -11.27mA   -11.46mA   -10.83mA
158mV     4.629mA    4.648mA    4.586mA
328mV     8.522mA    8.602mA    8.586mA
498mV     10.89mA    11.05mA    11.26mA
668mV     11.95mA    12.17mA    12.54mA
940mV     12.84mA    13.11mA    13.5mA
2.2V      15.04mA    15.47mA    15.61mA
[Pullup]
|Voltage   I(typ)   I(min)   I(max)
-1.1V     -58.82pA   9.882nA    0A
432mV     -148.6uA   -221.4uA   -100.6uA
568mV     -1.047mA   -1.224mA   -888.8uA
738mV     -3.104mA   -3.412mA   -2.724mA
976mV     -6.642mA   -7.121mA   -5.859mA
1.316V    -12.21mA   -12.81mA   -10.83mA
1.418V    -13.59mA   -14.07mA   -12.29mA
1.486V    -14.05mA   -14.52mA   -12.96mA
1.554V    -14.16mA   -14.74mA   -13.13mA
1.622V    -14.05mA   -14.81mA   -12.91mA
1.996V    -12.18mA   -14.16mA   -9.815mA
2.2V      -11.38mA   -13.68mA   -8.909mA
[GND_clamp]
|Voltage   I(typ)   I(min)   I(max)
-1.1V     -128.5mA   -147.6mA   -122.6mA
-1.008V   -93.62mA   -112mA     -87.95mA
-962mV    -77.6mA    -95.05mA   -73.96mA
-893mV    -57.36mA   -71.21mA   -60.7mA
-847mV    -48.01mA   -56.81mA   -54.36mA
-801mV    -41.47mA   -44.23mA   -48.33mA
-755mV    -36.02mA   -34.19mA   -42.41mA
-709mV    -30.9mA    -26.94mA   -36.63mA
-525mV    -12.67mA   -10.3mA    -15.49mA
-387mV    -3.615mA   -3.065mA   -4.419mA
-249mV    -281uA     -330.6uA   -301.3uA
1.1V      0A         0A         0A
[POWER_clamp]
|Voltage   I(typ)   I(min)   I(max)
-1.1V     70.27mA    107.3mA    47.25mA
-1.039V   47.68mA    83.93mA    25.86mA
-993mV    31.88mA    66.94mA    12.35mA
-970mV    24.65mA    58.72mA    7.262mA
-947mV    18.06mA    50.74mA    3.761mA
-901mV    7.73mA     35.71mA    987.1uA
-855mV    2.348mA    22.46mA    514uA
-809mV    697.3uA    11.94mA    396.5uA
-763mV    321uA      5.097mA    322.7uA
-717mV    213.8uA    1.813mA    258.1uA
-556mV    65.24uA    79.15uA    81.64uA
1.1V      0A         0A         0A
[Ramp]
| variable   typ   min   max
dV/dt_r   0.145/42.815p   0.141/53.439p   0.152/34.625p
dV/dt_f   0.337/39.417p   0.333/51.732p   0.359/30.295p
R_load = 50.000
[Rising Waveform]
R_fixture= 50.000
V_fixture= 1.100
V_fixture_min= 1.060
V_fixture_max= 1.170
|time   V(typ)   V(min)   V(max)
0s        538.9mV    504.5mV    572.5mV
137ps     540.2mV    505.1mV    569.5mV
198ps     527mV      505.8mV    944.3mV
273ps     916.4mV    481.6mV    1.111V
292ps     969.9mV    519.5mV    1.128V
311ps     1.008V     619.1mV    1.141V
341ps     1.046V     786mV      1.153V
376ps     1.07V      910.8mV    1.161V
456ps     1.093V     1.024V     1.168V
1ns       1.1V       1.06V      1.17V
[Rising Waveform]
R_fixture= 50.000
V_fixture= 0.0
V_fixture_min= 0.0
V_fixture_max= 0.0
|time   V(typ)   V(min)   V(max)
0s        1.764uV    14.27uV    330.5nV
140ps     31.23uV    -42.46uV   13.9mV
155ps     171.3uV    -12.37uV   53.99mV
195ps     6.383mV    -37.05uV   222.7mV
233ps     79.56mV    537.3uV    281.2mV
264ps     188.2mV    4.318mV    262.7mV
303ps     250.5mV    22.52mV    254.8mV
377ps     247.6mV    203.4mV    252.7mV
436ps     241.9mV    248.3mV    252.6mV
1ns       241.7mV    235.4mV    252.6mV
[Falling Waveform]
R_fixture= 50.000
V_fixture= 1.100
V_fixture_min= 1.060
V_fixture_max= 1.170
|time   V(typ)   V(min)   V(max)
0s        1.1V       1.06V      1.17V
150ps     1.1V       1.06V      1.166V
201ps     1.1V       1.06V      647.8mV
240ps     1.014V     1.06V      462.9mV
292ps     593.4mV    1.062V     531.4mV
322ps     481.4mV    1.055V     553.5mV
348ps     445.5mV    947.5mV    562.5mV
407ps     504.9mV    576.1mV    570.2mV
475ps     532.2mV    443.4mV    572mV
1ns       538.8mV    504.5mV    572.5mV
[Falling Waveform]
R_fixture= 50.000
V_fixture= 0.0
V_fixture_min= 0.0
V_fixture_max= 0.0
|time   V(typ)   V(min)   V(max)
0s        241.7mV    235.4mV    252.6mV
124ps     240.9mV    235.1mV    257mV
145ps     244.5mV    234.6mV    208.3mV
182ps     248.6mV    234.8mV    48.69mV
213ps     182.8mV    240.3mV    9.434mV
255ps     49.82mV    249mV      -4.147mV
294ps     7.695mV    196mV      -2.614mV
357ps     -2.145mV   46.25mV    -152.5uV
398ps     -3.877mV   8.384mV    -20.23uV
1ns       2.801uV    16.56uV    1.969uV
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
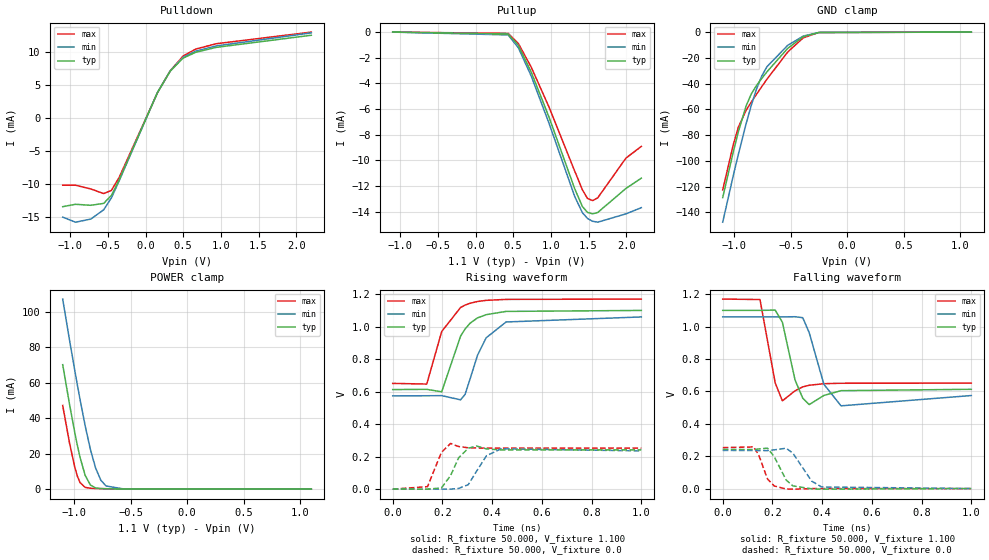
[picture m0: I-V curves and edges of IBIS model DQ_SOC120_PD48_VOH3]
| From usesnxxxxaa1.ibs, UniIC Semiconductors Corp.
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|   Model DQ_SOC120_PD48_VOH3
[Model] DQ_SOC120_PD48_VOH3
Model_type I/O
Polarity   Non-Inverting
Enable   Active-High
Vinl =  0.113V
Vinh =  0.253V
Vmeas =  0.183V
Rref =  50.000
Vref =  0.183V
C_comp   1.110pF   1.087pF   1.118pF
[Model Spec]
Vinh   0.253V   0.247V   0.265V
Vinl   0.113V   0.107V   0.125V
Vmeas   0.183V   NA   NA
Vref   0.183V   NA   NA
Rref   50.000   NA   NA
[Temperature Range]   25.000   0.125k   -40.000
[Voltage Range]   1.100V   1.060V   1.170V
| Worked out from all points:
|   slope of the pulldown table from 0 to 0.165 V, typ, clamps not added: 41.1 ohm
|   GND clamp passes 1 mA (typ) near -0.30 V on its own axis
|   POWER clamp passes 1 mA (typ) near -0.82 V on its own axis
|   rising waveform, R_fixture 50.000, V_fixture 1.100: 20-80 % time 77.4ps typ, 82ps min, 75.6ps max; typ from 0.613 V to 1.1 V
|   rising waveform, R_fixture 50.000, V_fixture 0.0: 20-80 % time 43.3ps typ, 53.2ps min, 34.6ps max; typ from 0 V to 0.242 V
|   falling waveform, R_fixture 50.000, V_fixture 1.100: 20-80 % time 39.7ps typ, 52.2ps min, 30.7ps max; typ from 1.1 V to 0.613 V
|   falling waveform, R_fixture 50.000, V_fixture 0.0: 20-80 % time 48.9ps typ, 60.3ps min, 37.4ps max; typ from 0.242 V to 0 V
[Pulldown]
|Voltage   I(typ)   I(min)   I(max)
-1.1V     -13.43mA   -15.01mA   -10.18mA
-930mV    -13.07mA   -15.78mA   -10.18mA
-726mV    -13.22mA   -15.3mA    -10.75mA
-556mV    -12.93mA   -13.9mA    -11.45mA
-454mV    -11.73mA   -12.11mA   -10.97mA
-352mV    -9.395mA   -9.553mA   -9.028mA
158mV     3.857mA    3.874mA    3.821mA
328mV     7.102mA    7.168mA    7.155mA
498mV     9.071mA    9.207mA    9.38mA
668mV     9.963mA    10.14mA    10.45mA
940mV     10.7mA     10.92mA    11.25mA
2.2V      12.53mA    12.89mA    13.01mA
[Pullup]
|Voltage   I(typ)   I(min)   I(max)
-1.1V     -58.82pA   9.882nA    0A
432mV     -148.6uA   -221.4uA   -100.6uA
568mV     -1.047mA   -1.224mA   -888.8uA
738mV     -3.104mA   -3.412mA   -2.724mA
976mV     -6.642mA   -7.121mA   -5.859mA
1.316V    -12.21mA   -12.81mA   -10.83mA
1.418V    -13.59mA   -14.07mA   -12.29mA
1.486V    -14.05mA   -14.52mA   -12.96mA
1.554V    -14.16mA   -14.74mA   -13.13mA
1.622V    -14.05mA   -14.81mA   -12.91mA
1.996V    -12.18mA   -14.16mA   -9.815mA
2.2V      -11.38mA   -13.68mA   -8.909mA
[GND_clamp]
|Voltage   I(typ)   I(min)   I(max)
-1.1V     -128.5mA   -147.6mA   -122.6mA
-1.008V   -93.62mA   -112mA     -87.95mA
-962mV    -77.6mA    -95.05mA   -73.96mA
-893mV    -57.36mA   -71.21mA   -60.7mA
-847mV    -48.01mA   -56.81mA   -54.36mA
-801mV    -41.47mA   -44.23mA   -48.33mA
-755mV    -36.02mA   -34.19mA   -42.41mA
-709mV    -30.9mA    -26.94mA   -36.63mA
-525mV    -12.67mA   -10.3mA    -15.49mA
-387mV    -3.615mA   -3.065mA   -4.419mA
-249mV    -281uA     -330.6uA   -301.3uA
1.1V      0A         0A         0A
[POWER_clamp]
|Voltage   I(typ)   I(min)   I(max)
-1.1V     70.27mA    107.3mA    47.25mA
-1.039V   47.68mA    83.93mA    25.86mA
-993mV    31.88mA    66.94mA    12.35mA
-970mV    24.65mA    58.72mA    7.262mA
-947mV    18.06mA    50.74mA    3.761mA
-901mV    7.73mA     35.71mA    987.1uA
-855mV    2.348mA    22.46mA    514uA
-809mV    697.3uA    11.94mA    396.5uA
-763mV    321uA      5.097mA    322.7uA
-717mV    213.8uA    1.813mA    258.1uA
-556mV    65.24uA    79.15uA    81.64uA
1.1V      0A         0A         0A
[Ramp]
| variable   typ   min   max
dV/dt_r   0.145/43.238p   0.141/54.160p   0.152/34.977p
dV/dt_f   0.292/40.124p   0.291/53.258p   0.311/30.773p
R_load = 50.000
[Rising Waveform]
R_fixture= 50.000
V_fixture= 1.100
V_fixture_min= 1.060
V_fixture_max= 1.170
|time   V(typ)   V(min)   V(max)
0s        613mV      574.4mV    651mV
137ps     614.2mV    575mV      646.9mV
197ps     599.1mV    575.6mV    970.1mV
273ps     941.6mV    549.9mV    1.118V
291ps     985.7mV    583mV      1.133V
311ps     1.021V     677.3mV    1.144V
341ps     1.054V     823.8mV    1.155V
376ps     1.074V     931.7mV    1.162V
456ps     1.094V     1.029V     1.168V
1ns       1.1V       1.06V      1.17V
[Rising Waveform]
R_fixture= 50.000
V_fixture= 0.0
V_fixture_min= 0.0
V_fixture_max= 0.0
|time   V(typ)   V(min)   V(max)
0s        1.965uV    15.9uV     367.9nV
140ps     -16.19uV   -22.61uV   15.5mV
196ps     7.679mV    -62.83uV   226.7mV
233ps     84.06mV    359.3uV    281.4mV
265ps     192.7mV    4.557mV    262.4mV
304ps     251.8mV    27.59mV    254.7mV
337ps     265.7mV    109.7mV    253.3mV
377ps     247.7mV    205.4mV    252.8mV
436ps     241.9mV    248.5mV    252.6mV
1ns       241.7mV    235.4mV    252.6mV
[Falling Waveform]
R_fixture= 50.000
V_fixture= 1.100
V_fixture_min= 1.060
V_fixture_max= 1.170
|time   V(typ)   V(min)   V(max)
0s        1.1V       1.06V      1.17V
150ps     1.1V       1.06V      1.167V
211ps     1.102V     1.06V      653.1mV
240ps     1.027V     1.06V      541.9mV
291ps     670.1mV    1.061V     603.6mV
322ps     557.9mV    1.055V     627.7mV
348ps     518.6mV    962.2mV    637.9mV
407ps     575mV      643.6mV    647.5mV
476ps     604.5mV    510.8mV    650.2mV
1ns       612.9mV    574.4mV    651mV
[Falling Waveform]
R_fixture= 50.000
V_fixture= 0.0
V_fixture_min= 0.0
V_fixture_max= 0.0
|time   V(typ)   V(min)   V(max)
0s        241.7mV    235.4mV    252.6mV
124ps     240.9mV    235.1mV    257.1mV
145ps     244.5mV    234.6mV    207.2mV
180ps     249.8mV    234.7mV    59.43mV
207ps     197.9mV    238.9mV    16.19mV
255ps     53.24mV    249.2mV    -2.824mV
282ps     16.72mV    219.2mV    -3.662mV
358ps     -1.72mV    45.79mV    -175.8uV
398ps     -3.433mV   9.889mV    -30.88uV
1ns       3.091uV    18.39uV    2.171uV
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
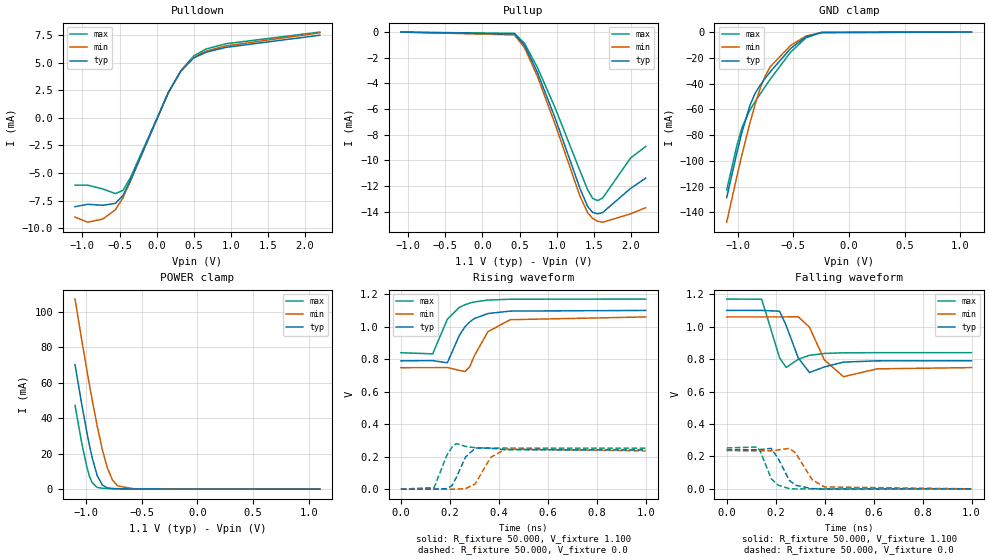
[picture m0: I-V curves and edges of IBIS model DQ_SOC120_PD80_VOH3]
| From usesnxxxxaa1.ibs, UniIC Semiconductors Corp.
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|   Model DQ_SOC120_PD80_VOH3
[Model] DQ_SOC120_PD80_VOH3
Model_type I/O
Polarity   Non-Inverting
Enable   Active-High
Vinl =  0.113V
Vinh =  0.253V
Vmeas =  0.183V
Rref =  50.000
Vref =  0.183V
C_comp   1.110pF   1.087pF   1.118pF
[Model Spec]
Vinh   0.253V   0.247V   0.265V
Vinl   0.113V   0.107V   0.125V
Vmeas   0.183V   NA   NA
Vref   0.183V   NA   NA
Rref   50.000   NA   NA
[Temperature Range]   25.000   0.125k   -40.000
[Voltage Range]   1.100V   1.060V   1.170V
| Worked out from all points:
|   slope of the pulldown table from 0 to 0.165 V, typ, clamps not added: 68.6 ohm
|   GND clamp passes 1 mA (typ) near -0.30 V on its own axis
|   POWER clamp passes 1 mA (typ) near -0.82 V on its own axis
|   rising waveform, R_fixture 50.000, V_fixture 1.100: 20-80 % time 75.8ps typ, 79.1ps min, 74.3ps max; typ from 0.79 V to 1.1 V
|   rising waveform, R_fixture 50.000, V_fixture 0.0: 20-80 % time 43ps typ, 52.6ps min, 34.4ps max; typ from 0 V to 0.242 V
|   falling waveform, R_fixture 50.000, V_fixture 1.100: 20-80 % time 42.4ps typ, 55.3ps min, 32.5ps max; typ from 1.1 V to 0.79 V
|   falling waveform, R_fixture 50.000, V_fixture 0.0: 20-80 % time 49.9ps typ, 58.6ps min, 42.7ps max; typ from 0.242 V to 0 V
[Pulldown]
|Voltage   I(typ)   I(min)   I(max)
-1.1V     -8.06mA    -9.005mA   -6.106mA
-930mV    -7.843mA   -9.47mA    -6.107mA
-726mV    -7.932mA   -9.181mA   -6.449mA
-556mV    -7.761mA   -8.341mA   -6.868mA
-454mV    -7.04mA    -7.266mA   -6.58mA
-352mV    -5.637mA   -5.732mA   -5.417mA
158mV     2.314mA    2.324mA    2.293mA
328mV     4.261mA    4.301mA    4.293mA
498mV     5.443mA    5.524mA    5.628mA
668mV     5.978mA    6.084mA    6.272mA
940mV     6.421mA    6.553mA    6.75mA
2.2V      7.518mA    7.735mA    7.803mA
[Pullup]
|Voltage   I(typ)   I(min)   I(max)
-1.1V     -58.82pA   9.882nA    0A
432mV     -148.6uA   -221.4uA   -100.6uA
568mV     -1.047mA   -1.224mA   -888.8uA
738mV     -3.104mA   -3.412mA   -2.724mA
976mV     -6.642mA   -7.121mA   -5.859mA
1.316V    -12.21mA   -12.81mA   -10.83mA
1.418V    -13.59mA   -14.07mA   -12.29mA
1.486V    -14.05mA   -14.52mA   -12.96mA
1.554V    -14.16mA   -14.74mA   -13.13mA
1.622V    -14.05mA   -14.81mA   -12.91mA
1.996V    -12.18mA   -14.16mA   -9.815mA
2.2V      -11.38mA   -13.68mA   -8.909mA
[GND_clamp]
|Voltage   I(typ)   I(min)   I(max)
-1.1V     -128.5mA   -147.6mA   -122.6mA
-1.008V   -93.62mA   -112mA     -87.95mA
-962mV    -77.6mA    -95.05mA   -73.96mA
-893mV    -57.36mA   -71.21mA   -60.7mA
-847mV    -48.01mA   -56.81mA   -54.36mA
-801mV    -41.47mA   -44.23mA   -48.33mA
-755mV    -36.02mA   -34.19mA   -42.41mA
-709mV    -30.9mA    -26.94mA   -36.63mA
-525mV    -12.67mA   -10.3mA    -15.49mA
-387mV    -3.615mA   -3.065mA   -4.419mA
-249mV    -281uA     -330.6uA   -301.3uA
1.1V      0A         0A         0A
[POWER_clamp]
|Voltage   I(typ)   I(min)   I(max)
-1.1V     70.27mA    107.3mA    47.25mA
-1.039V   47.68mA    83.93mA    25.86mA
-993mV    31.88mA    66.94mA    12.35mA
-970mV    24.65mA    58.72mA    7.262mA
-947mV    18.06mA    50.74mA    3.761mA
-901mV    7.73mA     35.71mA    987.1uA
-855mV    2.348mA    22.46mA    514uA
-809mV    697.3uA    11.94mA    396.5uA
-763mV    321uA      5.097mA    322.7uA
-717mV    213.8uA    1.813mA    258.1uA
-556mV    65.24uA    79.15uA    81.64uA
1.1V      0A         0A         0A
[Ramp]
| variable   typ   min   max
dV/dt_r   0.145/43.192p   0.141/53.263p   0.152/34.691p
dV/dt_f   0.186/42.604p   0.187/55.451p   0.198/32.557p
R_load = 50.000
[Rising Waveform]
R_fixture= 50.000
V_fixture= 1.100
V_fixture_min= 1.060
V_fixture_max= 1.170
|time   V(typ)   V(min)   V(max)
0s        789.7mV    747.6mV    839.6mV
130ps     791mV      747.9mV    832.8mV
190ps     778mV      748.6mV    1.046V
238ps     943.4mV    731mV      1.118V
262ps     999.4mV    723.8mV    1.135V
281ps     1.029V     753mV      1.145V
300ps     1.05V      820.7mV    1.152V
356ps     1.081V     969.9mV    1.164V
447ps     1.096V     1.043V     1.169V
1ns       1.1V       1.06V      1.17V
[Rising Waveform]
R_fixture= 50.000
V_fixture= 0.0
V_fixture_min= 0.0
V_fixture_max= 0.0
|time   V(typ)   V(min)   V(max)
0s        2.545uV    20.59uV    475.2nV
136ps     19.02uV    4.211uV    9.706mV
187ps     3.279mV    -3.991uV   205.8mV
209ps     21.36mV    -71.76uV   258.3mV
227ps     73.42mV    -27.17uV   280.8mV
264ps     197.2mV    3.272mV    263mV
304ps     253.3mV    32.8mV     254.9mV
367ps     252.1mV    195.8mV    252.9mV
428ps     242.1mV    246.8mV    252.6mV
1ns       241.7mV    235.4mV    252.6mV
[Falling Waveform]
R_fixture= 50.000
V_fixture= 1.100
V_fixture_min= 1.060
V_fixture_max= 1.170
|time   V(typ)   V(min)   V(max)
0s        1.1V       1.06V      1.17V
143ps     1.1V       1.06V      1.169V
216ps     1.095V     1.06V      807.9mV
243ps     1.007V     1.06V      748.5mV
292ps     807.7mV    1.061V     798.2mV
338ps     717.5mV    996.7mV    823.2mV
399ps     751.5mV    794.8mV    834.7mV
477ps     781.4mV    691.5mV    838.6mV
615ps     789.1mV    739.8mV    839.6mV
1ns       789.7mV    747.5mV    839.6mV
[Falling Waveform]
R_fixture= 50.000
V_fixture= 0.0
V_fixture_min= 0.0
V_fixture_max= 0.0
|time   V(typ)   V(min)   V(max)
0s        241.7mV    235.4mV    252.6mV
124ps     240.9mV    235.1mV    257.8mV
139ps     242.8mV    234.8mV    225.6mV
182ps     249.1mV    234.8mV    62.26mV
211ps     185.2mV    239.9mV    21.88mV
256ps     51.77mV    249.3mV    1.493mV
282ps     21.88mV    220.5mV    -967.7uV
349ps     1.362mV    56.44mV    -109.3uV
399ps     -1.99mV    11.74mV    -18.32uV
1ns       4.159uV    23.69uV    2.722uV
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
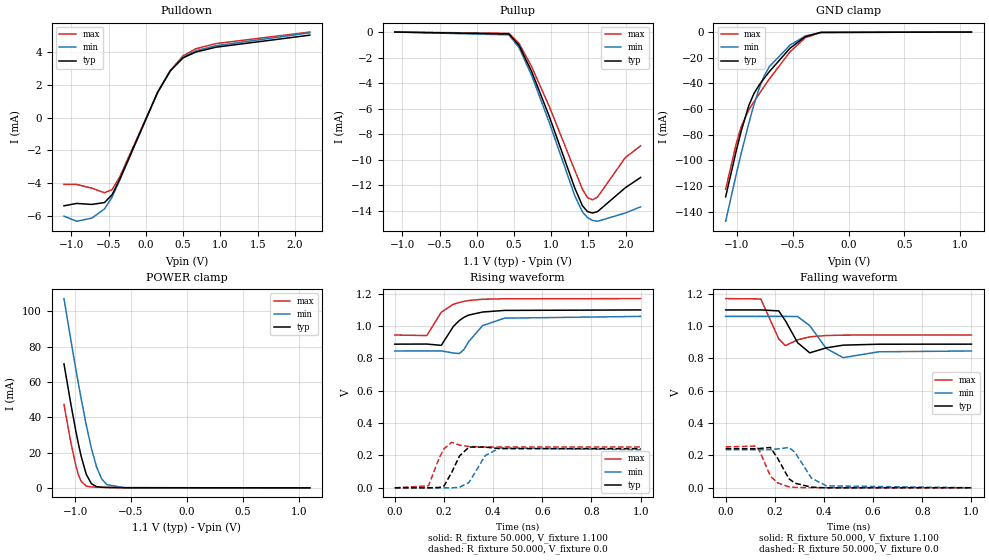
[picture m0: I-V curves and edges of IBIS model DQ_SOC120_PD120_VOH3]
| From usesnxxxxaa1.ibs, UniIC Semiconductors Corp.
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|   Model DQ_SOC120_PD120_VOH3
[Model] DQ_SOC120_PD120_VOH3
Model_type I/O
Polarity   Non-Inverting
Enable   Active-High
Vinl =  0.113V
Vinh =  0.253V
Vmeas =  0.183V
Rref =  50.000
Vref =  0.183V
C_comp   1.110pF   1.087pF   1.118pF
[Model Spec]
Vinh   0.253V   0.247V   0.265V
Vinl   0.113V   0.107V   0.125V
Vmeas   0.183V   NA   NA
Vref   0.183V   NA   NA
Rref   50.000   NA   NA
[Temperature Range]   25.000   0.125k   -40.000
[Voltage Range]   1.100V   1.060V   1.170V
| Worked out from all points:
|   slope of the pulldown table from 0 to 0.165 V, typ, clamps not added: 103 ohm
|   GND clamp passes 1 mA (typ) near -0.30 V on its own axis
|   POWER clamp passes 1 mA (typ) near -0.82 V on its own axis
|   rising waveform, R_fixture 50.000, V_fixture 1.100: 20-80 % time 74.8ps typ, 78ps min, 73.7ps max; typ from 0.888 V to 1.1 V
|   rising waveform, R_fixture 50.000, V_fixture 0.0: 20-80 % time 43.6ps typ, 53.6ps min, 34.8ps max; typ from 0 V to 0.242 V
|   falling waveform, R_fixture 50.000, V_fixture 1.100: 20-80 % time 42.8ps typ, 56ps min, 32.7ps max; typ from 1.1 V to 0.888 V
|   falling waveform, R_fixture 50.000, V_fixture 0.0: 20-80 % time 55ps typ, 61.9ps min, 49ps max; typ from 0.242 V to 0 V
[Pulldown]
|Voltage   I(typ)   I(min)   I(max)
-1.1V     -5.373mA   -6.003mA   -4.071mA
-930mV    -5.229mA   -6.314mA   -4.072mA
-726mV    -5.288mA   -6.12mA    -4.3mA
-556mV    -5.174mA   -5.561mA   -4.579mA
-454mV    -4.694mA   -4.844mA   -4.386mA
-352mV    -3.758mA   -3.821mA   -3.611mA
158mV     1.543mA    1.549mA    1.529mA
328mV     2.841mA    2.867mA    2.862mA
498mV     3.628mA    3.683mA    3.752mA
668mV     3.985mA    4.056mA    4.181mA
940mV     4.28mA     4.369mA    4.5mA
2.2V      5.012mA    5.157mA    5.202mA
[Pullup]
|Voltage   I(typ)   I(min)   I(max)
-1.1V     -58.82pA   9.882nA    0A
432mV     -148.6uA   -221.4uA   -100.6uA
568mV     -1.047mA   -1.224mA   -888.8uA
738mV     -3.104mA   -3.412mA   -2.724mA
976mV     -6.642mA   -7.121mA   -5.859mA
1.316V    -12.21mA   -12.81mA   -10.83mA
1.418V    -13.59mA   -14.07mA   -12.29mA
1.486V    -14.05mA   -14.52mA   -12.96mA
1.554V    -14.16mA   -14.74mA   -13.13mA
1.622V    -14.05mA   -14.81mA   -12.91mA
1.996V    -12.18mA   -14.16mA   -9.815mA
2.2V      -11.38mA   -13.68mA   -8.909mA
[GND_clamp]
|Voltage   I(typ)   I(min)   I(max)
-1.1V     -128.5mA   -147.6mA   -122.6mA
-1.008V   -93.62mA   -112mA     -87.95mA
-962mV    -77.6mA    -95.05mA   -73.96mA
-893mV    -57.36mA   -71.21mA   -60.7mA
-847mV    -48.01mA   -56.81mA   -54.36mA
-801mV    -41.47mA   -44.23mA   -48.33mA
-755mV    -36.02mA   -34.19mA   -42.41mA
-709mV    -30.9mA    -26.94mA   -36.63mA
-525mV    -12.67mA   -10.3mA    -15.49mA
-387mV    -3.615mA   -3.065mA   -4.419mA
-249mV    -281uA     -330.6uA   -301.3uA
1.1V      0A         0A         0A
[POWER_clamp]
|Voltage   I(typ)   I(min)   I(max)
-1.1V     70.27mA    107.3mA    47.25mA
-1.039V   47.68mA    83.93mA    25.86mA
-993mV    31.88mA    66.94mA    12.35mA
-970mV    24.65mA    58.72mA    7.262mA
-947mV    18.06mA    50.74mA    3.761mA
-901mV    7.73mA     35.71mA    987.1uA
-855mV    2.348mA    22.46mA    514uA
-809mV    697.3uA    11.94mA    396.5uA
-763mV    321uA      5.097mA    322.7uA
-717mV    213.8uA    1.813mA    258.1uA
-556mV    65.24uA    79.15uA    81.64uA
1.1V      0A         0A         0A
[Ramp]
| variable   typ   min   max
dV/dt_r   0.145/43.957p   0.141/54.233p   0.152/35.012p
dV/dt_f   0.127/42.915p   0.128/56.600p   0.135/32.753p
R_load = 50.000
[Rising Waveform]
R_fixture= 50.000
V_fixture= 1.100
V_fixture_min= 1.060
V_fixture_max= 1.170
|time   V(typ)   V(min)   V(max)
0s        888.3mV    846.1mV    944.8mV
130ps     889mV      846.4mV    941.5mV
189ps     880.9mV    846.7mV    1.086V
238ps     997.4mV    833.4mV    1.135V
262ps     1.034V     830.1mV    1.146V
281ps     1.054V     854.7mV    1.153V
300ps     1.068V     903.2mV    1.158V
357ps     1.087V     1.003V     1.166V
446ps     1.097V     1.049V     1.169V
1ns       1.1V       1.06V      1.17V
[Rising Waveform]
R_fixture= 50.000
V_fixture= 0.0
V_fixture_min= 0.0
V_fixture_max= 0.0
|time   V(typ)   V(min)   V(max)
0s        2.986uV    24.15uV    556.4nV
137ps     -48.29uV   32.76uV    11.87mV
180ps     2.027mV    22.07uV    182.8mV
200ps     10.89mV    -146.4uV   241.4mV
232ps     96.92mV    -233.1uV   282.1mV
263ps     196.5mV    3.378mV    263.7mV
302ps     252.1mV    32.7mV     255.1mV
368ps     251.5mV    199.5mV    252.8mV
428ps     242.1mV    247mV      252.6mV
1ns       241.7mV    235.4mV    252.6mV
[Falling Waveform]
R_fixture= 50.000
V_fixture= 1.100
V_fixture_min= 1.060
V_fixture_max= 1.170
|time   V(typ)   V(min)   V(max)
0s        1.1V       1.06V      1.17V
143ps     1.1V       1.06V      1.168V
216ps     1.094V     1.06V      920.8mV
243ps     1.033V     1.06V      879.3mV
293ps     896.9mV    1.059V     915.1mV
342ps     834.4mV    1.003V     933.4mV
409ps     865.3mV    861.7mV    941.6mV
478ps     882.1mV    804.7mV    944mV
623ps     887.9mV    841mV      944.7mV
1ns       888.3mV    846.1mV    944.8mV
[Falling Waveform]
R_fixture= 50.000
V_fixture= 0.0
V_fixture_min= 0.0
V_fixture_max= 0.0
|time   V(typ)   V(min)   V(max)
0s        241.7mV    235.4mV    252.6mV
124ps     240.9mV    235.1mV    257.8mV
139ps     242.8mV    234.7mV    224.3mV
182ps     249.2mV    234.8mV    72.05mV
211ps     183.4mV    240mV      30.37mV
257ps     56.48mV    249mV      5.802mV
282ps     28.05mV    219.5mV    1.99mV
349ps     3.654mV    59.21mV    373.7uV
410ps     -564.9uV   11.47mV    88.59uV
1ns       4.843uV    27.74uV    3.338uV
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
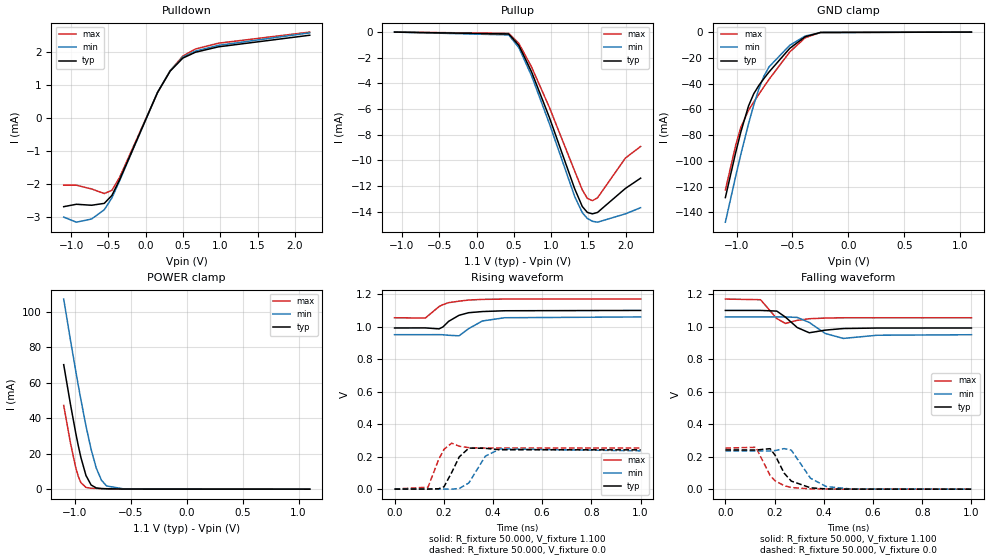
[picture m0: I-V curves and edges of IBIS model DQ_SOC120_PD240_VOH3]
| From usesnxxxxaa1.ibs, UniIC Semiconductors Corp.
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|   Model DQ_SOC120_PD240_VOH3
[Model] DQ_SOC120_PD240_VOH3
Model_type I/O
Polarity   Non-Inverting
Enable   Active-High
Vinl =  0.113V
Vinh =  0.253V
Vmeas =  0.183V
Rref =  50.000
Vref =  0.183V
C_comp   1.110pF   1.087pF   1.118pF
[Model Spec]
Vinh   0.253V   0.247V   0.265V
Vinl   0.113V   0.107V   0.125V
Vmeas   0.183V   NA   NA
Vref   0.183V   NA   NA
Rref   50.000   NA   NA
[Temperature Range]   25.000   0.125k   -40.000
[Voltage Range]   1.100V   1.060V   1.170V
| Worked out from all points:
|   slope of the pulldown table from 0 to 0.165 V, typ, clamps not added: 206 ohm
|   GND clamp passes 1 mA (typ) near -0.30 V on its own axis
|   POWER clamp passes 1 mA (typ) near -0.82 V on its own axis
|   rising waveform, R_fixture 50.000, V_fixture 1.100: 20-80 % time 72.3ps typ, 74.2ps min, 71.9ps max; typ from 0.992 V to 1.1 V
|   rising waveform, R_fixture 50.000, V_fixture 0.0: 20-80 % time 44.7ps typ, 54.7ps min, 35.3ps max; typ from 0 V to 0.242 V
|   falling waveform, R_fixture 50.000, V_fixture 1.100: 20-80 % time 44.2ps typ, 57.8ps min, 33.7ps max; typ from 1.1 V to 0.992 V
|   falling waveform, R_fixture 50.000, V_fixture 0.0: 20-80 % time 62ps typ, 66.4ps min, 58.5ps max; typ from 0.242 V to 0 V
[Pulldown]
|Voltage   I(typ)   I(min)   I(max)
-1.1V     -2.687mA   -3.002mA   -2.035mA
-930mV    -2.614mA   -3.157mA   -2.036mA
-726mV    -2.644mA   -3.06mA    -2.15mA
-556mV    -2.587mA   -2.78mA    -2.289mA
-454mV    -2.347mA   -2.422mA   -2.193mA
-352mV    -1.879mA   -1.911mA   -1.806mA
158mV     771.5uA    774.7uA    764.3uA
328mV     1.42mA     1.434mA    1.431mA
498mV     1.814mA    1.841mA    1.876mA
668mV     1.992mA    2.028mA    2.091mA
974mV     2.154mA    2.199mA    2.264mA
2.2V      2.506mA    2.578mA    2.601mA
[Pullup]
|Voltage   I(typ)   I(min)   I(max)
-1.1V     -58.82pA   9.882nA    0A
432mV     -148.6uA   -221.4uA   -100.6uA
568mV     -1.047mA   -1.224mA   -888.8uA
738mV     -3.104mA   -3.412mA   -2.724mA
976mV     -6.642mA   -7.121mA   -5.859mA
1.316V    -12.21mA   -12.81mA   -10.83mA
1.418V    -13.59mA   -14.07mA   -12.29mA
1.486V    -14.05mA   -14.52mA   -12.96mA
1.554V    -14.16mA   -14.74mA   -13.13mA
1.622V    -14.05mA   -14.81mA   -12.91mA
1.996V    -12.18mA   -14.16mA   -9.815mA
2.2V      -11.38mA   -13.68mA   -8.909mA
[GND_clamp]
|Voltage   I(typ)   I(min)   I(max)
-1.1V     -128.5mA   -147.6mA   -122.6mA
-1.008V   -93.62mA   -112mA     -87.95mA
-962mV    -77.6mA    -95.05mA   -73.96mA
-893mV    -57.36mA   -71.21mA   -60.7mA
-847mV    -48.01mA   -56.81mA   -54.36mA
-801mV    -41.47mA   -44.23mA   -48.33mA
-755mV    -36.02mA   -34.19mA   -42.41mA
-709mV    -30.9mA    -26.94mA   -36.63mA
-525mV    -12.67mA   -10.3mA    -15.49mA
-387mV    -3.615mA   -3.065mA   -4.419mA
-249mV    -281uA     -330.6uA   -301.3uA
1.1V      0A         0A         0A
[POWER_clamp]
|Voltage   I(typ)   I(min)   I(max)
-1.1V     70.27mA    107.3mA    47.25mA
-1.039V   47.68mA    83.93mA    25.86mA
-993mV    31.88mA    66.94mA    12.35mA
-970mV    24.65mA    58.72mA    7.262mA
-947mV    18.06mA    50.74mA    3.761mA
-901mV    7.73mA     35.71mA    987.1uA
-855mV    2.348mA    22.46mA    514uA
-809mV    697.3uA    11.94mA    396.5uA
-763mV    321uA      5.097mA    322.7uA
-717mV    213.8uA    1.813mA    258.1uA
-556mV    65.24uA    79.15uA    81.64uA
1.1V      0A         0A         0A
[Ramp]
| variable   typ   min   max
dV/dt_r   0.145/44.722p   0.141/55.553p   0.152/35.444p
dV/dt_f   64.848m/44.309p   65.673m/58.528p   68.888m/33.816p
R_load = 50.000
[Rising Waveform]
R_fixture= 50.000
V_fixture= 1.100
V_fixture_min= 1.060
V_fixture_max= 1.170
|time   V(typ)   V(min)   V(max)
0s        991.9mV    950.6mV    1.055V
125ps     992.4mV    950.6mV    1.053V
181ps     986.5mV    951.1mV    1.124V
197ps     998.7mV    950.2mV    1.136V
220ps     1.033V     946.9mV    1.148V
262ps     1.07V      943.7mV    1.157V
301ps     1.086V     987.8mV    1.164V
357ps     1.093V     1.035V     1.168V
447ps     1.098V     1.055V     1.17V
1ns       1.1V       1.06V      1.17V
[Rising Waveform]
R_fixture= 50.000
V_fixture= 0.0
V_fixture_min= 0.0
V_fixture_max= 0.0
|time   V(typ)   V(min)   V(max)
0s        3.61uV     29.2uV     671nV
136ps     -105.8uV   61.3uV     11.71mV
179ps     1.785mV    15.19uV    181.3mV
201ps     14.21mV    -288.3uV   244.5mV
232ps     101.4mV    -580.3uV   282.5mV
263ps     198.2mV    3.765mV    263.8mV
302ps     252.4mV    37.59mV    255.1mV
369ps     251mV      202.6mV    252.8mV
429ps     242mV      247.4mV    252.6mV
1ns       241.7mV    235.4mV    252.6mV
[Falling Waveform]
R_fixture= 50.000
V_fixture= 1.100
V_fixture_min= 1.060
V_fixture_max= 1.170
|time   V(typ)   V(min)   V(max)
0s        1.1V       1.06V      1.17V
143ps     1.1V       1.06V      1.166V
209ps     1.096V     1.06V      1.05V
244ps     1.059V     1.06V      1.02V
292ps     994.8mV    1.057V     1.039V
341ps     962.5mV    1.026V     1.049V
406ps     978.8mV    958.2mV    1.053V
479ps     988.6mV    927.7mV    1.055V
617ps     991.7mV    947.4mV    1.055V
1ns       991.9mV    950.5mV    1.055V
[Falling Waveform]
R_fixture= 50.000
V_fixture= 0.0
V_fixture_min= 0.0
V_fixture_max= 0.0
|time   V(typ)   V(min)   V(max)
0s        241.7mV    235.4mV    252.6mV
124ps     240.9mV    235.1mV    257.8mV
182ps     249.2mV    234.8mV    83.49mV
202ps     209.3mV    237.7mV    51.73mV
239ps     98.12mV    249.7mV    21.27mV
268ps     49.56mV    240.2mV    9.978mV
346ps     8.311mV    67.3mV     1.899mV
410ps     1.385mV    15.96mV    509.9uV
509ps     184.2uV    1.494mV    70.66uV
1ns       5.945uV    33.26uV    4.079uV
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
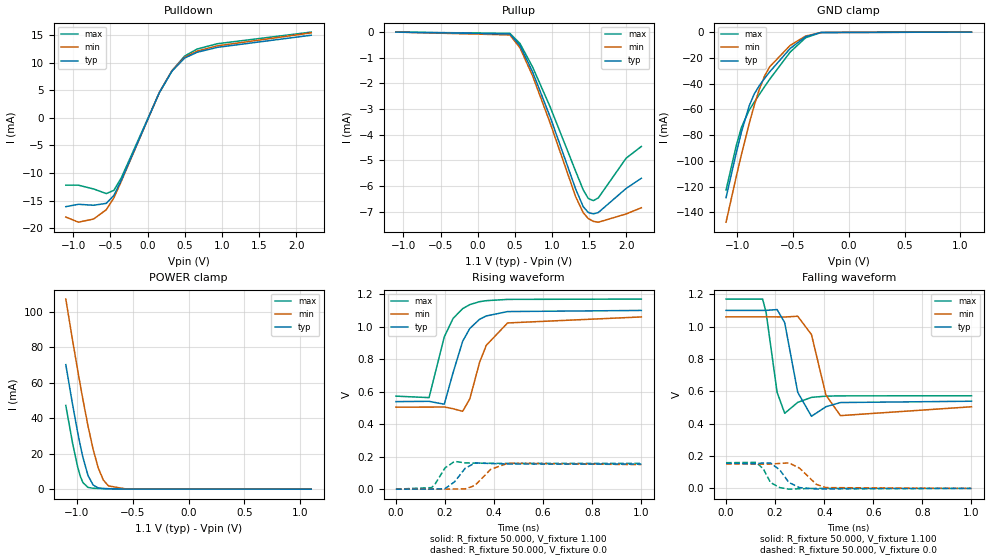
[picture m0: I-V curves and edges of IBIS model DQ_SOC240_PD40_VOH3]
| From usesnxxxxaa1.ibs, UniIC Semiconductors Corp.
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|   Model DQ_SOC240_PD40_VOH3
[Model] DQ_SOC240_PD40_VOH3
Model_type I/O
Polarity   Non-Inverting
Enable   Active-High
Vinl =  0.113V
Vinh =  0.253V
Vmeas =  0.183V
Rref =  50.000
Vref =  0.183V
C_comp   1.110pF   1.087pF   1.118pF
[Model Spec]
Vinh   0.253V   0.247V   0.265V
Vinl   0.113V   0.107V   0.125V
Vmeas   0.183V   NA   NA
Vref   0.183V   NA   NA
Rref   50.000   NA   NA
[Temperature Range]   25.000   0.125k   -40.000
[Voltage Range]   1.100V   1.060V   1.170V
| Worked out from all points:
|   slope of the pulldown table from 0 to 0.165 V, typ, clamps not added: 34.3 ohm
|   GND clamp passes 1 mA (typ) near -0.30 V on its own axis
|   POWER clamp passes 1 mA (typ) near -0.82 V on its own axis
|   rising waveform, R_fixture 50.000, V_fixture 1.100: 20-80 % time 77.3ps typ, 82.1ps min, 75.2ps max; typ from 0.539 V to 1.1 V
|   rising waveform, R_fixture 50.000, V_fixture 0.0: 20-80 % time 47ps typ, 57.4ps min, 38.1ps max; typ from 0 V to 0.154 V
|   falling waveform, R_fixture 50.000, V_fixture 1.100: 20-80 % time 38.9ps typ, 50.3ps min, 30ps max; typ from 1.1 V to 0.539 V
|   falling waveform, R_fixture 50.000, V_fixture 0.0: 20-80 % time 47.5ps typ, 59.9ps min, 35.2ps max; typ from 0.154 V to 0 V
[Pulldown]
|Voltage   I(typ)   I(min)   I(max)
-1.1V     -16.12mA   -18.01mA   -12.21mA
-930mV    -15.69mA   -18.94mA   -12.21mA
-726mV    -15.86mA   -18.36mA   -12.9mA
-556mV    -15.52mA   -16.68mA   -13.74mA
-454mV    -14.08mA   -14.53mA   -13.16mA
-352mV    -11.27mA   -11.46mA   -10.83mA
158mV     4.629mA    4.648mA    4.586mA
328mV     8.522mA    8.602mA    8.586mA
498mV     10.89mA    11.05mA    11.26mA
668mV     11.95mA    12.17mA    12.54mA
940mV     12.84mA    13.11mA    13.5mA
2.2V      15.04mA    15.47mA    15.61mA
[Pullup]
|Voltage   I(typ)   I(min)   I(max)
-1.1V     -58.82pA   10.24nA    0A
432mV     -74.32uA   -110.7uA   -50.31uA
568mV     -523.4uA   -612.1uA   -444.4uA
738mV     -1.552mA   -1.706mA   -1.362mA
976mV     -3.321mA   -3.56mA    -2.93mA
1.316V    -6.107mA   -6.406mA   -5.413mA
1.418V    -6.797mA   -7.033mA   -6.143mA
1.486V    -7.024mA   -7.26mA    -6.478mA
1.554V    -7.079mA   -7.37mA    -6.564mA
1.622V    -7.025mA   -7.403mA   -6.455mA
1.996V    -6.088mA   -7.082mA   -4.908mA
2.2V      -5.692mA   -6.84mA    -4.454mA
[GND_clamp]
|Voltage   I(typ)   I(min)   I(max)
-1.1V     -128.5mA   -147.6mA   -122.6mA
-1.008V   -93.62mA   -112mA     -87.95mA
-962mV    -77.6mA    -95.05mA   -73.96mA
-893mV    -57.36mA   -71.21mA   -60.7mA
-847mV    -48.01mA   -56.81mA   -54.36mA
-801mV    -41.47mA   -44.23mA   -48.33mA
-755mV    -36.02mA   -34.19mA   -42.41mA
-709mV    -30.9mA    -26.94mA   -36.63mA
-525mV    -12.67mA   -10.3mA    -15.49mA
-387mV    -3.615mA   -3.065mA   -4.419mA
-249mV    -281uA     -330.6uA   -301.3uA
1.1V      0A         0A         0A
[POWER_clamp]
|Voltage   I(typ)   I(min)   I(max)
-1.1V     70.27mA    107.3mA    47.25mA
-1.039V   47.68mA    83.93mA    25.86mA
-993mV    31.88mA    66.94mA    12.35mA
-970mV    24.65mA    58.72mA    7.262mA
-947mV    18.06mA    50.74mA    3.761mA
-901mV    7.73mA     35.71mA    987.1uA
-855mV    2.348mA    22.46mA    514uA
-809mV    697.3uA    11.94mA    396.5uA
-763mV    321uA      5.097mA    322.7uA
-717mV    213.8uA    1.813mA    258.1uA
-556mV    65.24uA    79.15uA    81.64uA
1.1V      0A         0A         0A
[Ramp]
| variable   typ   min   max
dV/dt_r   92.531m/47.009p   90.530m/58.050p   95.291m/38.202p
dV/dt_f   0.337/39.369p   0.333/51.398p   0.359/30.118p
R_load = 50.000
[Rising Waveform]
R_fixture= 50.000
V_fixture= 1.100
V_fixture_min= 1.060
V_fixture_max= 1.170
|time   V(typ)   V(min)   V(max)
0s        538.9mV    504.5mV    572.5mV
135ps     540.5mV    505mV      563.4mV
197ps     522.8mV    506mV      937.5mV
233ps     717.8mV    495mV      1.051V
272ps     910.5mV    479.2mV    1.111V
301ps     988.9mV    555.6mV    1.136V
341ps     1.046V     781.2mV    1.154V
368ps     1.066V     885.1mV    1.16V
455ps     1.093V     1.023V     1.168V
1ns       1.1V       1.06V      1.17V
[Rising Waveform]
R_fixture= 50.000
V_fixture= 0.0
V_fixture_min= 0.0
V_fixture_max= 0.0
|time   V(typ)   V(min)   V(max)
0s        1.764uV    14.27uV    330.5nV
145ps     244.4uV    -57.61uV   9.46mV
158ps     510.8uV    -27.45uV   27.34mV
200ps     2.97mV     177.8uV    130.9mV
239ps     45.15mV    1.237mV    170.8mV
282ps     128.1mV    1.352mV    161.9mV
322ps     161.5mV    22.74mV    159.9mV
386ps     157.8mV    121.9mV    159mV
456ps     154.7mV    159.4mV    158.8mV
1ns       154.2mV    150.9mV    158.8mV
[Falling Waveform]
R_fixture= 50.000
V_fixture= 1.100
V_fixture_min= 1.060
V_fixture_max= 1.170
|time   V(typ)   V(min)   V(max)
0s        1.1V       1.06V      1.17V
149ps     1.1V       1.06V      1.17V
163ps     1.1V       1.06V      1.089V
208ps     1.105V     1.06V      593.9mV
239ps     1.024V     1.059V     464.1mV
292ps     594.1mV    1.064V     531.6mV
348ps     445.6mV    950.8mV    562.6mV
407ps     504.9mV    577mV      570.2mV
466ps     530.6mV    449.8mV    571.9mV
1ns       538.8mV    504.5mV    572.5mV
[Falling Waveform]
R_fixture= 50.000
V_fixture= 0.0
V_fixture_min= 0.0
V_fixture_max= 0.0
|time   V(typ)   V(min)   V(max)
0s        154.2mV    150.9mV    158.8mV
123ps     153.8mV    150.8mV    160.7mV
152ps     157mV      150.4mV    120.5mV
181ps     157.2mV    150.5mV    36.73mV
219ps     114.2mV    154.5mV    5.124mV
256ps     36.88mV    157.6mV    -4.6mV
299ps     5.017mV    125.9mV    -2.094mV
368ps     -3.386mV   24.94mV    -99.49uV
408ps     -2.884mV   4.941mV    -16.13uV
1ns       1.709uV    14.94uV    593.1nV
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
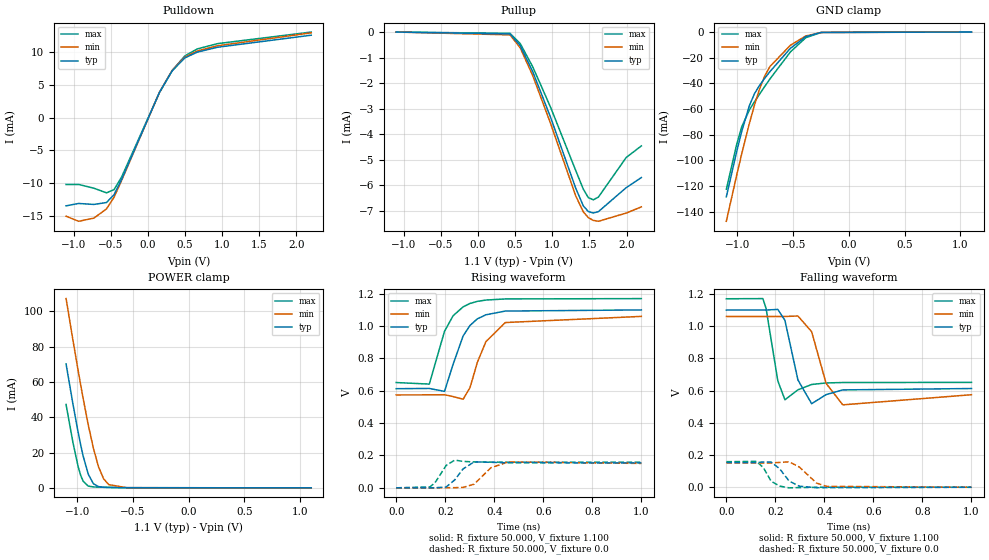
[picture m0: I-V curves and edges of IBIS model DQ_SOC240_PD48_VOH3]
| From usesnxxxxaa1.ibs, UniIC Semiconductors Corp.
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|   Model DQ_SOC240_PD48_VOH3
[Model] DQ_SOC240_PD48_VOH3
Model_type I/O
Polarity   Non-Inverting
Enable   Active-High
Vinl =  0.113V
Vinh =  0.253V
Vmeas =  0.183V
Rref =  50.000
Vref =  0.183V
C_comp   1.110pF   1.087pF   1.118pF
[Model Spec]
Vinh   0.253V   0.247V   0.265V
Vinl   0.113V   0.107V   0.125V
Vmeas   0.183V   NA   NA
Vref   0.183V   NA   NA
Rref   50.000   NA   NA
[Temperature Range]   25.000   0.125k   -40.000
[Voltage Range]   1.100V   1.060V   1.170V
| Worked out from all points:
|   slope of the pulldown table from 0 to 0.165 V, typ, clamps not added: 41.1 ohm
|   GND clamp passes 1 mA (typ) near -0.30 V on its own axis
|   POWER clamp passes 1 mA (typ) near -0.82 V on its own axis
|   rising waveform, R_fixture 50.000, V_fixture 1.100: 20-80 % time 77.1ps typ, 81.7ps min, 75.2ps max; typ from 0.613 V to 1.1 V
|   rising waveform, R_fixture 50.000, V_fixture 0.0: 20-80 % time 48ps typ, 58.8ps min, 38.7ps max; typ from 0 V to 0.154 V
|   falling waveform, R_fixture 50.000, V_fixture 1.100: 20-80 % time 39.6ps typ, 51.9ps min, 30.5ps max; typ from 1.1 V to 0.613 V
|   falling waveform, R_fixture 50.000, V_fixture 0.0: 20-80 % time 50.2ps typ, 62ps min, 37.9ps max; typ from 0.154 V to 0 V
[Pulldown]
|Voltage   I(typ)   I(min)   I(max)
-1.1V     -13.43mA   -15.01mA   -10.18mA
-930mV    -13.07mA   -15.78mA   -10.18mA
-726mV    -13.22mA   -15.3mA    -10.75mA
-556mV    -12.93mA   -13.9mA    -11.45mA
-454mV    -11.73mA   -12.11mA   -10.97mA
-352mV    -9.395mA   -9.553mA   -9.028mA
158mV     3.857mA    3.874mA    3.821mA
328mV     7.102mA    7.168mA    7.155mA
498mV     9.071mA    9.207mA    9.38mA
668mV     9.963mA    10.14mA    10.45mA
940mV     10.7mA     10.92mA    11.25mA
2.2V      12.53mA    12.89mA    13.01mA
[Pullup]
|Voltage   I(typ)   I(min)   I(max)
-1.1V     -58.82pA   10.24nA    0A
432mV     -74.32uA   -110.7uA   -50.31uA
568mV     -523.4uA   -612.1uA   -444.4uA
738mV     -1.552mA   -1.706mA   -1.362mA
976mV     -3.321mA   -3.56mA    -2.93mA
1.316V    -6.107mA   -6.406mA   -5.413mA
1.418V    -6.797mA   -7.033mA   -6.143mA
1.486V    -7.024mA   -7.26mA    -6.478mA
1.554V    -7.079mA   -7.37mA    -6.564mA
1.622V    -7.025mA   -7.403mA   -6.455mA
1.996V    -6.088mA   -7.082mA   -4.908mA
2.2V      -5.692mA   -6.84mA    -4.454mA
[GND_clamp]
|Voltage   I(typ)   I(min)   I(max)
-1.1V     -128.5mA   -147.6mA   -122.6mA
-1.008V   -93.62mA   -112mA     -87.95mA
-962mV    -77.6mA    -95.05mA   -73.96mA
-893mV    -57.36mA   -71.21mA   -60.7mA
-847mV    -48.01mA   -56.81mA   -54.36mA
-801mV    -41.47mA   -44.23mA   -48.33mA
-755mV    -36.02mA   -34.19mA   -42.41mA
-709mV    -30.9mA    -26.94mA   -36.63mA
-525mV    -12.67mA   -10.3mA    -15.49mA
-387mV    -3.615mA   -3.065mA   -4.419mA
-249mV    -281uA     -330.6uA   -301.3uA
1.1V      0A         0A         0A
[POWER_clamp]
|Voltage   I(typ)   I(min)   I(max)
-1.1V     70.27mA    107.3mA    47.25mA
-1.039V   47.68mA    83.93mA    25.86mA
-993mV    31.88mA    66.94mA    12.35mA
-970mV    24.65mA    58.72mA    7.262mA
-947mV    18.06mA    50.74mA    3.761mA
-901mV    7.73mA     35.71mA    987.1uA
-855mV    2.348mA    22.46mA    514uA
-809mV    697.3uA    11.94mA    396.5uA
-763mV    321uA      5.097mA    322.7uA
-717mV    213.8uA    1.813mA    258.1uA
-556mV    65.24uA    79.15uA    81.64uA
1.1V      0A         0A         0A
[Ramp]
| variable   typ   min   max
dV/dt_r   92.531m/47.969p   90.530m/59.492p   95.291m/38.898p
dV/dt_f   0.292/39.850p   0.291/52.748p   0.311/30.586p
R_load = 50.000
[Rising Waveform]
R_fixture= 50.000
V_fixture= 1.100
V_fixture_min= 1.060
V_fixture_max= 1.170
|time   V(typ)   V(min)   V(max)
0s        613mV      574.4mV    651mV
135ps     614.5mV    574.9mV    641.4mV
197ps     596.3mV    575.7mV    967.7mV
232ps     763.5mV    564.4mV    1.064V
273ps     939.4mV    547.7mV    1.119V
301ps     1.004V     619.7mV    1.14V
331ps     1.045V     775.8mV    1.153V
366ps     1.07V      904.2mV    1.161V
445ps     1.093V     1.022V     1.168V
1ns       1.1V       1.06V      1.17V
[Rising Waveform]
R_fixture= 50.000
V_fixture= 0.0
V_fixture_min= 0.0
V_fixture_max= 0.0
|time   V(typ)   V(min)   V(max)
0s        1.965uV    15.9uV     367.9nV
138ps     95.76uV    -45.86uV   5.981mV
158ps     377.3uV    -11.34uV   30.9mV
204ps     5.335mV    176.1uV    139.1mV
239ps     49.41mV    1.06mV     171.4mV
273ps     117.5mV    2.474mV    163.3mV
318ps     160.2mV    22.76mV    160.1mV
386ps     157.9mV    124mV      159mV
457ps     154.7mV    159.9mV    158.9mV
1ns       154.2mV    150.9mV    158.8mV
[Falling Waveform]
R_fixture= 50.000
V_fixture= 1.100
V_fixture_min= 1.060
V_fixture_max= 1.170
|time   V(typ)   V(min)   V(max)
0s        1.1V       1.06V      1.17V
149ps     1.1V       1.06V      1.171V
162ps     1.1V       1.06V      1.111V
210ps     1.104V     1.06V      660.3mV
239ps     1.036V     1.06V      543.2mV
292ps     666.1mV    1.063V     604.8mV
348ps     518.7mV    965.5mV    638mV
407ps     575.1mV    644.7mV    647.5mV
475ps     604.4mV    511.6mV    650.2mV
1ns       612.9mV    574.4mV    651mV
[Falling Waveform]
R_fixture= 50.000
V_fixture= 0.0
V_fixture_min= 0.0
V_fixture_max= 0.0
|time   V(typ)   V(min)   V(max)
0s        154.2mV    150.9mV    158.8mV
123ps     153.7mV    150.8mV    160.8mV
151ps     156.9mV    150.4mV    122mV
183ps     156.5mV    150.6mV    37.13mV
218ps     114mV      154.4mV    7.177mV
256ps     38.63mV    157.8mV    -3.474mV
298ps     6.595mV    125.5mV    -2.037mV
368ps     -2.868mV   26.01mV    -128.3uV
408ps     -2.63mV    5.862mV    -25.38uV
1ns       1.943uV    16.58uV    631.9nV
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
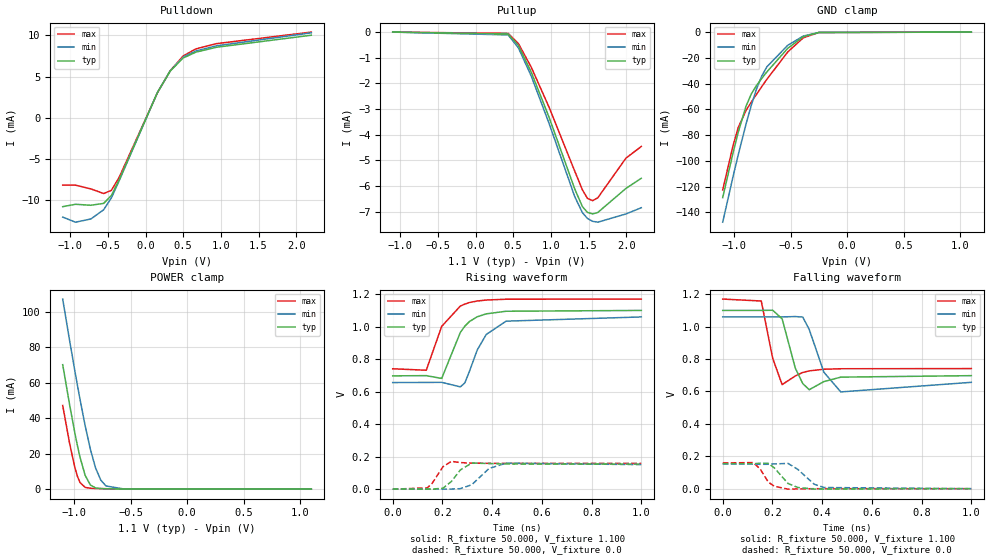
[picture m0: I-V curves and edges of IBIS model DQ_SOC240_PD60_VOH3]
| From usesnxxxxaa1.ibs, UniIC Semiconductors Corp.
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|   Model DQ_SOC240_PD60_VOH3
[Model] DQ_SOC240_PD60_VOH3
Model_type I/O
Polarity   Non-Inverting
Enable   Active-High
Vinl =  0.113V
Vinh =  0.253V
Vmeas =  0.183V
Rref =  50.000
Vref =  0.183V
C_comp   1.110pF   1.087pF   1.118pF
[Model Spec]
Vinh   0.253V   0.247V   0.265V
Vinl   0.113V   0.107V   0.125V
Vmeas   0.183V   NA   NA
Vref   0.183V   NA   NA
Rref   50.000   NA   NA
[Temperature Range]   25.000   0.125k   -40.000
[Voltage Range]   1.100V   1.060V   1.170V
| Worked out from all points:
|   slope of the pulldown table from 0 to 0.165 V, typ, clamps not added: 51.4 ohm
|   GND clamp passes 1 mA (typ) near -0.30 V on its own axis
|   POWER clamp passes 1 mA (typ) near -0.82 V on its own axis
|   rising waveform, R_fixture 50.000, V_fixture 1.100: 20-80 % time 76.9ps typ, 81.2ps min, 75ps max; typ from 0.697 V to 1.1 V
|   rising waveform, R_fixture 50.000, V_fixture 0.0: 20-80 % time 48.8ps typ, 60.5ps min, 39.5ps max; typ from 0 V to 0.154 V
|   falling waveform, R_fixture 50.000, V_fixture 1.100: 20-80 % time 40ps typ, 52.9ps min, 30.8ps max; typ from 1.1 V to 0.697 V
|   falling waveform, R_fixture 50.000, V_fixture 0.0: 20-80 % time 53ps typ, 64.7ps min, 41.3ps max; typ from 0.154 V to 0 V
[Pulldown]
|Voltage   I(typ)   I(min)   I(max)
-1.1V     -10.75mA   -12.01mA   -8.142mA
-930mV    -10.46mA   -12.63mA   -8.143mA
-726mV    -10.58mA   -12.24mA   -8.599mA
-556mV    -10.35mA   -11.12mA   -9.157mA
-454mV    -9.387mA   -9.688mA   -8.773mA
-352mV    -7.516mA   -7.642mA   -7.222mA
158mV     3.086mA    3.099mA    3.057mA
328mV     5.681mA    5.734mA    5.724mA
498mV     7.257mA    7.365mA    7.504mA
668mV     7.97mA     8.112mA    8.363mA
940mV     8.561mA    8.737mA    9mA
2.2V      10.02mA    10.31mA    10.4mA
[Pullup]
|Voltage   I(typ)   I(min)   I(max)
-1.1V     -58.82pA   10.24nA    0A
432mV     -74.32uA   -110.7uA   -50.31uA
568mV     -523.4uA   -612.1uA   -444.4uA
738mV     -1.552mA   -1.706mA   -1.362mA
976mV     -3.321mA   -3.56mA    -2.93mA
1.316V    -6.107mA   -6.406mA   -5.413mA
1.418V    -6.797mA   -7.033mA   -6.143mA
1.486V    -7.024mA   -7.26mA    -6.478mA
1.554V    -7.079mA   -7.37mA    -6.564mA
1.622V    -7.025mA   -7.403mA   -6.455mA
1.996V    -6.088mA   -7.082mA   -4.908mA
2.2V      -5.692mA   -6.84mA    -4.454mA
[GND_clamp]
|Voltage   I(typ)   I(min)   I(max)
-1.1V     -128.5mA   -147.6mA   -122.6mA
-1.008V   -93.62mA   -112mA     -87.95mA
-962mV    -77.6mA    -95.05mA   -73.96mA
-893mV    -57.36mA   -71.21mA   -60.7mA
-847mV    -48.01mA   -56.81mA   -54.36mA
-801mV    -41.47mA   -44.23mA   -48.33mA
-755mV    -36.02mA   -34.19mA   -42.41mA
-709mV    -30.9mA    -26.94mA   -36.63mA
-525mV    -12.67mA   -10.3mA    -15.49mA
-387mV    -3.615mA   -3.065mA   -4.419mA
-249mV    -281uA     -330.6uA   -301.3uA
1.1V      0A         0A         0A
[POWER_clamp]
|Voltage   I(typ)   I(min)   I(max)
-1.1V     70.27mA    107.3mA    47.25mA
-1.039V   47.68mA    83.93mA    25.86mA
-993mV    31.88mA    66.94mA    12.35mA
-970mV    24.65mA    58.72mA    7.262mA
-947mV    18.06mA    50.74mA    3.761mA
-901mV    7.73mA     35.71mA    987.1uA
-855mV    2.348mA    22.46mA    514uA
-809mV    697.3uA    11.94mA    396.5uA
-763mV    321uA      5.097mA    322.7uA
-717mV    213.8uA    1.813mA    258.1uA
-556mV    65.24uA    79.15uA    81.64uA
1.1V      0A         0A         0A
[Ramp]
| variable   typ   min   max
dV/dt_r   92.531m/49.080p   90.528m/60.911p   95.291m/39.688p
dV/dt_f   0.242/40.197p   0.242/53.667p   0.257/30.874p
R_load = 50.000
[Rising Waveform]
R_fixture= 50.000
V_fixture= 1.100
V_fixture_min= 1.060
V_fixture_max= 1.170
|time   V(typ)   V(min)   V(max)
0s        697.4mV    656.2mV    741mV
135ps     698.7mV    656.8mV    731.9mV
197ps     681.5mV    657.5mV    1.002V
272ps     964.7mV    629.6mV    1.127V
290ps     1.003V     653.9mV    1.139V
309ps     1.032V     726.7mV    1.149V
340ps     1.061V     856.4mV    1.158V
376ps     1.079V     951.9mV    1.164V
456ps     1.095V     1.034V     1.169V
1ns       1.1V       1.06V      1.17V
[Rising Waveform]
R_fixture= 50.000
V_fixture= 0.0
V_fixture_min= 0.0
V_fixture_max= 0.0
|time   V(typ)   V(min)   V(max)
0s        2.218uV    17.94uV    414.7nV
139ps     49.34uV    -24.19uV   7.807mV
158ps     234.6uV    2.817uV    34.66mV
202ps     5.849mV    76.03uV    137.8mV
236ps     47.3mV     684.8uV    171.3mV
272ps     118.2mV    3.105mV    163.6mV
318ps     160.8mV    27.23mV    160.2mV
388ps     157.7mV    127.9mV    159mV
457ps     154.7mV    160.2mV    158.9mV
1ns       154.2mV    150.9mV    158.8mV
[Falling Waveform]
R_fixture= 50.000
V_fixture= 1.100
V_fixture_min= 1.060
V_fixture_max= 1.170
|time   V(typ)   V(min)   V(max)
0s        1.1V       1.06V      1.17V
155ps     1.1V       1.06V      1.158V
201ps     1.101V     1.06V      804.7mV
239ps     1.048V     1.06V      642.1mV
292ps     743.7mV    1.062V     695.5mV
322ps     648.6mV    1.059V     717mV
348ps     610.5mV    982.3mV    726.9mV
407ps     660.7mV    718.4mV    736.9mV
475ps     688.2mV    597mV      740mV
1ns       697.4mV    656.2mV    741mV
[Falling Waveform]
R_fixture= 50.000
V_fixture= 0.0
V_fixture_min= 0.0
V_fixture_max= 0.0
|time   V(typ)   V(min)   V(max)
0s        154.2mV    150.9mV    158.8mV
123ps     153.7mV    150.8mV    160.9mV
151ps     157mV      150.4mV    120.9mV
183ps     156.6mV    150.5mV    41.16mV
207ps     128.9mV    152.7mV    15.06mV
263ps     31.83mV    155.7mV    -3.093mV
302ps     7.354mV    119.1mV    -1.452mV
368ps     -2.157mV   27.38mV    -144.2uV
408ps     -2.261mV   7.124mV    -34.52uV
1ns       2.36uV     18.65uV    713.8nV
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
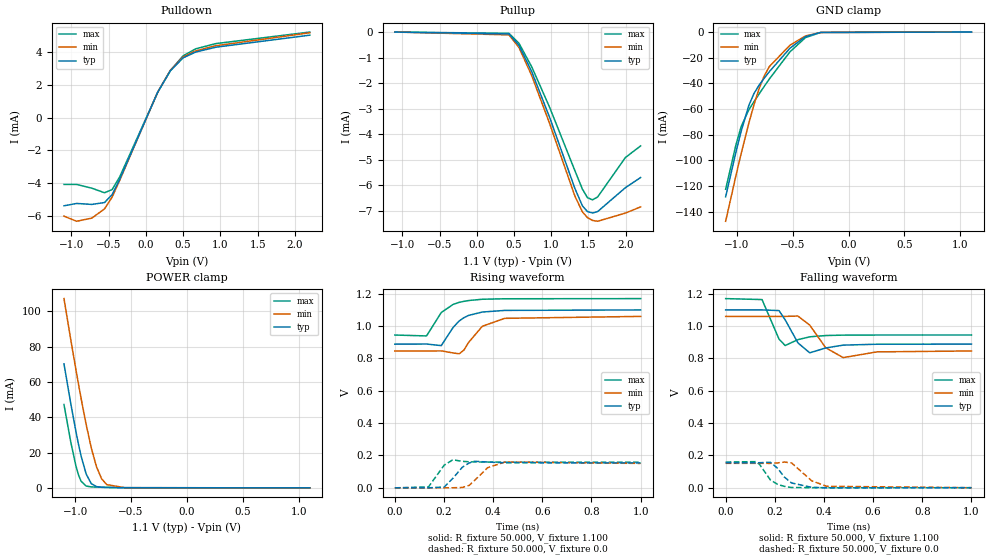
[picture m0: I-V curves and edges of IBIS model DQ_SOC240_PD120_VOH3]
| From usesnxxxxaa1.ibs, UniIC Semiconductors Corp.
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|   Model DQ_SOC240_PD120_VOH3
[Model] DQ_SOC240_PD120_VOH3
Model_type I/O
Polarity   Non-Inverting
Enable   Active-High
Vinl =  0.113V
Vinh =  0.253V
Vmeas =  0.183V
Rref =  50.000
Vref =  0.183V
C_comp   1.110pF   1.087pF   1.118pF
[Model Spec]
Vinh   0.253V   0.247V   0.265V
Vinl   0.113V   0.107V   0.125V
Vmeas   0.183V   NA   NA
Vref   0.183V   NA   NA
Rref   50.000   NA   NA
[Temperature Range]   25.000   0.125k   -40.000
[Voltage Range]   1.100V   1.060V   1.170V
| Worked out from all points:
|   slope of the pulldown table from 0 to 0.165 V, typ, clamps not added: 103 ohm
|   GND clamp passes 1 mA (typ) near -0.30 V on its own axis
|   POWER clamp passes 1 mA (typ) near -0.82 V on its own axis
|   rising waveform, R_fixture 50.000, V_fixture 1.100: 20-80 % time 75.8ps typ, 79.3ps min, 74.3ps max; typ from 0.888 V to 1.1 V
|   rising waveform, R_fixture 50.000, V_fixture 0.0: 20-80 % time 49.3ps typ, 59.9ps min, 39.6ps max; typ from 0 V to 0.154 V
|   falling waveform, R_fixture 50.000, V_fixture 1.100: 20-80 % time 42.4ps typ, 55.4ps min, 32.3ps max; typ from 1.1 V to 0.888 V
|   falling waveform, R_fixture 50.000, V_fixture 0.0: 20-80 % time 56.7ps typ, 64.6ps min, 50.5ps max; typ from 0.154 V to 0 V
[Pulldown]
|Voltage   I(typ)   I(min)   I(max)
-1.1V     -5.373mA   -6.003mA   -4.071mA
-930mV    -5.229mA   -6.314mA   -4.072mA
-726mV    -5.288mA   -6.12mA    -4.3mA
-556mV    -5.174mA   -5.561mA   -4.579mA
-454mV    -4.694mA   -4.844mA   -4.386mA
-352mV    -3.758mA   -3.821mA   -3.611mA
158mV     1.543mA    1.549mA    1.529mA
328mV     2.841mA    2.867mA    2.862mA
498mV     3.628mA    3.683mA    3.752mA
668mV     3.985mA    4.056mA    4.181mA
940mV     4.28mA     4.369mA    4.5mA
2.2V      5.012mA    5.157mA    5.202mA
[Pullup]
|Voltage   I(typ)   I(min)   I(max)
-1.1V     -58.82pA   10.24nA    0A
432mV     -74.32uA   -110.7uA   -50.31uA
568mV     -523.4uA   -612.1uA   -444.4uA
738mV     -1.552mA   -1.706mA   -1.362mA
976mV     -3.321mA   -3.56mA    -2.93mA
1.316V    -6.107mA   -6.406mA   -5.413mA
1.418V    -6.797mA   -7.033mA   -6.143mA
1.486V    -7.024mA   -7.26mA    -6.478mA
1.554V    -7.079mA   -7.37mA    -6.564mA
1.622V    -7.025mA   -7.403mA   -6.455mA
1.996V    -6.088mA   -7.082mA   -4.908mA
2.2V      -5.692mA   -6.84mA    -4.454mA
[GND_clamp]
|Voltage   I(typ)   I(min)   I(max)
-1.1V     -128.5mA   -147.6mA   -122.6mA
-1.008V   -93.62mA   -112mA     -87.95mA
-962mV    -77.6mA    -95.05mA   -73.96mA
-893mV    -57.36mA   -71.21mA   -60.7mA
-847mV    -48.01mA   -56.81mA   -54.36mA
-801mV    -41.47mA   -44.23mA   -48.33mA
-755mV    -36.02mA   -34.19mA   -42.41mA
-709mV    -30.9mA    -26.94mA   -36.63mA
-525mV    -12.67mA   -10.3mA    -15.49mA
-387mV    -3.615mA   -3.065mA   -4.419mA
-249mV    -281uA     -330.6uA   -301.3uA
1.1V      0A         0A         0A
[POWER_clamp]
|Voltage   I(typ)   I(min)   I(max)
-1.1V     70.27mA    107.3mA    47.25mA
-1.039V   47.68mA    83.93mA    25.86mA
-993mV    31.88mA    66.94mA    12.35mA
-970mV    24.65mA    58.72mA    7.262mA
-947mV    18.06mA    50.74mA    3.761mA
-901mV    7.73mA     35.71mA    987.1uA
-855mV    2.348mA    22.46mA    514uA
-809mV    697.3uA    11.94mA    396.5uA
-763mV    321uA      5.097mA    322.7uA
-717mV    213.8uA    1.813mA    258.1uA
-556mV    65.24uA    79.15uA    81.64uA
1.1V      0A         0A         0A
[Ramp]
| variable   typ   min   max
dV/dt_r   92.530m/49.441p   90.524m/60.126p   95.291m/39.756p
dV/dt_f   0.127/42.588p   0.128/55.512p   0.135/32.645p
R_load = 50.000
[Rising Waveform]
R_fixture= 50.000
V_fixture= 1.100
V_fixture_min= 1.060
V_fixture_max= 1.170
|time   V(typ)   V(min)   V(max)
0s        888.3mV    846.1mV    944.8mV
129ps     889.1mV    846.4mV    939.2mV
189ps     879.3mV    846.8mV    1.084V
237ps     991.6mV    834mV      1.134V
262ps     1.032V     829mV      1.147V
281ps     1.052V     851.5mV    1.153V
300ps     1.066V     898.7mV    1.158V
356ps     1.087V     999.1mV    1.166V
447ps     1.097V     1.048V     1.169V
1ns       1.1V       1.06V      1.17V
[Rising Waveform]
R_fixture= 50.000
V_fixture= 0.0
V_fixture_min= 0.0
V_fixture_max= 0.0
|time   V(typ)   V(min)   V(max)
0s        2.986uV    24.15uV    556.4nV
137ps     50.75uV    10.52uV    5.901mV
201ps     5.257mV    50.25uV    140.4mV
236ps     58.81mV    395.3uV    173.4mV
275ps     128mV      2.337mV    163.8mV
302ps     153.2mV    14.89mV    161.2mV
322ps     164.2mV    42.35mV    160.2mV
378ps     159.7mV    124.9mV    159.2mV
448ps     154.9mV    159.4mV    158.9mV
1ns       154.2mV    150.9mV    158.8mV
[Falling Waveform]
R_fixture= 50.000
V_fixture= 1.100
V_fixture_min= 1.060
V_fixture_max= 1.170
|time   V(typ)   V(min)   V(max)
0s        1.1V       1.06V      1.17V
148ps     1.1V       1.06V      1.164V
217ps     1.096V     1.06V      919.6mV
242ps     1.039V     1.06V      879.8mV
294ps     896mV      1.062V     916mV
342ps     834.6mV    1.006V     933.5mV
407ps     864.6mV    865.9mV    941.5mV
478ps     882.1mV    805mV      944mV
616ps     887.8mV    840.4mV    944.7mV
1ns       888.3mV    846.1mV    944.8mV
[Falling Waveform]
R_fixture= 50.000
V_fixture= 0.0
V_fixture_min= 0.0
V_fixture_max= 0.0
|time   V(typ)   V(min)   V(max)
0s        154.2mV    150.9mV    158.8mV
123ps     153.7mV    150.8mV    161.3mV
138ps     154.7mV    150.6mV    143.9mV
182ps     157.5mV    150.5mV    48.26mV
212ps     119.1mV    153.5mV    19.97mV
239ps     65.46mV    158.7mV    8.209mV
268ps     29.35mV    153.6mV    1.322mV
350ps     2.289mV    42.73mV    115.6uV
411ps     -809.8uV   8.736mV    26.89uV
1ns       3.154uV    24.95uV    1.01uV
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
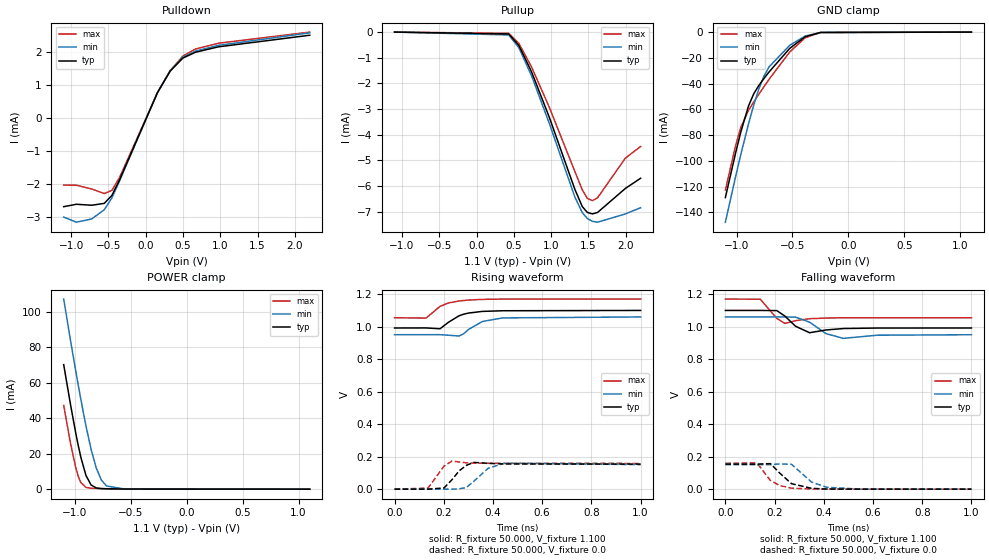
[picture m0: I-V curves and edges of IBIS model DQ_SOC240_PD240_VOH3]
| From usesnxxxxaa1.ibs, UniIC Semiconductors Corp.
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|   Model DQ_SOC240_PD240_VOH3
[Model] DQ_SOC240_PD240_VOH3
Model_type I/O
Polarity   Non-Inverting
Enable   Active-High
Vinl =  0.113V
Vinh =  0.253V
Vmeas =  0.183V
Rref =  50.000
Vref =  0.183V
C_comp   1.110pF   1.087pF   1.118pF
[Model Spec]
Vinh   0.253V   0.247V   0.265V
Vinl   0.113V   0.107V   0.125V
Vmeas   0.183V   NA   NA
Vref   0.183V   NA   NA
Rref   50.000   NA   NA
[Temperature Range]   25.000   0.125k   -40.000
[Voltage Range]   1.100V   1.060V   1.170V
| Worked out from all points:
|   slope of the pulldown table from 0 to 0.165 V, typ, clamps not added: 206 ohm
|   GND clamp passes 1 mA (typ) near -0.30 V on its own axis
|   POWER clamp passes 1 mA (typ) near -0.82 V on its own axis
|   rising waveform, R_fixture 50.000, V_fixture 1.100: 20-80 % time 75ps typ, 78.3ps min, 73.4ps max; typ from 0.992 V to 1.1 V
|   rising waveform, R_fixture 50.000, V_fixture 0.0: 20-80 % time 50.5ps typ, 61.7ps min, 40.4ps max; typ from 0 V to 0.154 V
|   falling waveform, R_fixture 50.000, V_fixture 1.100: 20-80 % time 43.1ps typ, 56.1ps min, 33.1ps max; typ from 1.1 V to 0.992 V
|   falling waveform, R_fixture 50.000, V_fixture 0.0: 20-80 % time 64.4ps typ, 69.9ps min, 60.1ps max; typ from 0.154 V to 0 V
[Pulldown]
|Voltage   I(typ)   I(min)   I(max)
-1.1V     -2.687mA   -3.002mA   -2.035mA
-930mV    -2.614mA   -3.157mA   -2.036mA
-726mV    -2.644mA   -3.06mA    -2.15mA
-556mV    -2.587mA   -2.78mA    -2.289mA
-454mV    -2.347mA   -2.422mA   -2.193mA
-352mV    -1.879mA   -1.911mA   -1.806mA
158mV     771.5uA    774.7uA    764.3uA
328mV     1.42mA     1.434mA    1.431mA
498mV     1.814mA    1.841mA    1.876mA
668mV     1.992mA    2.028mA    2.091mA
974mV     2.154mA    2.199mA    2.264mA
2.2V      2.506mA    2.578mA    2.601mA
[Pullup]
|Voltage   I(typ)   I(min)   I(max)
-1.1V     -58.82pA   10.24nA    0A
432mV     -74.32uA   -110.7uA   -50.31uA
568mV     -523.4uA   -612.1uA   -444.4uA
738mV     -1.552mA   -1.706mA   -1.362mA
976mV     -3.321mA   -3.56mA    -2.93mA
1.316V    -6.107mA   -6.406mA   -5.413mA
1.418V    -6.797mA   -7.033mA   -6.143mA
1.486V    -7.024mA   -7.26mA    -6.478mA
1.554V    -7.079mA   -7.37mA    -6.564mA
1.622V    -7.025mA   -7.403mA   -6.455mA
1.996V    -6.088mA   -7.082mA   -4.908mA
2.2V      -5.692mA   -6.84mA    -4.454mA
[GND_clamp]
|Voltage   I(typ)   I(min)   I(max)
-1.1V     -128.5mA   -147.6mA   -122.6mA
-1.008V   -93.62mA   -112mA     -87.95mA
-962mV    -77.6mA    -95.05mA   -73.96mA
-893mV    -57.36mA   -71.21mA   -60.7mA
-847mV    -48.01mA   -56.81mA   -54.36mA
-801mV    -41.47mA   -44.23mA   -48.33mA
-755mV    -36.02mA   -34.19mA   -42.41mA
-709mV    -30.9mA    -26.94mA   -36.63mA
-525mV    -12.67mA   -10.3mA    -15.49mA
-387mV    -3.615mA   -3.065mA   -4.419mA
-249mV    -281uA     -330.6uA   -301.3uA
1.1V      0A         0A         0A
[POWER_clamp]
|Voltage   I(typ)   I(min)   I(max)
-1.1V     70.27mA    107.3mA    47.25mA
-1.039V   47.68mA    83.93mA    25.86mA
-993mV    31.88mA    66.94mA    12.35mA
-970mV    24.65mA    58.72mA    7.262mA
-947mV    18.06mA    50.74mA    3.761mA
-901mV    7.73mA     35.71mA    987.1uA
-855mV    2.348mA    22.46mA    514uA
-809mV    697.3uA    11.94mA    396.5uA
-763mV    321uA      5.097mA    322.7uA
-717mV    213.8uA    1.813mA    258.1uA
-556mV    65.24uA    79.15uA    81.64uA
1.1V      0A         0A         0A
[Ramp]
| variable   typ   min   max
dV/dt_r   92.530m/50.555p   90.522m/61.781p   95.291m/40.356p
dV/dt_f   64.848m/43.265p   65.673m/56.947p   68.888m/33.233p
R_load = 50.000
[Rising Waveform]
R_fixture= 50.000
V_fixture= 1.100
V_fixture_min= 1.060
V_fixture_max= 1.170
|time   V(typ)   V(min)   V(max)
0s        991.9mV    950.6mV    1.055V
128ps     992.3mV    950.7mV    1.053V
185ps     987.3mV    951.1mV    1.125V
219ps     1.027V     947.4mV    1.146V
262ps     1.067V     942.5mV    1.158V
281ps     1.077V     956.6mV    1.161V
301ps     1.084V     983.3mV    1.164V
357ps     1.094V     1.032V     1.168V
439ps     1.098V     1.054V     1.17V
1ns       1.1V       1.06V      1.17V
[Rising Waveform]
R_fixture= 50.000
V_fixture= 0.0
V_fixture_min= 0.0
V_fixture_max= 0.0
|time   V(typ)   V(min)   V(max)
0s        3.61uV     29.2uV     671nV
136ps     -19.77uV   39.09uV    6.363mV
201ps     7.356mV    -76.4uV    141.9mV
234ps     59.13mV    -15.32uV   173.7mV
262ps     111.8mV    1.849mV    166.9mV
292ps     146.6mV    10.44mV    162.1mV
322ps     164.7mV    48.28mV    160.3mV
381ps     159.1mV    129.2mV    159.2mV
449ps     154.9mV    159.9mV    158.9mV
1ns       154.2mV    150.9mV    158.8mV
[Falling Waveform]
R_fixture= 50.000
V_fixture= 1.100
V_fixture_min= 1.060
V_fixture_max= 1.170
|time   V(typ)   V(min)   V(max)
0s        1.1V       1.06V      1.17V
142ps     1.1V       1.06V      1.169V
209ps     1.099V     1.06V      1.051V
242ps     1.065V     1.06V      1.02V
285ps     1.003V     1.059V     1.037V
342ps     962.8mV    1.028V     1.049V
409ps     979.7mV    957.3mV    1.053V
479ps     988.6mV    928.1mV    1.055V
617ps     991.7mV    947.5mV    1.055V
1ns       991.9mV    950.5mV    1.055V
[Falling Waveform]
R_fixture= 50.000
V_fixture= 0.0
V_fixture_min= 0.0
V_fixture_max= 0.0
|time   V(typ)   V(min)   V(max)
0s        154.2mV    150.9mV    158.8mV
123ps     153.7mV    150.8mV    161.4mV
137ps     154.6mV    150.6mV    144.3mV
183ps     157.2mV    150.5mV    53.58mV
221ps     98.9mV     155.3mV    21.98mV
269ps     33.55mV    152.8mV    5.993mV
350ps     5.135mV    44.09mV    1.06mV
410ps     713.2uV    11.93mV    307.3uV
548ps     44.66uV    -76.42uV   18.1uV
1ns       3.839uV    30.04uV    1.158uV
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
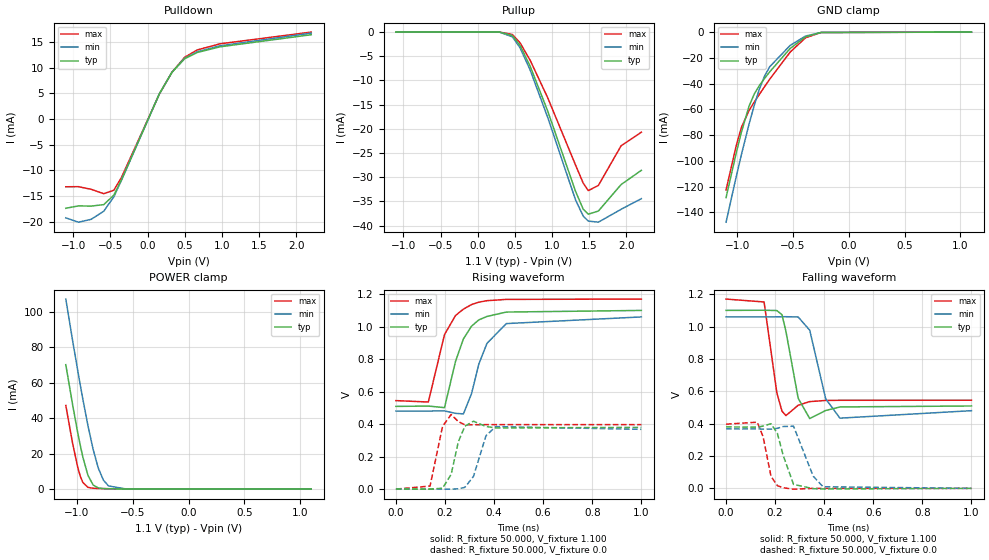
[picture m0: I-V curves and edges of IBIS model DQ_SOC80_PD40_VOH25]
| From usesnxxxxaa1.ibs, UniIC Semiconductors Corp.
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|   Model DQ_SOC80_PD40_VOH25
[Model] DQ_SOC80_PD40_VOH25
Model_type I/O
Polarity   Non-Inverting
Enable   Active-High
Vinl =  0.113V
Vinh =  0.253V
Vmeas =  0.183V
Rref =  50.000
Vref =  0.183V
C_comp   1.110pF   1.087pF   1.118pF
[Model Spec]
Vinh   0.253V   0.247V   0.265V
Vinl   0.113V   0.107V   0.125V
Vmeas   0.183V   NA   NA
Vref   0.183V   NA   NA
Rref   50.000   NA   NA
[Temperature Range]   25.000   0.125k   -40.000
[Voltage Range]   1.100V   1.060V   1.170V
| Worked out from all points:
|   slope of the pulldown table from 0 to 0.165 V, typ, clamps not added: 32.4 ohm
|   GND clamp passes 1 mA (typ) near -0.30 V on its own axis
|   POWER clamp passes 1 mA (typ) near -0.82 V on its own axis
|   rising waveform, R_fixture 50.000, V_fixture 1.100: 20-80 % time 76.9ps typ, 81.3ps min, 75.3ps max; typ from 0.509 V to 1.1 V
|   rising waveform, R_fixture 50.000, V_fixture 0.0: 20-80 % time 34.7ps typ, 42.5ps min, 26.7ps max; typ from 0 V to 0.38 V
|   falling waveform, R_fixture 50.000, V_fixture 1.100: 20-80 % time 39.8ps typ, 50.6ps min, 30ps max; typ from 1.1 V to 0.509 V
|   falling waveform, R_fixture 50.000, V_fixture 0.0: 20-80 % time 37.8ps typ, 47.8ps min, 30.8ps max; typ from 0.38 V to 0 V
[Pulldown]
|Voltage   I(typ)   I(min)   I(max)
-1.1V     -17.35mA   -19.2mA    -13.17mA
-930mV    -16.88mA   -20.05mA   -13.15mA
-760mV    -16.93mA   -19.5mA    -13.66mA
-590mV    -16.64mA   -17.92mA   -14.51mA
-454mV    -14.8mA    -15.12mA   -13.84mA
-352mV    -11.84mA   -11.92mA   -11.37mA
158mV     4.896mA    4.872mA    4.835mA
328mV     9.081mA    9.089mA    9.09mA
498mV     11.7mA     11.8mA     11.99mA
668mV     12.92mA    13.07mA    13.42mA
974mV     14.02mA    14.21mA    14.6mA
2.2V      16.37mA    16.68mA    16.88mA
[Pullup]
|Voltage   I(typ)   I(min)   I(max)
-1.1V     1nA        30.06nA    -1.059nA
296mV     -10.87uA   -31.47uA   -4.538uA
466mV     -722.3uA   -981.5uA   -506.7uA
568mV     -2.738mA   -3.216mA   -2.197mA
704mV     -7.017mA   -7.806mA   -5.798mA
942mV     -16.37mA   -17.69mA   -13.61mA
1.316V    -32.95mA   -34.73mA   -27.51mA
1.418V    -36.6mA    -38.02mA   -31.21mA
1.486V    -37.63mA   -39.06mA   -32.76mA
1.622V    -36.99mA   -39.29mA   -31.7mA
1.928V    -31.51mA   -36.62mA   -23.5mA
2.2V      -28.57mA   -34.43mA   -20.69mA
[GND_clamp]
|Voltage   I(typ)   I(min)   I(max)
-1.1V     -128.5mA   -147.6mA   -122.6mA
-1.008V   -93.62mA   -112mA     -87.95mA
-962mV    -77.6mA    -95.05mA   -73.96mA
-893mV    -57.36mA   -71.21mA   -60.7mA
-847mV    -48.01mA   -56.81mA   -54.36mA
-801mV    -41.47mA   -44.23mA   -48.33mA
-755mV    -36.02mA   -34.19mA   -42.41mA
-709mV    -30.9mA    -26.94mA   -36.63mA
-525mV    -12.67mA   -10.3mA    -15.49mA
-387mV    -3.615mA   -3.065mA   -4.419mA
-249mV    -281uA     -330.6uA   -301.3uA
1.1V      0A         0A         0A
[POWER_clamp]
|Voltage   I(typ)   I(min)   I(max)
-1.1V     70.27mA    107.3mA    47.25mA
-1.039V   47.68mA    83.93mA    25.86mA
-993mV    31.88mA    66.94mA    12.35mA
-970mV    24.65mA    58.72mA    7.262mA
-947mV    18.06mA    50.74mA    3.761mA
-901mV    7.73mA     35.71mA    987.1uA
-855mV    2.348mA    22.46mA    514uA
-809mV    697.3uA    11.94mA    396.5uA
-763mV    321uA      5.097mA    322.7uA
-717mV    213.8uA    1.813mA    258.1uA
-556mV    65.24uA    79.15uA    81.64uA
1.1V      0A         0A         0A
[Ramp]
| variable   typ   min   max
dV/dt_r   0.228/34.824p   0.221/43.224p   0.238/26.790p
dV/dt_f   0.354/40.173p   0.348/51.380p   0.375/30.299p
R_load = 50.000
[Rising Waveform]
R_fixture= 50.000
V_fixture= 1.100
V_fixture_min= 1.060
V_fixture_max= 1.170
|time   V(typ)   V(min)   V(max)
0s        509.2mV    480.2mV    544.8mV
132ps     511.1mV    480.6mV    536.1mV
198ps     501.6mV    481.3mV    951.8mV
243ps     787.3mV    466.3mV    1.069V
275ps     924.7mV    463mV      1.108V
308ps     1.003V     587.3mV    1.136V
338ps     1.042V     771mV      1.151V
371ps     1.063V     897.3mV    1.16V
450ps     1.09V      1.019V     1.168V
1ns       1.1V       1.06V      1.17V
[Rising Waveform]
R_fixture= 50.000
V_fixture= 0.0
V_fixture_min= 0.0
V_fixture_max= 0.0
|time   V(typ)   V(min)   V(max)
0s        1.709uV    13.91uV    320.5nV
139ps     -26.99uV   450.9nV    18.5mV
190ps     5.191mV    -27.39uV   386.2mV
225ps     90.39mV    -465.1uV   459.5mV
254ps     289.9mV    1.792mV    415.7mV
281ps     387.6mV    10.55mV    396mV
316ps     417.9mV    78.21mV    396.2mV
367ps     385.3mV    329.1mV    396.7mV
407ps     376.6mV    384.8mV    396.7mV
1ns       379.8mV    367.9mV    396.7mV
[Falling Waveform]
R_fixture= 50.000
V_fixture= 1.100
V_fixture_min= 1.060
V_fixture_max= 1.170
|time   V(typ)   V(min)   V(max)
0s        1.1V       1.06V      1.17V
155ps     1.101V     1.06V      1.152V
207ps     1.099V     1.06V      590.1mV
228ps     1.073V     1.061V     477mV
244ps     970.3mV    1.061V     450mV
294ps     556.4mV    1.059V     513.8mV
341ps     431.5mV    977.2mV    536.3mV
406ps     481.4mV    553.8mV    543.3mV
464ps     503.3mV    434mV      544.5mV
1ns       509.2mV    480.2mV    544.8mV
[Falling Waveform]
R_fixture= 50.000
V_fixture= 0.0
V_fixture_min= 0.0
V_fixture_max= 0.0
|time   V(typ)   V(min)   V(max)
0s        379.8mV    367.9mV    396.7mV
127ps     378.3mV    367.5mV    408.9mV
151ps     384.9mV    366.5mV    319.2mV
183ps     399.7mV    366.2mV    75.08mV
209ps     340.4mV    371.1mV    17.17mV
233ps     203.1mV    382.4mV    3.622mV
275ps     24.63mV    384.1mV    -4.874mV
355ps     -1.806mV   75.62mV    -125uV
395ps     -3.809mV   10.18mV    -15.18uV
1ns       3.368uV    15.56uV    -2.679uV
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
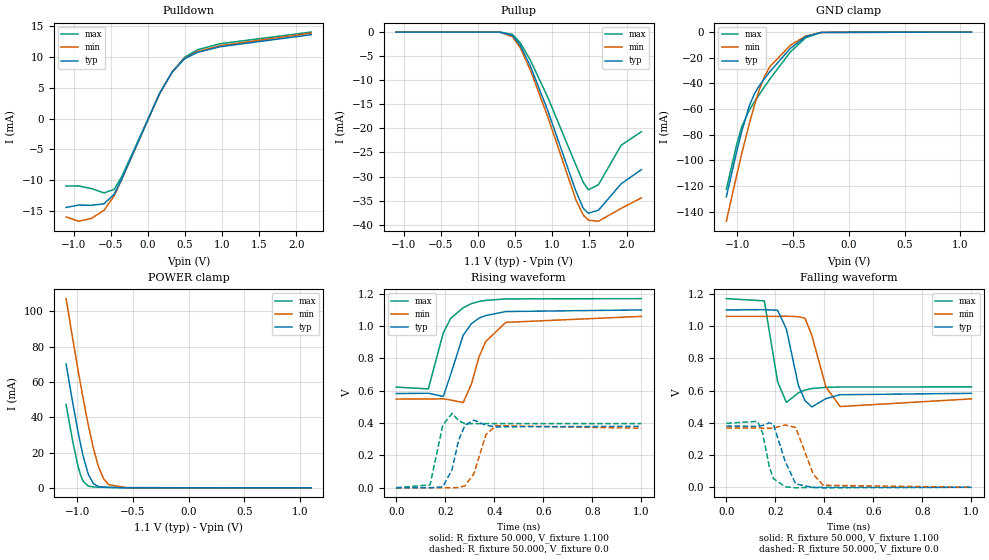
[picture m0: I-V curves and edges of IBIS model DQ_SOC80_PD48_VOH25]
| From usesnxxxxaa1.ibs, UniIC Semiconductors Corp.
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|   Model DQ_SOC80_PD48_VOH25
[Model] DQ_SOC80_PD48_VOH25
Model_type I/O
Polarity   Non-Inverting
Enable   Active-High
Vinl =  0.113V
Vinh =  0.253V
Vmeas =  0.183V
Rref =  50.000
Vref =  0.183V
C_comp   1.110pF   1.087pF   1.118pF
[Model Spec]
Vinh   0.253V   0.247V   0.265V
Vinl   0.113V   0.107V   0.125V
Vmeas   0.183V   NA   NA
Vref   0.183V   NA   NA
Rref   50.000   NA   NA
[Temperature Range]   25.000   0.125k   -40.000
[Voltage Range]   1.100V   1.060V   1.170V
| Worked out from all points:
|   slope of the pulldown table from 0 to 0.165 V, typ, clamps not added: 38.9 ohm
|   GND clamp passes 1 mA (typ) near -0.30 V on its own axis
|   POWER clamp passes 1 mA (typ) near -0.82 V on its own axis
|   rising waveform, R_fixture 50.000, V_fixture 1.100: 20-80 % time 76.4ps typ, 80.3ps min, 75.1ps max; typ from 0.583 V to 1.1 V
|   rising waveform, R_fixture 50.000, V_fixture 0.0: 20-80 % time 35.2ps typ, 43.8ps min, 27ps max; typ from 0 V to 0.38 V
|   falling waveform, R_fixture 50.000, V_fixture 1.100: 20-80 % time 40.9ps typ, 53ps min, 30.8ps max; typ from 1.1 V to 0.583 V
|   falling waveform, R_fixture 50.000, V_fixture 0.0: 20-80 % time 40.1ps typ, 49.8ps min, 33.5ps max; typ from 0.38 V to 0 V
[Pulldown]
|Voltage   I(typ)   I(min)   I(max)
-1.1V     -14.46mA   -16mA      -10.98mA
-930mV    -14.07mA   -16.71mA   -10.96mA
-760mV    -14.11mA   -16.25mA   -11.39mA
-590mV    -13.87mA   -14.94mA   -12.09mA
-454mV    -12.33mA   -12.6mA    -11.53mA
-352mV    -9.864mA   -9.937mA   -9.473mA
158mV     4.08mA     4.06mA     4.029mA
328mV     7.567mA    7.574mA    7.575mA
498mV     9.752mA    9.831mA    9.989mA
668mV     10.77mA    10.89mA    11.19mA
974mV     11.68mA    11.84mA    12.17mA
2.2V      13.64mA    13.9mA     14.07mA
[Pullup]
|Voltage   I(typ)   I(min)   I(max)
-1.1V     1nA        30.06nA    -1.059nA
296mV     -10.87uA   -31.47uA   -4.538uA
466mV     -722.3uA   -981.5uA   -506.7uA
568mV     -2.738mA   -3.216mA   -2.197mA
704mV     -7.017mA   -7.806mA   -5.798mA
942mV     -16.37mA   -17.69mA   -13.61mA
1.316V    -32.95mA   -34.73mA   -27.51mA
1.418V    -36.6mA    -38.02mA   -31.21mA
1.486V    -37.63mA   -39.06mA   -32.76mA
1.622V    -36.99mA   -39.29mA   -31.7mA
1.928V    -31.51mA   -36.62mA   -23.5mA
2.2V      -28.57mA   -34.43mA   -20.69mA
[GND_clamp]
|Voltage   I(typ)   I(min)   I(max)
-1.1V     -128.5mA   -147.6mA   -122.6mA
-1.008V   -93.62mA   -112mA     -87.95mA
-962mV    -77.6mA    -95.05mA   -73.96mA
-893mV    -57.36mA   -71.21mA   -60.7mA
-847mV    -48.01mA   -56.81mA   -54.36mA
-801mV    -41.47mA   -44.23mA   -48.33mA
-755mV    -36.02mA   -34.19mA   -42.41mA
-709mV    -30.9mA    -26.94mA   -36.63mA
-525mV    -12.67mA   -10.3mA    -15.49mA
-387mV    -3.615mA   -3.065mA   -4.419mA
-249mV    -281uA     -330.6uA   -301.3uA
1.1V      0A         0A         0A
[POWER_clamp]
|Voltage   I(typ)   I(min)   I(max)
-1.1V     70.27mA    107.3mA    47.25mA
-1.039V   47.68mA    83.93mA    25.86mA
-993mV    31.88mA    66.94mA    12.35mA
-970mV    24.65mA    58.72mA    7.262mA
-947mV    18.06mA    50.74mA    3.761mA
-901mV    7.73mA     35.71mA    987.1uA
-855mV    2.348mA    22.46mA    514uA
-809mV    697.3uA    11.94mA    396.5uA
-763mV    321uA      5.097mA    322.7uA
-717mV    213.8uA    1.813mA    258.1uA
-556mV    65.24uA    79.15uA    81.64uA
1.1V      0A         0A         0A
[Ramp]
| variable   typ   min   max
dV/dt_r   0.228/35.313p   0.221/43.713p   0.238/27.102p
dV/dt_f   0.310/41.345p   0.307/53.546p   0.329/31.124p
R_load = 50.000
[Rising Waveform]
R_fixture= 50.000
V_fixture= 1.100
V_fixture_min= 1.060
V_fixture_max= 1.170
|time   V(typ)   V(min)   V(max)
0s        582.6mV    548.3mV    622.5mV
131ps     584.5mV    548.7mV    611.5mV
192ps     564.8mV    550mV      957.8mV
222ps     699.7mV    542.7mV    1.047V
273ps     942.8mV    526.4mV    1.113V
307ps     1.015V     641.4mV    1.139V
337ps     1.049V     806.4mV    1.152V
365ps     1.065V     904.2mV    1.159V
447ps     1.09V      1.023V     1.168V
1ns       1.1V       1.06V      1.17V
[Rising Waveform]
R_fixture= 50.000
V_fixture= 0.0
V_fixture_min= 0.0
V_fixture_max= 0.0
|time   V(typ)   V(min)   V(max)
0s        1.908uV    15.52uV    357.4nV
138ps     -38.95uV   17.5uV     17.51mV
190ps     5.463mV    -32.78uV   386.7mV
228ps     113.5mV    -682.3uV   460.7mV
254ps     291.6mV    1.55mV     415.7mV
281ps     387.8mV    11.63mV    396mV
317ps     418.3mV    87.54mV    396.2mV
366ps     386.5mV    327.3mV    396.7mV
406ps     376.6mV    384.2mV    396.7mV
1ns       379.8mV    367.9mV    396.7mV
[Falling Waveform]
R_fixture= 50.000
V_fixture= 1.100
V_fixture_min= 1.060
V_fixture_max= 1.170
|time   V(typ)   V(min)   V(max)
0s        1.1V       1.06V      1.17V
155ps     1.101V     1.06V      1.156V
209ps     1.098V     1.06V      655.4mV
245ps     981.1mV    1.061V     526.5mV
294ps     631.1mV    1.058V     585.7mV
321ps     537.1mV    1.048V     603.1mV
349ps     498.1mV    941.1mV    612.4mV
406ps     549.7mV    622.5mV    619.8mV
464ps     574mV      500.7mV    621.8mV
1ns       582.6mV    548.3mV    622.4mV
[Falling Waveform]
R_fixture= 50.000
V_fixture= 0.0
V_fixture_min= 0.0
V_fixture_max= 0.0
|time   V(typ)   V(min)   V(max)
0s        379.8mV    367.9mV    396.7mV
127ps     378.3mV    367.5mV    409mV
148ps     383.2mV    366.6mV    336.3mV
175ps     399.6mV    366mV      129.6mV
192ps     390.5mV    367.1mV    54mV
240ps     160.8mV    386.6mV    3.134mV
283ps     21.05mV    371mV      -2.982mV
355ps     -1.173mV   79.69mV    -140.9uV
395ps     -3.337mV   12.85mV    -21.91uV
1ns       3.832uV    17.88uV    -2.754uV
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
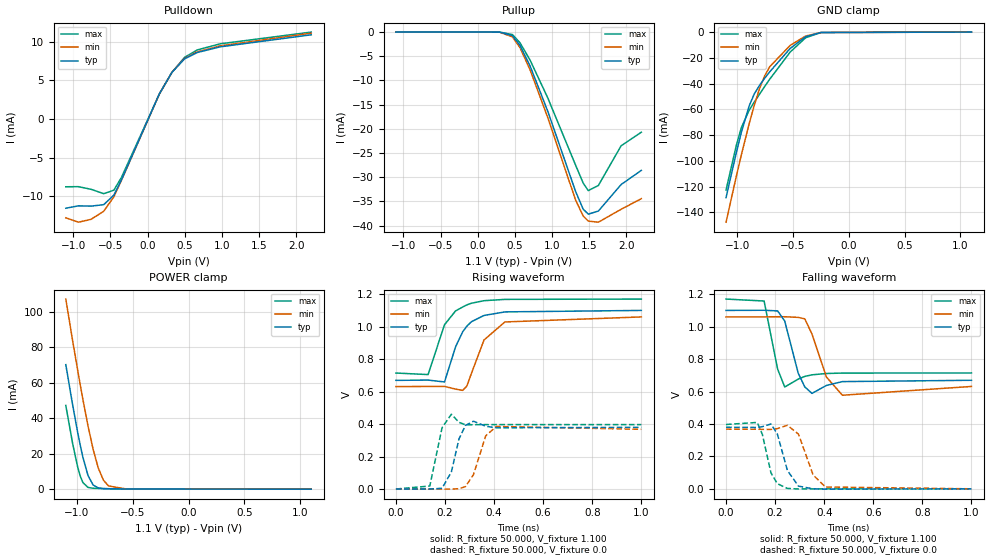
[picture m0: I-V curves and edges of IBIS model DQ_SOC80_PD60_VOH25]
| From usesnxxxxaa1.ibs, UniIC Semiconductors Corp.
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|   Model DQ_SOC80_PD60_VOH25
[Model] DQ_SOC80_PD60_VOH25
Model_type I/O
Polarity   Non-Inverting
Enable   Active-High
Vinl =  0.113V
Vinh =  0.253V
Vmeas =  0.183V
Rref =  50.000
Vref =  0.183V
C_comp   1.110pF   1.087pF   1.118pF
[Model Spec]
Vinh   0.253V   0.247V   0.265V
Vinl   0.113V   0.107V   0.125V
Vmeas   0.183V   NA   NA
Vref   0.183V   NA   NA
Rref   50.000   NA   NA
[Temperature Range]   25.000   0.125k   -40.000
[Voltage Range]   1.100V   1.060V   1.170V
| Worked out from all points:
|   slope of the pulldown table from 0 to 0.165 V, typ, clamps not added: 48.6 ohm
|   GND clamp passes 1 mA (typ) near -0.30 V on its own axis
|   POWER clamp passes 1 mA (typ) near -0.82 V on its own axis
|   rising waveform, R_fixture 50.000, V_fixture 1.100: 20-80 % time 75.6ps typ, 79ps min, 74.7ps max; typ from 0.669 V to 1.1 V
|   rising waveform, R_fixture 50.000, V_fixture 0.0: 20-80 % time 35.8ps typ, 44.4ps min, 27.4ps max; typ from 0 V to 0.38 V
|   falling waveform, R_fixture 50.000, V_fixture 1.100: 20-80 % time 41.7ps typ, 54.7ps min, 31.3ps max; typ from 1.1 V to 0.669 V
|   falling waveform, R_fixture 50.000, V_fixture 0.0: 20-80 % time 43.1ps typ, 52.1ps min, 37ps max; typ from 0.38 V to 0 V
[Pulldown]
|Voltage   I(typ)   I(min)   I(max)
-1.1V     -11.56mA   -12.8mA    -8.78mA
-930mV    -11.25mA   -13.37mA   -8.769mA
-760mV    -11.29mA   -13mA      -9.11mA
-590mV    -11.1mA    -11.95mA   -9.675mA
-454mV    -9.865mA   -10.08mA   -9.225mA
-352mV    -7.891mA   -7.949mA   -7.578mA
158mV     3.264mA    3.248mA    3.223mA
328mV     6.054mA    6.059mA    6.06mA
498mV     7.801mA    7.865mA    7.991mA
668mV     8.612mA    8.711mA    8.95mA
974mV     9.345mA    9.47mA     9.737mA
2.2V      10.91mA    11.12mA    11.26mA
[Pullup]
|Voltage   I(typ)   I(min)   I(max)
-1.1V     1nA        30.06nA    -1.059nA
296mV     -10.87uA   -31.47uA   -4.538uA
466mV     -722.3uA   -981.5uA   -506.7uA
568mV     -2.738mA   -3.216mA   -2.197mA
704mV     -7.017mA   -7.806mA   -5.798mA
942mV     -16.37mA   -17.69mA   -13.61mA
1.316V    -32.95mA   -34.73mA   -27.51mA
1.418V    -36.6mA    -38.02mA   -31.21mA
1.486V    -37.63mA   -39.06mA   -32.76mA
1.622V    -36.99mA   -39.29mA   -31.7mA
1.928V    -31.51mA   -36.62mA   -23.5mA
2.2V      -28.57mA   -34.43mA   -20.69mA
[GND_clamp]
|Voltage   I(typ)   I(min)   I(max)
-1.1V     -128.5mA   -147.6mA   -122.6mA
-1.008V   -93.62mA   -112mA     -87.95mA
-962mV    -77.6mA    -95.05mA   -73.96mA
-893mV    -57.36mA   -71.21mA   -60.7mA
-847mV    -48.01mA   -56.81mA   -54.36mA
-801mV    -41.47mA   -44.23mA   -48.33mA
-755mV    -36.02mA   -34.19mA   -42.41mA
-709mV    -30.9mA    -26.94mA   -36.63mA
-525mV    -12.67mA   -10.3mA    -15.49mA
-387mV    -3.615mA   -3.065mA   -4.419mA
-249mV    -281uA     -330.6uA   -301.3uA
1.1V      0A         0A         0A
[POWER_clamp]
|Voltage   I(typ)   I(min)   I(max)
-1.1V     70.27mA    107.3mA    47.25mA
-1.039V   47.68mA    83.93mA    25.86mA
-993mV    31.88mA    66.94mA    12.35mA
-970mV    24.65mA    58.72mA    7.262mA
-947mV    18.06mA    50.74mA    3.761mA
-901mV    7.73mA     35.71mA    987.1uA
-855mV    2.348mA    22.46mA    514uA
-809mV    697.3uA    11.94mA    396.5uA
-763mV    321uA      5.097mA    322.7uA
-717mV    213.8uA    1.813mA    258.1uA
-556mV    65.24uA    79.15uA    81.64uA
1.1V      0A         0A         0A
[Ramp]
| variable   typ   min   max
dV/dt_r   0.228/35.753p   0.221/44.420p   0.238/27.487p
dV/dt_f   0.258/42.116p   0.257/55.008p   0.273/31.733p
R_load = 50.000
[Rising Waveform]
R_fixture= 50.000
V_fixture= 1.100
V_fixture_min= 1.060
V_fixture_max= 1.170
|time   V(typ)   V(min)   V(max)
0s        669.2mV    631.2mV    714.4mV
131ps     671mV      631.6mV    704.9mV
198ps     659.4mV    632.2mV    1.012V
243ps     875.6mV    615.3mV    1.097V
272ps     968.4mV    607.6mV    1.121V
289ps     1.003V     634.1mV    1.134V
307ps     1.03V      709.5mV    1.144V
359ps     1.069V     918.2mV    1.16V
444ps     1.091V     1.029V     1.168V
1ns       1.1V       1.06V      1.17V
[Rising Waveform]
R_fixture= 50.000
V_fixture= 0.0
V_fixture_min= 0.0
V_fixture_max= 0.0
|time   V(typ)   V(min)   V(max)
0s        2.16uV     17.56uV    404.1nV
138ps     -73.3uV    39.83uV    18.48mV
188ps     4.74mV     -20.77uV   377.8mV
226ps     105.4mV    -892.7uV   460.7mV
257ps     308.4mV    2.165mV    410.7mV
283ps     391.3mV    14.49mV    395.7mV
316ps     417.8mV    88.64mV    396.2mV
366ps     386.6mV    328.1mV    396.7mV
409ps     376.8mV    385.3mV    396.7mV
1ns       379.8mV    367.9mV    396.7mV
[Falling Waveform]
R_fixture= 50.000
V_fixture= 1.100
V_fixture_min= 1.060
V_fixture_max= 1.170
|time   V(typ)   V(min)   V(max)
0s        1.1V       1.06V      1.17V
155ps     1.101V     1.06V      1.158V
210ps     1.097V     1.061V     739.1mV
239ps     1.035V     1.061V     627.8mV
294ps     713mV      1.057V     676.4mV
321ps     628.1mV    1.048V     693.2mV
350ps     588.4mV    954.6mV    702.9mV
409ps     637.4mV    689.4mV    711.1mV
474ps     661.1mV    577mV      713.6mV
1ns       669.2mV    631.2mV    714.4mV
[Falling Waveform]
R_fixture= 50.000
V_fixture= 0.0
V_fixture_min= 0.0
V_fixture_max= 0.0
|time   V(typ)   V(min)   V(max)
0s        379.8mV    367.9mV    396.7mV
127ps     378.3mV    367.5mV    409.2mV
148ps     383.3mV    366.6mV    335.2mV
183ps     399.9mV    366.2mV    98.33mV
209ps     337.8mV    371.2mV    31.62mV
250ps     113.2mV    391.9mV    2.461mV
295ps     16.7mV     337.3mV    -1.069mV
355ps     -119.8uV   84.76mV    -104.7uV
405ps     -2.147mV   11.22mV    -10.32uV
1ns       4.704uV    20.22uV    -2.702uV
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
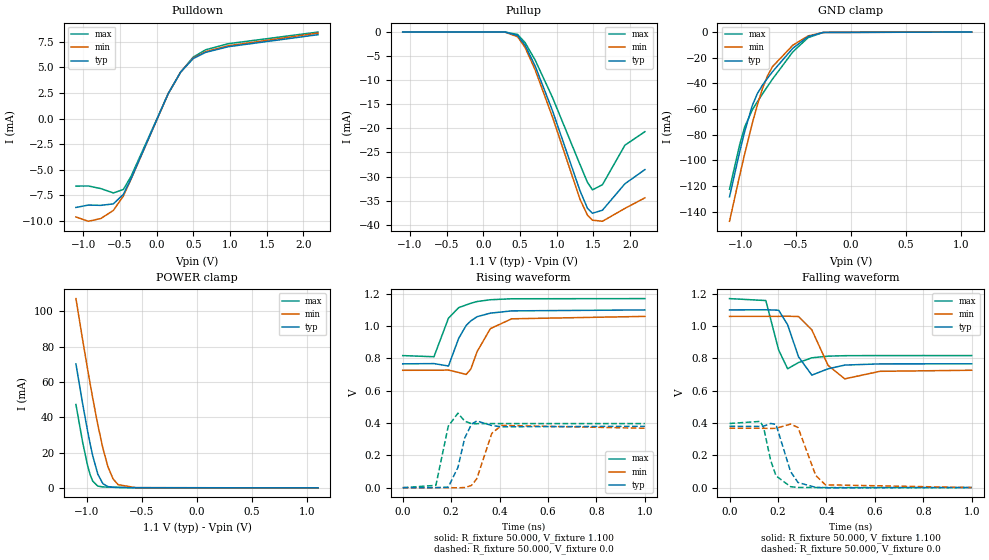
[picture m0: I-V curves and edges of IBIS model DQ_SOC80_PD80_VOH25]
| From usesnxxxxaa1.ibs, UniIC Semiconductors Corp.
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|   Model DQ_SOC80_PD80_VOH25
[Model] DQ_SOC80_PD80_VOH25
Model_type I/O
Polarity   Non-Inverting
Enable   Active-High
Vinl =  0.113V
Vinh =  0.253V
Vmeas =  0.183V
Rref =  50.000
Vref =  0.183V
C_comp   1.110pF   1.087pF   1.118pF
[Model Spec]
Vinh   0.253V   0.247V   0.265V
Vinl   0.113V   0.107V   0.125V
Vmeas   0.183V   NA   NA
Vref   0.183V   NA   NA
Rref   50.000   NA   NA
[Temperature Range]   25.000   0.125k   -40.000
[Voltage Range]   1.100V   1.060V   1.170V
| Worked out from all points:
|   slope of the pulldown table from 0 to 0.165 V, typ, clamps not added: 64.8 ohm
|   GND clamp passes 1 mA (typ) near -0.30 V on its own axis
|   POWER clamp passes 1 mA (typ) near -0.82 V on its own axis
|   rising waveform, R_fixture 50.000, V_fixture 1.100: 20-80 % time 71.4ps typ, 73ps min, 71.4ps max; typ from 0.766 V to 1.1 V
|   rising waveform, R_fixture 50.000, V_fixture 0.0: 20-80 % time 35.8ps typ, 44.9ps min, 27.2ps max; typ from 0 V to 0.38 V
|   falling waveform, R_fixture 50.000, V_fixture 1.100: 20-80 % time 44ps typ, 56.5ps min, 32.9ps max; typ from 1.1 V to 0.766 V
|   falling waveform, R_fixture 50.000, V_fixture 0.0: 20-80 % time 43.5ps typ, 50.5ps min, 39.9ps max; typ from 0.38 V to 0 V
[Pulldown]
|Voltage   I(typ)   I(min)   I(max)
-1.1V     -8.673mA   -9.601mA   -6.585mA
-930mV    -8.439mA   -10.02mA   -6.577mA
-760mV    -8.467mA   -9.748mA   -6.832mA
-590mV    -8.322mA   -8.962mA   -7.256mA
-454mV    -7.399mA   -7.561mA   -6.919mA
-352mV    -5.919mA   -5.962mA   -5.684mA
158mV     2.448mA    2.436mA    2.417mA
328mV     4.54mA     4.545mA    4.545mA
498mV     5.851mA    5.899mA    5.993mA
668mV     6.459mA    6.534mA    6.712mA
974mV     7.009mA    7.103mA    7.302mA
2.2V      8.186mA    8.338mA    8.442mA
[Pullup]
|Voltage   I(typ)   I(min)   I(max)
-1.1V     1nA        30.06nA    -1.059nA
296mV     -10.87uA   -31.47uA   -4.538uA
466mV     -722.3uA   -981.5uA   -506.7uA
568mV     -2.738mA   -3.216mA   -2.197mA
704mV     -7.017mA   -7.806mA   -5.798mA
942mV     -16.37mA   -17.69mA   -13.61mA
1.316V    -32.95mA   -34.73mA   -27.51mA
1.418V    -36.6mA    -38.02mA   -31.21mA
1.486V    -37.63mA   -39.06mA   -32.76mA
1.622V    -36.99mA   -39.29mA   -31.7mA
1.928V    -31.51mA   -36.62mA   -23.5mA
2.2V      -28.57mA   -34.43mA   -20.69mA
[GND_clamp]
|Voltage   I(typ)   I(min)   I(max)
-1.1V     -128.5mA   -147.6mA   -122.6mA
-1.008V   -93.62mA   -112mA     -87.95mA
-962mV    -77.6mA    -95.05mA   -73.96mA
-893mV    -57.36mA   -71.21mA   -60.7mA
-847mV    -48.01mA   -56.81mA   -54.36mA
-801mV    -41.47mA   -44.23mA   -48.33mA
-755mV    -36.02mA   -34.19mA   -42.41mA
-709mV    -30.9mA    -26.94mA   -36.63mA
-525mV    -12.67mA   -10.3mA    -15.49mA
-387mV    -3.615mA   -3.065mA   -4.419mA
-249mV    -281uA     -330.6uA   -301.3uA
1.1V      0A         0A         0A
[POWER_clamp]
|Voltage   I(typ)   I(min)   I(max)
-1.1V     70.27mA    107.3mA    47.25mA
-1.039V   47.68mA    83.93mA    25.86mA
-993mV    31.88mA    66.94mA    12.35mA
-970mV    24.65mA    58.72mA    7.262mA
-947mV    18.06mA    50.74mA    3.761mA
-901mV    7.73mA     35.71mA    987.1uA
-855mV    2.348mA    22.46mA    514uA
-809mV    697.3uA    11.94mA    396.5uA
-763mV    321uA      5.097mA    322.7uA
-717mV    213.8uA    1.813mA    258.1uA
-556mV    65.24uA    79.15uA    81.64uA
1.1V      0A         0A         0A
[Ramp]
| variable   typ   min   max
dV/dt_r   0.228/36.058p   0.221/44.490p   0.238/27.386p
dV/dt_f   0.200/44.117p   0.200/57.046p   0.212/33.036p
R_load = 50.000
[Rising Waveform]
R_fixture= 50.000
V_fixture= 1.100
V_fixture_min= 1.060
V_fixture_max= 1.170
|time   V(typ)   V(min)   V(max)
0s        766.3mV    726.4mV    817.4mV
129ps     767.8mV    726.8mV    810.3mV
189ps     752.9mV    727.7mV    1.049V
231ps     923.7mV    712.9mV    1.114V
262ps     1.004V     700.6mV    1.131V
281ps     1.032V     733.1mV    1.141V
307ps     1.058V     841.2mV    1.152V
362ps     1.08V      984.3mV    1.163V
450ps     1.094V     1.045V     1.169V
1ns       1.1V       1.06V      1.17V
[Rising Waveform]
R_fixture= 50.000
V_fixture= 0.0
V_fixture_min= 0.0
V_fixture_max= 0.0
|time   V(typ)   V(min)   V(max)
0s        2.487uV    20.21uV    464.7nV
137ps     30.76uV    49.6uV     14.48mV
188ps     3.353mV    60.75uV    379.8mV
228ps     125.4mV    -968uV     461mV
256ps     306.8mV    1.029mV    411.9mV
284ps     393.1mV    13.78mV    395.8mV
306ps     412.9mV    55.63mV    396mV
368ps     384.7mV    336.6mV    396.7mV
408ps     376.8mV    385mV      396.7mV
1ns       379.8mV    367.9mV    396.7mV
[Falling Waveform]
R_fixture= 50.000
V_fixture= 1.100
V_fixture_min= 1.060
V_fixture_max= 1.170
|time   V(typ)   V(min)   V(max)
0s        1.1V       1.06V      1.17V
150ps     1.101V     1.06V      1.158V
203ps     1.098V     1.06V      851.4mV
240ps     1.008V     1.061V     735.6mV
285ps     809.8mV    1.059V     774.1mV
340ps     696.3mV    976.4mV    803.3mV
407ps     735.3mV    756.7mV    813.7mV
476ps     758.4mV    673.1mV    816.5mV
621ps     765.8mV    719.8mV    817.4mV
1ns       766.3mV    726.4mV    817.4mV
[Falling Waveform]
R_fixture= 50.000
V_fixture= 0.0
V_fixture_min= 0.0
V_fixture_max= 0.0
|time   V(typ)   V(min)   V(max)
0s        379.8mV    367.9mV    396.7mV
127ps     378.3mV    367.5mV    409.8mV
141ps     380.6mV    366.9mV    370.9mV
170ps     396.9mV    366mV      167.7mV
192ps     391.1mV    367.1mV    72.76mV
252ps     99.3mV     393.1mV    5.568mV
283ps     31.14mV    372mV      375.3uV
356ps     1.173mV    75.28mV    67.34uV
396ps     -1.684mV   16.98mV    26.95uV
1ns       5.324uV    23.26uV    -3.515uV
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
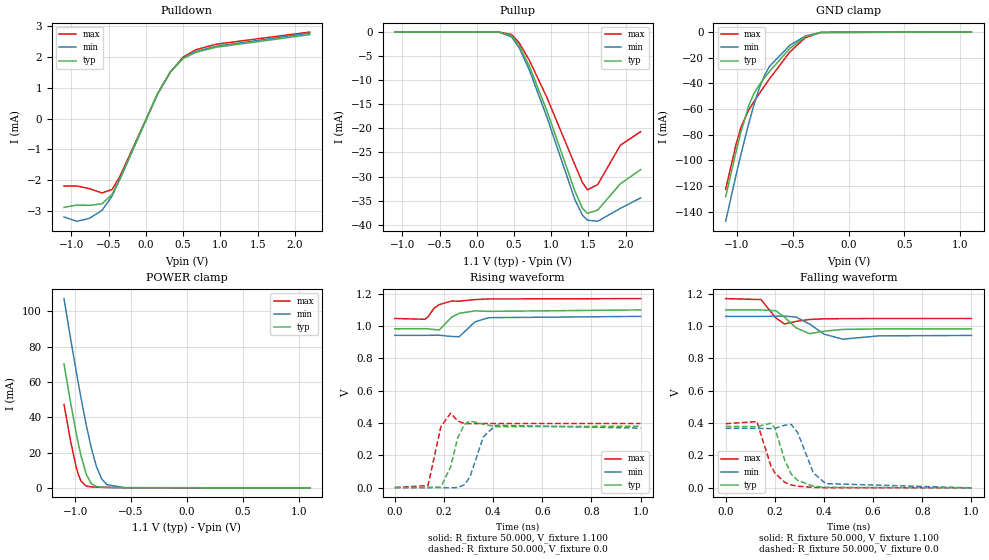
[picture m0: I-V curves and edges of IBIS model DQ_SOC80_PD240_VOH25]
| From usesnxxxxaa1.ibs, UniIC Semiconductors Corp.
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|   Model DQ_SOC80_PD240_VOH25
[Model] DQ_SOC80_PD240_VOH25
Model_type I/O
Polarity   Non-Inverting
Enable   Active-High
Vinl =  0.113V
Vinh =  0.253V
Vmeas =  0.183V
Rref =  50.000
Vref =  0.183V
C_comp   1.110pF   1.087pF   1.118pF
[Model Spec]
Vinh   0.253V   0.247V   0.265V
Vinl   0.113V   0.107V   0.125V
Vmeas   0.183V   NA   NA
Vref   0.183V   NA   NA
Rref   50.000   NA   NA
[Temperature Range]   25.000   0.125k   -40.000
[Voltage Range]   1.100V   1.060V   1.170V
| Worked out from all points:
|   slope of the pulldown table from 0 to 0.165 V, typ, clamps not added: 194 ohm
|   GND clamp passes 1 mA (typ) near -0.30 V on its own axis
|   POWER clamp passes 1 mA (typ) near -0.82 V on its own axis
|   rising waveform, R_fixture 50.000, V_fixture 1.100: 20-80 % time 54.1ps typ, 51.7ps min, 60.8ps max; typ from 0.983 V to 1.1 V
|   rising waveform, R_fixture 50.000, V_fixture 0.0: 20-80 % time 37.1ps typ, 46.9ps min, 28.1ps max; typ from 0 V to 0.38 V
|   falling waveform, R_fixture 50.000, V_fixture 1.100: 20-80 % time 45.6ps typ, 58.8ps min, 34.2ps max; typ from 1.1 V to 0.983 V
|   falling waveform, R_fixture 50.000, V_fixture 0.0: 20-80 % time 56.8ps typ, 60.2ps min, 56.1ps max; typ from 0.38 V to 0 V
[Pulldown]
|Voltage   I(typ)   I(min)   I(max)
-1.1V     -2.891mA   -3.2mA     -2.195mA
-930mV    -2.813mA   -3.341mA   -2.192mA
-760mV    -2.822mA   -3.249mA   -2.278mA
-590mV    -2.774mA   -2.987mA   -2.419mA
-454mV    -2.466mA   -2.52mA    -2.306mA
-352mV    -1.973mA   -1.987mA   -1.895mA
158mV     816.1uA    812uA      805.8uA
328mV     1.513mA    1.515mA    1.515mA
498mV     1.95mA     1.966mA    1.998mA
668mV     2.153mA    2.178mA    2.237mA
940mV     2.32mA     2.351mA    2.418mA
2.2V      2.729mA    2.779mA    2.814mA
[Pullup]
|Voltage   I(typ)   I(min)   I(max)
-1.1V     1nA        30.06nA    -1.059nA
296mV     -10.87uA   -31.47uA   -4.538uA
466mV     -722.3uA   -981.5uA   -506.7uA
568mV     -2.738mA   -3.216mA   -2.197mA
704mV     -7.017mA   -7.806mA   -5.798mA
942mV     -16.37mA   -17.69mA   -13.61mA
1.316V    -32.95mA   -34.73mA   -27.51mA
1.418V    -36.6mA    -38.02mA   -31.21mA
1.486V    -37.63mA   -39.06mA   -32.76mA
1.622V    -36.99mA   -39.29mA   -31.7mA
1.928V    -31.51mA   -36.62mA   -23.5mA
2.2V      -28.57mA   -34.43mA   -20.69mA
[GND_clamp]
|Voltage   I(typ)   I(min)   I(max)
-1.1V     -128.5mA   -147.6mA   -122.6mA
-1.008V   -93.62mA   -112mA     -87.95mA
-962mV    -77.6mA    -95.05mA   -73.96mA
-893mV    -57.36mA   -71.21mA   -60.7mA
-847mV    -48.01mA   -56.81mA   -54.36mA
-801mV    -41.47mA   -44.23mA   -48.33mA
-755mV    -36.02mA   -34.19mA   -42.41mA
-709mV    -30.9mA    -26.94mA   -36.63mA
-525mV    -12.67mA   -10.3mA    -15.49mA
-387mV    -3.615mA   -3.065mA   -4.419mA
-249mV    -281uA     -330.6uA   -301.3uA
1.1V      0A         0A         0A
[POWER_clamp]
|Voltage   I(typ)   I(min)   I(max)
-1.1V     70.27mA    107.3mA    47.25mA
-1.039V   47.68mA    83.93mA    25.86mA
-993mV    31.88mA    66.94mA    12.35mA
-970mV    24.65mA    58.72mA    7.262mA
-947mV    18.06mA    50.74mA    3.761mA
-901mV    7.73mA     35.71mA    987.1uA
-855mV    2.348mA    22.46mA    514uA
-809mV    697.3uA    11.94mA    396.5uA
-763mV    321uA      5.097mA    322.7uA
-717mV    213.8uA    1.813mA    258.1uA
-556mV    65.24uA    79.15uA    81.64uA
1.1V      0A         0A         0A
[Ramp]
| variable   typ   min   max
dV/dt_r   0.228/37.619p   0.221/46.807p   0.238/28.146p
dV/dt_f   70.211m/45.739p   70.570m/59.118p   73.998m/34.439p
R_load = 50.000
[Rising Waveform]
R_fixture= 50.000
V_fixture= 1.100
V_fixture_min= 1.060
V_fixture_max= 1.170
|time   V(typ)   V(min)   V(max)
0s        983mV      942.4mV    1.047V
122ps     983.7mV    942.5mV    1.042V
134ps     983.2mV    942.7mV    1.055V
160ps     978.3mV    943.1mV    1.111V
181ps     975.8mV    943.1mV    1.133V
231ps     1.055V     935.5mV    1.155V
262ps     1.079V     933.7mV    1.154V
326ps     1.094V     1.026V     1.164V
382ps     1.091V     1.052V     1.168V
1ns       1.1V       1.06V      1.17V
[Rising Waveform]
R_fixture= 50.000
V_fixture= 0.0
V_fixture_min= 0.0
V_fixture_max= 0.0
|time   V(typ)   V(min)   V(max)
0s        3.571uV    28.95uV    664nV
135ps     -3.344uV   100.3uV    12.48mV
187ps     3.544mV    35.31uV    375.6mV
227ps     127.7mV    -1.619mV   461mV
255ps     304.2mV    220.7uV    413.5mV
283ps     391.6mV    17.17mV    395.8mV
306ps     412.8mV    66.72mV    395.9mV
360ps     392.6mV    314.2mV    396.7mV
410ps     376.9mV    385.5mV    396.7mV
1ns       379.8mV    367.9mV    396.7mV
[Falling Waveform]
R_fixture= 50.000
V_fixture= 1.100
V_fixture_min= 1.060
V_fixture_max= 1.170
|time   V(typ)   V(min)   V(max)
0s        1.1V       1.06V      1.17V
144ps     1.1V       1.06V      1.164V
204ps     1.095V     1.061V     1.051V
239ps     1.056V     1.062V     1.013V
286ps     989.9mV    1.056V     1.029V
341ps     953.2mV    1.013V     1.041V
401ps     968.6mV    949.8mV    1.045V
476ps     979.4mV    919.2mV    1.046V
623ps     982.8mV    939.6mV    1.047V
1ns       983mV      942.4mV    1.047V
[Falling Waveform]
R_fixture= 50.000
V_fixture= 0.0
V_fixture_min= 0.0
V_fixture_max= 0.0
|time   V(typ)   V(min)   V(max)
0s        379.8mV    367.9mV    396.7mV
127ps     378.3mV    367.5mV    409.7mV
184ps     399.4mV    366.2mV    136.2mV
201ps     366.4mV    368.9mV    89.83mV
240ps     172.3mV    387mV      34.66mV
267ps     84.94mV    391.7mV    17.84mV
293ps     45.88mV    341.4mV    10.08mV
357ps     10.22mV    91.82mV    2.64mV
407ps     2.916mV    25.9mV     920uV
1ns       8.035uV    33.53uV    -2.833uV
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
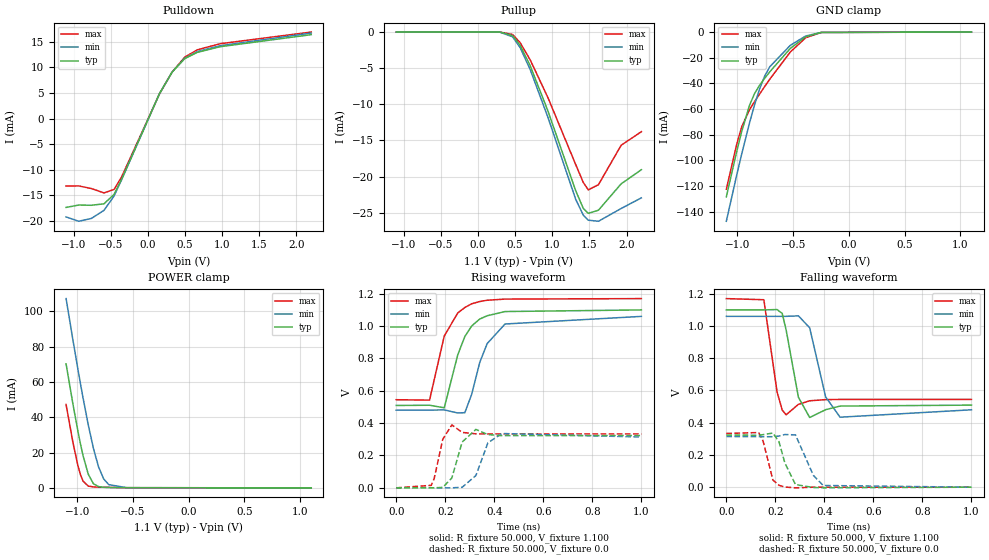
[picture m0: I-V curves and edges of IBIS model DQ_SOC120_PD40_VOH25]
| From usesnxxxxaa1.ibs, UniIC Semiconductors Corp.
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|   Model DQ_SOC120_PD40_VOH25
[Model] DQ_SOC120_PD40_VOH25
Model_type I/O
Polarity   Non-Inverting
Enable   Active-High
Vinl =  0.113V
Vinh =  0.253V
Vmeas =  0.183V
Rref =  50.000
Vref =  0.183V
C_comp   1.110pF   1.087pF   1.118pF
[Model Spec]
Vinh   0.253V   0.247V   0.265V
Vinl   0.113V   0.107V   0.125V
Vmeas   0.183V   NA   NA
Vref   0.183V   NA   NA
Rref   50.000   NA   NA
[Temperature Range]   25.000   0.125k   -40.000
[Voltage Range]   1.100V   1.060V   1.170V
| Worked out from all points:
|   slope of the pulldown table from 0 to 0.165 V, typ, clamps not added: 32.4 ohm
|   GND clamp passes 1 mA (typ) near -0.30 V on its own axis
|   POWER clamp passes 1 mA (typ) near -0.82 V on its own axis
|   rising waveform, R_fixture 50.000, V_fixture 1.100: 20-80 % time 77.2ps typ, 81.6ps min, 75.4ps max; typ from 0.509 V to 1.1 V
|   rising waveform, R_fixture 50.000, V_fixture 0.0: 20-80 % time 35.1ps typ, 43.2ps min, 27.3ps max; typ from 0 V to 0.323 V
|   falling waveform, R_fixture 50.000, V_fixture 1.100: 20-80 % time 39.5ps typ, 50.4ps min, 30ps max; typ from 1.1 V to 0.509 V
|   falling waveform, R_fixture 50.000, V_fixture 0.0: 20-80 % time 36.6ps typ, 46.4ps min, 30.1ps max; typ from 0.323 V to 0 V
[Pulldown]
|Voltage   I(typ)   I(min)   I(max)
-1.1V     -17.35mA   -19.2mA    -13.17mA
-930mV    -16.88mA   -20.05mA   -13.15mA
-760mV    -16.93mA   -19.5mA    -13.66mA
-590mV    -16.64mA   -17.92mA   -14.51mA
-454mV    -14.8mA    -15.12mA   -13.84mA
-352mV    -11.84mA   -11.92mA   -11.37mA
158mV     4.896mA    4.872mA    4.835mA
328mV     9.081mA    9.089mA    9.09mA
498mV     11.7mA     11.8mA     11.99mA
668mV     12.92mA    13.07mA    13.42mA
974mV     14.02mA    14.21mA    14.6mA
2.2V      16.37mA    16.68mA    16.88mA
[Pullup]
|Voltage   I(typ)   I(min)   I(max)
-1.1V     1nA        20.06nA    0A
296mV     -7.246uA   -20.98uA   -3.025uA
466mV     -481.5uA   -654.3uA   -337.8uA
568mV     -1.825mA   -2.144mA   -1.464mA
704mV     -4.678mA   -5.204mA   -3.865mA
942mV     -10.91mA   -11.79mA   -9.07mA
1.316V    -21.96mA   -23.15mA   -18.34mA
1.418V    -24.4mA    -25.34mA   -20.81mA
1.486V    -25.09mA   -26.04mA   -21.84mA
1.622V    -24.66mA   -26.19mA   -21.13mA
1.928V    -21.01mA   -24.42mA   -15.67mA
2.2V      -19.05mA   -22.95mA   -13.79mA
[GND_clamp]
|Voltage   I(typ)   I(min)   I(max)
-1.1V     -128.5mA   -147.6mA   -122.6mA
-1.008V   -93.62mA   -112mA     -87.95mA
-962mV    -77.6mA    -95.05mA   -73.96mA
-893mV    -57.36mA   -71.21mA   -60.7mA
-847mV    -48.01mA   -56.81mA   -54.36mA
-801mV    -41.47mA   -44.23mA   -48.33mA
-755mV    -36.02mA   -34.19mA   -42.41mA
-709mV    -30.9mA    -26.94mA   -36.63mA
-525mV    -12.67mA   -10.3mA    -15.49mA
-387mV    -3.615mA   -3.065mA   -4.419mA
-249mV    -281uA     -330.6uA   -301.3uA
1.1V      0A         0A         0A
[POWER_clamp]
|Voltage   I(typ)   I(min)   I(max)
-1.1V     70.27mA    107.3mA    47.25mA
-1.039V   47.68mA    83.93mA    25.86mA
-993mV    31.88mA    66.94mA    12.35mA
-970mV    24.65mA    58.72mA    7.262mA
-947mV    18.06mA    50.74mA    3.761mA
-901mV    7.73mA     35.71mA    987.1uA
-855mV    2.348mA    22.46mA    514uA
-809mV    697.3uA    11.94mA    396.5uA
-763mV    321uA      5.097mA    322.7uA
-717mV    213.8uA    1.813mA    258.1uA
-556mV    65.24uA    79.15uA    81.64uA
1.1V      0A         0A         0A
[Ramp]
| variable   typ   min   max
dV/dt_r   0.194/35.103p   0.188/43.353p   0.200/27.474p
dV/dt_f   0.354/40.044p   0.348/51.029p   0.375/30.125p
R_load = 50.000
[Rising Waveform]
R_fixture= 50.000
V_fixture= 1.100
V_fixture_min= 1.060
V_fixture_max= 1.170
|time   V(typ)   V(min)   V(max)
0s        509.2mV    480.2mV    544.8mV
136ps     510.7mV    480.7mV    542.2mV
196ps     494.8mV    481.7mV    938.9mV
251ps     822.3mV    462.8mV    1.081V
280ps     935.7mV    464.7mV    1.115V
308ps     1.001V     578.9mV    1.138V
341ps     1.044V     776.6mV    1.152V
371ps     1.064V     891.8mV    1.16V
444ps     1.09V      1.013V     1.167V
1ns       1.1V       1.06V      1.17V
[Rising Waveform]
R_fixture= 50.000
V_fixture= 0.0
V_fixture_min= 0.0
V_fixture_max= 0.0
|time   V(typ)   V(min)   V(max)
0s        1.709uV    13.91uV    320.5nV
143ps     61.89uV    -16.8uV    15.43mV
155ps     -54.69uV   13.92uV    57.78mV
190ps     2.677mV    32.45uV    301mV
227ps     61.2mV     31.96uV    389.1mV
269ps     283.2mV    3.298mV    342.7mV
325ps     361.2mV    75.91mV    333.7mV
374ps     329mV      278mV      333.3mV
431ps     322.6mV    335.8mV    333.3mV
1ns       323.3mV    314.2mV    333.3mV
[Falling Waveform]
R_fixture= 50.000
V_fixture= 1.100
V_fixture_min= 1.060
V_fixture_max= 1.170
|time   V(typ)   V(min)   V(max)
0s        1.1V       1.06V      1.17V
153ps     1.1V       1.06V      1.163V
207ps     1.102V     1.06V      590.6mV
228ps     1.078V     1.06V      478.5mV
244ps     975.1mV    1.06V      449.2mV
294ps     558.1mV    1.063V     513.9mV
340ps     432.4mV    988.8mV    536.1mV
405ps     480.8mV    560.1mV    543.2mV
464ps     503.3mV    434.3mV    544.5mV
1ns       509.2mV    480.2mV    544.8mV
[Falling Waveform]
R_fixture= 50.000
V_fixture= 0.0
V_fixture_min= 0.0
V_fixture_max= 0.0
|time   V(typ)   V(min)   V(max)
0s        323.3mV    314.2mV    333.3mV
132ps     322.4mV    313.7mV    339.1mV
150ps     326.1mV    313.1mV    286.1mV
190ps     336.1mV    313.2mV    44.43mV
215ps     281.2mV    317.6mV    11.33mV
239ps     149.3mV    326.8mV    959.8uV
282ps     16.37mV    324.5mV    -3.966mV
355ps     -1.832mV   73.22mV    -127.2uV
395ps     -3.822mV   10.65mV    -13.01uV
1ns       3.698uV    16.83uV    1.207uV
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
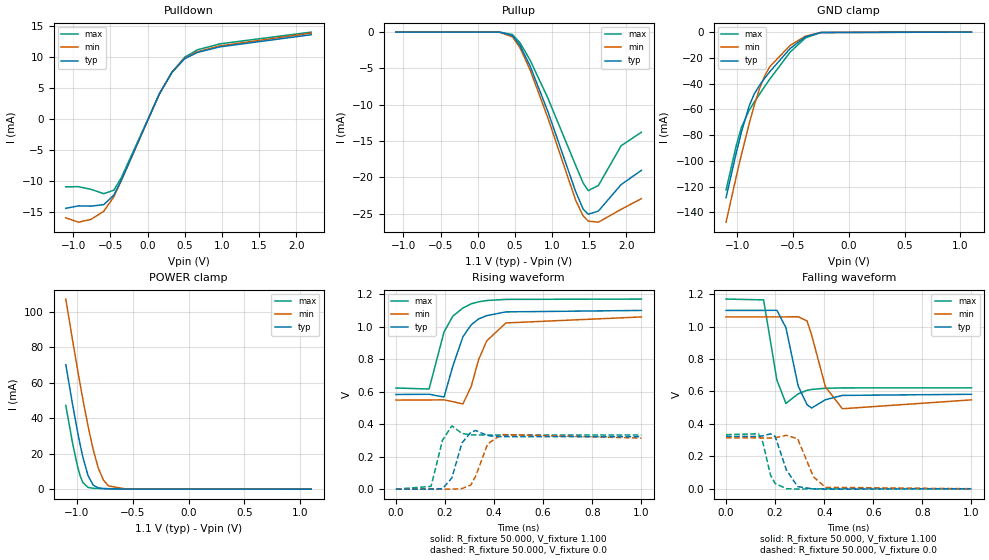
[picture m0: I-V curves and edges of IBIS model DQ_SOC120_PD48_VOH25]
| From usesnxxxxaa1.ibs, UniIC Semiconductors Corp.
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|   Model DQ_SOC120_PD48_VOH25
[Model] DQ_SOC120_PD48_VOH25
Model_type I/O
Polarity   Non-Inverting
Enable   Active-High
Vinl =  0.113V
Vinh =  0.253V
Vmeas =  0.183V
Rref =  50.000
Vref =  0.183V
C_comp   1.110pF   1.087pF   1.118pF
[Model Spec]
Vinh   0.253V   0.247V   0.265V
Vinl   0.113V   0.107V   0.125V
Vmeas   0.183V   NA   NA
Vref   0.183V   NA   NA
Rref   50.000   NA   NA
[Temperature Range]   25.000   0.125k   -40.000
[Voltage Range]   1.100V   1.060V   1.170V
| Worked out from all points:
|   slope of the pulldown table from 0 to 0.165 V, typ, clamps not added: 38.9 ohm
|   GND clamp passes 1 mA (typ) near -0.30 V on its own axis
|   POWER clamp passes 1 mA (typ) near -0.82 V on its own axis
|   rising waveform, R_fixture 50.000, V_fixture 1.100: 20-80 % time 76.8ps typ, 80.8ps min, 75.2ps max; typ from 0.583 V to 1.1 V
|   rising waveform, R_fixture 50.000, V_fixture 0.0: 20-80 % time 35.7ps typ, 43.8ps min, 27.6ps max; typ from 0 V to 0.323 V
|   falling waveform, R_fixture 50.000, V_fixture 1.100: 20-80 % time 40.5ps typ, 52.6ps min, 30.9ps max; typ from 1.1 V to 0.583 V
|   falling waveform, R_fixture 50.000, V_fixture 0.0: 20-80 % time 39.1ps typ, 48.2ps min, 32.7ps max; typ from 0.323 V to 0 V
[Pulldown]
|Voltage   I(typ)   I(min)   I(max)
-1.1V     -14.46mA   -16mA      -10.98mA
-930mV    -14.07mA   -16.71mA   -10.96mA
-760mV    -14.11mA   -16.25mA   -11.39mA
-590mV    -13.87mA   -14.94mA   -12.09mA
-454mV    -12.33mA   -12.6mA    -11.53mA
-352mV    -9.864mA   -9.937mA   -9.473mA
158mV     4.08mA     4.06mA     4.029mA
328mV     7.567mA    7.574mA    7.575mA
498mV     9.752mA    9.831mA    9.989mA
668mV     10.77mA    10.89mA    11.19mA
974mV     11.68mA    11.84mA    12.17mA
2.2V      13.64mA    13.9mA     14.07mA
[Pullup]
|Voltage   I(typ)   I(min)   I(max)
-1.1V     1nA        20.06nA    0A
296mV     -7.246uA   -20.98uA   -3.025uA
466mV     -481.5uA   -654.3uA   -337.8uA
568mV     -1.825mA   -2.144mA   -1.464mA
704mV     -4.678mA   -5.204mA   -3.865mA
942mV     -10.91mA   -11.79mA   -9.07mA
1.316V    -21.96mA   -23.15mA   -18.34mA
1.418V    -24.4mA    -25.34mA   -20.81mA
1.486V    -25.09mA   -26.04mA   -21.84mA
1.622V    -24.66mA   -26.19mA   -21.13mA
1.928V    -21.01mA   -24.42mA   -15.67mA
2.2V      -19.05mA   -22.95mA   -13.79mA
[GND_clamp]
|Voltage   I(typ)   I(min)   I(max)
-1.1V     -128.5mA   -147.6mA   -122.6mA
-1.008V   -93.62mA   -112mA     -87.95mA
-962mV    -77.6mA    -95.05mA   -73.96mA
-893mV    -57.36mA   -71.21mA   -60.7mA
-847mV    -48.01mA   -56.81mA   -54.36mA
-801mV    -41.47mA   -44.23mA   -48.33mA
-755mV    -36.02mA   -34.19mA   -42.41mA
-709mV    -30.9mA    -26.94mA   -36.63mA
-525mV    -12.67mA   -10.3mA    -15.49mA
-387mV    -3.615mA   -3.065mA   -4.419mA
-249mV    -281uA     -330.6uA   -301.3uA
1.1V      0A         0A         0A
[POWER_clamp]
|Voltage   I(typ)   I(min)   I(max)
-1.1V     70.27mA    107.3mA    47.25mA
-1.039V   47.68mA    83.93mA    25.86mA
-993mV    31.88mA    66.94mA    12.35mA
-970mV    24.65mA    58.72mA    7.262mA
-947mV    18.06mA    50.74mA    3.761mA
-901mV    7.73mA     35.71mA    987.1uA
-855mV    2.348mA    22.46mA    514uA
-809mV    697.3uA    11.94mA    396.5uA
-763mV    321uA      5.097mA    322.7uA
-717mV    213.8uA    1.813mA    258.1uA
-556mV    65.24uA    79.15uA    81.64uA
1.1V      0A         0A         0A
[Ramp]
| variable   typ   min   max
dV/dt_r   0.194/35.699p   0.188/44.071p   0.200/27.816p
dV/dt_f   0.310/41.129p   0.307/53.302p   0.329/30.877p
R_load = 50.000
[Rising Waveform]
R_fixture= 50.000
V_fixture= 1.100
V_fixture_min= 1.060
V_fixture_max= 1.170
|time   V(typ)   V(min)   V(max)
0s        582.6mV    548.3mV    622.5mV
135ps     584.1mV    548.8mV    616.4mV
196ps     566.9mV    549.8mV    967.5mV
232ps     757.6mV    538.6mV    1.065V
273ps     937.9mV    524.3mV    1.115V
307ps     1.012V     633.4mV    1.141V
337ps     1.048V     797.3mV    1.153V
370ps     1.068V     912.5mV    1.161V
448ps     1.091V     1.023V     1.168V
1ns       1.1V       1.06V      1.17V
[Rising Waveform]
R_fixture= 50.000
V_fixture= 0.0
V_fixture_min= 0.0
V_fixture_max= 0.0
|time   V(typ)   V(min)   V(max)
0s        1.908uV    15.52uV    357.4nV
143ps     9.046uV    4.626uV    17.05mV
190ps     2.9mV      25.46uV    302.1mV
228ps     69.31mV    -140.6uV   389.4mV
269ps     284.3mV    3.487mV    342.7mV
305ps     349.6mV    25.11mV    334.3mV
325ps     361.2mV    81.03mV    333.7mV
374ps     329mV      279.2mV    333.3mV
431ps     322.6mV    335.8mV    333.3mV
1ns       323.3mV    314.2mV    333.3mV
[Falling Waveform]
R_fixture= 50.000
V_fixture= 1.100
V_fixture_min= 1.060
V_fixture_max= 1.170
|time   V(typ)   V(min)   V(max)
0s        1.1V       1.06V      1.17V
153ps     1.1V       1.06V      1.165V
207ps     1.101V     1.06V      671mV
244ps     993.1mV    1.06V      526.3mV
294ps     632.9mV    1.061V     585.8mV
330ps     518.4mV    1.035V     607.1mV
349ps     498.3mV    946.6mV    612.4mV
405ps     549mV      628.4mV    619.8mV
474ps     575.7mV    493.4mV    621.9mV
1ns       582.6mV    548.3mV    622.4mV
[Falling Waveform]
R_fixture= 50.000
V_fixture= 0.0
V_fixture_min= 0.0
V_fixture_max= 0.0
|time   V(typ)   V(min)   V(max)
0s        323.3mV    314.2mV    333.3mV
132ps     322.4mV    313.7mV    338.9mV
150ps     326.1mV    313.1mV    285.6mV
181ps     338.7mV    312.8mV    84.82mV
200ps     323.1mV    314.3mV    32.04mV
246ps     115.5mV    329.9mV    495.8uV
292ps     13.19mV    307.6mV    -2.16mV
356ps     -1.347mV   73.9mV     -141.3uV
405ps     -2.624mV   8.644mV    -10.83uV
1ns       4.366uV    19.17uV    1.328uV
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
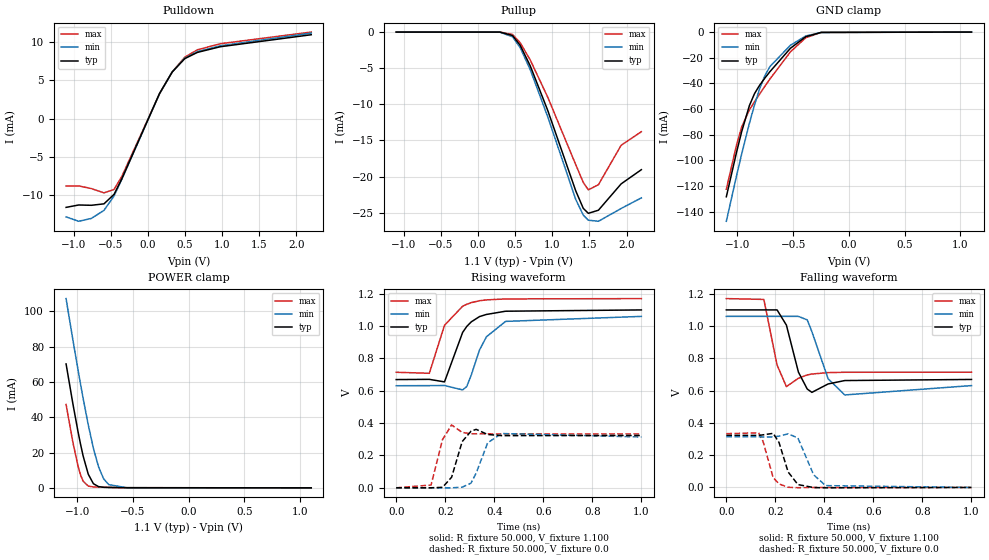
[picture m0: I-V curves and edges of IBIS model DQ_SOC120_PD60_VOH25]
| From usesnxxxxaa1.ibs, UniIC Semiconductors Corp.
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|   Model DQ_SOC120_PD60_VOH25
[Model] DQ_SOC120_PD60_VOH25
Model_type I/O
Polarity   Non-Inverting
Enable   Active-High
Vinl =  0.113V
Vinh =  0.253V
Vmeas =  0.183V
Rref =  50.000
Vref =  0.183V
C_comp   1.110pF   1.087pF   1.118pF
[Model Spec]
Vinh   0.253V   0.247V   0.265V
Vinl   0.113V   0.107V   0.125V
Vmeas   0.183V   NA   NA
Vref   0.183V   NA   NA
Rref   50.000   NA   NA
[Temperature Range]   25.000   0.125k   -40.000
[Voltage Range]   1.100V   1.060V   1.170V
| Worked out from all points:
|   slope of the pulldown table from 0 to 0.165 V, typ, clamps not added: 48.6 ohm
|   GND clamp passes 1 mA (typ) near -0.30 V on its own axis
|   POWER clamp passes 1 mA (typ) near -0.82 V on its own axis
|   rising waveform, R_fixture 50.000, V_fixture 1.100: 20-80 % time 76.2ps typ, 80ps min, 74.9ps max; typ from 0.669 V to 1.1 V
|   rising waveform, R_fixture 50.000, V_fixture 0.0: 20-80 % time 36.3ps typ, 44.9ps min, 28ps max; typ from 0 V to 0.323 V
|   falling waveform, R_fixture 50.000, V_fixture 1.100: 20-80 % time 41.4ps typ, 54.1ps min, 31.5ps max; typ from 1.1 V to 0.669 V
|   falling waveform, R_fixture 50.000, V_fixture 0.0: 20-80 % time 41.9ps typ, 50.7ps min, 35.8ps max; typ from 0.323 V to 0 V
[Pulldown]
|Voltage   I(typ)   I(min)   I(max)
-1.1V     -11.56mA   -12.8mA    -8.78mA
-930mV    -11.25mA   -13.37mA   -8.769mA
-760mV    -11.29mA   -13mA      -9.11mA
-590mV    -11.1mA    -11.95mA   -9.675mA
-454mV    -9.865mA   -10.08mA   -9.225mA
-352mV    -7.891mA   -7.949mA   -7.578mA
158mV     3.264mA    3.248mA    3.223mA
328mV     6.054mA    6.059mA    6.06mA
498mV     7.801mA    7.865mA    7.991mA
668mV     8.612mA    8.711mA    8.95mA
974mV     9.345mA    9.47mA     9.737mA
2.2V      10.91mA    11.12mA    11.26mA
[Pullup]
|Voltage   I(typ)   I(min)   I(max)
-1.1V     1nA        20.06nA    0A
296mV     -7.246uA   -20.98uA   -3.025uA
466mV     -481.5uA   -654.3uA   -337.8uA
568mV     -1.825mA   -2.144mA   -1.464mA
704mV     -4.678mA   -5.204mA   -3.865mA
942mV     -10.91mA   -11.79mA   -9.07mA
1.316V    -21.96mA   -23.15mA   -18.34mA
1.418V    -24.4mA    -25.34mA   -20.81mA
1.486V    -25.09mA   -26.04mA   -21.84mA
1.622V    -24.66mA   -26.19mA   -21.13mA
1.928V    -21.01mA   -24.42mA   -15.67mA
2.2V      -19.05mA   -22.95mA   -13.79mA
[GND_clamp]
|Voltage   I(typ)   I(min)   I(max)
-1.1V     -128.5mA   -147.6mA   -122.6mA
-1.008V   -93.62mA   -112mA     -87.95mA
-962mV    -77.6mA    -95.05mA   -73.96mA
-893mV    -57.36mA   -71.21mA   -60.7mA
-847mV    -48.01mA   -56.81mA   -54.36mA
-801mV    -41.47mA   -44.23mA   -48.33mA
-755mV    -36.02mA   -34.19mA   -42.41mA
-709mV    -30.9mA    -26.94mA   -36.63mA
-525mV    -12.67mA   -10.3mA    -15.49mA
-387mV    -3.615mA   -3.065mA   -4.419mA
-249mV    -281uA     -330.6uA   -301.3uA
1.1V      0A         0A         0A
[POWER_clamp]
|Voltage   I(typ)   I(min)   I(max)
-1.1V     70.27mA    107.3mA    47.25mA
-1.039V   47.68mA    83.93mA    25.86mA
-993mV    31.88mA    66.94mA    12.35mA
-970mV    24.65mA    58.72mA    7.262mA
-947mV    18.06mA    50.74mA    3.761mA
-901mV    7.73mA     35.71mA    987.1uA
-855mV    2.348mA    22.46mA    514uA
-809mV    697.3uA    11.94mA    396.5uA
-763mV    321uA      5.097mA    322.7uA
-717mV    213.8uA    1.813mA    258.1uA
-556mV    65.24uA    79.15uA    81.64uA
1.1V      0A         0A         0A
[Ramp]
| variable   typ   min   max
dV/dt_r   0.194/36.488p   0.188/45.597p   0.200/28.066p
dV/dt_f   0.258/41.841p   0.257/54.811p   0.273/31.629p
R_load = 50.000
[Rising Waveform]
R_fixture= 50.000
V_fixture= 1.100
V_fixture_min= 1.060
V_fixture_max= 1.170
|time   V(typ)   V(min)   V(max)
0s        669.2mV    631.2mV    714.4mV
135ps     670.6mV    631.8mV    708.1mV
197ps     654.9mV    632.5mV    1.005V
271ps     961mV      605.4mV    1.123V
288ps     998.3mV    626.8mV    1.135V
306ps     1.026V     696.8mV    1.145V
340ps     1.059V     852.8mV    1.157V
368ps     1.072V     933.7mV    1.162V
446ps     1.092V     1.029V     1.168V
1ns       1.1V       1.06V      1.17V
[Rising Waveform]
R_fixture= 50.000
V_fixture= 0.0
V_fixture_min= 0.0
V_fixture_max= 0.0
|time   V(typ)   V(min)   V(max)
0s        2.16uV     17.56uV    404.1nV
142ps     -38.29uV   23.84uV    16.88mV
189ps     2.875mV    5.257uV    298.2mV
226ps     65.36mV    -339.6uV   388.8mV
269ps     285.4mV    3.833mV    342.6mV
305ps     349.6mV    28.65mV    334.3mV
326ps     361.4mV    90.14mV    333.6mV
373ps     329.6mV    278mV      333.3mV
430ps     322.6mV    335.5mV    333.3mV
1ns       323.3mV    314.2mV    333.3mV
[Falling Waveform]
R_fixture= 50.000
V_fixture= 1.100
V_fixture_min= 1.060
V_fixture_max= 1.170
|time   V(typ)   V(min)   V(max)
0s        1.1V       1.06V      1.17V
153ps     1.1V       1.06V      1.165V
207ps     1.1V       1.06V      758.7mV
245ps     1.006V     1.06V      624.7mV
294ps     714.8mV    1.06V      676.7mV
330ps     609.8mV    1.038V     697.2mV
349ps     589.2mV    965.3mV    702.8mV
415ps     641.2mV    673.8mV    711.6mV
483ps     662.4mV    573.2mV    713.7mV
1ns       669.2mV    631.2mV    714.4mV
[Falling Waveform]
R_fixture= 50.000
V_fixture= 0.0
V_fixture_min= 0.0
V_fixture_max= 0.0
|time   V(typ)   V(min)   V(max)
0s        323.3mV    314.2mV    333.3mV
132ps     322.4mV    313.7mV    338.7mV
150ps     326.2mV    313.1mV    284.5mV
191ps     335.4mV    313.3mV    61.38mV
215ps     278.4mV    317.8mV    21.89mV
252ps     96.26mV    332.5mV    1.366mV
292ps     17.99mV    306.5mV    -1.36mV
356ps     -355.9uV   78.62mV    -115.9uV
405ps     -2.171mV   11.56mV    -10.74uV
1ns       5.113uV    21.66uV    1.104uV
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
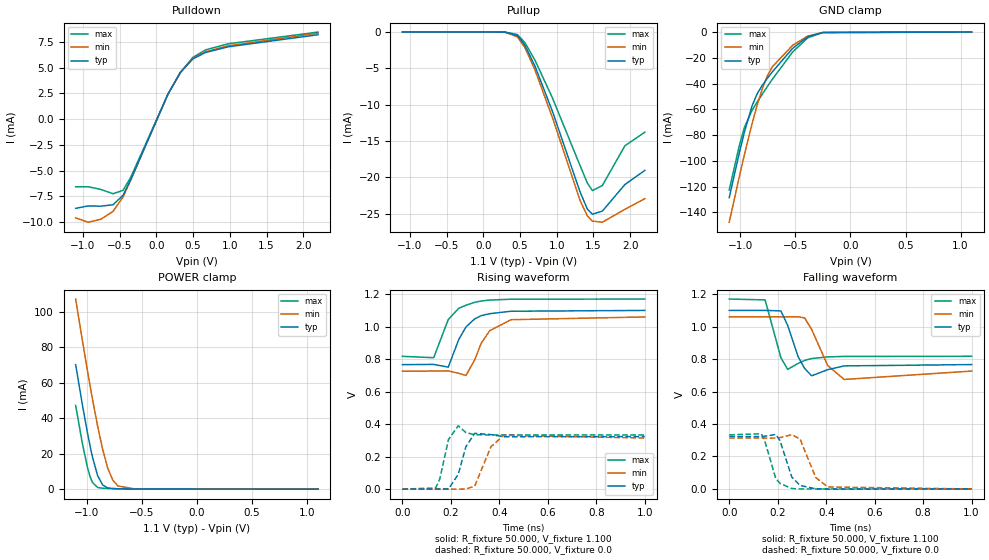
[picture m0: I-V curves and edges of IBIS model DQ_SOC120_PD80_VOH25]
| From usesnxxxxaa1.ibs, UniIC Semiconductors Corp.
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|   Model DQ_SOC120_PD80_VOH25
[Model] DQ_SOC120_PD80_VOH25
Model_type I/O
Polarity   Non-Inverting
Enable   Active-High
Vinl =  0.113V
Vinh =  0.253V
Vmeas =  0.183V
Rref =  50.000
Vref =  0.183V
C_comp   1.110pF   1.087pF   1.118pF
[Model Spec]
Vinh   0.253V   0.247V   0.265V
Vinl   0.113V   0.107V   0.125V
Vmeas   0.183V   NA   NA
Vref   0.183V   NA   NA
Rref   50.000   NA   NA
[Temperature Range]   25.000   0.125k   -40.000
[Voltage Range]   1.100V   1.060V   1.170V
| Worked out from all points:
|   slope of the pulldown table from 0 to 0.165 V, typ, clamps not added: 64.8 ohm
|   GND clamp passes 1 mA (typ) near -0.30 V on its own axis
|   POWER clamp passes 1 mA (typ) near -0.82 V on its own axis
|   rising waveform, R_fixture 50.000, V_fixture 1.100: 20-80 % time 73.3ps typ, 75.8ps min, 72.7ps max; typ from 0.766 V to 1.1 V
|   rising waveform, R_fixture 50.000, V_fixture 0.0: 20-80 % time 36.6ps typ, 45.2ps min, 28ps max; typ from 0 V to 0.323 V
|   falling waveform, R_fixture 50.000, V_fixture 1.100: 20-80 % time 43.6ps typ, 55.9ps min, 32.9ps max; typ from 1.1 V to 0.766 V
|   falling waveform, R_fixture 50.000, V_fixture 0.0: 20-80 % time 43.2ps typ, 50.1ps min, 39ps max; typ from 0.323 V to 0 V
[Pulldown]
|Voltage   I(typ)   I(min)   I(max)
-1.1V     -8.673mA   -9.601mA   -6.585mA
-930mV    -8.439mA   -10.02mA   -6.577mA
-760mV    -8.467mA   -9.748mA   -6.832mA
-590mV    -8.322mA   -8.962mA   -7.256mA
-454mV    -7.399mA   -7.561mA   -6.919mA
-352mV    -5.919mA   -5.962mA   -5.684mA
158mV     2.448mA    2.436mA    2.417mA
328mV     4.54mA     4.545mA    4.545mA
498mV     5.851mA    5.899mA    5.993mA
668mV     6.459mA    6.534mA    6.712mA
974mV     7.009mA    7.103mA    7.302mA
2.2V      8.186mA    8.338mA    8.442mA
[Pullup]
|Voltage   I(typ)   I(min)   I(max)
-1.1V     1nA        20.06nA    0A
296mV     -7.246uA   -20.98uA   -3.025uA
466mV     -481.5uA   -654.3uA   -337.8uA
568mV     -1.825mA   -2.144mA   -1.464mA
704mV     -4.678mA   -5.204mA   -3.865mA
942mV     -10.91mA   -11.79mA   -9.07mA
1.316V    -21.96mA   -23.15mA   -18.34mA
1.418V    -24.4mA    -25.34mA   -20.81mA
1.486V    -25.09mA   -26.04mA   -21.84mA
1.622V    -24.66mA   -26.19mA   -21.13mA
1.928V    -21.01mA   -24.42mA   -15.67mA
2.2V      -19.05mA   -22.95mA   -13.79mA
[GND_clamp]
|Voltage   I(typ)   I(min)   I(max)
-1.1V     -128.5mA   -147.6mA   -122.6mA
-1.008V   -93.62mA   -112mA     -87.95mA
-962mV    -77.6mA    -95.05mA   -73.96mA
-893mV    -57.36mA   -71.21mA   -60.7mA
-847mV    -48.01mA   -56.81mA   -54.36mA
-801mV    -41.47mA   -44.23mA   -48.33mA
-755mV    -36.02mA   -34.19mA   -42.41mA
-709mV    -30.9mA    -26.94mA   -36.63mA
-525mV    -12.67mA   -10.3mA    -15.49mA
-387mV    -3.615mA   -3.065mA   -4.419mA
-249mV    -281uA     -330.6uA   -301.3uA
1.1V      0A         0A         0A
[POWER_clamp]
|Voltage   I(typ)   I(min)   I(max)
-1.1V     70.27mA    107.3mA    47.25mA
-1.039V   47.68mA    83.93mA    25.86mA
-993mV    31.88mA    66.94mA    12.35mA
-970mV    24.65mA    58.72mA    7.262mA
-947mV    18.06mA    50.74mA    3.761mA
-901mV    7.73mA     35.71mA    987.1uA
-855mV    2.348mA    22.46mA    514uA
-809mV    697.3uA    11.94mA    396.5uA
-763mV    321uA      5.097mA    322.7uA
-717mV    213.8uA    1.813mA    258.1uA
-556mV    65.24uA    79.15uA    81.64uA
1.1V      0A         0A         0A
[Ramp]
| variable   typ   min   max
dV/dt_r   0.194/36.596p   0.188/45.754p   0.200/28.127p
dV/dt_f   0.200/43.428p   0.200/56.231p   0.212/32.949p
R_load = 50.000
[Rising Waveform]
R_fixture= 50.000
V_fixture= 1.100
V_fixture_min= 1.060
V_fixture_max= 1.170
|time   V(typ)   V(min)   V(max)
0s        766.3mV    726.4mV    817.4mV
129ps     767.7mV    726.7mV    809mV
189ps     751mV      727.7mV    1.044V
232ps     919.9mV    712.9mV    1.113V
262ps     998.3mV    699.8mV    1.132V
298ps     1.048V     795.3mV    1.15V
325ps     1.068V     897.6mV    1.158V
360ps     1.08V      975.2mV    1.164V
448ps     1.095V     1.043V     1.169V
1ns       1.1V       1.06V      1.17V
[Rising Waveform]
R_fixture= 50.000
V_fixture= 0.0
V_fixture_min= 0.0
V_fixture_max= 0.0
|time   V(typ)   V(min)   V(max)
0s        2.487uV    20.21uV    464.7nV
137ps     95.26uV    24.17uV    6.746mV
154ps     -257.1uV   62.87uV    62.23mV
190ps     1.578mV    79.49uV    305mV
230ps     90mV       -371.5uV   389.9mV
262ps     261.6mV    916.8uV    347.9mV
298ps     343.4mV    18.38mV    334.8mV
365ps     335.4mV    260.4mV    333.4mV
418ps     322.2mV    331.3mV    333.3mV
1ns       323.3mV    314.2mV    333.3mV
[Falling Waveform]
R_fixture= 50.000
V_fixture= 1.100
V_fixture_min= 1.060
V_fixture_max= 1.170
|time   V(typ)   V(min)   V(max)
0s        1.1V       1.06V      1.17V
148ps     1.1V       1.06V      1.165V
213ps     1.097V     1.06V      809.6mV
241ps     1.008V     1.061V     736.8mV
284ps     815.7mV    1.061V     773.3mV
311ps     742.6mV    1.054V     792mV
340ps     697mV      982.7mV    803.3mV
406ps     734.9mV    761.2mV    813.7mV
474ps     758.1mV    674.6mV    816.5mV
1ns       766.3mV    726.4mV    817.4mV
[Falling Waveform]
R_fixture= 50.000
V_fixture= 0.0
V_fixture_min= 0.0
V_fixture_max= 0.0
|time   V(typ)   V(min)   V(max)
0s        323.3mV    314.2mV    333.3mV
132ps     322.4mV    313.7mV    339.9mV
145ps     324.6mV    313.3mV    304.1mV
192ps     335.6mV    313.4mV    64.09mV
209ps     299mV      316.2mV    34.37mV
258ps     73.45mV    334.4mV    2.785mV
292ps     21.37mV    307.9mV    13.33uV
357ps     859.6uV    69.81mV    27.2uV
407ps     -1.42mV    11.93mV    14.42uV
1ns       5.777uV    24.9uV     -383.8nV
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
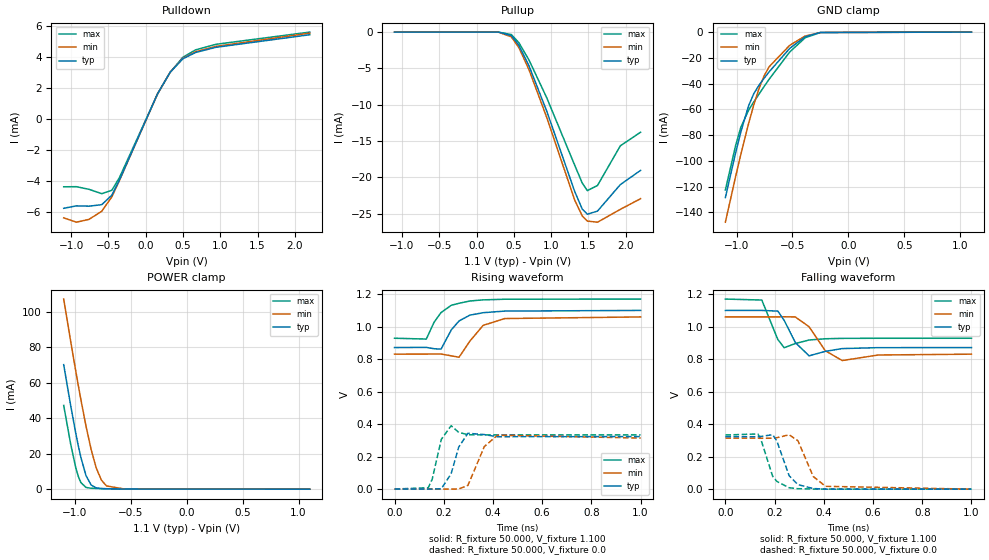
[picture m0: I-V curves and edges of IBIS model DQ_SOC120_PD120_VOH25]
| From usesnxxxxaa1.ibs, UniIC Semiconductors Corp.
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|   Model DQ_SOC120_PD120_VOH25
[Model] DQ_SOC120_PD120_VOH25
Model_type I/O
Polarity   Non-Inverting
Enable   Active-High
Vinl =  0.113V
Vinh =  0.253V
Vmeas =  0.183V
Rref =  50.000
Vref =  0.183V
C_comp   1.110pF   1.087pF   1.118pF
[Model Spec]
Vinh   0.253V   0.247V   0.265V
Vinl   0.113V   0.107V   0.125V
Vmeas   0.183V   NA   NA
Vref   0.183V   NA   NA
Rref   50.000   NA   NA
[Temperature Range]   25.000   0.125k   -40.000
[Voltage Range]   1.100V   1.060V   1.170V
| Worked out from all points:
|   slope of the pulldown table from 0 to 0.165 V, typ, clamps not added: 97.2 ohm
|   GND clamp passes 1 mA (typ) near -0.30 V on its own axis
|   POWER clamp passes 1 mA (typ) near -0.82 V on its own axis
|   rising waveform, R_fixture 50.000, V_fixture 1.100: 20-80 % time 71ps typ, 72.6ps min, 71.3ps max; typ from 0.871 V to 1.1 V
|   rising waveform, R_fixture 50.000, V_fixture 0.0: 20-80 % time 37.3ps typ, 46.4ps min, 28.5ps max; typ from 0 V to 0.323 V
|   falling waveform, R_fixture 50.000, V_fixture 1.100: 20-80 % time 44ps typ, 56.8ps min, 33.2ps max; typ from 1.1 V to 0.871 V
|   falling waveform, R_fixture 50.000, V_fixture 0.0: 20-80 % time 48.7ps typ, 54.7ps min, 46.1ps max; typ from 0.323 V to 0 V
[Pulldown]
|Voltage   I(typ)   I(min)   I(max)
-1.1V     -5.782mA   -6.401mA   -4.39mA
-930mV    -5.626mA   -6.683mA   -4.384mA
-760mV    -5.645mA   -6.499mA   -4.555mA
-590mV    -5.548mA   -5.975mA   -4.837mA
-454mV    -4.933mA   -5.041mA   -4.613mA
-352mV    -3.946mA   -3.975mA   -3.789mA
158mV     1.632mA    1.624mA    1.612mA
328mV     3.027mA    3.03mA     3.03mA
498mV     3.901mA    3.932mA    3.996mA
668mV     4.306mA    4.356mA    4.475mA
940mV     4.641mA    4.702mA    4.836mA
2.2V      5.457mA    5.559mA    5.628mA
[Pullup]
|Voltage   I(typ)   I(min)   I(max)
-1.1V     1nA        20.06nA    0A
296mV     -7.246uA   -20.98uA   -3.025uA
466mV     -481.5uA   -654.3uA   -337.8uA
568mV     -1.825mA   -2.144mA   -1.464mA
704mV     -4.678mA   -5.204mA   -3.865mA
942mV     -10.91mA   -11.79mA   -9.07mA
1.316V    -21.96mA   -23.15mA   -18.34mA
1.418V    -24.4mA    -25.34mA   -20.81mA
1.486V    -25.09mA   -26.04mA   -21.84mA
1.622V    -24.66mA   -26.19mA   -21.13mA
1.928V    -21.01mA   -24.42mA   -15.67mA
2.2V      -19.05mA   -22.95mA   -13.79mA
[GND_clamp]
|Voltage   I(typ)   I(min)   I(max)
-1.1V     -128.5mA   -147.6mA   -122.6mA
-1.008V   -93.62mA   -112mA     -87.95mA
-962mV    -77.6mA    -95.05mA   -73.96mA
-893mV    -57.36mA   -71.21mA   -60.7mA
-847mV    -48.01mA   -56.81mA   -54.36mA
-801mV    -41.47mA   -44.23mA   -48.33mA
-755mV    -36.02mA   -34.19mA   -42.41mA
-709mV    -30.9mA    -26.94mA   -36.63mA
-525mV    -12.67mA   -10.3mA    -15.49mA
-387mV    -3.615mA   -3.065mA   -4.419mA
-249mV    -281uA     -330.6uA   -301.3uA
1.1V      0A         0A         0A
[POWER_clamp]
|Voltage   I(typ)   I(min)   I(max)
-1.1V     70.27mA    107.3mA    47.25mA
-1.039V   47.68mA    83.93mA    25.86mA
-993mV    31.88mA    66.94mA    12.35mA
-970mV    24.65mA    58.72mA    7.262mA
-947mV    18.06mA    50.74mA    3.761mA
-901mV    7.73mA     35.71mA    987.1uA
-855mV    2.348mA    22.46mA    514uA
-809mV    697.3uA    11.94mA    396.5uA
-763mV    321uA      5.097mA    322.7uA
-717mV    213.8uA    1.813mA    258.1uA
-556mV    65.24uA    79.15uA    81.64uA
1.1V      0A         0A         0A
[Ramp]
| variable   typ   min   max
dV/dt_r   0.194/37.595p   0.188/46.891p   0.200/28.501p
dV/dt_f   0.137/44.046p   0.138/57.064p   0.145/33.119p
R_load = 50.000
[Rising Waveform]
R_fixture= 50.000
V_fixture= 1.100
V_fixture_min= 1.060
V_fixture_max= 1.170
|time   V(typ)   V(min)   V(max)
0s        871.4mV    830.8mV    928.8mV
129ps     872.4mV    831.1mV    923.7mV
161ps     864.1mV    832mV      1.028V
189ps     861.8mV    831.6mV    1.087V
231ps     981.1mV    820.3mV    1.132V
262ps     1.035V     811.7mV    1.144V
306ps     1.071V     910.7mV    1.158V
360ps     1.086V     1.008V     1.165V
448ps     1.096V     1.05V      1.169V
1ns       1.1V       1.06V      1.17V
[Rising Waveform]
R_fixture= 50.000
V_fixture= 0.0
V_fixture_min= 0.0
V_fixture_max= 0.0
|time   V(typ)   V(min)   V(max)
0s        2.932uV    23.8uV     546.7nV
137ps     49.01uV    51.36uV    8.421mV
153ps     -388.5uV   87.26uV    60.33mV
190ps     2.065mV    49.7uV     305.9mV
230ps     94.3mV     -665.9uV   390.1mV
261ps     259.2mV    762.1uV    348.9mV
298ps     343.5mV    22.2mV     334.8mV
365ps     335.4mV    261.7mV    333.4mV
418ps     322.2mV    331.3mV    333.3mV
1ns       323.3mV    314.2mV    333.3mV
[Falling Waveform]
R_fixture= 50.000
V_fixture= 1.100
V_fixture_min= 1.060
V_fixture_max= 1.170
|time   V(typ)   V(min)   V(max)
0s        1.1V       1.06V      1.17V
148ps     1.1V       1.06V      1.164V
213ps     1.096V     1.06V      921.5mV
239ps     1.039V     1.061V     870.6mV
284ps     902.9mV    1.06V      896.2mV
340ps     820.5mV    1V         918mV
406ps     848.1mV    852.1mV    925.7mV
475ps     865.2mV    791.5mV    928mV
621ps     871mV      825.7mV    928.7mV
1ns       871.4mV    830.8mV    928.8mV
[Falling Waveform]
R_fixture= 50.000
V_fixture= 0.0
V_fixture_min= 0.0
V_fixture_max= 0.0
|time   V(typ)   V(min)   V(max)
0s        323.3mV    314.2mV    333.3mV
132ps     322.4mV    313.7mV    339.7mV
145ps     324.6mV    313.2mV    302.9mV
192ps     335.2mV    313.4mV    79.89mV
209ps     297.4mV    316.3mV    47.74mV
259ps     82.96mV    334.7mV    8.597mV
295ps     27.79mV    297.8mV    2.771mV
357ps     3.818mV    77.96mV    597.6uV
407ps     -124uV     17.43mV    174.6uV
1ns       2.727uV    29.35uV    2.522uV
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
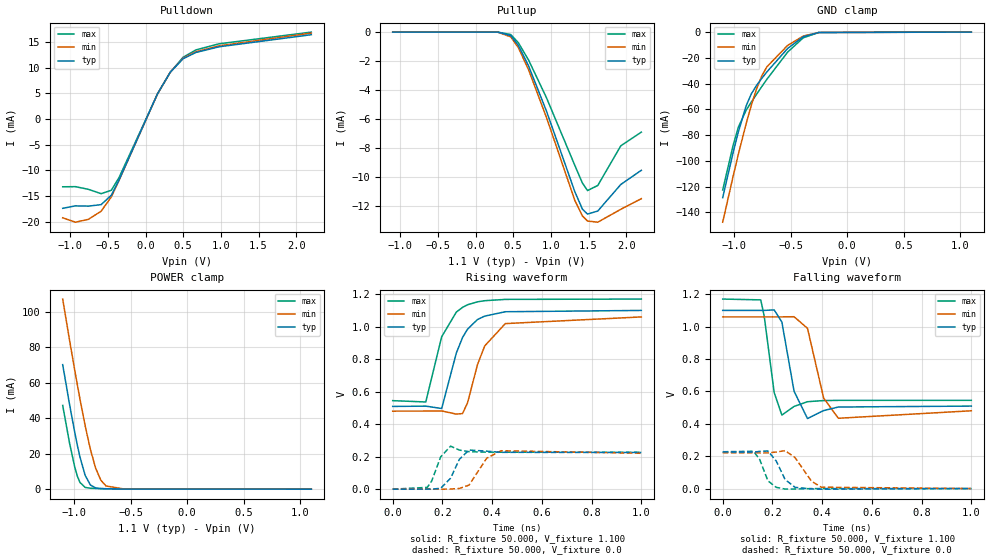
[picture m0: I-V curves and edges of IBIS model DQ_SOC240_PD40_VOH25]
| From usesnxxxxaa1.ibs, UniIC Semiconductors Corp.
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|   Model DQ_SOC240_PD40_VOH25
[Model] DQ_SOC240_PD40_VOH25
Model_type I/O
Polarity   Non-Inverting
Enable   Active-High
Vinl =  0.113V
Vinh =  0.253V
Vmeas =  0.183V
Rref =  50.000
Vref =  0.183V
C_comp   1.110pF   1.087pF   1.118pF
[Model Spec]
Vinh   0.253V   0.247V   0.265V
Vinl   0.113V   0.107V   0.125V
Vmeas   0.183V   NA   NA
Vref   0.183V   NA   NA
Rref   50.000   NA   NA
[Temperature Range]   25.000   0.125k   -40.000
[Voltage Range]   1.100V   1.060V   1.170V
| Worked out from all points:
|   slope of the pulldown table from 0 to 0.165 V, typ, clamps not added: 32.4 ohm
|   GND clamp passes 1 mA (typ) near -0.30 V on its own axis
|   POWER clamp passes 1 mA (typ) near -0.82 V on its own axis
|   rising waveform, R_fixture 50.000, V_fixture 1.100: 20-80 % time 77.5ps typ, 82.3ps min, 75.2ps max; typ from 0.509 V to 1.1 V
|   rising waveform, R_fixture 50.000, V_fixture 0.0: 20-80 % time 41.5ps typ, 52.5ps min, 32.5ps max; typ from 0 V to 0.226 V
|   falling waveform, R_fixture 50.000, V_fixture 1.100: 20-80 % time 39.6ps typ, 50ps min, 29.7ps max; typ from 1.1 V to 0.509 V
|   falling waveform, R_fixture 50.000, V_fixture 0.0: 20-80 % time 45.1ps typ, 59ps min, 34.8ps max; typ from 0.226 V to 0 V
[Pulldown]
|Voltage   I(typ)   I(min)   I(max)
-1.1V     -17.35mA   -19.2mA    -13.17mA
-930mV    -16.88mA   -20.05mA   -13.15mA
-760mV    -16.93mA   -19.5mA    -13.66mA
-590mV    -16.64mA   -17.92mA   -14.51mA
-454mV    -14.8mA    -15.12mA   -13.84mA
-352mV    -11.84mA   -11.92mA   -11.37mA
158mV     4.896mA    4.872mA    4.835mA
328mV     9.081mA    9.089mA    9.09mA
498mV     11.7mA     11.8mA     11.99mA
668mV     12.92mA    13.07mA    13.42mA
974mV     14.02mA    14.21mA    14.6mA
2.2V      16.37mA    16.68mA    16.88mA
[Pullup]
|Voltage   I(typ)   I(min)   I(max)
-1.1V     -58.82pA   10nA       0A
296mV     -3.623uA   -10.49uA   -1.513uA
466mV     -240.8uA   -327.2uA   -168.9uA
568mV     -912.6uA   -1.072mA   -732.2uA
704mV     -2.339mA   -2.602mA   -1.933mA
942mV     -5.457mA   -5.897mA   -4.535mA
1.316V    -10.98mA   -11.58mA   -9.169mA
1.418V    -12.2mA    -12.67mA   -10.4mA
1.486V    -12.54mA   -13.02mA   -10.92mA
1.622V    -12.33mA   -13.1mA    -10.57mA
1.928V    -10.5mA    -12.21mA   -7.835mA
2.2V      -9.524mA   -11.48mA   -6.896mA
[GND_clamp]
|Voltage   I(typ)   I(min)   I(max)
-1.1V     -128.5mA   -147.6mA   -122.6mA
-1.008V   -93.62mA   -112mA     -87.95mA
-962mV    -77.6mA    -95.05mA   -73.96mA
-893mV    -57.36mA   -71.21mA   -60.7mA
-847mV    -48.01mA   -56.81mA   -54.36mA
-801mV    -41.47mA   -44.23mA   -48.33mA
-755mV    -36.02mA   -34.19mA   -42.41mA
-709mV    -30.9mA    -26.94mA   -36.63mA
-525mV    -12.67mA   -10.3mA    -15.49mA
-387mV    -3.615mA   -3.065mA   -4.419mA
-249mV    -281uA     -330.6uA   -301.3uA
1.1V      0A         0A         0A
[POWER_clamp]
|Voltage   I(typ)   I(min)   I(max)
-1.1V     70.27mA    107.3mA    47.25mA
-1.039V   47.68mA    83.93mA    25.86mA
-993mV    31.88mA    66.94mA    12.35mA
-970mV    24.65mA    58.72mA    7.262mA
-947mV    18.06mA    50.74mA    3.761mA
-901mV    7.73mA     35.71mA    987.1uA
-855mV    2.348mA    22.46mA    514uA
-809mV    697.3uA    11.94mA    396.5uA
-763mV    321uA      5.097mA    322.7uA
-717mV    213.8uA    1.813mA    258.1uA
-556mV    65.24uA    79.15uA    81.64uA
1.1V      0A         0A         0A
[Ramp]
| variable   typ   min   max
dV/dt_r   0.136/41.855p   0.132/52.320p   0.136/32.671p
dV/dt_f   0.354/39.755p   0.348/50.489p   0.375/30.213p
R_load = 50.000
[Rising Waveform]
R_fixture= 50.000
V_fixture= 1.100
V_fixture_min= 1.060
V_fixture_max= 1.170
|time   V(typ)   V(min)   V(max)
0s        509.2mV    480.2mV    544.8mV
133ps     511mV      480.6mV    536.6mV
197ps     496.4mV    481.5mV    938.1mV
256ps     838.6mV    462mV      1.09V
281ps     933.6mV    465.3mV    1.119V
301ps     984.7mV    531.4mV    1.135V
341ps     1.044V     766.5mV    1.153V
370ps     1.065V     881.5mV    1.16V
453ps     1.092V     1.019V     1.168V
1ns       1.1V       1.06V      1.17V
[Rising Waveform]
R_fixture= 50.000
V_fixture= 0.0
V_fixture_min= 0.0
V_fixture_max= 0.0
|time   V(typ)   V(min)   V(max)
0s        1.709uV    13.91uV    320.5nV
139ps     31.7uV     -44.13uV   11mV
157ps     158.7uV    -9.6uV     50.97mV
193ps     5.294mV    -25.56uV   198.9mV
233ps     67.81mV    626.8uV    264.8mV
268ps     183.4mV    4.396mV    240.6mV
307ps     240.8mV    24.85mV    230.7mV
378ps     234mV      190.5mV    227.6mV
436ps     226.5mV    236.4mV    227.3mV
1ns       225.9mV    220.8mV    227.2mV
[Falling Waveform]
R_fixture= 50.000
V_fixture= 1.100
V_fixture_min= 1.060
V_fixture_max= 1.170
|time   V(typ)   V(min)   V(max)
0s        1.1V       1.06V      1.17V
153ps     1.1V       1.06V      1.165V
167ps     1.1V       1.06V      1.064V
207ps     1.103V     1.06V      592.9mV
238ps     1.028V     1.06V      453.8mV
287ps     601.1mV    1.061V     507mV
341ps     432.3mV    989.3mV    536.3mV
406ps     481.5mV    558.8mV    543.3mV
465ps     503.4mV    434mV      544.5mV
1ns       509.2mV    480.2mV    544.8mV
[Falling Waveform]
R_fixture= 50.000
V_fixture= 0.0
V_fixture_min= 0.0
V_fixture_max= 0.0
|time   V(typ)   V(min)   V(max)
0s        225.9mV    220.8mV    227.2mV
124ps     225.2mV    220.6mV    230.3mV
149ps     229.6mV    220mV      178.7mV
182ps     232mV      220.2mV    47.4mV
215ps     170.5mV    225.6mV    7.813mV
251ps     55.81mV    234.1mV    -3.175mV
291ps     7.624mV    191mV      -2.774mV
357ps     -2.188mV   45.29mV    -130uV
397ps     -3.742mV   8.404mV    -18.63uV
1ns       -865.2nV   15.77uV    424.8nV
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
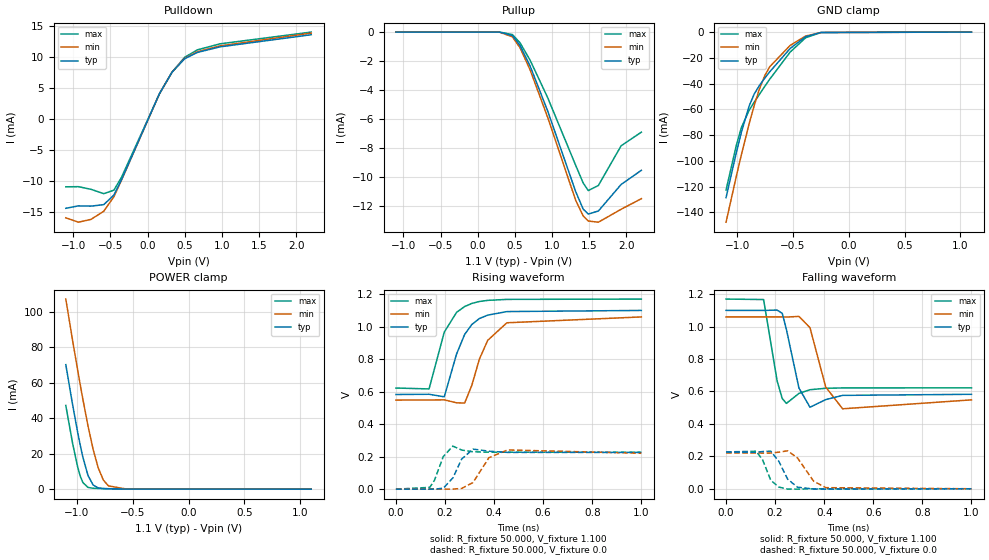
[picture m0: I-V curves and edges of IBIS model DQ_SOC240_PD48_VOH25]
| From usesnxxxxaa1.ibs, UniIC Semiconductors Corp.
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|   Model DQ_SOC240_PD48_VOH25
[Model] DQ_SOC240_PD48_VOH25
Model_type I/O
Polarity   Non-Inverting
Enable   Active-High
Vinl =  0.113V
Vinh =  0.253V
Vmeas =  0.183V
Rref =  50.000
Vref =  0.183V
C_comp   1.110pF   1.087pF   1.118pF
[Model Spec]
Vinh   0.253V   0.247V   0.265V
Vinl   0.113V   0.107V   0.125V
Vmeas   0.183V   NA   NA
Vref   0.183V   NA   NA
Rref   50.000   NA   NA
[Temperature Range]   25.000   0.125k   -40.000
[Voltage Range]   1.100V   1.060V   1.170V
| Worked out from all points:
|   slope of the pulldown table from 0 to 0.165 V, typ, clamps not added: 38.9 ohm
|   GND clamp passes 1 mA (typ) near -0.30 V on its own axis
|   POWER clamp passes 1 mA (typ) near -0.82 V on its own axis
|   rising waveform, R_fixture 50.000, V_fixture 1.100: 20-80 % time 77.3ps typ, 81.9ps min, 75.1ps max; typ from 0.583 V to 1.1 V
|   rising waveform, R_fixture 50.000, V_fixture 0.0: 20-80 % time 42.4ps typ, 53.3ps min, 33.1ps max; typ from 0 V to 0.226 V
|   falling waveform, R_fixture 50.000, V_fixture 1.100: 20-80 % time 40.7ps typ, 52.2ps min, 30.8ps max; typ from 1.1 V to 0.583 V
|   falling waveform, R_fixture 50.000, V_fixture 0.0: 20-80 % time 47.2ps typ, 60.8ps min, 37.2ps max; typ from 0.226 V to 0 V
[Pulldown]
|Voltage   I(typ)   I(min)   I(max)
-1.1V     -14.46mA   -16mA      -10.98mA
-930mV    -14.07mA   -16.71mA   -10.96mA
-760mV    -14.11mA   -16.25mA   -11.39mA
-590mV    -13.87mA   -14.94mA   -12.09mA
-454mV    -12.33mA   -12.6mA    -11.53mA
-352mV    -9.864mA   -9.937mA   -9.473mA
158mV     4.08mA     4.06mA     4.029mA
328mV     7.567mA    7.574mA    7.575mA
498mV     9.752mA    9.831mA    9.989mA
668mV     10.77mA    10.89mA    11.19mA
974mV     11.68mA    11.84mA    12.17mA
2.2V      13.64mA    13.9mA     14.07mA
[Pullup]
|Voltage   I(typ)   I(min)   I(max)
-1.1V     -58.82pA   10nA       0A
296mV     -3.623uA   -10.49uA   -1.513uA
466mV     -240.8uA   -327.2uA   -168.9uA
568mV     -912.6uA   -1.072mA   -732.2uA
704mV     -2.339mA   -2.602mA   -1.933mA
942mV     -5.457mA   -5.897mA   -4.535mA
1.316V    -10.98mA   -11.58mA   -9.169mA
1.418V    -12.2mA    -12.67mA   -10.4mA
1.486V    -12.54mA   -13.02mA   -10.92mA
1.622V    -12.33mA   -13.1mA    -10.57mA
1.928V    -10.5mA    -12.21mA   -7.835mA
2.2V      -9.524mA   -11.48mA   -6.896mA
[GND_clamp]
|Voltage   I(typ)   I(min)   I(max)
-1.1V     -128.5mA   -147.6mA   -122.6mA
-1.008V   -93.62mA   -112mA     -87.95mA
-962mV    -77.6mA    -95.05mA   -73.96mA
-893mV    -57.36mA   -71.21mA   -60.7mA
-847mV    -48.01mA   -56.81mA   -54.36mA
-801mV    -41.47mA   -44.23mA   -48.33mA
-755mV    -36.02mA   -34.19mA   -42.41mA
-709mV    -30.9mA    -26.94mA   -36.63mA
-525mV    -12.67mA   -10.3mA    -15.49mA
-387mV    -3.615mA   -3.065mA   -4.419mA
-249mV    -281uA     -330.6uA   -301.3uA
1.1V      0A         0A         0A
[POWER_clamp]
|Voltage   I(typ)   I(min)   I(max)
-1.1V     70.27mA    107.3mA    47.25mA
-1.039V   47.68mA    83.93mA    25.86mA
-993mV    31.88mA    66.94mA    12.35mA
-970mV    24.65mA    58.72mA    7.262mA
-947mV    18.06mA    50.74mA    3.761mA
-901mV    7.73mA     35.71mA    987.1uA
-855mV    2.348mA    22.46mA    514uA
-809mV    697.3uA    11.94mA    396.5uA
-763mV    321uA      5.097mA    322.7uA
-717mV    213.8uA    1.813mA    258.1uA
-556mV    65.24uA    79.15uA    81.64uA
1.1V      0A         0A         0A
[Ramp]
| variable   typ   min   max
dV/dt_r   0.136/42.588p   0.132/53.458p   0.136/33.195p
dV/dt_f   0.310/40.833p   0.307/52.654p   0.329/31.014p
R_load = 50.000
[Rising Waveform]
R_fixture= 50.000
V_fixture= 1.100
V_fixture_min= 1.060
V_fixture_max= 1.170
|time   V(typ)   V(min)   V(max)
0s        582.6mV    548.3mV    622.5mV
135ps     584mV      548.8mV    616.9mV
197ps     568.3mV    549.6mV    966.4mV
247ps     831.3mV    531.6mV    1.088V
280ps     952.3mV    529.8mV    1.124V
309ps     1.013V     637.8mV    1.143V
340ps     1.05V      800.4mV    1.155V
374ps     1.071V     916.1mV    1.162V
452ps     1.093V     1.024V     1.168V
1ns       1.1V       1.06V      1.17V
[Rising Waveform]
R_fixture= 50.000
V_fixture= 0.0
V_fixture_min= 0.0
V_fixture_max= 0.0
|time   V(typ)   V(min)   V(max)
0s        1.908uV    15.52uV    357.4nV
138ps     -4.81uV    -26.59uV   11.12mV
157ps     30uV       7.815uV    54.57mV
193ps     5.831mV    -46.33uV   200.6mV
232ps     69.08mV    400.5uV    265mV
268ps     185.3mV    4.662mV    240.7mV
314ps     246.5mV    40.75mV    230.1mV
379ps     233.7mV    193.9mV    227.6mV
455ps     226.2mV    241.3mV    227.3mV
1ns       225.9mV    220.8mV    227.2mV
[Falling Waveform]
R_fixture= 50.000
V_fixture= 1.100
V_fixture_min= 1.060
V_fixture_max= 1.170
|time   V(typ)   V(min)   V(max)
0s        1.1V       1.06V      1.17V
153ps     1.1V       1.06V      1.167V
208ps     1.102V     1.06V      665.6mV
229ps     1.082V     1.06V      556.2mV
246ps     982.5mV    1.059V     526.6mV
297ps     621.4mV    1.063V     588.3mV
342ps     502.6mV    993.7mV    610.8mV
406ps     549.8mV    627.7mV    619.8mV
475ps     575.9mV    493.2mV    621.9mV
1ns       582.6mV    548.3mV    622.4mV
[Falling Waveform]
R_fixture= 50.000
V_fixture= 0.0
V_fixture_min= 0.0
V_fixture_max= 0.0
|time   V(typ)   V(min)   V(max)
0s        225.9mV    220.8mV    227.2mV
123ps     225.2mV    220.6mV    231.3mV
149ps     229.6mV    220mV      177.7mV
182ps     232.1mV    220.2mV    52.82mV
215ps     169mV      225.7mV    10.54mV
251ps     59.13mV    234.2mV    -1.923mV
291ps     9.846mV    190.1mV    -2.453mV
357ps     -1.687mV   46.61mV    -160.2uV
407ps     -2.515mV   6.748mV    -18.15uV
1ns       2.722uV    17.56uV    929.5nV
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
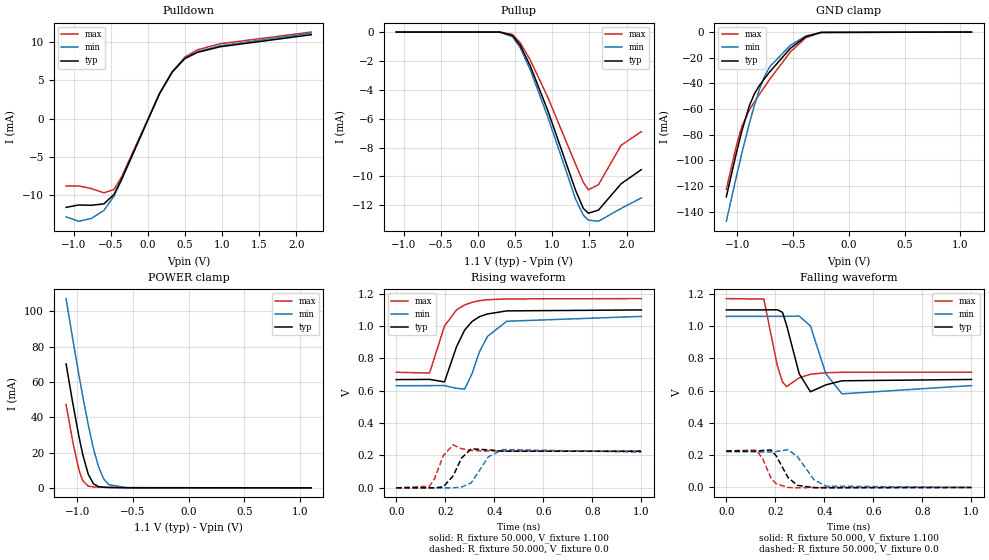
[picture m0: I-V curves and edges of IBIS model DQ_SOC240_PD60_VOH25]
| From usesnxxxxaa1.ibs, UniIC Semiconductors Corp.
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|   Model DQ_SOC240_PD60_VOH25
[Model] DQ_SOC240_PD60_VOH25
Model_type I/O
Polarity   Non-Inverting
Enable   Active-High
Vinl =  0.113V
Vinh =  0.253V
Vmeas =  0.183V
Rref =  50.000
Vref =  0.183V
C_comp   1.110pF   1.087pF   1.118pF
[Model Spec]
Vinh   0.253V   0.247V   0.265V
Vinl   0.113V   0.107V   0.125V
Vmeas   0.183V   NA   NA
Vref   0.183V   NA   NA
Rref   50.000   NA   NA
[Temperature Range]   25.000   0.125k   -40.000
[Voltage Range]   1.100V   1.060V   1.170V
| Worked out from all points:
|   slope of the pulldown table from 0 to 0.165 V, typ, clamps not added: 48.6 ohm
|   GND clamp passes 1 mA (typ) near -0.30 V on its own axis
|   POWER clamp passes 1 mA (typ) near -0.82 V on its own axis
|   rising waveform, R_fixture 50.000, V_fixture 1.100: 20-80 % time 76.9ps typ, 81.3ps min, 75.1ps max; typ from 0.669 V to 1.1 V
|   rising waveform, R_fixture 50.000, V_fixture 0.0: 20-80 % time 43.2ps typ, 54ps min, 33.6ps max; typ from 0 V to 0.226 V
|   falling waveform, R_fixture 50.000, V_fixture 1.100: 20-80 % time 41.3ps typ, 53.7ps min, 31.4ps max; typ from 1.1 V to 0.669 V
|   falling waveform, R_fixture 50.000, V_fixture 0.0: 20-80 % time 49.7ps typ, 62.8ps min, 40.9ps max; typ from 0.226 V to 0 V
[Pulldown]
|Voltage   I(typ)   I(min)   I(max)
-1.1V     -11.56mA   -12.8mA    -8.78mA
-930mV    -11.25mA   -13.37mA   -8.769mA
-760mV    -11.29mA   -13mA      -9.11mA
-590mV    -11.1mA    -11.95mA   -9.675mA
-454mV    -9.865mA   -10.08mA   -9.225mA
-352mV    -7.891mA   -7.949mA   -7.578mA
158mV     3.264mA    3.248mA    3.223mA
328mV     6.054mA    6.059mA    6.06mA
498mV     7.801mA    7.865mA    7.991mA
668mV     8.612mA    8.711mA    8.95mA
974mV     9.345mA    9.47mA     9.737mA
2.2V      10.91mA    11.12mA    11.26mA
[Pullup]
|Voltage   I(typ)   I(min)   I(max)
-1.1V     -58.82pA   10nA       0A
296mV     -3.623uA   -10.49uA   -1.513uA
466mV     -240.8uA   -327.2uA   -168.9uA
568mV     -912.6uA   -1.072mA   -732.2uA
704mV     -2.339mA   -2.602mA   -1.933mA
942mV     -5.457mA   -5.897mA   -4.535mA
1.316V    -10.98mA   -11.58mA   -9.169mA
1.418V    -12.2mA    -12.67mA   -10.4mA
1.486V    -12.54mA   -13.02mA   -10.92mA
1.622V    -12.33mA   -13.1mA    -10.57mA
1.928V    -10.5mA    -12.21mA   -7.835mA
2.2V      -9.524mA   -11.48mA   -6.896mA
[GND_clamp]
|Voltage   I(typ)   I(min)   I(max)
-1.1V     -128.5mA   -147.6mA   -122.6mA
-1.008V   -93.62mA   -112mA     -87.95mA
-962mV    -77.6mA    -95.05mA   -73.96mA
-893mV    -57.36mA   -71.21mA   -60.7mA
-847mV    -48.01mA   -56.81mA   -54.36mA
-801mV    -41.47mA   -44.23mA   -48.33mA
-755mV    -36.02mA   -34.19mA   -42.41mA
-709mV    -30.9mA    -26.94mA   -36.63mA
-525mV    -12.67mA   -10.3mA    -15.49mA
-387mV    -3.615mA   -3.065mA   -4.419mA
-249mV    -281uA     -330.6uA   -301.3uA
1.1V      0A         0A         0A
[POWER_clamp]
|Voltage   I(typ)   I(min)   I(max)
-1.1V     70.27mA    107.3mA    47.25mA
-1.039V   47.68mA    83.93mA    25.86mA
-993mV    31.88mA    66.94mA    12.35mA
-970mV    24.65mA    58.72mA    7.262mA
-947mV    18.06mA    50.74mA    3.761mA
-901mV    7.73mA     35.71mA    987.1uA
-855mV    2.348mA    22.46mA    514uA
-809mV    697.3uA    11.94mA    396.5uA
-763mV    321uA      5.097mA    322.7uA
-717mV    213.8uA    1.813mA    258.1uA
-556mV    65.24uA    79.15uA    81.64uA
1.1V      0A         0A         0A
[Ramp]
| variable   typ   min   max
dV/dt_r   0.136/43.515p   0.132/54.570p   0.136/33.826p
dV/dt_f   0.258/41.562p   0.257/54.158p   0.273/31.541p
R_load = 50.000
[Rising Waveform]
R_fixture= 50.000
V_fixture= 1.100
V_fixture_min= 1.060
V_fixture_max= 1.170
|time   V(typ)   V(min)   V(max)
0s        669.2mV    631.2mV    714.4mV
136ps     670.4mV    631.8mV    709.8mV
197ps     655mV      632.4mV    1.001V
246ps     872.1mV    615.1mV    1.1V
279ps     974.8mV    610mV      1.131V
309ps     1.028V     704.4mV    1.147V
339ps     1.058V     839.3mV    1.157V
372ps     1.075V     935.8mV    1.163V
451ps     1.094V     1.03V      1.168V
1ns       1.1V       1.06V      1.17V
[Rising Waveform]
R_fixture= 50.000
V_fixture= 0.0
V_fixture_min= 0.0
V_fixture_max= 0.0
|time   V(typ)   V(min)   V(max)
0s        2.16uV     17.56uV    404.1nV
136ps     -40.17uV   -8.72uV    10.07mV
156ps     -110.6uV   22.85uV    54.72mV
192ps     5.984mV    -86.46uV   199.1mV
232ps     73.39mV    188uV      265.4mV
267ps     184.8mV    4.92mV     241.4mV
306ps     240.9mV    30.85mV    230.9mV
376ps     234.9mV    191.7mV    227.6mV
435ps     226.5mV    236.5mV    227.3mV
1ns       225.9mV    220.8mV    227.2mV
[Falling Waveform]
R_fixture= 50.000
V_fixture= 1.100
V_fixture_min= 1.060
V_fixture_max= 1.170
|time   V(typ)   V(min)   V(max)
0s        1.1V       1.06V      1.17V
153ps     1.1V       1.06V      1.167V
208ps     1.101V     1.06V      754.8mV
229ps     1.085V     1.06V      654.1mV
246ps     1.004V     1.06V      625.1mV
297ps     705.4mV    1.062V     679.1mV
343ps     592.9mV    1.001V     701.4mV
406ps     635.6mV    703.8mV    711mV
472ps     660.9mV    580mV      713.6mV
1ns       669.2mV    631.2mV    714.4mV
[Falling Waveform]
R_fixture= 50.000
V_fixture= 0.0
V_fixture_min= 0.0
V_fixture_max= 0.0
|time   V(typ)   V(min)   V(max)
0s        225.9mV    220.8mV    227.2mV
123ps     225.1mV    220.6mV    231.4mV
149ps     229.6mV    220mV      176.4mV
182ps     232.2mV    220.2mV    58.81mV
203ps     196.7mV    222.9mV    23.59mV
252ps     60.78mV    234.5mV    -281.3uV
290ps     13.38mV    190.9mV    -1.889mV
358ps     -1.027mV   46.85mV    -158.2uV
407ps     -2.15mV    8.464mV    -23.41uV
1ns       3.098uV    19.79uV    2.009uV
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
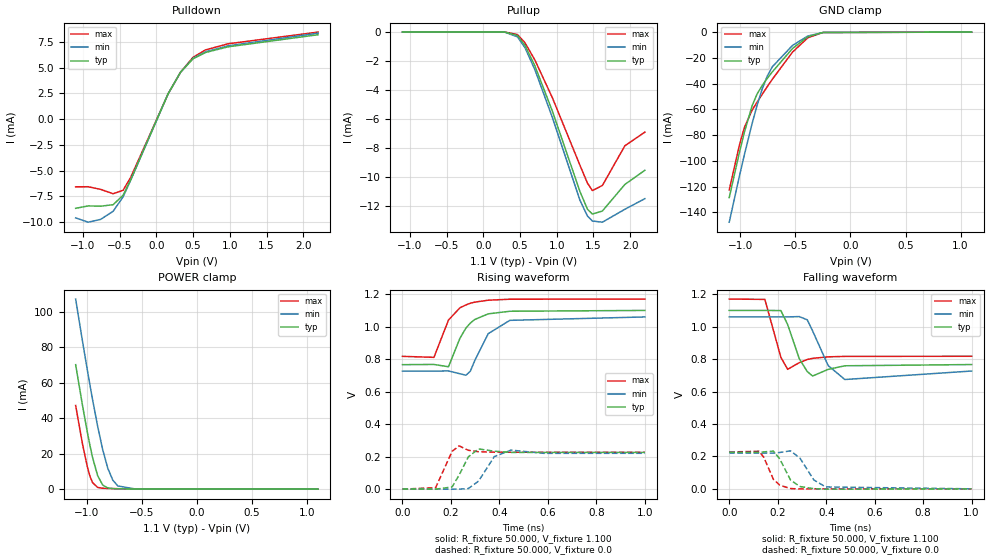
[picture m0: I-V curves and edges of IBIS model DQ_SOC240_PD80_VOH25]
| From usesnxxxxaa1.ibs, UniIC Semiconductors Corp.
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|   Model DQ_SOC240_PD80_VOH25
[Model] DQ_SOC240_PD80_VOH25
Model_type I/O
Polarity   Non-Inverting
Enable   Active-High
Vinl =  0.113V
Vinh =  0.253V
Vmeas =  0.183V
Rref =  50.000
Vref =  0.183V
C_comp   1.110pF   1.087pF   1.118pF
[Model Spec]
Vinh   0.253V   0.247V   0.265V
Vinl   0.113V   0.107V   0.125V
Vmeas   0.183V   NA   NA
Vref   0.183V   NA   NA
Rref   50.000   NA   NA
[Temperature Range]   25.000   0.125k   -40.000
[Voltage Range]   1.100V   1.060V   1.170V
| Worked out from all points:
|   slope of the pulldown table from 0 to 0.165 V, typ, clamps not added: 64.8 ohm
|   GND clamp passes 1 mA (typ) near -0.30 V on its own axis
|   POWER clamp passes 1 mA (typ) near -0.82 V on its own axis
|   rising waveform, R_fixture 50.000, V_fixture 1.100: 20-80 % time 75.8ps typ, 79.7ps min, 74.1ps max; typ from 0.766 V to 1.1 V
|   rising waveform, R_fixture 50.000, V_fixture 0.0: 20-80 % time 42.8ps typ, 52.5ps min, 33.2ps max; typ from 0 V to 0.226 V
|   falling waveform, R_fixture 50.000, V_fixture 1.100: 20-80 % time 43.4ps typ, 55.8ps min, 32.9ps max; typ from 1.1 V to 0.766 V
|   falling waveform, R_fixture 50.000, V_fixture 0.0: 20-80 % time 48.6ps typ, 58.7ps min, 42.7ps max; typ from 0.226 V to 0 V
[Pulldown]
|Voltage   I(typ)   I(min)   I(max)
-1.1V     -8.673mA   -9.601mA   -6.585mA
-930mV    -8.439mA   -10.02mA   -6.577mA
-760mV    -8.467mA   -9.748mA   -6.832mA
-590mV    -8.322mA   -8.962mA   -7.256mA
-454mV    -7.399mA   -7.561mA   -6.919mA
-352mV    -5.919mA   -5.962mA   -5.684mA
158mV     2.448mA    2.436mA    2.417mA
328mV     4.54mA     4.545mA    4.545mA
498mV     5.851mA    5.899mA    5.993mA
668mV     6.459mA    6.534mA    6.712mA
974mV     7.009mA    7.103mA    7.302mA
2.2V      8.186mA    8.338mA    8.442mA
[Pullup]
|Voltage   I(typ)   I(min)   I(max)
-1.1V     -58.82pA   10nA       0A
296mV     -3.623uA   -10.49uA   -1.513uA
466mV     -240.8uA   -327.2uA   -168.9uA
568mV     -912.6uA   -1.072mA   -732.2uA
704mV     -2.339mA   -2.602mA   -1.933mA
942mV     -5.457mA   -5.897mA   -4.535mA
1.316V    -10.98mA   -11.58mA   -9.169mA
1.418V    -12.2mA    -12.67mA   -10.4mA
1.486V    -12.54mA   -13.02mA   -10.92mA
1.622V    -12.33mA   -13.1mA    -10.57mA
1.928V    -10.5mA    -12.21mA   -7.835mA
2.2V      -9.524mA   -11.48mA   -6.896mA
[GND_clamp]
|Voltage   I(typ)   I(min)   I(max)
-1.1V     -128.5mA   -147.6mA   -122.6mA
-1.008V   -93.62mA   -112mA     -87.95mA
-962mV    -77.6mA    -95.05mA   -73.96mA
-893mV    -57.36mA   -71.21mA   -60.7mA
-847mV    -48.01mA   -56.81mA   -54.36mA
-801mV    -41.47mA   -44.23mA   -48.33mA
-755mV    -36.02mA   -34.19mA   -42.41mA
-709mV    -30.9mA    -26.94mA   -36.63mA
-525mV    -12.67mA   -10.3mA    -15.49mA
-387mV    -3.615mA   -3.065mA   -4.419mA
-249mV    -281uA     -330.6uA   -301.3uA
1.1V      0A         0A         0A
[POWER_clamp]
|Voltage   I(typ)   I(min)   I(max)
-1.1V     70.27mA    107.3mA    47.25mA
-1.039V   47.68mA    83.93mA    25.86mA
-993mV    31.88mA    66.94mA    12.35mA
-970mV    24.65mA    58.72mA    7.262mA
-947mV    18.06mA    50.74mA    3.761mA
-901mV    7.73mA     35.71mA    987.1uA
-855mV    2.348mA    22.46mA    514uA
-809mV    697.3uA    11.94mA    396.5uA
-763mV    321uA      5.097mA    322.7uA
-717mV    213.8uA    1.813mA    258.1uA
-556mV    65.24uA    79.15uA    81.64uA
1.1V      0A         0A         0A
[Ramp]
| variable   typ   min   max
dV/dt_r   0.136/42.887p   0.132/52.956p   0.136/33.395p
dV/dt_f   0.200/43.869p   0.200/56.705p   0.212/33.001p
R_load = 50.000
[Rising Waveform]
R_fixture= 50.000
V_fixture= 1.100
V_fixture_min= 1.060
V_fixture_max= 1.170
|time   V(typ)   V(min)   V(max)
0s        766.3mV    726.4mV    817.4mV
130ps     767.6mV    726.8mV    811.3mV
190ps     753.3mV    727.5mV    1.041V
237ps     928.1mV    710.4mV    1.116V
262ps     991.8mV    701.2mV    1.134V
280ps     1.022V     725.7mV    1.144V
298ps     1.044V     790.4mV    1.151V
354ps     1.079V     957.1mV    1.163V
443ps     1.095V     1.039V     1.169V
1ns       1.1V       1.06V      1.17V
[Rising Waveform]
R_fixture= 50.000
V_fixture= 0.0
V_fixture_min= 0.0
V_fixture_max= 0.0
|time   V(typ)   V(min)   V(max)
0s        2.487uV    20.21uV    464.7nV
137ps     18.88uV    4.888uV    9.34mV
205ps     13.56mV    -21.99uV   233.3mV
234ps     87.52mV    330.9uV    266.3mV
272ps     199mV      3.865mV    239.1mV
314ps     247.6mV    49.39mV    230.2mV
379ps     233.7mV    200.4mV    227.6mV
448ps     226.3mV    240.4mV    227.3mV
583ps     225.9mV    220.5mV    227.2mV
1ns       225.9mV    220.8mV    227.2mV
[Falling Waveform]
R_fixture= 50.000
V_fixture= 1.100
V_fixture_min= 1.060
V_fixture_max= 1.170
|time   V(typ)   V(min)   V(max)
0s        1.1V       1.06V      1.17V
147ps     1.1V       1.06V      1.168V
213ps     1.099V     1.06V      811mV
241ps     1.013V     1.06V      736.8mV
289ps     802.4mV    1.062V     777.9mV
322ps     722.7mV    1.042V     797.4mV
344ps     695.6mV    973.7mV    804.6mV
408ps     736.5mV    760.2mV    813.8mV
477ps     758.7mV    674mV      816.5mV
1ns       766.3mV    726.4mV    817.4mV
[Falling Waveform]
R_fixture= 50.000
V_fixture= 0.0
V_fixture_min= 0.0
V_fixture_max= 0.0
|time   V(typ)   V(min)   V(max)
0s        225.9mV    220.8mV    227.2mV
123ps     225.1mV    220.6mV    231.8mV
143ps     227.9mV    220.1mV    193.3mV
182ps     232.7mV    220.2mV    58.97mV
209ps     183.1mV    224.3mV    22.08mV
253ps     53.87mV    234.3mV    1.836mV
292ps     14.15mV    188.9mV    -779.7uV
349ps     1.061mV    54.78mV    -118.3uV
398ps     -1.978mV   11.66mV    -22.01uV
1ns       3.586uV    22.72uV    2.401uV
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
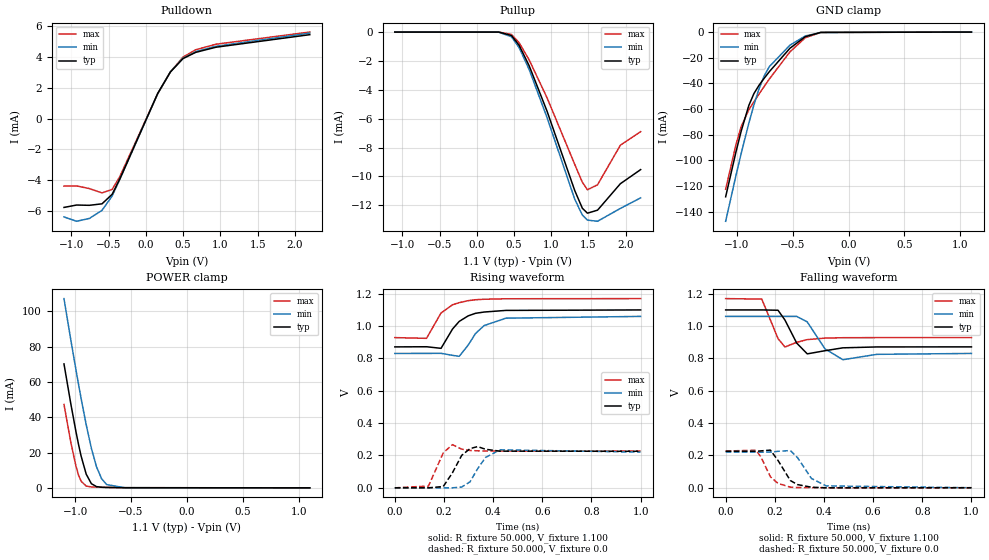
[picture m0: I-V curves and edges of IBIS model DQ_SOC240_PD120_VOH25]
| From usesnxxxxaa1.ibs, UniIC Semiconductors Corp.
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|   Model DQ_SOC240_PD120_VOH25
[Model] DQ_SOC240_PD120_VOH25
Model_type I/O
Polarity   Non-Inverting
Enable   Active-High
Vinl =  0.113V
Vinh =  0.253V
Vmeas =  0.183V
Rref =  50.000
Vref =  0.183V
C_comp   1.110pF   1.087pF   1.118pF
[Model Spec]
Vinh   0.253V   0.247V   0.265V
Vinl   0.113V   0.107V   0.125V
Vmeas   0.183V   NA   NA
Vref   0.183V   NA   NA
Rref   50.000   NA   NA
[Temperature Range]   25.000   0.125k   -40.000
[Voltage Range]   1.100V   1.060V   1.170V
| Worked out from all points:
|   slope of the pulldown table from 0 to 0.165 V, typ, clamps not added: 97.2 ohm
|   GND clamp passes 1 mA (typ) near -0.30 V on its own axis
|   POWER clamp passes 1 mA (typ) near -0.82 V on its own axis
|   rising waveform, R_fixture 50.000, V_fixture 1.100: 20-80 % time 75.2ps typ, 78.5ps min, 73.5ps max; typ from 0.871 V to 1.1 V
|   rising waveform, R_fixture 50.000, V_fixture 0.0: 20-80 % time 43.6ps typ, 53.7ps min, 33.8ps max; typ from 0 V to 0.226 V
|   falling waveform, R_fixture 50.000, V_fixture 1.100: 20-80 % time 43.9ps typ, 57ps min, 33.1ps max; typ from 1.1 V to 0.871 V
|   falling waveform, R_fixture 50.000, V_fixture 0.0: 20-80 % time 53.6ps typ, 62.1ps min, 49ps max; typ from 0.226 V to 0 V
[Pulldown]
|Voltage   I(typ)   I(min)   I(max)
-1.1V     -5.782mA   -6.401mA   -4.39mA
-930mV    -5.626mA   -6.683mA   -4.384mA
-760mV    -5.645mA   -6.499mA   -4.555mA
-590mV    -5.548mA   -5.975mA   -4.837mA
-454mV    -4.933mA   -5.041mA   -4.613mA
-352mV    -3.946mA   -3.975mA   -3.789mA
158mV     1.632mA    1.624mA    1.612mA
328mV     3.027mA    3.03mA     3.03mA
498mV     3.901mA    3.932mA    3.996mA
668mV     4.306mA    4.356mA    4.475mA
940mV     4.641mA    4.702mA    4.836mA
2.2V      5.457mA    5.559mA    5.628mA
[Pullup]
|Voltage   I(typ)   I(min)   I(max)
-1.1V     -58.82pA   10.06nA    0A
296mV     -3.623uA   -10.49uA   -1.513uA
466mV     -240.8uA   -327.2uA   -168.9uA
568mV     -912.6uA   -1.072mA   -732.2uA
704mV     -2.339mA   -2.602mA   -1.933mA
942mV     -5.457mA   -5.897mA   -4.535mA
1.316V    -10.98mA   -11.58mA   -9.169mA
1.418V    -12.2mA    -12.67mA   -10.4mA
1.486V    -12.54mA   -13.02mA   -10.92mA
1.622V    -12.33mA   -13.1mA    -10.57mA
1.928V    -10.5mA    -12.21mA   -7.835mA
2.2V      -9.524mA   -11.48mA   -6.896mA
[GND_clamp]
|Voltage   I(typ)   I(min)   I(max)
-1.1V     -128.5mA   -147.6mA   -122.6mA
-1.008V   -93.62mA   -112mA     -87.95mA
-962mV    -77.6mA    -95.05mA   -73.96mA
-893mV    -57.36mA   -71.21mA   -60.7mA
-847mV    -48.01mA   -56.81mA   -54.36mA
-801mV    -41.47mA   -44.23mA   -48.33mA
-755mV    -36.02mA   -34.19mA   -42.41mA
-709mV    -30.9mA    -26.94mA   -36.63mA
-525mV    -12.67mA   -10.3mA    -15.49mA
-387mV    -3.615mA   -3.065mA   -4.419mA
-249mV    -281uA     -330.6uA   -301.3uA
1.1V      0A         0A         0A
[POWER_clamp]
|Voltage   I(typ)   I(min)   I(max)
-1.1V     70.27mA    107.3mA    47.25mA
-1.039V   47.68mA    83.93mA    25.86mA
-993mV    31.88mA    66.94mA    12.35mA
-970mV    24.65mA    58.72mA    7.262mA
-947mV    18.06mA    50.74mA    3.761mA
-901mV    7.73mA     35.71mA    987.1uA
-855mV    2.348mA    22.46mA    514uA
-809mV    697.3uA    11.94mA    396.5uA
-763mV    321uA      5.097mA    322.7uA
-717mV    213.8uA    1.813mA    258.1uA
-556mV    65.24uA    79.15uA    81.64uA
1.1V      0A         0A         0A
[Ramp]
| variable   typ   min   max
dV/dt_r   0.136/43.660p   0.132/53.887p   0.136/33.873p
dV/dt_f   0.137/44.278p   0.138/57.380p   0.145/33.316p
R_load = 50.000
[Rising Waveform]
R_fixture= 50.000
V_fixture= 1.100
V_fixture_min= 1.060
V_fixture_max= 1.170
|time   V(typ)   V(min)   V(max)
0s        871.4mV    830.8mV    928.8mV
129ps     872.3mV    831.1mV    924.3mV
188ps     862.5mV    831.6mV    1.081V
235ps     982.4mV    819.1mV    1.132V
262ps     1.029V     813.2mV    1.145V
298ps     1.063V     881.6mV    1.157V
328ps     1.079V     953.5mV    1.163V
363ps     1.087V     1.003V     1.166V
452ps     1.097V     1.049V     1.169V
1ns       1.1V       1.06V      1.17V
[Rising Waveform]
R_fixture= 50.000
V_fixture= 0.0
V_fixture_min= 0.0
V_fixture_max= 0.0
|time   V(typ)   V(min)   V(max)
0s        2.932uV    23.8uV     546.7nV
137ps     -36.9uV    31.54uV    11.12mV
197ps     8.009mV    -92.89uV   216.2mV
234ps     91.93mV    32.37uV    266.8mV
272ps     200.5mV    4.737mV    239.1mV
306ps     242.4mV    37.27mV    231.1mV
337ps     254.9mV    118mV      228.6mV
369ps     238.3mV    187.8mV    227.8mV
428ps     226.7mV    235mV      227.3mV
1ns       225.9mV    220.8mV    227.2mV
[Falling Waveform]
R_fixture= 50.000
V_fixture= 1.100
V_fixture_min= 1.060
V_fixture_max= 1.170
|time   V(typ)   V(min)   V(max)
0s        1.1V       1.06V      1.17V
147ps     1.1V       1.06V      1.167V
213ps     1.098V     1.06V      923mV
241ps     1.038V     1.06V      870.4mV
289ps     895mV      1.06V      899.6mV
332ps     828.1mV    1.026V     916.3mV
404ps     847.6mV    859.1mV    925.7mV
477ps     865.5mV    791.9mV    928mV
615ps     871mV      825.2mV    928.7mV
1ns       871.4mV    830.8mV    928.8mV
[Falling Waveform]
R_fixture= 50.000
V_fixture= 0.0
V_fixture_min= 0.0
V_fixture_max= 0.0
|time   V(typ)   V(min)   V(max)
0s        225.9mV    220.8mV    227.2mV
123ps     225.1mV    220.6mV    231.9mV
143ps     227.9mV    220.1mV    191.8mV
182ps     232.8mV    220.2mV    67.78mV
213ps     169mV      225.3mV    26.64mV
263ps     44.75mV    230.1mV    3.675mV
292ps     19.59mV    187mV      1.293mV
349ps     3.225mV    57.31mV    310.1uV
409ps     -605.8uV   11.33mV    71.48uV
1ns       4.287uV    26.71uV    2.739uV
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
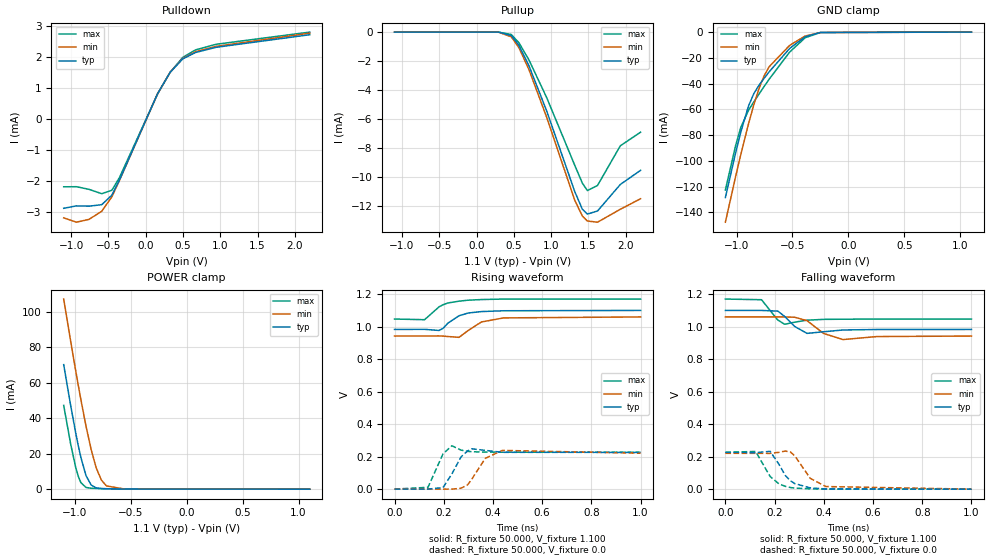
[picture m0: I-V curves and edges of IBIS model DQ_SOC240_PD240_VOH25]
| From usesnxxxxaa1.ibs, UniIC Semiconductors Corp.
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|   Model DQ_SOC240_PD240_VOH25
[Model] DQ_SOC240_PD240_VOH25
Model_type I/O
Polarity   Non-Inverting
Enable   Active-High
Vinl =  0.113V
Vinh =  0.253V
Vmeas =  0.183V
Rref =  50.000
Vref =  0.183V
C_comp   1.110pF   1.087pF   1.118pF
[Model Spec]
Vinh   0.253V   0.247V   0.265V
Vinl   0.113V   0.107V   0.125V
Vmeas   0.183V   NA   NA
Vref   0.183V   NA   NA
Rref   50.000   NA   NA
[Temperature Range]   25.000   0.125k   -40.000
[Voltage Range]   1.100V   1.060V   1.170V
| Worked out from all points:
|   slope of the pulldown table from 0 to 0.165 V, typ, clamps not added: 194 ohm
|   GND clamp passes 1 mA (typ) near -0.30 V on its own axis
|   POWER clamp passes 1 mA (typ) near -0.82 V on its own axis
|   rising waveform, R_fixture 50.000, V_fixture 1.100: 20-80 % time 72.8ps typ, 75.9ps min, 71.7ps max; typ from 0.983 V to 1.1 V
|   rising waveform, R_fixture 50.000, V_fixture 0.0: 20-80 % time 44.5ps typ, 54.9ps min, 34.4ps max; typ from 0 V to 0.226 V
|   falling waveform, R_fixture 50.000, V_fixture 1.100: 20-80 % time 45ps typ, 58.4ps min, 33.7ps max; typ from 1.1 V to 0.983 V
|   falling waveform, R_fixture 50.000, V_fixture 0.0: 20-80 % time 61.7ps typ, 67.3ps min, 58.9ps max; typ from 0.226 V to 0 V
[Pulldown]
|Voltage   I(typ)   I(min)   I(max)
-1.1V     -2.891mA   -3.2mA     -2.195mA
-930mV    -2.813mA   -3.341mA   -2.192mA
-760mV    -2.822mA   -3.249mA   -2.278mA
-590mV    -2.774mA   -2.987mA   -2.419mA
-454mV    -2.466mA   -2.52mA    -2.306mA
-352mV    -1.973mA   -1.987mA   -1.895mA
158mV     816.1uA    812uA      805.8uA
328mV     1.513mA    1.515mA    1.515mA
498mV     1.95mA     1.966mA    1.998mA
668mV     2.153mA    2.178mA    2.237mA
940mV     2.32mA     2.351mA    2.418mA
2.2V      2.729mA    2.779mA    2.814mA
[Pullup]
|Voltage   I(typ)   I(min)   I(max)
-1.1V     -58.82pA   10nA       0A
296mV     -3.623uA   -10.49uA   -1.513uA
466mV     -240.8uA   -327.2uA   -168.9uA
568mV     -912.6uA   -1.072mA   -732.2uA
704mV     -2.339mA   -2.602mA   -1.933mA
942mV     -5.457mA   -5.897mA   -4.535mA
1.316V    -10.98mA   -11.58mA   -9.169mA
1.418V    -12.2mA    -12.67mA   -10.4mA
1.486V    -12.54mA   -13.02mA   -10.92mA
1.622V    -12.33mA   -13.1mA    -10.57mA
1.928V    -10.5mA    -12.21mA   -7.835mA
2.2V      -9.524mA   -11.48mA   -6.896mA
[GND_clamp]
|Voltage   I(typ)   I(min)   I(max)
-1.1V     -128.5mA   -147.6mA   -122.6mA
-1.008V   -93.62mA   -112mA     -87.95mA
-962mV    -77.6mA    -95.05mA   -73.96mA
-893mV    -57.36mA   -71.21mA   -60.7mA
-847mV    -48.01mA   -56.81mA   -54.36mA
-801mV    -41.47mA   -44.23mA   -48.33mA
-755mV    -36.02mA   -34.19mA   -42.41mA
-709mV    -30.9mA    -26.94mA   -36.63mA
-525mV    -12.67mA   -10.3mA    -15.49mA
-387mV    -3.615mA   -3.065mA   -4.419mA
-249mV    -281uA     -330.6uA   -301.3uA
1.1V      0A         0A         0A
[POWER_clamp]
|Voltage   I(typ)   I(min)   I(max)
-1.1V     70.27mA    107.3mA    47.25mA
-1.039V   47.68mA    83.93mA    25.86mA
-993mV    31.88mA    66.94mA    12.35mA
-970mV    24.65mA    58.72mA    7.262mA
-947mV    18.06mA    50.74mA    3.761mA
-901mV    7.73mA     35.71mA    987.1uA
-855mV    2.348mA    22.46mA    514uA
-809mV    697.3uA    11.94mA    396.5uA
-763mV    321uA      5.097mA    322.7uA
-717mV    213.8uA    1.813mA    258.1uA
-556mV    65.24uA    79.15uA    81.64uA
1.1V      0A         0A         0A
[Ramp]
| variable   typ   min   max
dV/dt_r   0.136/44.704p   0.132/55.163p   0.136/34.554p
dV/dt_f   70.211m/45.268p   70.570m/58.516p   73.998m/33.998p
R_load = 50.000
[Rising Waveform]
R_fixture= 50.000
V_fixture= 1.100
V_fixture_min= 1.060
V_fixture_max= 1.170
|time   V(typ)   V(min)   V(max)
0s        983mV      942.4mV    1.047V
122ps     983.6mV    942.5mV    1.043V
181ps     976.7mV    943mV      1.122V
197ps     989.5mV    942.1mV    1.135V
217ps     1.022V     939.4mV    1.146V
262ps     1.067V     934.3mV    1.157V
299ps     1.084V     976.2mV    1.163V
353ps     1.093V     1.029V     1.167V
443ps     1.098V     1.054V     1.17V
1ns       1.1V       1.06V      1.17V
[Rising Waveform]
R_fixture= 50.000
V_fixture= 0.0
V_fixture_min= 0.0
V_fixture_max= 0.0
|time   V(typ)   V(min)   V(max)
0s        3.571uV    28.95uV    664nV
136ps     -89.14uV   60.12uV    11.14mV
197ps     9.582mV    -197.3uV   217.2mV
233ps     93.01mV    -386.8uV   266.8mV
270ps     198.1mV    5.362mV    240.2mV
297ps     235.1mV    26.23mV    232.4mV
314ps     248.2mV    61.39mV    230.2mV
369ps     238.4mV    189.7mV    227.8mV
438ps     226.5mV    238.2mV    227.3mV
1ns       225.9mV    220.8mV    227.2mV
[Falling Waveform]
R_fixture= 50.000
V_fixture= 1.100
V_fixture_min= 1.060
V_fixture_max= 1.170
|time   V(typ)   V(min)   V(max)
0s        1.1V       1.06V      1.17V
147ps     1.1V       1.06V      1.166V
213ps     1.096V     1.06V      1.041V
241ps     1.063V     1.06V      1.015V
282ps     1.001V     1.058V     1.028V
332ps     958.8mV    1.037V     1.04V
399ps     968.8mV    958.4mV    1.045V
478ps     979.7mV    920.7mV    1.046V
616ps     982.7mV    939.3mV    1.047V
1ns       983mV      942.4mV    1.047V
[Falling Waveform]
R_fixture= 50.000
V_fixture= 0.0
V_fixture_min= 0.0
V_fixture_max= 0.0
|time   V(typ)   V(min)   V(max)
0s        225.9mV    220.8mV    227.2mV
123ps     225.1mV    220.6mV    232mV
182ps     232.8mV    220.2mV    77.87mV
217ps     154.9mV    226.6mV    33.52mV
243ps     85.47mV    234.4mV    17.64mV
264ps     51.73mV    229.1mV    10.03mV
282ps     34.2mV     205.4mV    6.597mV
345ps     8.012mV    66.46mV    1.723mV
408ps     1.308mV    16.15mV    467.1uV
1ns       5.247uV    32.35uV    3.358uV
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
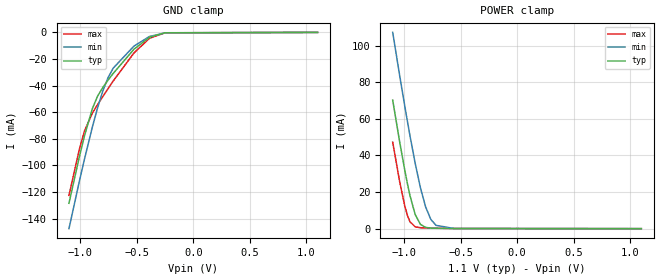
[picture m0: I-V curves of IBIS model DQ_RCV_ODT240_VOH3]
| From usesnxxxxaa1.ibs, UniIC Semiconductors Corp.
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|   Model DQ_RCV_ODT240_VOH3
[Model] DQ_RCV_ODT240_VOH3
Model_type Input
Polarity   Non-Inverting
Vinl =  0.113V
Vinh =  0.253V
C_comp   1.110pF   1.087pF   1.118pF
[Model Spec]
Vinh   0.253V   0.247V   0.265V
Vinl   0.113V   0.107V   0.125V
[Add Submodel]
|  Submodel_name   Mode
ODT240_VOH3   Non-Driving
[Temperature Range]   25.000   0.125k   -40.000
[Voltage Range]   1.100V   1.060V   1.170V
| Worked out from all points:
|   GND clamp passes 1 mA (typ) near -0.30 V on its own axis
|   POWER clamp passes 1 mA (typ) near -0.82 V on its own axis
[GND_clamp]
|Voltage   I(typ)   I(min)   I(max)
-1.1V     -128.5mA   -147.6mA   -122.6mA
-1.008V   -93.62mA   -112mA     -87.95mA
-962mV    -77.6mA    -95.05mA   -73.96mA
-893mV    -57.36mA   -71.21mA   -60.7mA
-847mV    -48.01mA   -56.81mA   -54.36mA
-801mV    -41.47mA   -44.23mA   -48.33mA
-755mV    -36.02mA   -34.19mA   -42.41mA
-709mV    -30.9mA    -26.94mA   -36.63mA
-525mV    -12.67mA   -10.3mA    -15.49mA
-387mV    -3.615mA   -3.065mA   -4.419mA
-249mV    -281uA     -330.6uA   -301.3uA
1.1V      0A         0A         0A
[POWER_clamp]
|Voltage   I(typ)   I(min)   I(max)
-1.1V     70.27mA    107.3mA    47.25mA
-1.039V   47.68mA    83.93mA    25.86mA
-993mV    31.88mA    66.94mA    12.35mA
-970mV    24.65mA    58.72mA    7.262mA
-947mV    18.06mA    50.74mA    3.761mA
-901mV    7.73mA     35.71mA    987.1uA
-855mV    2.348mA    22.46mA    514uA
-809mV    697.3uA    11.94mA    396.5uA
-763mV    321uA      5.097mA    322.7uA
-717mV    213.8uA    1.813mA    258.1uA
-556mV    65.24uA    79.15uA    81.64uA
1.1V      0A         0A         0A
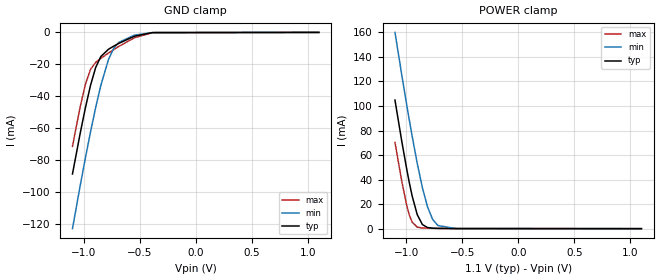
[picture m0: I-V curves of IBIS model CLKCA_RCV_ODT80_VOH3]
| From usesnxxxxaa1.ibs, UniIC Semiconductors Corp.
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|   Model CLKCA_RCV_ODT80_VOH3
[Model] CLKCA_RCV_ODT80_VOH3
Model_type Input
Polarity   Non-Inverting
Vinl =  0.113V
Vinh =  0.253V
C_comp   0.852pF   0.835pF   0.861pF
[Model Spec]
Vinh   0.253V   0.247V   0.265V
Vinl   0.113V   0.107V   0.125V
[Add Submodel]
|  Submodel_name   Mode
ODT80_VOH3   Non-Driving
[Temperature Range]   25.000   0.125k   -40.000
[Voltage Range]   1.100V   1.060V   1.170V
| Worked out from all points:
|   GND clamp passes 1 mA (typ) near -0.48 V on its own axis
|   POWER clamp passes 1 mA (typ) near -0.81 V on its own axis
[GND_clamp]
|Voltage   I(typ)   I(min)   I(max)
-1.1V     -88.79mA   -123.1mA   -71.48mA
-1.031V   -63.25mA   -96.13mA   -46.59mA
-985mV    -47.4mA    -78.91mA   -32.65mA
-939mV    -33.23mA   -62.49mA   -23.22mA
-893mV    -22.03mA   -47.12mA   -18.8mA
-847mV    -15.14mA   -33.24mA   -16.26mA
-778mV    -10.55mA   -16.86mA   -12.94mA
-732mV    -8.616mA   -10.04mA   -10.83mA
-686mV    -6.865mA   -6.259mA   -8.795mA
-548mV    -2.421mA   -1.734mA   -3.398mA
-387mV    -126.8uA   -122.3uA   -186.4uA
1.1V      0A         0A         0A
[POWER_clamp]
|Voltage   I(typ)   I(min)   I(max)
-1.1V     104.8mA    160mA      70.36mA
-1.039V   71.02mA    125.1mA    38.37mA
-993mV    47.41mA    99.76mA    18.16mA
-970mV    36.61mA    87.48mA    10.56mA
-947mV    26.77mA    75.56mA    5.326mA
-901mV    11.35mA    53.11mA    1.208mA
-855mV    3.329mA    33.33mA    538.3uA
-809mV    890.1uA    17.63mA    399uA
-763mV    354.9uA    7.445mA    322.9uA
-717mV    219.7uA    2.583mA    258.1uA
-556mV    65.25uA    87.5uA     81.64uA
1.1V      0A         0A         1.291pA
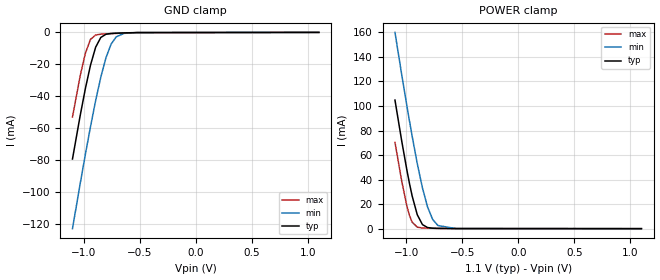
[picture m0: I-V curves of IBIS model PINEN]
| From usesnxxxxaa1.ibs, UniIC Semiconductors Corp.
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|   Model PINEN
[Model] PINEN
Model_type Input
Polarity   Non-Inverting
Vinl =  0.113V
Vinh =  0.253V
C_comp   0.756pF   0.737pF   0.762pF
[Model Spec]
Vinh   0.253V   0.247V   0.265V
Vinl   0.113V   0.107V   0.125V
[Temperature Range]   25.000   0.125k   -40.000
[Voltage Range]   1.100V   1.060V   1.170V
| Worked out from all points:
|   GND clamp passes 1 mA (typ) near -0.79 V on its own axis
|   POWER clamp passes 1 mA (typ) near -0.81 V on its own axis
[GND_clamp]
|Voltage   I(typ)   I(min)   I(max)
-1.1V     -79.42mA   -123.1mA   -53.09mA
-1.031V   -52.1mA    -94.8mA    -27.19mA
-985mV    -35.29mA   -76.57mA   -13.08mA
-939mV    -20.51mA   -59.1mA    -4.36mA
-893mV    -9.259mA   -42.73mA   -1.63mA
-847mV    -3.161mA   -28.03mA   -1.105mA
-801mV    -1.173mA   -15.86mA   -912.6uA
-755mV    -669uA     -7.327mA   -762.3uA
-709mV    -488.1uA   -2.784mA   -622.8uA
-640mV    -320.8uA   -621.9uA   -429.5uA
-525mV    -114.3uA   -99.72uA   -163.8uA
1.1V      0A         0A         0A
[POWER_clamp]
|Voltage   I(typ)   I(min)   I(max)
-1.1V     104.8mA    160mA      70.36mA
-1.039V   71.02mA    125.1mA    38.37mA
-993mV    47.41mA    99.76mA    18.16mA
-970mV    36.61mA    87.48mA    10.56mA
-947mV    26.77mA    75.56mA    5.326mA
-901mV    11.35mA    53.11mA    1.208mA
-855mV    3.329mA    33.33mA    538.3uA
-809mV    890.1uA    17.63mA    399uA
-763mV    354.9uA    7.445mA    322.9uA
-717mV    219.7uA    2.582mA    258.1uA
-556mV    65.25uA    87.48uA    81.64uA
1.1V      0A         0A         0A
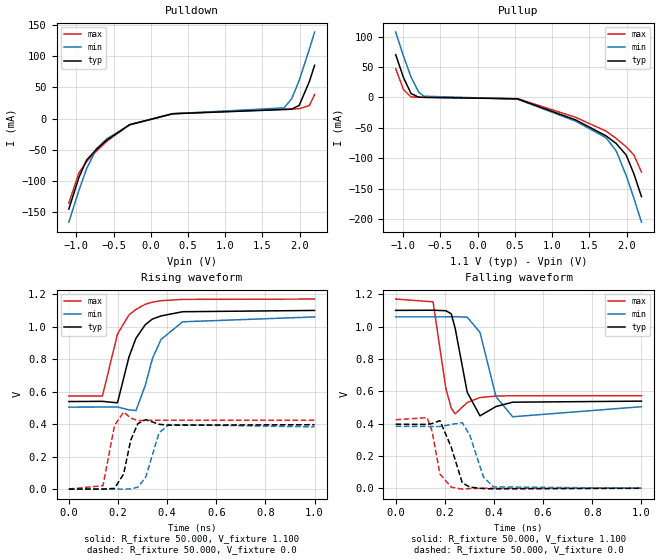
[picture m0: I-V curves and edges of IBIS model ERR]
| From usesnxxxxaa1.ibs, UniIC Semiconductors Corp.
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|   Model ERR
[Model] ERR
Model_type Output
Polarity   Non-Inverting
Vmeas =  0.300V
Rref =  50.000
Vref =  0.300V
C_comp   1.110pF   1.087pF   1.118pF
[Temperature Range]   25.000   0.125k   -40.000
[Voltage Range]   1.100V   1.060V   1.170V
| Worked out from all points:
|   slope of the pulldown table from 0 to 0.165 V, typ, clamps not added: 34.3 ohm
|   rising waveform, R_fixture 50.000, V_fixture 1.100: 20-80 % time 76.9ps typ, 80.7ps min, 76.1ps max; typ from 0.539 V to 1.1 V
|   rising waveform, R_fixture 50.000, V_fixture 0.0: 20-80 % time 34.2ps typ, 42.2ps min, 26.6ps max; typ from 0 V to 0.396 V
|   falling waveform, R_fixture 50.000, V_fixture 1.100: 20-80 % time 39.5ps typ, 51.4ps min, 30.3ps max; typ from 1.1 V to 0.539 V
|   falling waveform, R_fixture 50.000, V_fixture 0.0: 20-80 % time 39.4ps typ, 48.3ps min, 31.2ps max; typ from 0.396 V to 0 V
[Pulldown]
|Voltage   I(typ)   I(min)   I(max)
-1.1V     -144.6mA   -165.6mA   -134.9mA
-964mV    -93.98mA   -114.7mA   -86.67mA
-862mV    -66.35mA   -80.23mA   -68.71mA
-726mV    -48.63mA   -47.69mA   -51.65mA
-590mV    -34.31mA   -32.32mA   -36.11mA
-284mV    -9.75mA    -9.891mA   -9.528mA
294mV     7.853mA    7.917mA    7.879mA
1.79V     14.61mA    17.27mA    15.19mA
1.892V    15.08mA    31.78mA    15.46mA
1.994V    21.32mA    61.5mA     15.76mA
2.13V     59.42mA    111.1mA    21.05mA
2.2V      85.39mA    138.5mA    38.51mA
[Pullup]
|Voltage   I(typ)   I(min)   I(max)
-1.1V     70.35mA    107.3mA    47.41mA
-996mV    32.86mA    68.02mA    13.11mA
-894mV    6.579mA    33.56mA    850.6uA
-792mV    492.9uA    8.95mA     367.4uA
-724mV    224.8uA    2.136mA    267.5uA
534mV     -2.207mA   -2.664mA   -1.828mA
1.316V    -36.76mA   -38.82mA   -32.49mA
1.724V    -62.93mA   -66.01mA   -55.09mA
1.86V     -75.39mA   -87.46mA   -67.11mA
1.996V    -94.62mA   -128.3mA   -81.03mA
2.098V    -125.2mA   -165.1mA   -94.2mA
2.2V      -162.6mA   -204.6mA   -122.4mA
[Ramp]
| variable   typ   min   max
dV/dt_r   0.238/34.205p   0.230/44.058p   0.254/26.879p
dV/dt_f   0.337/40.097p   0.333/51.984p   0.359/30.470p
R_load = 50.000
[Rising Waveform]
R_fixture= 50.000
V_fixture= 1.100
V_fixture_min= 1.060
V_fixture_max= 1.170
|time   V(typ)   V(min)   V(max)
0s        538.9mV    504.5mV    572.5mV
137ps     540.2mV    505.1mV    573.3mV
198ps     531mV      505.7mV    954.9mV
245ps     814.7mV    487.4mV    1.073V
273ps     928.1mV    483.5mV    1.106V
311ps     1.012V     637.3mV    1.138V
340ps     1.047V     802.9mV    1.151V
375ps     1.066V     920.7mV    1.16V
463ps     1.092V     1.03V      1.168V
1ns       1.1V       1.06V      1.17V
[Rising Waveform]
R_fixture= 50.000
V_fixture= 0.0
V_fixture_min= 0.0
V_fixture_max= 0.0
|time   V(typ)   V(min)   V(max)
0s        1.764uV    14.27uV    330.5nV
139ps     -39.12uV   2.016uV    20.91mV
186ps     4.2mV      18.06uV    391.2mV
223ps     92.51mV    -600.2uV   474.3mV
252ps     301.6mV    1.192mV    437.6mV
281ps     403.2mV    11.53mV    421.3mV
313ps     427.4mV    73.36mV    423.1mV
367ps     398.9mV    345.4mV    423.7mV
407ps     393.4mV    396.8mV    423.7mV
1ns       396.3mV    383.1mV    423.7mV
[Falling Waveform]
R_fixture= 50.000
V_fixture= 1.100
V_fixture_min= 1.060
V_fixture_max= 1.170
|time   V(typ)   V(min)   V(max)
0s        1.1V       1.06V      1.17V
152ps     1.101V     1.06V      1.153V
204ps     1.098V     1.06V      618.2mV
226ps     1.079V     1.061V     495.6mV
242ps     989.3mV    1.061V     460.5mV
291ps     593.7mV    1.058V     530.2mV
343ps     447.9mV    964.1mV    561.3mV
408ps     505.4mV    566.4mV    570.2mV
476ps     532.3mV    442.2mV    572mV
1ns       538.8mV    504.5mV    572.5mV
[Falling Waveform]
R_fixture= 50.000
V_fixture= 0.0
V_fixture_min= 0.0
V_fixture_max= 0.0
|time   V(typ)   V(min)   V(max)
0s        396.3mV    383.1mV    423.7mV
128ps     394.7mV    382.7mV    436.7mV
148ps     400.1mV    381.8mV    353.5mV
180ps     418.2mV    381.3mV    88.91mV
226ps     254.5mV    394.9mV    6.791mV
271ps     33.25mV    405.4mV    -5.525mV
302ps     7.059mV    326.9mV    -1.691mV
357ps     -2.039mV   69.62mV    -140.1uV
398ps     -3.841mV   8.587mV    -19.95uV
1ns       1.873uV    15.43uV    -4.527uV
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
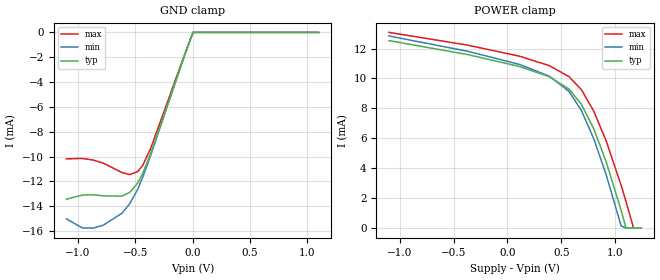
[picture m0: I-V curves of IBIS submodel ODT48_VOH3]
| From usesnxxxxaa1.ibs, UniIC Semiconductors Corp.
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|   Submodel ODT48_VOH3
[Submodel] ODT48_VOH3
Submodel_type Dynamic_clamp
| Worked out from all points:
|   GND clamp passes 1 mA (typ) near -0.04 V on its own axis
[GND_clamp]
|Voltage   I(typ)   I(min)   I(max)
-1.1V     -13.43mA   -15.01mA   -10.18mA
-962mV    -13.1mA    -15.74mA   -10.15mA
-870mV    -13.07mA   -15.76mA   -10.27mA
-778mV    -13.16mA   -15.52mA   -10.53mA
-617mV    -13.19mA   -14.57mA   -11.28mA
-548mV    -12.88mA   -13.8mA    -11.45mA
-479mV    -12.14mA   -12.64mA   -11.21mA
-433mV    -11.33mA   -11.63mA   -10.68mA
-364mV    -9.705mA   -9.874mA   -9.312mA
-65mV     -1.725mA   -1.733mA   -1.686mA
4mV       79.17nA    663.9nA    14.11nA
1.1V      0A         0A         0A
[POWER_clamp]
|Voltage   I(typ)   I(min)   I(max)
-1.1V     12.53mA    12.84mA    13.08mA
-372mV    11.6mA     11.82mA    12.23mA
111mV     10.8mA     10.94mA    11.49mA
387mV     10.12mA    10.16mA    10.86mA
571mV     9.29mA     9.133mA    10.12mA
686mV     8.273mA    7.857mA    9.246mA
801mV     6.629mA    5.961mA    7.806mA
916mV     4.422mA    3.558mA    5.82mA
1.054V    1.192mA    157.9uA    2.865mA
1.1V      0A         0A         1.766mA
1.17V     0A         0A         0A
1.24V     0A         0A         0A
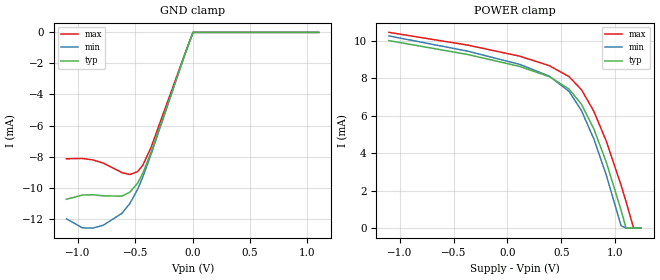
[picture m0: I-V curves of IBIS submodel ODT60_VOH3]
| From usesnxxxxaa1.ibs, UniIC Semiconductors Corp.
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|   Submodel ODT60_VOH3
[Submodel] ODT60_VOH3
Submodel_type Dynamic_clamp
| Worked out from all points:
|   GND clamp passes 1 mA (typ) near -0.05 V on its own axis
[GND_clamp]
|Voltage   I(typ)   I(min)   I(max)
-1.1V     -10.75mA   -12.01mA   -8.142mA
-962mV    -10.48mA   -12.59mA   -8.123mA
-870mV    -10.46mA   -12.61mA   -8.213mA
-778mV    -10.53mA   -12.42mA   -8.421mA
-617mV    -10.55mA   -11.66mA   -9.027mA
-548mV    -10.3mA    -11.04mA   -9.16mA
-479mV    -9.715mA   -10.11mA   -8.969mA
-433mV    -9.063mA   -9.303mA   -8.546mA
-364mV    -7.764mA   -7.899mA   -7.45mA
-65mV     -1.38mA    -1.386mA   -1.349mA
4mV       79.17nA    663.9nA    14.11nA
1.1V      0A         0A         0A
[POWER_clamp]
|Voltage   I(typ)   I(min)   I(max)
-1.1V     10.02mA    10.27mA    10.46mA
-372mV    9.281mA    9.46mA     9.783mA
111mV     8.642mA    8.753mA    9.191mA
387mV     8.094mA    8.127mA    8.684mA
571mV     7.432mA    7.306mA    8.095mA
686mV     6.618mA    6.286mA    7.397mA
801mV     5.303mA    4.769mA    6.245mA
916mV     3.538mA    2.846mA    4.656mA
1.054V    953.7uA    126.2uA    2.292mA
1.1V      0A         0A         1.413mA
1.17V     0A         0A         0A
1.24V     0A         0A         0A
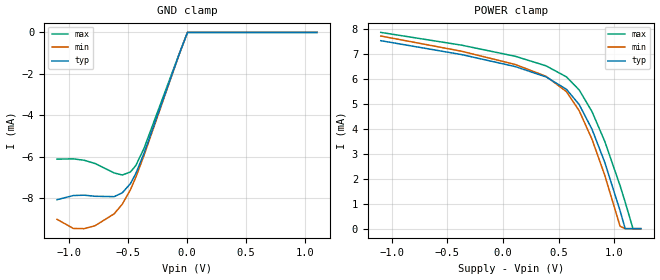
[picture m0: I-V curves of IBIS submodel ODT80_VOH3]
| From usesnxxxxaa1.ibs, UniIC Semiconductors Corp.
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|   Submodel ODT80_VOH3
[Submodel] ODT80_VOH3
Submodel_type Dynamic_clamp
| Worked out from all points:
|   GND clamp passes 1 mA (typ) near -0.06 V on its own axis
[GND_clamp]
|Voltage   I(typ)   I(min)   I(max)
-1.1V     -8.06mA    -9.005mA   -6.106mA
-962mV    -7.859mA   -9.445mA   -6.092mA
-870mV    -7.842mA   -9.455mA   -6.16mA
-778mV    -7.895mA   -9.312mA   -6.316mA
-617mV    -7.913mA   -8.742mA   -6.77mA
-548mV    -7.729mA   -8.277mA   -6.87mA
-479mV    -7.286mA   -7.582mA   -6.726mA
-433mV    -6.797mA   -6.977mA   -6.41mA
-364mV    -5.823mA   -5.925mA   -5.587mA
-65mV     -1.035mA   -1.04mA    -1.012mA
4mV       79.17nA    663.9nA    14.11nA
1.1V      0A         0A         0A
[POWER_clamp]
|Voltage   I(typ)   I(min)   I(max)
-1.1V     7.518mA    7.704mA    7.849mA
-372mV    6.961mA    7.095mA    7.338mA
111mV     6.481mA    6.565mA    6.893mA
387mV     6.07mA     6.095mA    6.513mA
571mV     5.574mA    5.48mA     6.071mA
686mV     4.964mA    4.714mA    5.547mA
801mV     3.977mA    3.577mA    4.683mA
916mV     2.653mA    2.135mA    3.492mA
1.054V    715.2uA    94.47uA    1.719mA
1.1V      0A         0A         1.059mA
1.17V     0A         0A         0A
1.24V     0A         0A         0A
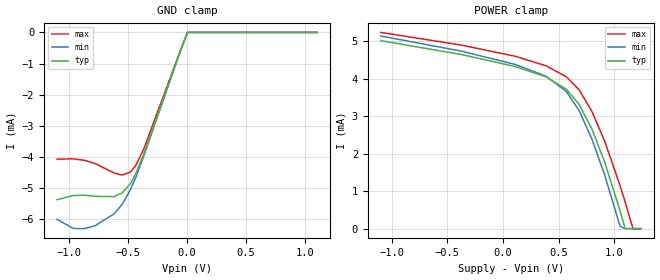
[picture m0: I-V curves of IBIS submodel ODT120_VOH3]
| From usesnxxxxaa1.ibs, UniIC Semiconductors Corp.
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|   Submodel ODT120_VOH3
[Submodel] ODT120_VOH3
Submodel_type Dynamic_clamp
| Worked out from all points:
|   GND clamp passes 1 mA (typ) near -0.09 V on its own axis
[GND_clamp]
|Voltage   I(typ)   I(min)   I(max)
-1.1V     -5.373mA   -6.003mA   -4.071mA
-962mV    -5.239mA   -6.296mA   -4.061mA
-870mV    -5.228mA   -6.303mA   -4.107mA
-778mV    -5.263mA   -6.208mA   -4.21mA
-617mV    -5.275mA   -5.828mA   -4.514mA
-548mV    -5.152mA   -5.518mA   -4.58mA
-479mV    -4.857mA   -5.054mA   -4.484mA
-433mV    -4.531mA   -4.652mA   -4.273mA
-364mV    -3.882mA   -3.95mA    -3.725mA
-65mV     -690.2uA   -693.1uA   -674.4uA
4mV       79.17nA    663.9nA    14.11nA
1.1V      0A         0A         0A
[POWER_clamp]
|Voltage   I(typ)   I(min)   I(max)
-1.1V     5.012mA    5.136mA    5.232mA
-372mV    4.641mA    4.73mA     4.892mA
111mV     4.321mA    4.377mA    4.595mA
387mV     4.047mA    4.064mA    4.342mA
571mV     3.716mA    3.653mA    4.047mA
686mV     3.309mA    3.143mA    3.698mA
801mV     2.652mA    2.384mA    3.122mA
916mV     1.769mA    1.423mA    2.328mA
1.054V    476.8uA    62.77uA    1.146mA
1.1V      0A         0A         706.2uA
1.17V     0A         0A         0A
1.24V     0A         0A         0A
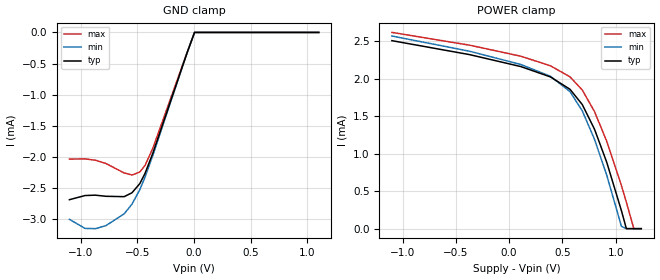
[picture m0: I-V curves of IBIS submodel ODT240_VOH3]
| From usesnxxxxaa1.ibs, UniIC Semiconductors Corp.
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|   Submodel ODT240_VOH3
[Submodel] ODT240_VOH3
Submodel_type Dynamic_clamp
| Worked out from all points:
|   GND clamp passes 1 mA (typ) near -0.19 V on its own axis
[GND_clamp]
|Voltage   I(typ)   I(min)   I(max)
-1.1V     -2.687mA   -3.002mA   -2.035mA
-962mV    -2.62mA    -3.148mA   -2.031mA
-870mV    -2.614mA   -3.152mA   -2.053mA
-778mV    -2.632mA   -3.104mA   -2.105mA
-617mV    -2.638mA   -2.914mA   -2.257mA
-548mV    -2.576mA   -2.759mA   -2.29mA
-479mV    -2.429mA   -2.527mA   -2.242mA
-433mV    -2.266mA   -2.326mA   -2.137mA
-364mV    -1.941mA   -1.975mA   -1.862mA
-65mV     -345.1uA   -346.5uA   -337.2uA
4mV       79.17nA    663.9nA    14.11nA
1.1V      0A         0A         0A
[POWER_clamp]
|Voltage   I(typ)   I(min)   I(max)
-1.1V     2.506mA    2.568mA    2.616mA
-372mV    2.32mA     2.365mA    2.446mA
111mV     2.16mA     2.188mA    2.298mA
387mV     2.023mA    2.032mA    2.171mA
571mV     1.858mA    1.827mA    2.024mA
686mV     1.655mA    1.571mA    1.849mA
801mV     1.326mA    1.192mA    1.561mA
916mV     884.4uA    711.6uA    1.164mA
1.054V    238.4uA    31.07uA    572.9uA
1.1V      0A         0A         353.1uA
1.17V     0A         0A         0A
1.24V     0A         0A         0A
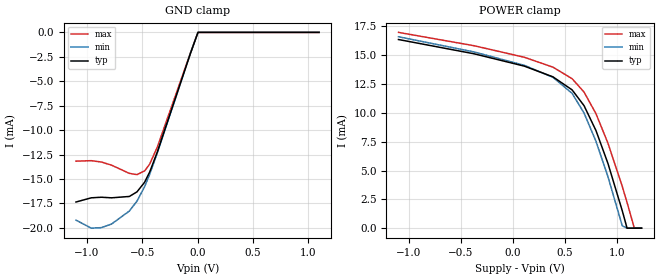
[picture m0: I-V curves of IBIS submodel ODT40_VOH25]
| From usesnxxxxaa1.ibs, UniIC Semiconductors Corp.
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|   Submodel ODT40_VOH25
[Submodel] ODT40_VOH25
Submodel_type Dynamic_clamp
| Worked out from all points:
|   GND clamp passes 1 mA (typ) near -0.03 V on its own axis
[GND_clamp]
|Voltage   I(typ)   I(min)   I(max)
-1.1V     -17.35mA   -19.2mA    -13.17mA
-962mV    -16.92mA   -20.02mA   -13.12mA
-870mV    -16.86mA   -19.97mA   -13.26mA
-778mV    -16.92mA   -19.6mA    -13.58mA
-617mV    -16.78mA   -18.27mA   -14.42mA
-548mV    -16.31mA   -17.26mA   -14.55mA
-479mV    -15.33mA   -15.78mA   -14.17mA
-433mV    -14.28mA   -14.52mA   -13.47mA
-364mV    -12.23mA   -12.33mA   -11.73mA
-65mV     -2.178mA   -2.166mA   -2.126mA
4mV       79.17nA    663.9nA    14.11nA
1.1V      0A         0A         0A
[POWER_clamp]
|Voltage   I(typ)   I(min)   I(max)
-1.1V     16.37mA    16.61mA    16.99mA
-372mV    15.13mA    15.29mA    15.83mA
111mV     14.06mA    14.13mA    14.83mA
387mV     13.13mA    13.09mA    13.97mA
571mV     12mA       11.7mA     12.97mA
686mV     10.63mA    9.991mA    11.81mA
801mV     8.464mA    7.531mA    9.93mA
916mV     5.619mA    4.473mA    7.38mA
1.054V    1.507mA    197.7uA    3.622mA
1.1V      0A         0A         2.23mA
1.17V     0A         0A         0A
1.24V     0A         0A         0A
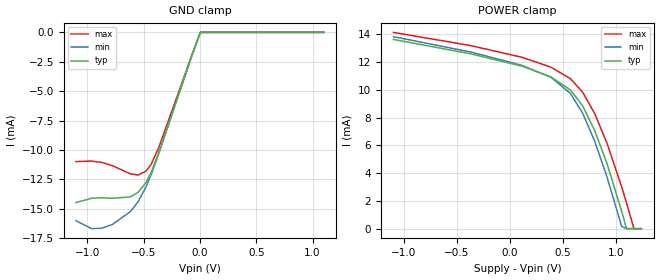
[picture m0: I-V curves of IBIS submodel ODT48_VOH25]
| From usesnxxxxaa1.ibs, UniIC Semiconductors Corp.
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|   Submodel ODT48_VOH25
[Submodel] ODT48_VOH25
Submodel_type Dynamic_clamp
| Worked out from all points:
|   GND clamp passes 1 mA (typ) near -0.04 V on its own axis
[GND_clamp]
|Voltage   I(typ)   I(min)   I(max)
-1.1V     -14.46mA   -16mA      -10.98mA
-962mV    -14.1mA    -16.68mA   -10.94mA
-870mV    -14.05mA   -16.64mA   -11.05mA
-778mV    -14.1mA    -16.33mA   -11.32mA
-617mV    -13.98mA   -15.23mA   -12.02mA
-548mV    -13.59mA   -14.38mA   -12.12mA
-479mV    -12.77mA   -13.15mA   -11.8mA
-433mV    -11.9mA    -12.1mA    -11.22mA
-364mV    -10.19mA   -10.27mA   -9.771mA
-65mV     -1.815mA   -1.805mA   -1.772mA
4mV       79.17nA    663.9nA    14.11nA
1.1V      0A         0A         0A
[POWER_clamp]
|Voltage   I(typ)   I(min)   I(max)
-1.1V     13.64mA    13.84mA    14.15mA
-372mV    12.61mA    12.74mA    13.2mA
111mV     11.72mA    11.78mA    12.36mA
387mV     10.94mA    10.91mA    11.64mA
571mV     10mA       9.747mA    10.81mA
686mV     8.855mA    8.326mA    9.841mA
801mV     7.054mA    6.276mA    8.275mA
916mV     4.682mA    3.727mA    6.15mA
1.054V    1.256mA    164.6uA    3.018mA
1.1V      0A         0A         1.859mA
1.17V     0A         0A         0A
1.24V     0A         0A         0A
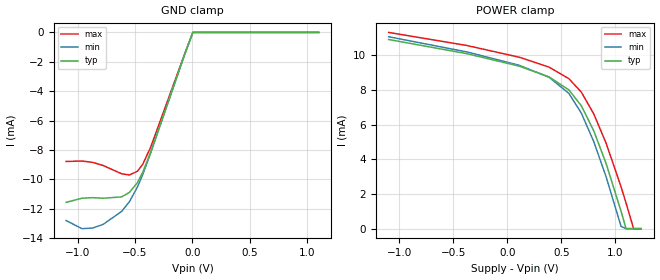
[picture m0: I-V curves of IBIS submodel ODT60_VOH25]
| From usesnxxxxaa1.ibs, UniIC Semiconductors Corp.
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|   Submodel ODT60_VOH25
[Submodel] ODT60_VOH25
Submodel_type Dynamic_clamp
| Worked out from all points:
|   GND clamp passes 1 mA (typ) near -0.04 V on its own axis
[GND_clamp]
|Voltage   I(typ)   I(min)   I(max)
-1.1V     -11.56mA   -12.8mA    -8.78mA
-962mV    -11.28mA   -13.35mA   -8.749mA
-870mV    -11.24mA   -13.31mA   -8.84mA
-778mV    -11.28mA   -13.06mA   -9.052mA
-617mV    -11.19mA   -12.18mA   -9.616mA
-548mV    -10.88mA   -11.51mA   -9.697mA
-479mV    -10.22mA   -10.52mA   -9.444mA
-433mV    -9.52mA    -9.679mA   -8.979mA
-364mV    -8.151mA   -8.217mA   -7.817mA
-65mV     -1.452mA   -1.444mA   -1.417mA
4mV       79.17nA    663.9nA    14.11nA
1.1V      0A         0A         0A
[POWER_clamp]
|Voltage   I(typ)   I(min)   I(max)
-1.1V     10.91mA    11.07mA    11.32mA
-372mV    10.09mA    10.19mA    10.56mA
111mV     9.372mA    9.422mA    9.887mA
387mV     8.753mA    8.729mA    9.314mA
571mV     8mA        7.798mA    8.648mA
686mV     7.084mA    6.66mA     7.873mA
801mV     5.643mA    5.021mA    6.62mA
916mV     3.746mA    2.982mA    4.92mA
1.054V    1.005mA    131.6uA    2.414mA
1.1V      0A         0A         1.487mA
1.17V     0A         0A         0A
1.24V     0A         0A         0A
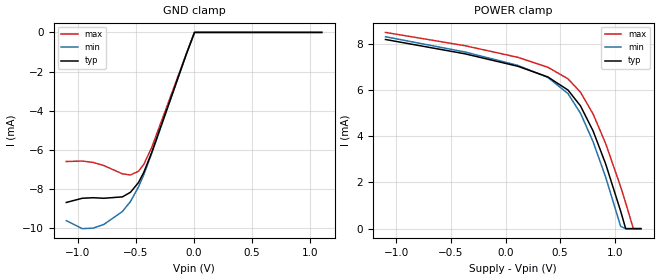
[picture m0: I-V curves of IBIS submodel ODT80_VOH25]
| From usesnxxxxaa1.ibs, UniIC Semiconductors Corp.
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|   Submodel ODT80_VOH25
[Submodel] ODT80_VOH25
Submodel_type Dynamic_clamp
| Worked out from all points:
|   GND clamp passes 1 mA (typ) near -0.06 V on its own axis
[GND_clamp]
|Voltage   I(typ)   I(min)   I(max)
-1.1V     -8.673mA   -9.601mA   -6.585mA
-962mV    -8.459mA   -10.01mA   -6.562mA
-870mV    -8.431mA   -9.985mA   -6.63mA
-778mV    -8.46mA    -9.799mA   -6.789mA
-617mV    -8.389mA   -9.137mA   -7.212mA
-548mV    -8.157mA   -8.63mA    -7.273mA
-479mV    -7.664mA   -7.892mA   -7.083mA
-433mV    -7.14mA    -7.259mA   -6.734mA
-364mV    -6.114mA   -6.163mA   -5.863mA
-65mV     -1.089mA   -1.083mA   -1.063mA
4mV       79.17nA    663.9nA    14.11nA
1.1V      0A         0A         0A
[POWER_clamp]
|Voltage   I(typ)   I(min)   I(max)
-1.1V     8.186mA    8.305mA    8.493mA
-372mV    7.566mA    7.645mA    7.917mA
111mV     7.029mA    7.067mA    7.415mA
387mV     6.565mA    6.546mA    6.985mA
571mV     6mA        5.848mA    6.486mA
686mV     5.313mA    4.995mA    5.905mA
801mV     4.232mA    3.766mA    4.965mA
916mV     2.809mA    2.236mA    3.69mA
1.054V    753.7uA    98.53uA    1.811mA
1.1V      0A         0A         1.115mA
1.17V     0A         0A         0A
1.24V     0A         0A         0A
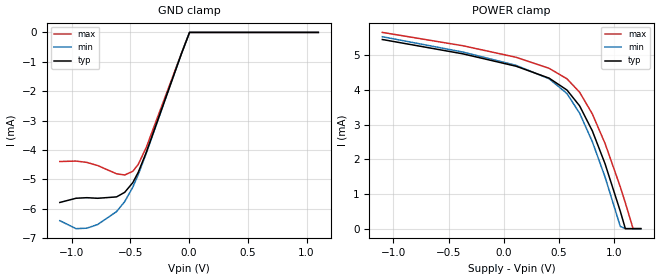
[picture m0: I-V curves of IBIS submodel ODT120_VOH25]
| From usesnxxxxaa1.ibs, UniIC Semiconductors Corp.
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|   Submodel ODT120_VOH25
[Submodel] ODT120_VOH25
Submodel_type Dynamic_clamp
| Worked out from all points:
|   GND clamp passes 1 mA (typ) near -0.09 V on its own axis
[GND_clamp]
|Voltage   I(typ)   I(min)   I(max)
-1.1V     -5.782mA   -6.401mA   -4.39mA
-962mV    -5.639mA   -6.673mA   -4.375mA
-870mV    -5.62mA    -6.657mA   -4.42mA
-778mV    -5.64mA    -6.533mA   -4.526mA
-617mV    -5.593mA   -6.092mA   -4.808mA
-548mV    -5.438mA   -5.754mA   -4.848mA
-479mV    -5.109mA   -5.262mA   -4.722mA
-433mV    -4.76mA    -4.84mA    -4.49mA
-364mV    -4.076mA   -4.108mA   -3.909mA
-65mV     -725.9uA   -722.1uA   -708.7uA
4mV       79.17nA    663.9nA    14.11nA
1.1V      0A         0A         0A
[POWER_clamp]
|Voltage   I(typ)   I(min)   I(max)
-1.1V     5.457mA    5.537mA    5.662mA
-372mV    5.044mA    5.096mA    5.278mA
111mV     4.686mA    4.711mA    4.944mA
410mV     4.342mA    4.324mA    4.625mA
571mV     4mA        3.899mA    4.324mA
686mV     3.542mA    3.33mA     3.936mA
801mV     2.821mA    2.51mA     3.31mA
916mV     1.873mA    1.491mA    2.46mA
1.054V    502.5uA    65.48uA    1.207mA
1.1V      0A         0A         743.4uA
1.17V     0A         0A         0A
1.24V     0A         0A         0A
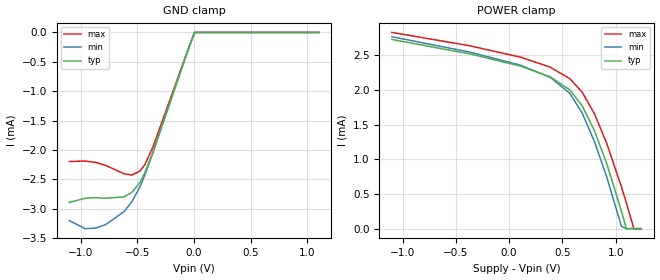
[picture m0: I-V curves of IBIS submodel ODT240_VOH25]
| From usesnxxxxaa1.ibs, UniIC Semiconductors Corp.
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|   Submodel ODT240_VOH25
[Submodel] ODT240_VOH25
Submodel_type Dynamic_clamp
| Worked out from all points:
|   GND clamp passes 1 mA (typ) near -0.18 V on its own axis
[GND_clamp]
|Voltage   I(typ)   I(min)   I(max)
-1.1V     -2.891mA   -3.2mA     -2.195mA
-962mV    -2.82mA    -3.337mA   -2.187mA
-870mV    -2.81mA    -3.328mA   -2.21mA
-778mV    -2.82mA    -3.266mA   -2.263mA
-617mV    -2.796mA   -3.046mA   -2.404mA
-548mV    -2.719mA   -2.877mA   -2.424mA
-479mV    -2.555mA   -2.631mA   -2.361mA
-433mV    -2.38mA    -2.42mA    -2.245mA
-364mV    -2.038mA   -2.054mA   -1.954mA
-65mV     -363uA     -361.1uA   -354.4uA
4mV       79.17nA    663.9nA    14.11nA
1.1V      0A         0A         0A
[POWER_clamp]
|Voltage   I(typ)   I(min)   I(max)
-1.1V     2.729mA    2.768mA    2.831mA
-372mV    2.522mA    2.548mA    2.639mA
111mV     2.343mA    2.356mA    2.472mA
387mV     2.188mA    2.182mA    2.328mA
571mV     2mA        1.95mA     2.162mA
686mV     1.771mA    1.665mA    1.968mA
801mV     1.411mA    1.255mA    1.655mA
916mV     936.4uA    745.4uA    1.23mA
1.054V    251.2uA    32.42uA    603.6uA
1.1V      0A         0A         371.7uA
1.17V     0A         0A         0A
1.24V     0A         0A         0A
